VERSION 5.8 ;
BUSBITCHARS "[]" ;
DIVIDERCHAR "/" ;
UNITS
    DATABASE MICRONS 1000 ;
END UNITS

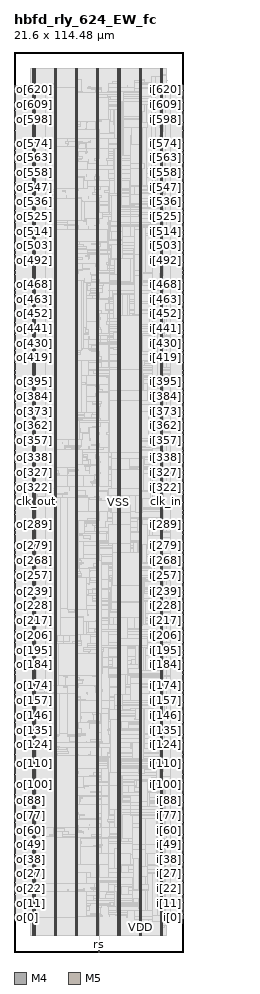
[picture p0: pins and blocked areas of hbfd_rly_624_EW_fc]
MACRO hbfd_rly_624_EW_fc
  FOREIGN hbfd_rly_624_EW_fc 0 0 ;
  CLASS BLOCK ;
  SIZE 21.6 BY 114.48 ;
  PIN clk_in
    DIRECTION INPUT ;
    USE SIGNAL ;
    PORT
      LAYER M4 ;
        RECT  21.408 57.264 21.6 57.288 ;
    END
  END clk_in
  PIN clk_out
    DIRECTION OUTPUT ;
    USE SIGNAL ;
    PORT
      LAYER M4 ;
        RECT  0 57.264 0.192 57.288 ;
    END
  END clk_out
  PIN i[0]
    DIRECTION INPUT ;
    USE SIGNAL ;
    PORT
      LAYER M4 ;
        RECT  21.408 4.32 21.6 4.344 ;
    END
  END i[0]
  PIN i[100]
    DIRECTION INPUT ;
    USE SIGNAL ;
    PORT
      LAYER M4 ;
        RECT  21.408 21.312 21.6 21.336 ;
    END
  END i[100]
  PIN i[101]
    DIRECTION INPUT ;
    USE SIGNAL ;
    PORT
      LAYER M4 ;
        RECT  21.408 21.456 21.6 21.48 ;
    END
  END i[101]
  PIN i[102]
    DIRECTION INPUT ;
    USE SIGNAL ;
    PORT
      LAYER M4 ;
        RECT  21.408 21.648 21.6 21.672 ;
    END
  END i[102]
  PIN i[103]
    DIRECTION INPUT ;
    USE SIGNAL ;
    PORT
      LAYER M4 ;
        RECT  21.408 21.792 21.6 21.816 ;
    END
  END i[103]
  PIN i[104]
    DIRECTION INPUT ;
    USE SIGNAL ;
    PORT
      LAYER M4 ;
        RECT  21.408 21.984 21.6 22.008 ;
    END
  END i[104]
  PIN i[105]
    DIRECTION INPUT ;
    USE SIGNAL ;
    PORT
      LAYER M4 ;
        RECT  21.408 22.128 21.6 22.152 ;
    END
  END i[105]
  PIN i[106]
    DIRECTION INPUT ;
    USE SIGNAL ;
    PORT
      LAYER M4 ;
        RECT  21.408 22.32 21.6 22.344 ;
    END
  END i[106]
  PIN i[107]
    DIRECTION INPUT ;
    USE SIGNAL ;
    PORT
      LAYER M4 ;
        RECT  21.408 22.464 21.6 22.488 ;
    END
  END i[107]
  PIN i[108]
    DIRECTION INPUT ;
    USE SIGNAL ;
    PORT
      LAYER M4 ;
        RECT  21.408 22.656 21.6 22.68 ;
    END
  END i[108]
  PIN i[109]
    DIRECTION INPUT ;
    USE SIGNAL ;
    PORT
      LAYER M4 ;
        RECT  21.408 22.8 21.6 22.824 ;
    END
  END i[109]
  PIN i[10]
    DIRECTION INPUT ;
    USE SIGNAL ;
    PORT
      LAYER M4 ;
        RECT  21.408 6.048 21.6 6.072 ;
    END
  END i[10]
  PIN i[110]
    DIRECTION INPUT ;
    USE SIGNAL ;
    PORT
      LAYER M4 ;
        RECT  21.408 22.992 21.6 23.016 ;
    END
  END i[110]
  PIN i[111]
    DIRECTION INPUT ;
    USE SIGNAL ;
    PORT
      LAYER M4 ;
        RECT  21.408 23.136 21.6 23.16 ;
    END
  END i[111]
  PIN i[112]
    DIRECTION INPUT ;
    USE SIGNAL ;
    PORT
      LAYER M4 ;
        RECT  21.408 23.328 21.6 23.352 ;
    END
  END i[112]
  PIN i[113]
    DIRECTION INPUT ;
    USE SIGNAL ;
    PORT
      LAYER M4 ;
        RECT  21.408 23.52 21.6 23.544 ;
    END
  END i[113]
  PIN i[114]
    DIRECTION INPUT ;
    USE SIGNAL ;
    PORT
      LAYER M4 ;
        RECT  21.408 23.664 21.6 23.688 ;
    END
  END i[114]
  PIN i[115]
    DIRECTION INPUT ;
    USE SIGNAL ;
    PORT
      LAYER M4 ;
        RECT  21.408 23.856 21.6 23.88 ;
    END
  END i[115]
  PIN i[116]
    DIRECTION INPUT ;
    USE SIGNAL ;
    PORT
      LAYER M4 ;
        RECT  21.408 24 21.6 24.024 ;
    END
  END i[116]
  PIN i[117]
    DIRECTION INPUT ;
    USE SIGNAL ;
    PORT
      LAYER M4 ;
        RECT  21.408 24.192 21.6 24.216 ;
    END
  END i[117]
  PIN i[118]
    DIRECTION INPUT ;
    USE SIGNAL ;
    PORT
      LAYER M4 ;
        RECT  21.408 24.336 21.6 24.36 ;
    END
  END i[118]
  PIN i[119]
    DIRECTION INPUT ;
    USE SIGNAL ;
    PORT
      LAYER M4 ;
        RECT  21.408 24.528 21.6 24.552 ;
    END
  END i[119]
  PIN i[11]
    DIRECTION INPUT ;
    USE SIGNAL ;
    PORT
      LAYER M4 ;
        RECT  21.408 6.192 21.6 6.216 ;
    END
  END i[11]
  PIN i[120]
    DIRECTION INPUT ;
    USE SIGNAL ;
    PORT
      LAYER M4 ;
        RECT  21.408 24.672 21.6 24.696 ;
    END
  END i[120]
  PIN i[121]
    DIRECTION INPUT ;
    USE SIGNAL ;
    PORT
      LAYER M4 ;
        RECT  21.408 24.864 21.6 24.888 ;
    END
  END i[121]
  PIN i[122]
    DIRECTION INPUT ;
    USE SIGNAL ;
    PORT
      LAYER M4 ;
        RECT  21.408 25.008 21.6 25.032 ;
    END
  END i[122]
  PIN i[123]
    DIRECTION INPUT ;
    USE SIGNAL ;
    PORT
      LAYER M4 ;
        RECT  21.408 25.2 21.6 25.224 ;
    END
  END i[123]
  PIN i[124]
    DIRECTION INPUT ;
    USE SIGNAL ;
    PORT
      LAYER M4 ;
        RECT  21.408 25.344 21.6 25.368 ;
    END
  END i[124]
  PIN i[125]
    DIRECTION INPUT ;
    USE SIGNAL ;
    PORT
      LAYER M4 ;
        RECT  21.408 25.536 21.6 25.56 ;
    END
  END i[125]
  PIN i[126]
    DIRECTION INPUT ;
    USE SIGNAL ;
    PORT
      LAYER M4 ;
        RECT  21.408 25.68 21.6 25.704 ;
    END
  END i[126]
  PIN i[127]
    DIRECTION INPUT ;
    USE SIGNAL ;
    PORT
      LAYER M4 ;
        RECT  21.408 25.872 21.6 25.896 ;
    END
  END i[127]
  PIN i[128]
    DIRECTION INPUT ;
    USE SIGNAL ;
    PORT
      LAYER M4 ;
        RECT  21.408 26.064 21.6 26.088 ;
    END
  END i[128]
  PIN i[129]
    DIRECTION INPUT ;
    USE SIGNAL ;
    PORT
      LAYER M4 ;
        RECT  21.408 26.208 21.6 26.232 ;
    END
  END i[129]
  PIN i[12]
    DIRECTION INPUT ;
    USE SIGNAL ;
    PORT
      LAYER M4 ;
        RECT  21.408 6.384 21.6 6.408 ;
    END
  END i[12]
  PIN i[130]
    DIRECTION INPUT ;
    USE SIGNAL ;
    PORT
      LAYER M4 ;
        RECT  21.408 26.4 21.6 26.424 ;
    END
  END i[130]
  PIN i[131]
    DIRECTION INPUT ;
    USE SIGNAL ;
    PORT
      LAYER M4 ;
        RECT  21.408 26.544 21.6 26.568 ;
    END
  END i[131]
  PIN i[132]
    DIRECTION INPUT ;
    USE SIGNAL ;
    PORT
      LAYER M4 ;
        RECT  21.408 26.736 21.6 26.76 ;
    END
  END i[132]
  PIN i[133]
    DIRECTION INPUT ;
    USE SIGNAL ;
    PORT
      LAYER M4 ;
        RECT  21.408 26.88 21.6 26.904 ;
    END
  END i[133]
  PIN i[134]
    DIRECTION INPUT ;
    USE SIGNAL ;
    PORT
      LAYER M4 ;
        RECT  21.408 27.072 21.6 27.096 ;
    END
  END i[134]
  PIN i[135]
    DIRECTION INPUT ;
    USE SIGNAL ;
    PORT
      LAYER M4 ;
        RECT  21.408 27.216 21.6 27.24 ;
    END
  END i[135]
  PIN i[136]
    DIRECTION INPUT ;
    USE SIGNAL ;
    PORT
      LAYER M4 ;
        RECT  21.408 27.408 21.6 27.432 ;
    END
  END i[136]
  PIN i[137]
    DIRECTION INPUT ;
    USE SIGNAL ;
    PORT
      LAYER M4 ;
        RECT  21.408 27.552 21.6 27.576 ;
    END
  END i[137]
  PIN i[138]
    DIRECTION INPUT ;
    USE SIGNAL ;
    PORT
      LAYER M4 ;
        RECT  21.408 27.744 21.6 27.768 ;
    END
  END i[138]
  PIN i[139]
    DIRECTION INPUT ;
    USE SIGNAL ;
    PORT
      LAYER M4 ;
        RECT  21.408 27.888 21.6 27.912 ;
    END
  END i[139]
  PIN i[13]
    DIRECTION INPUT ;
    USE SIGNAL ;
    PORT
      LAYER M4 ;
        RECT  21.408 6.528 21.6 6.552 ;
    END
  END i[13]
  PIN i[140]
    DIRECTION INPUT ;
    USE SIGNAL ;
    PORT
      LAYER M4 ;
        RECT  21.408 28.08 21.6 28.104 ;
    END
  END i[140]
  PIN i[141]
    DIRECTION INPUT ;
    USE SIGNAL ;
    PORT
      LAYER M4 ;
        RECT  21.408 28.224 21.6 28.248 ;
    END
  END i[141]
  PIN i[142]
    DIRECTION INPUT ;
    USE SIGNAL ;
    PORT
      LAYER M4 ;
        RECT  21.408 28.416 21.6 28.44 ;
    END
  END i[142]
  PIN i[143]
    DIRECTION INPUT ;
    USE SIGNAL ;
    PORT
      LAYER M4 ;
        RECT  21.408 28.608 21.6 28.632 ;
    END
  END i[143]
  PIN i[144]
    DIRECTION INPUT ;
    USE SIGNAL ;
    PORT
      LAYER M4 ;
        RECT  21.408 28.752 21.6 28.776 ;
    END
  END i[144]
  PIN i[145]
    DIRECTION INPUT ;
    USE SIGNAL ;
    PORT
      LAYER M4 ;
        RECT  21.408 28.944 21.6 28.968 ;
    END
  END i[145]
  PIN i[146]
    DIRECTION INPUT ;
    USE SIGNAL ;
    PORT
      LAYER M4 ;
        RECT  21.408 29.088 21.6 29.112 ;
    END
  END i[146]
  PIN i[147]
    DIRECTION INPUT ;
    USE SIGNAL ;
    PORT
      LAYER M4 ;
        RECT  21.408 29.28 21.6 29.304 ;
    END
  END i[147]
  PIN i[148]
    DIRECTION INPUT ;
    USE SIGNAL ;
    PORT
      LAYER M4 ;
        RECT  21.408 29.424 21.6 29.448 ;
    END
  END i[148]
  PIN i[149]
    DIRECTION INPUT ;
    USE SIGNAL ;
    PORT
      LAYER M4 ;
        RECT  21.408 29.616 21.6 29.64 ;
    END
  END i[149]
  PIN i[14]
    DIRECTION INPUT ;
    USE SIGNAL ;
    PORT
      LAYER M4 ;
        RECT  21.408 6.72 21.6 6.744 ;
    END
  END i[14]
  PIN i[150]
    DIRECTION INPUT ;
    USE SIGNAL ;
    PORT
      LAYER M4 ;
        RECT  21.408 29.76 21.6 29.784 ;
    END
  END i[150]
  PIN i[151]
    DIRECTION INPUT ;
    USE SIGNAL ;
    PORT
      LAYER M4 ;
        RECT  21.408 29.952 21.6 29.976 ;
    END
  END i[151]
  PIN i[152]
    DIRECTION INPUT ;
    USE SIGNAL ;
    PORT
      LAYER M4 ;
        RECT  21.408 30.096 21.6 30.12 ;
    END
  END i[152]
  PIN i[153]
    DIRECTION INPUT ;
    USE SIGNAL ;
    PORT
      LAYER M4 ;
        RECT  21.408 30.288 21.6 30.312 ;
    END
  END i[153]
  PIN i[154]
    DIRECTION INPUT ;
    USE SIGNAL ;
    PORT
      LAYER M4 ;
        RECT  21.408 30.432 21.6 30.456 ;
    END
  END i[154]
  PIN i[155]
    DIRECTION INPUT ;
    USE SIGNAL ;
    PORT
      LAYER M4 ;
        RECT  21.408 30.624 21.6 30.648 ;
    END
  END i[155]
  PIN i[156]
    DIRECTION INPUT ;
    USE SIGNAL ;
    PORT
      LAYER M4 ;
        RECT  21.408 30.768 21.6 30.792 ;
    END
  END i[156]
  PIN i[157]
    DIRECTION INPUT ;
    USE SIGNAL ;
    PORT
      LAYER M4 ;
        RECT  21.408 30.96 21.6 30.984 ;
    END
  END i[157]
  PIN i[158]
    DIRECTION INPUT ;
    USE SIGNAL ;
    PORT
      LAYER M4 ;
        RECT  21.408 31.152 21.6 31.176 ;
    END
  END i[158]
  PIN i[159]
    DIRECTION INPUT ;
    USE SIGNAL ;
    PORT
      LAYER M4 ;
        RECT  21.408 31.296 21.6 31.32 ;
    END
  END i[159]
  PIN i[15]
    DIRECTION INPUT ;
    USE SIGNAL ;
    PORT
      LAYER M4 ;
        RECT  21.408 6.864 21.6 6.888 ;
    END
  END i[15]
  PIN i[160]
    DIRECTION INPUT ;
    USE SIGNAL ;
    PORT
      LAYER M4 ;
        RECT  21.408 31.488 21.6 31.512 ;
    END
  END i[160]
  PIN i[161]
    DIRECTION INPUT ;
    USE SIGNAL ;
    PORT
      LAYER M4 ;
        RECT  21.408 31.632 21.6 31.656 ;
    END
  END i[161]
  PIN i[162]
    DIRECTION INPUT ;
    USE SIGNAL ;
    PORT
      LAYER M4 ;
        RECT  21.408 31.824 21.6 31.848 ;
    END
  END i[162]
  PIN i[163]
    DIRECTION INPUT ;
    USE SIGNAL ;
    PORT
      LAYER M4 ;
        RECT  21.408 31.968 21.6 31.992 ;
    END
  END i[163]
  PIN i[164]
    DIRECTION INPUT ;
    USE SIGNAL ;
    PORT
      LAYER M4 ;
        RECT  21.408 32.16 21.6 32.184 ;
    END
  END i[164]
  PIN i[165]
    DIRECTION INPUT ;
    USE SIGNAL ;
    PORT
      LAYER M4 ;
        RECT  21.408 32.304 21.6 32.328 ;
    END
  END i[165]
  PIN i[166]
    DIRECTION INPUT ;
    USE SIGNAL ;
    PORT
      LAYER M4 ;
        RECT  21.408 32.496 21.6 32.52 ;
    END
  END i[166]
  PIN i[167]
    DIRECTION INPUT ;
    USE SIGNAL ;
    PORT
      LAYER M4 ;
        RECT  21.408 32.64 21.6 32.664 ;
    END
  END i[167]
  PIN i[168]
    DIRECTION INPUT ;
    USE SIGNAL ;
    PORT
      LAYER M4 ;
        RECT  21.408 32.832 21.6 32.856 ;
    END
  END i[168]
  PIN i[169]
    DIRECTION INPUT ;
    USE SIGNAL ;
    PORT
      LAYER M4 ;
        RECT  21.408 32.976 21.6 33 ;
    END
  END i[169]
  PIN i[16]
    DIRECTION INPUT ;
    USE SIGNAL ;
    PORT
      LAYER M4 ;
        RECT  21.408 7.056 21.6 7.08 ;
    END
  END i[16]
  PIN i[170]
    DIRECTION INPUT ;
    USE SIGNAL ;
    PORT
      LAYER M4 ;
        RECT  21.408 33.168 21.6 33.192 ;
    END
  END i[170]
  PIN i[171]
    DIRECTION INPUT ;
    USE SIGNAL ;
    PORT
      LAYER M4 ;
        RECT  21.408 33.36 21.6 33.384 ;
    END
  END i[171]
  PIN i[172]
    DIRECTION INPUT ;
    USE SIGNAL ;
    PORT
      LAYER M4 ;
        RECT  21.408 33.504 21.6 33.528 ;
    END
  END i[172]
  PIN i[173]
    DIRECTION INPUT ;
    USE SIGNAL ;
    PORT
      LAYER M4 ;
        RECT  21.408 33.696 21.6 33.72 ;
    END
  END i[173]
  PIN i[174]
    DIRECTION INPUT ;
    USE SIGNAL ;
    PORT
      LAYER M4 ;
        RECT  21.408 33.84 21.6 33.864 ;
    END
  END i[174]
  PIN i[175]
    DIRECTION INPUT ;
    USE SIGNAL ;
    PORT
      LAYER M4 ;
        RECT  21.408 34.032 21.6 34.056 ;
    END
  END i[175]
  PIN i[176]
    DIRECTION INPUT ;
    USE SIGNAL ;
    PORT
      LAYER M4 ;
        RECT  21.408 34.176 21.6 34.2 ;
    END
  END i[176]
  PIN i[177]
    DIRECTION INPUT ;
    USE SIGNAL ;
    PORT
      LAYER M4 ;
        RECT  21.408 34.368 21.6 34.392 ;
    END
  END i[177]
  PIN i[178]
    DIRECTION INPUT ;
    USE SIGNAL ;
    PORT
      LAYER M4 ;
        RECT  21.408 34.512 21.6 34.536 ;
    END
  END i[178]
  PIN i[179]
    DIRECTION INPUT ;
    USE SIGNAL ;
    PORT
      LAYER M4 ;
        RECT  21.408 34.704 21.6 34.728 ;
    END
  END i[179]
  PIN i[17]
    DIRECTION INPUT ;
    USE SIGNAL ;
    PORT
      LAYER M4 ;
        RECT  21.408 7.2 21.6 7.224 ;
    END
  END i[17]
  PIN i[180]
    DIRECTION INPUT ;
    USE SIGNAL ;
    PORT
      LAYER M4 ;
        RECT  21.408 34.848 21.6 34.872 ;
    END
  END i[180]
  PIN i[181]
    DIRECTION INPUT ;
    USE SIGNAL ;
    PORT
      LAYER M4 ;
        RECT  21.408 35.04 21.6 35.064 ;
    END
  END i[181]
  PIN i[182]
    DIRECTION INPUT ;
    USE SIGNAL ;
    PORT
      LAYER M4 ;
        RECT  21.408 35.184 21.6 35.208 ;
    END
  END i[182]
  PIN i[183]
    DIRECTION INPUT ;
    USE SIGNAL ;
    PORT
      LAYER M4 ;
        RECT  21.408 35.376 21.6 35.4 ;
    END
  END i[183]
  PIN i[184]
    DIRECTION INPUT ;
    USE SIGNAL ;
    PORT
      LAYER M4 ;
        RECT  21.408 35.52 21.6 35.544 ;
    END
  END i[184]
  PIN i[185]
    DIRECTION INPUT ;
    USE SIGNAL ;
    PORT
      LAYER M4 ;
        RECT  21.408 35.712 21.6 35.736 ;
    END
  END i[185]
  PIN i[186]
    DIRECTION INPUT ;
    USE SIGNAL ;
    PORT
      LAYER M4 ;
        RECT  21.408 35.904 21.6 35.928 ;
    END
  END i[186]
  PIN i[187]
    DIRECTION INPUT ;
    USE SIGNAL ;
    PORT
      LAYER M4 ;
        RECT  21.408 36.048 21.6 36.072 ;
    END
  END i[187]
  PIN i[188]
    DIRECTION INPUT ;
    USE SIGNAL ;
    PORT
      LAYER M4 ;
        RECT  21.408 36.24 21.6 36.264 ;
    END
  END i[188]
  PIN i[189]
    DIRECTION INPUT ;
    USE SIGNAL ;
    PORT
      LAYER M4 ;
        RECT  21.408 36.384 21.6 36.408 ;
    END
  END i[189]
  PIN i[18]
    DIRECTION INPUT ;
    USE SIGNAL ;
    PORT
      LAYER M4 ;
        RECT  21.408 7.392 21.6 7.416 ;
    END
  END i[18]
  PIN i[190]
    DIRECTION INPUT ;
    USE SIGNAL ;
    PORT
      LAYER M4 ;
        RECT  21.408 36.576 21.6 36.6 ;
    END
  END i[190]
  PIN i[191]
    DIRECTION INPUT ;
    USE SIGNAL ;
    PORT
      LAYER M4 ;
        RECT  21.408 36.72 21.6 36.744 ;
    END
  END i[191]
  PIN i[192]
    DIRECTION INPUT ;
    USE SIGNAL ;
    PORT
      LAYER M4 ;
        RECT  21.408 36.912 21.6 36.936 ;
    END
  END i[192]
  PIN i[193]
    DIRECTION INPUT ;
    USE SIGNAL ;
    PORT
      LAYER M4 ;
        RECT  21.408 37.056 21.6 37.08 ;
    END
  END i[193]
  PIN i[194]
    DIRECTION INPUT ;
    USE SIGNAL ;
    PORT
      LAYER M4 ;
        RECT  21.408 37.248 21.6 37.272 ;
    END
  END i[194]
  PIN i[195]
    DIRECTION INPUT ;
    USE SIGNAL ;
    PORT
      LAYER M4 ;
        RECT  21.408 37.392 21.6 37.416 ;
    END
  END i[195]
  PIN i[196]
    DIRECTION INPUT ;
    USE SIGNAL ;
    PORT
      LAYER M4 ;
        RECT  21.408 37.584 21.6 37.608 ;
    END
  END i[196]
  PIN i[197]
    DIRECTION INPUT ;
    USE SIGNAL ;
    PORT
      LAYER M4 ;
        RECT  21.408 37.728 21.6 37.752 ;
    END
  END i[197]
  PIN i[198]
    DIRECTION INPUT ;
    USE SIGNAL ;
    PORT
      LAYER M4 ;
        RECT  21.408 37.92 21.6 37.944 ;
    END
  END i[198]
  PIN i[199]
    DIRECTION INPUT ;
    USE SIGNAL ;
    PORT
      LAYER M4 ;
        RECT  21.408 38.064 21.6 38.088 ;
    END
  END i[199]
  PIN i[19]
    DIRECTION INPUT ;
    USE SIGNAL ;
    PORT
      LAYER M4 ;
        RECT  21.408 7.536 21.6 7.56 ;
    END
  END i[19]
  PIN i[1]
    DIRECTION INPUT ;
    USE SIGNAL ;
    PORT
      LAYER M4 ;
        RECT  21.408 4.512 21.6 4.536 ;
    END
  END i[1]
  PIN i[200]
    DIRECTION INPUT ;
    USE SIGNAL ;
    PORT
      LAYER M4 ;
        RECT  21.408 38.256 21.6 38.28 ;
    END
  END i[200]
  PIN i[201]
    DIRECTION INPUT ;
    USE SIGNAL ;
    PORT
      LAYER M4 ;
        RECT  21.408 38.448 21.6 38.472 ;
    END
  END i[201]
  PIN i[202]
    DIRECTION INPUT ;
    USE SIGNAL ;
    PORT
      LAYER M4 ;
        RECT  21.408 38.592 21.6 38.616 ;
    END
  END i[202]
  PIN i[203]
    DIRECTION INPUT ;
    USE SIGNAL ;
    PORT
      LAYER M4 ;
        RECT  21.408 38.784 21.6 38.808 ;
    END
  END i[203]
  PIN i[204]
    DIRECTION INPUT ;
    USE SIGNAL ;
    PORT
      LAYER M4 ;
        RECT  21.408 38.928 21.6 38.952 ;
    END
  END i[204]
  PIN i[205]
    DIRECTION INPUT ;
    USE SIGNAL ;
    PORT
      LAYER M4 ;
        RECT  21.408 39.12 21.6 39.144 ;
    END
  END i[205]
  PIN i[206]
    DIRECTION INPUT ;
    USE SIGNAL ;
    PORT
      LAYER M4 ;
        RECT  21.408 39.264 21.6 39.288 ;
    END
  END i[206]
  PIN i[207]
    DIRECTION INPUT ;
    USE SIGNAL ;
    PORT
      LAYER M4 ;
        RECT  21.408 39.456 21.6 39.48 ;
    END
  END i[207]
  PIN i[208]
    DIRECTION INPUT ;
    USE SIGNAL ;
    PORT
      LAYER M4 ;
        RECT  21.408 39.6 21.6 39.624 ;
    END
  END i[208]
  PIN i[209]
    DIRECTION INPUT ;
    USE SIGNAL ;
    PORT
      LAYER M4 ;
        RECT  21.408 39.792 21.6 39.816 ;
    END
  END i[209]
  PIN i[20]
    DIRECTION INPUT ;
    USE SIGNAL ;
    PORT
      LAYER M4 ;
        RECT  21.408 7.728 21.6 7.752 ;
    END
  END i[20]
  PIN i[210]
    DIRECTION INPUT ;
    USE SIGNAL ;
    PORT
      LAYER M4 ;
        RECT  21.408 39.936 21.6 39.96 ;
    END
  END i[210]
  PIN i[211]
    DIRECTION INPUT ;
    USE SIGNAL ;
    PORT
      LAYER M4 ;
        RECT  21.408 40.128 21.6 40.152 ;
    END
  END i[211]
  PIN i[212]
    DIRECTION INPUT ;
    USE SIGNAL ;
    PORT
      LAYER M4 ;
        RECT  21.408 40.272 21.6 40.296 ;
    END
  END i[212]
  PIN i[213]
    DIRECTION INPUT ;
    USE SIGNAL ;
    PORT
      LAYER M4 ;
        RECT  21.408 40.464 21.6 40.488 ;
    END
  END i[213]
  PIN i[214]
    DIRECTION INPUT ;
    USE SIGNAL ;
    PORT
      LAYER M4 ;
        RECT  21.408 40.608 21.6 40.632 ;
    END
  END i[214]
  PIN i[215]
    DIRECTION INPUT ;
    USE SIGNAL ;
    PORT
      LAYER M4 ;
        RECT  21.408 40.8 21.6 40.824 ;
    END
  END i[215]
  PIN i[216]
    DIRECTION INPUT ;
    USE SIGNAL ;
    PORT
      LAYER M4 ;
        RECT  21.408 40.992 21.6 41.016 ;
    END
  END i[216]
  PIN i[217]
    DIRECTION INPUT ;
    USE SIGNAL ;
    PORT
      LAYER M4 ;
        RECT  21.408 41.136 21.6 41.16 ;
    END
  END i[217]
  PIN i[218]
    DIRECTION INPUT ;
    USE SIGNAL ;
    PORT
      LAYER M4 ;
        RECT  21.408 41.328 21.6 41.352 ;
    END
  END i[218]
  PIN i[219]
    DIRECTION INPUT ;
    USE SIGNAL ;
    PORT
      LAYER M4 ;
        RECT  21.408 41.472 21.6 41.496 ;
    END
  END i[219]
  PIN i[21]
    DIRECTION INPUT ;
    USE SIGNAL ;
    PORT
      LAYER M4 ;
        RECT  21.408 7.872 21.6 7.896 ;
    END
  END i[21]
  PIN i[220]
    DIRECTION INPUT ;
    USE SIGNAL ;
    PORT
      LAYER M4 ;
        RECT  21.408 41.664 21.6 41.688 ;
    END
  END i[220]
  PIN i[221]
    DIRECTION INPUT ;
    USE SIGNAL ;
    PORT
      LAYER M4 ;
        RECT  21.408 41.808 21.6 41.832 ;
    END
  END i[221]
  PIN i[222]
    DIRECTION INPUT ;
    USE SIGNAL ;
    PORT
      LAYER M4 ;
        RECT  21.408 42 21.6 42.024 ;
    END
  END i[222]
  PIN i[223]
    DIRECTION INPUT ;
    USE SIGNAL ;
    PORT
      LAYER M4 ;
        RECT  21.408 42.144 21.6 42.168 ;
    END
  END i[223]
  PIN i[224]
    DIRECTION INPUT ;
    USE SIGNAL ;
    PORT
      LAYER M4 ;
        RECT  21.408 42.336 21.6 42.36 ;
    END
  END i[224]
  PIN i[225]
    DIRECTION INPUT ;
    USE SIGNAL ;
    PORT
      LAYER M4 ;
        RECT  21.408 42.48 21.6 42.504 ;
    END
  END i[225]
  PIN i[226]
    DIRECTION INPUT ;
    USE SIGNAL ;
    PORT
      LAYER M4 ;
        RECT  21.408 42.672 21.6 42.696 ;
    END
  END i[226]
  PIN i[227]
    DIRECTION INPUT ;
    USE SIGNAL ;
    PORT
      LAYER M4 ;
        RECT  21.408 42.816 21.6 42.84 ;
    END
  END i[227]
  PIN i[228]
    DIRECTION INPUT ;
    USE SIGNAL ;
    PORT
      LAYER M4 ;
        RECT  21.408 43.008 21.6 43.032 ;
    END
  END i[228]
  PIN i[229]
    DIRECTION INPUT ;
    USE SIGNAL ;
    PORT
      LAYER M4 ;
        RECT  21.408 43.152 21.6 43.176 ;
    END
  END i[229]
  PIN i[22]
    DIRECTION INPUT ;
    USE SIGNAL ;
    PORT
      LAYER M4 ;
        RECT  21.408 8.064 21.6 8.088 ;
    END
  END i[22]
  PIN i[230]
    DIRECTION INPUT ;
    USE SIGNAL ;
    PORT
      LAYER M4 ;
        RECT  21.408 43.344 21.6 43.368 ;
    END
  END i[230]
  PIN i[231]
    DIRECTION INPUT ;
    USE SIGNAL ;
    PORT
      LAYER M4 ;
        RECT  21.408 43.536 21.6 43.56 ;
    END
  END i[231]
  PIN i[232]
    DIRECTION INPUT ;
    USE SIGNAL ;
    PORT
      LAYER M4 ;
        RECT  21.408 43.68 21.6 43.704 ;
    END
  END i[232]
  PIN i[233]
    DIRECTION INPUT ;
    USE SIGNAL ;
    PORT
      LAYER M4 ;
        RECT  21.408 43.872 21.6 43.896 ;
    END
  END i[233]
  PIN i[234]
    DIRECTION INPUT ;
    USE SIGNAL ;
    PORT
      LAYER M4 ;
        RECT  21.408 44.016 21.6 44.04 ;
    END
  END i[234]
  PIN i[235]
    DIRECTION INPUT ;
    USE SIGNAL ;
    PORT
      LAYER M4 ;
        RECT  21.408 44.208 21.6 44.232 ;
    END
  END i[235]
  PIN i[236]
    DIRECTION INPUT ;
    USE SIGNAL ;
    PORT
      LAYER M4 ;
        RECT  21.408 44.352 21.6 44.376 ;
    END
  END i[236]
  PIN i[237]
    DIRECTION INPUT ;
    USE SIGNAL ;
    PORT
      LAYER M4 ;
        RECT  21.408 44.544 21.6 44.568 ;
    END
  END i[237]
  PIN i[238]
    DIRECTION INPUT ;
    USE SIGNAL ;
    PORT
      LAYER M4 ;
        RECT  21.408 44.688 21.6 44.712 ;
    END
  END i[238]
  PIN i[239]
    DIRECTION INPUT ;
    USE SIGNAL ;
    PORT
      LAYER M4 ;
        RECT  21.408 44.88 21.6 44.904 ;
    END
  END i[239]
  PIN i[23]
    DIRECTION INPUT ;
    USE SIGNAL ;
    PORT
      LAYER M4 ;
        RECT  21.408 8.256 21.6 8.28 ;
    END
  END i[23]
  PIN i[240]
    DIRECTION INPUT ;
    USE SIGNAL ;
    PORT
      LAYER M4 ;
        RECT  21.408 45.024 21.6 45.048 ;
    END
  END i[240]
  PIN i[241]
    DIRECTION INPUT ;
    USE SIGNAL ;
    PORT
      LAYER M4 ;
        RECT  21.408 45.216 21.6 45.24 ;
    END
  END i[241]
  PIN i[242]
    DIRECTION INPUT ;
    USE SIGNAL ;
    PORT
      LAYER M4 ;
        RECT  21.408 45.36 21.6 45.384 ;
    END
  END i[242]
  PIN i[243]
    DIRECTION INPUT ;
    USE SIGNAL ;
    PORT
      LAYER M4 ;
        RECT  21.408 45.552 21.6 45.576 ;
    END
  END i[243]
  PIN i[244]
    DIRECTION INPUT ;
    USE SIGNAL ;
    PORT
      LAYER M4 ;
        RECT  21.408 45.696 21.6 45.72 ;
    END
  END i[244]
  PIN i[245]
    DIRECTION INPUT ;
    USE SIGNAL ;
    PORT
      LAYER M4 ;
        RECT  21.408 45.888 21.6 45.912 ;
    END
  END i[245]
  PIN i[246]
    DIRECTION INPUT ;
    USE SIGNAL ;
    PORT
      LAYER M4 ;
        RECT  21.408 46.08 21.6 46.104 ;
    END
  END i[246]
  PIN i[247]
    DIRECTION INPUT ;
    USE SIGNAL ;
    PORT
      LAYER M4 ;
        RECT  21.408 46.224 21.6 46.248 ;
    END
  END i[247]
  PIN i[248]
    DIRECTION INPUT ;
    USE SIGNAL ;
    PORT
      LAYER M4 ;
        RECT  21.408 46.416 21.6 46.44 ;
    END
  END i[248]
  PIN i[249]
    DIRECTION INPUT ;
    USE SIGNAL ;
    PORT
      LAYER M4 ;
        RECT  21.408 46.56 21.6 46.584 ;
    END
  END i[249]
  PIN i[24]
    DIRECTION INPUT ;
    USE SIGNAL ;
    PORT
      LAYER M4 ;
        RECT  21.408 8.4 21.6 8.424 ;
    END
  END i[24]
  PIN i[250]
    DIRECTION INPUT ;
    USE SIGNAL ;
    PORT
      LAYER M4 ;
        RECT  21.408 46.752 21.6 46.776 ;
    END
  END i[250]
  PIN i[251]
    DIRECTION INPUT ;
    USE SIGNAL ;
    PORT
      LAYER M4 ;
        RECT  21.408 46.896 21.6 46.92 ;
    END
  END i[251]
  PIN i[252]
    DIRECTION INPUT ;
    USE SIGNAL ;
    PORT
      LAYER M4 ;
        RECT  21.408 47.088 21.6 47.112 ;
    END
  END i[252]
  PIN i[253]
    DIRECTION INPUT ;
    USE SIGNAL ;
    PORT
      LAYER M4 ;
        RECT  21.408 47.232 21.6 47.256 ;
    END
  END i[253]
  PIN i[254]
    DIRECTION INPUT ;
    USE SIGNAL ;
    PORT
      LAYER M4 ;
        RECT  21.408 47.424 21.6 47.448 ;
    END
  END i[254]
  PIN i[255]
    DIRECTION INPUT ;
    USE SIGNAL ;
    PORT
      LAYER M4 ;
        RECT  21.408 47.568 21.6 47.592 ;
    END
  END i[255]
  PIN i[256]
    DIRECTION INPUT ;
    USE SIGNAL ;
    PORT
      LAYER M4 ;
        RECT  21.408 47.76 21.6 47.784 ;
    END
  END i[256]
  PIN i[257]
    DIRECTION INPUT ;
    USE SIGNAL ;
    PORT
      LAYER M4 ;
        RECT  21.408 47.904 21.6 47.928 ;
    END
  END i[257]
  PIN i[258]
    DIRECTION INPUT ;
    USE SIGNAL ;
    PORT
      LAYER M4 ;
        RECT  21.408 48.096 21.6 48.12 ;
    END
  END i[258]
  PIN i[259]
    DIRECTION INPUT ;
    USE SIGNAL ;
    PORT
      LAYER M4 ;
        RECT  21.408 48.24 21.6 48.264 ;
    END
  END i[259]
  PIN i[25]
    DIRECTION INPUT ;
    USE SIGNAL ;
    PORT
      LAYER M4 ;
        RECT  21.408 8.592 21.6 8.616 ;
    END
  END i[25]
  PIN i[260]
    DIRECTION INPUT ;
    USE SIGNAL ;
    PORT
      LAYER M4 ;
        RECT  21.408 48.432 21.6 48.456 ;
    END
  END i[260]
  PIN i[261]
    DIRECTION INPUT ;
    USE SIGNAL ;
    PORT
      LAYER M4 ;
        RECT  21.408 48.624 21.6 48.648 ;
    END
  END i[261]
  PIN i[262]
    DIRECTION INPUT ;
    USE SIGNAL ;
    PORT
      LAYER M4 ;
        RECT  21.408 48.768 21.6 48.792 ;
    END
  END i[262]
  PIN i[263]
    DIRECTION INPUT ;
    USE SIGNAL ;
    PORT
      LAYER M4 ;
        RECT  21.408 48.96 21.6 48.984 ;
    END
  END i[263]
  PIN i[264]
    DIRECTION INPUT ;
    USE SIGNAL ;
    PORT
      LAYER M4 ;
        RECT  21.408 49.104 21.6 49.128 ;
    END
  END i[264]
  PIN i[265]
    DIRECTION INPUT ;
    USE SIGNAL ;
    PORT
      LAYER M4 ;
        RECT  21.408 49.296 21.6 49.32 ;
    END
  END i[265]
  PIN i[266]
    DIRECTION INPUT ;
    USE SIGNAL ;
    PORT
      LAYER M4 ;
        RECT  21.408 49.44 21.6 49.464 ;
    END
  END i[266]
  PIN i[267]
    DIRECTION INPUT ;
    USE SIGNAL ;
    PORT
      LAYER M4 ;
        RECT  21.408 49.632 21.6 49.656 ;
    END
  END i[267]
  PIN i[268]
    DIRECTION INPUT ;
    USE SIGNAL ;
    PORT
      LAYER M4 ;
        RECT  21.408 49.776 21.6 49.8 ;
    END
  END i[268]
  PIN i[269]
    DIRECTION INPUT ;
    USE SIGNAL ;
    PORT
      LAYER M4 ;
        RECT  21.408 49.968 21.6 49.992 ;
    END
  END i[269]
  PIN i[26]
    DIRECTION INPUT ;
    USE SIGNAL ;
    PORT
      LAYER M4 ;
        RECT  21.408 8.736 21.6 8.76 ;
    END
  END i[26]
  PIN i[270]
    DIRECTION INPUT ;
    USE SIGNAL ;
    PORT
      LAYER M4 ;
        RECT  21.408 50.112 21.6 50.136 ;
    END
  END i[270]
  PIN i[271]
    DIRECTION INPUT ;
    USE SIGNAL ;
    PORT
      LAYER M4 ;
        RECT  21.408 50.304 21.6 50.328 ;
    END
  END i[271]
  PIN i[272]
    DIRECTION INPUT ;
    USE SIGNAL ;
    PORT
      LAYER M4 ;
        RECT  21.408 50.448 21.6 50.472 ;
    END
  END i[272]
  PIN i[273]
    DIRECTION INPUT ;
    USE SIGNAL ;
    PORT
      LAYER M4 ;
        RECT  21.408 50.64 21.6 50.664 ;
    END
  END i[273]
  PIN i[274]
    DIRECTION INPUT ;
    USE SIGNAL ;
    PORT
      LAYER M4 ;
        RECT  21.408 50.784 21.6 50.808 ;
    END
  END i[274]
  PIN i[275]
    DIRECTION INPUT ;
    USE SIGNAL ;
    PORT
      LAYER M4 ;
        RECT  21.408 50.976 21.6 51 ;
    END
  END i[275]
  PIN i[276]
    DIRECTION INPUT ;
    USE SIGNAL ;
    PORT
      LAYER M4 ;
        RECT  21.408 51.168 21.6 51.192 ;
    END
  END i[276]
  PIN i[277]
    DIRECTION INPUT ;
    USE SIGNAL ;
    PORT
      LAYER M4 ;
        RECT  21.408 51.312 21.6 51.336 ;
    END
  END i[277]
  PIN i[278]
    DIRECTION INPUT ;
    USE SIGNAL ;
    PORT
      LAYER M4 ;
        RECT  21.408 51.504 21.6 51.528 ;
    END
  END i[278]
  PIN i[279]
    DIRECTION INPUT ;
    USE SIGNAL ;
    PORT
      LAYER M4 ;
        RECT  21.408 51.648 21.6 51.672 ;
    END
  END i[279]
  PIN i[27]
    DIRECTION INPUT ;
    USE SIGNAL ;
    PORT
      LAYER M4 ;
        RECT  21.408 8.928 21.6 8.952 ;
    END
  END i[27]
  PIN i[280]
    DIRECTION INPUT ;
    USE SIGNAL ;
    PORT
      LAYER M4 ;
        RECT  21.408 51.84 21.6 51.864 ;
    END
  END i[280]
  PIN i[281]
    DIRECTION INPUT ;
    USE SIGNAL ;
    PORT
      LAYER M4 ;
        RECT  21.408 51.984 21.6 52.008 ;
    END
  END i[281]
  PIN i[282]
    DIRECTION INPUT ;
    USE SIGNAL ;
    PORT
      LAYER M4 ;
        RECT  21.408 52.176 21.6 52.2 ;
    END
  END i[282]
  PIN i[283]
    DIRECTION INPUT ;
    USE SIGNAL ;
    PORT
      LAYER M4 ;
        RECT  21.408 52.32 21.6 52.344 ;
    END
  END i[283]
  PIN i[284]
    DIRECTION INPUT ;
    USE SIGNAL ;
    PORT
      LAYER M4 ;
        RECT  21.408 52.512 21.6 52.536 ;
    END
  END i[284]
  PIN i[285]
    DIRECTION INPUT ;
    USE SIGNAL ;
    PORT
      LAYER M4 ;
        RECT  21.408 52.656 21.6 52.68 ;
    END
  END i[285]
  PIN i[286]
    DIRECTION INPUT ;
    USE SIGNAL ;
    PORT
      LAYER M4 ;
        RECT  21.408 52.848 21.6 52.872 ;
    END
  END i[286]
  PIN i[287]
    DIRECTION INPUT ;
    USE SIGNAL ;
    PORT
      LAYER M4 ;
        RECT  21.408 52.992 21.6 53.016 ;
    END
  END i[287]
  PIN i[288]
    DIRECTION INPUT ;
    USE SIGNAL ;
    PORT
      LAYER M4 ;
        RECT  21.408 53.184 21.6 53.208 ;
    END
  END i[288]
  PIN i[289]
    DIRECTION INPUT ;
    USE SIGNAL ;
    PORT
      LAYER M4 ;
        RECT  21.408 53.328 21.6 53.352 ;
    END
  END i[289]
  PIN i[28]
    DIRECTION INPUT ;
    USE SIGNAL ;
    PORT
      LAYER M4 ;
        RECT  21.408 9.072 21.6 9.096 ;
    END
  END i[28]
  PIN i[290]
    DIRECTION INPUT ;
    USE SIGNAL ;
    PORT
      LAYER M4 ;
        RECT  21.408 53.52 21.6 53.544 ;
    END
  END i[290]
  PIN i[291]
    DIRECTION INPUT ;
    USE SIGNAL ;
    PORT
      LAYER M4 ;
        RECT  21.408 53.712 21.6 53.736 ;
    END
  END i[291]
  PIN i[292]
    DIRECTION INPUT ;
    USE SIGNAL ;
    PORT
      LAYER M4 ;
        RECT  21.408 53.856 21.6 53.88 ;
    END
  END i[292]
  PIN i[293]
    DIRECTION INPUT ;
    USE SIGNAL ;
    PORT
      LAYER M4 ;
        RECT  21.408 54.048 21.6 54.072 ;
    END
  END i[293]
  PIN i[294]
    DIRECTION INPUT ;
    USE SIGNAL ;
    PORT
      LAYER M4 ;
        RECT  21.408 54.192 21.6 54.216 ;
    END
  END i[294]
  PIN i[295]
    DIRECTION INPUT ;
    USE SIGNAL ;
    PORT
      LAYER M4 ;
        RECT  21.408 54.384 21.6 54.408 ;
    END
  END i[295]
  PIN i[296]
    DIRECTION INPUT ;
    USE SIGNAL ;
    PORT
      LAYER M4 ;
        RECT  21.408 54.528 21.6 54.552 ;
    END
  END i[296]
  PIN i[297]
    DIRECTION INPUT ;
    USE SIGNAL ;
    PORT
      LAYER M4 ;
        RECT  21.408 54.72 21.6 54.744 ;
    END
  END i[297]
  PIN i[298]
    DIRECTION INPUT ;
    USE SIGNAL ;
    PORT
      LAYER M4 ;
        RECT  21.408 54.864 21.6 54.888 ;
    END
  END i[298]
  PIN i[299]
    DIRECTION INPUT ;
    USE SIGNAL ;
    PORT
      LAYER M4 ;
        RECT  21.408 55.056 21.6 55.08 ;
    END
  END i[299]
  PIN i[29]
    DIRECTION INPUT ;
    USE SIGNAL ;
    PORT
      LAYER M4 ;
        RECT  21.408 9.264 21.6 9.288 ;
    END
  END i[29]
  PIN i[2]
    DIRECTION INPUT ;
    USE SIGNAL ;
    PORT
      LAYER M4 ;
        RECT  21.408 4.656 21.6 4.68 ;
    END
  END i[2]
  PIN i[300]
    DIRECTION INPUT ;
    USE SIGNAL ;
    PORT
      LAYER M4 ;
        RECT  21.408 55.2 21.6 55.224 ;
    END
  END i[300]
  PIN i[301]
    DIRECTION INPUT ;
    USE SIGNAL ;
    PORT
      LAYER M4 ;
        RECT  21.408 55.392 21.6 55.416 ;
    END
  END i[301]
  PIN i[302]
    DIRECTION INPUT ;
    USE SIGNAL ;
    PORT
      LAYER M4 ;
        RECT  21.408 55.536 21.6 55.56 ;
    END
  END i[302]
  PIN i[303]
    DIRECTION INPUT ;
    USE SIGNAL ;
    PORT
      LAYER M4 ;
        RECT  21.408 55.728 21.6 55.752 ;
    END
  END i[303]
  PIN i[304]
    DIRECTION INPUT ;
    USE SIGNAL ;
    PORT
      LAYER M4 ;
        RECT  21.408 55.872 21.6 55.896 ;
    END
  END i[304]
  PIN i[305]
    DIRECTION INPUT ;
    USE SIGNAL ;
    PORT
      LAYER M4 ;
        RECT  21.408 56.064 21.6 56.088 ;
    END
  END i[305]
  PIN i[306]
    DIRECTION INPUT ;
    USE SIGNAL ;
    PORT
      LAYER M4 ;
        RECT  21.408 56.256 21.6 56.28 ;
    END
  END i[306]
  PIN i[307]
    DIRECTION INPUT ;
    USE SIGNAL ;
    PORT
      LAYER M4 ;
        RECT  21.408 56.4 21.6 56.424 ;
    END
  END i[307]
  PIN i[308]
    DIRECTION INPUT ;
    USE SIGNAL ;
    PORT
      LAYER M4 ;
        RECT  21.408 56.592 21.6 56.616 ;
    END
  END i[308]
  PIN i[309]
    DIRECTION INPUT ;
    USE SIGNAL ;
    PORT
      LAYER M4 ;
        RECT  21.408 56.736 21.6 56.76 ;
    END
  END i[309]
  PIN i[30]
    DIRECTION INPUT ;
    USE SIGNAL ;
    PORT
      LAYER M4 ;
        RECT  21.408 9.408 21.6 9.432 ;
    END
  END i[30]
  PIN i[310]
    DIRECTION INPUT ;
    USE SIGNAL ;
    PORT
      LAYER M4 ;
        RECT  21.408 56.928 21.6 56.952 ;
    END
  END i[310]
  PIN i[311]
    DIRECTION INPUT ;
    USE SIGNAL ;
    PORT
      LAYER M4 ;
        RECT  21.408 57.072 21.6 57.096 ;
    END
  END i[311]
  PIN i[312]
    DIRECTION INPUT ;
    USE SIGNAL ;
    PORT
      LAYER M4 ;
        RECT  21.408 57.408 21.6 57.432 ;
    END
  END i[312]
  PIN i[313]
    DIRECTION INPUT ;
    USE SIGNAL ;
    PORT
      LAYER M4 ;
        RECT  21.408 57.6 21.6 57.624 ;
    END
  END i[313]
  PIN i[314]
    DIRECTION INPUT ;
    USE SIGNAL ;
    PORT
      LAYER M4 ;
        RECT  21.408 57.744 21.6 57.768 ;
    END
  END i[314]
  PIN i[315]
    DIRECTION INPUT ;
    USE SIGNAL ;
    PORT
      LAYER M4 ;
        RECT  21.408 57.936 21.6 57.96 ;
    END
  END i[315]
  PIN i[316]
    DIRECTION INPUT ;
    USE SIGNAL ;
    PORT
      LAYER M4 ;
        RECT  21.408 58.08 21.6 58.104 ;
    END
  END i[316]
  PIN i[317]
    DIRECTION INPUT ;
    USE SIGNAL ;
    PORT
      LAYER M4 ;
        RECT  21.408 58.272 21.6 58.296 ;
    END
  END i[317]
  PIN i[318]
    DIRECTION INPUT ;
    USE SIGNAL ;
    PORT
      LAYER M4 ;
        RECT  21.408 58.416 21.6 58.44 ;
    END
  END i[318]
  PIN i[319]
    DIRECTION INPUT ;
    USE SIGNAL ;
    PORT
      LAYER M4 ;
        RECT  21.408 58.608 21.6 58.632 ;
    END
  END i[319]
  PIN i[31]
    DIRECTION INPUT ;
    USE SIGNAL ;
    PORT
      LAYER M4 ;
        RECT  21.408 9.6 21.6 9.624 ;
    END
  END i[31]
  PIN i[320]
    DIRECTION INPUT ;
    USE SIGNAL ;
    PORT
      LAYER M4 ;
        RECT  21.408 58.8 21.6 58.824 ;
    END
  END i[320]
  PIN i[321]
    DIRECTION INPUT ;
    USE SIGNAL ;
    PORT
      LAYER M4 ;
        RECT  21.408 58.944 21.6 58.968 ;
    END
  END i[321]
  PIN i[322]
    DIRECTION INPUT ;
    USE SIGNAL ;
    PORT
      LAYER M4 ;
        RECT  21.408 59.136 21.6 59.16 ;
    END
  END i[322]
  PIN i[323]
    DIRECTION INPUT ;
    USE SIGNAL ;
    PORT
      LAYER M4 ;
        RECT  21.408 59.28 21.6 59.304 ;
    END
  END i[323]
  PIN i[324]
    DIRECTION INPUT ;
    USE SIGNAL ;
    PORT
      LAYER M4 ;
        RECT  21.408 59.472 21.6 59.496 ;
    END
  END i[324]
  PIN i[325]
    DIRECTION INPUT ;
    USE SIGNAL ;
    PORT
      LAYER M4 ;
        RECT  21.408 59.616 21.6 59.64 ;
    END
  END i[325]
  PIN i[326]
    DIRECTION INPUT ;
    USE SIGNAL ;
    PORT
      LAYER M4 ;
        RECT  21.408 59.808 21.6 59.832 ;
    END
  END i[326]
  PIN i[327]
    DIRECTION INPUT ;
    USE SIGNAL ;
    PORT
      LAYER M4 ;
        RECT  21.408 59.952 21.6 59.976 ;
    END
  END i[327]
  PIN i[328]
    DIRECTION INPUT ;
    USE SIGNAL ;
    PORT
      LAYER M4 ;
        RECT  21.408 60.144 21.6 60.168 ;
    END
  END i[328]
  PIN i[329]
    DIRECTION INPUT ;
    USE SIGNAL ;
    PORT
      LAYER M4 ;
        RECT  21.408 60.288 21.6 60.312 ;
    END
  END i[329]
  PIN i[32]
    DIRECTION INPUT ;
    USE SIGNAL ;
    PORT
      LAYER M4 ;
        RECT  21.408 9.744 21.6 9.768 ;
    END
  END i[32]
  PIN i[330]
    DIRECTION INPUT ;
    USE SIGNAL ;
    PORT
      LAYER M4 ;
        RECT  21.408 60.48 21.6 60.504 ;
    END
  END i[330]
  PIN i[331]
    DIRECTION INPUT ;
    USE SIGNAL ;
    PORT
      LAYER M4 ;
        RECT  21.408 60.624 21.6 60.648 ;
    END
  END i[331]
  PIN i[332]
    DIRECTION INPUT ;
    USE SIGNAL ;
    PORT
      LAYER M4 ;
        RECT  21.408 60.816 21.6 60.84 ;
    END
  END i[332]
  PIN i[333]
    DIRECTION INPUT ;
    USE SIGNAL ;
    PORT
      LAYER M4 ;
        RECT  21.408 60.96 21.6 60.984 ;
    END
  END i[333]
  PIN i[334]
    DIRECTION INPUT ;
    USE SIGNAL ;
    PORT
      LAYER M4 ;
        RECT  21.408 61.152 21.6 61.176 ;
    END
  END i[334]
  PIN i[335]
    DIRECTION INPUT ;
    USE SIGNAL ;
    PORT
      LAYER M4 ;
        RECT  21.408 61.344 21.6 61.368 ;
    END
  END i[335]
  PIN i[336]
    DIRECTION INPUT ;
    USE SIGNAL ;
    PORT
      LAYER M4 ;
        RECT  21.408 61.488 21.6 61.512 ;
    END
  END i[336]
  PIN i[337]
    DIRECTION INPUT ;
    USE SIGNAL ;
    PORT
      LAYER M4 ;
        RECT  21.408 61.68 21.6 61.704 ;
    END
  END i[337]
  PIN i[338]
    DIRECTION INPUT ;
    USE SIGNAL ;
    PORT
      LAYER M4 ;
        RECT  21.408 61.824 21.6 61.848 ;
    END
  END i[338]
  PIN i[339]
    DIRECTION INPUT ;
    USE SIGNAL ;
    PORT
      LAYER M4 ;
        RECT  21.408 62.016 21.6 62.04 ;
    END
  END i[339]
  PIN i[33]
    DIRECTION INPUT ;
    USE SIGNAL ;
    PORT
      LAYER M4 ;
        RECT  21.408 9.936 21.6 9.96 ;
    END
  END i[33]
  PIN i[340]
    DIRECTION INPUT ;
    USE SIGNAL ;
    PORT
      LAYER M4 ;
        RECT  21.408 62.16 21.6 62.184 ;
    END
  END i[340]
  PIN i[341]
    DIRECTION INPUT ;
    USE SIGNAL ;
    PORT
      LAYER M4 ;
        RECT  21.408 62.352 21.6 62.376 ;
    END
  END i[341]
  PIN i[342]
    DIRECTION INPUT ;
    USE SIGNAL ;
    PORT
      LAYER M4 ;
        RECT  21.408 62.496 21.6 62.52 ;
    END
  END i[342]
  PIN i[343]
    DIRECTION INPUT ;
    USE SIGNAL ;
    PORT
      LAYER M4 ;
        RECT  21.408 62.688 21.6 62.712 ;
    END
  END i[343]
  PIN i[344]
    DIRECTION INPUT ;
    USE SIGNAL ;
    PORT
      LAYER M4 ;
        RECT  21.408 62.832 21.6 62.856 ;
    END
  END i[344]
  PIN i[345]
    DIRECTION INPUT ;
    USE SIGNAL ;
    PORT
      LAYER M4 ;
        RECT  21.408 63.024 21.6 63.048 ;
    END
  END i[345]
  PIN i[346]
    DIRECTION INPUT ;
    USE SIGNAL ;
    PORT
      LAYER M4 ;
        RECT  21.408 63.168 21.6 63.192 ;
    END
  END i[346]
  PIN i[347]
    DIRECTION INPUT ;
    USE SIGNAL ;
    PORT
      LAYER M4 ;
        RECT  21.408 63.36 21.6 63.384 ;
    END
  END i[347]
  PIN i[348]
    DIRECTION INPUT ;
    USE SIGNAL ;
    PORT
      LAYER M4 ;
        RECT  21.408 63.504 21.6 63.528 ;
    END
  END i[348]
  PIN i[349]
    DIRECTION INPUT ;
    USE SIGNAL ;
    PORT
      LAYER M4 ;
        RECT  21.408 63.696 21.6 63.72 ;
    END
  END i[349]
  PIN i[34]
    DIRECTION INPUT ;
    USE SIGNAL ;
    PORT
      LAYER M4 ;
        RECT  21.408 10.08 21.6 10.104 ;
    END
  END i[34]
  PIN i[350]
    DIRECTION INPUT ;
    USE SIGNAL ;
    PORT
      LAYER M4 ;
        RECT  21.408 63.888 21.6 63.912 ;
    END
  END i[350]
  PIN i[351]
    DIRECTION INPUT ;
    USE SIGNAL ;
    PORT
      LAYER M4 ;
        RECT  21.408 64.032 21.6 64.056 ;
    END
  END i[351]
  PIN i[352]
    DIRECTION INPUT ;
    USE SIGNAL ;
    PORT
      LAYER M4 ;
        RECT  21.408 64.224 21.6 64.248 ;
    END
  END i[352]
  PIN i[353]
    DIRECTION INPUT ;
    USE SIGNAL ;
    PORT
      LAYER M4 ;
        RECT  21.408 64.368 21.6 64.392 ;
    END
  END i[353]
  PIN i[354]
    DIRECTION INPUT ;
    USE SIGNAL ;
    PORT
      LAYER M4 ;
        RECT  21.408 64.56 21.6 64.584 ;
    END
  END i[354]
  PIN i[355]
    DIRECTION INPUT ;
    USE SIGNAL ;
    PORT
      LAYER M4 ;
        RECT  21.408 64.704 21.6 64.728 ;
    END
  END i[355]
  PIN i[356]
    DIRECTION INPUT ;
    USE SIGNAL ;
    PORT
      LAYER M4 ;
        RECT  21.408 64.896 21.6 64.92 ;
    END
  END i[356]
  PIN i[357]
    DIRECTION INPUT ;
    USE SIGNAL ;
    PORT
      LAYER M4 ;
        RECT  21.408 65.04 21.6 65.064 ;
    END
  END i[357]
  PIN i[358]
    DIRECTION INPUT ;
    USE SIGNAL ;
    PORT
      LAYER M4 ;
        RECT  21.408 65.232 21.6 65.256 ;
    END
  END i[358]
  PIN i[359]
    DIRECTION INPUT ;
    USE SIGNAL ;
    PORT
      LAYER M4 ;
        RECT  21.408 65.376 21.6 65.4 ;
    END
  END i[359]
  PIN i[35]
    DIRECTION INPUT ;
    USE SIGNAL ;
    PORT
      LAYER M4 ;
        RECT  21.408 10.272 21.6 10.296 ;
    END
  END i[35]
  PIN i[360]
    DIRECTION INPUT ;
    USE SIGNAL ;
    PORT
      LAYER M4 ;
        RECT  21.408 65.568 21.6 65.592 ;
    END
  END i[360]
  PIN i[361]
    DIRECTION INPUT ;
    USE SIGNAL ;
    PORT
      LAYER M4 ;
        RECT  21.408 65.712 21.6 65.736 ;
    END
  END i[361]
  PIN i[362]
    DIRECTION INPUT ;
    USE SIGNAL ;
    PORT
      LAYER M4 ;
        RECT  21.408 65.904 21.6 65.928 ;
    END
  END i[362]
  PIN i[363]
    DIRECTION INPUT ;
    USE SIGNAL ;
    PORT
      LAYER M4 ;
        RECT  21.408 66.096 21.6 66.12 ;
    END
  END i[363]
  PIN i[364]
    DIRECTION INPUT ;
    USE SIGNAL ;
    PORT
      LAYER M4 ;
        RECT  21.408 66.24 21.6 66.264 ;
    END
  END i[364]
  PIN i[365]
    DIRECTION INPUT ;
    USE SIGNAL ;
    PORT
      LAYER M4 ;
        RECT  21.408 66.432 21.6 66.456 ;
    END
  END i[365]
  PIN i[366]
    DIRECTION INPUT ;
    USE SIGNAL ;
    PORT
      LAYER M4 ;
        RECT  21.408 66.576 21.6 66.6 ;
    END
  END i[366]
  PIN i[367]
    DIRECTION INPUT ;
    USE SIGNAL ;
    PORT
      LAYER M4 ;
        RECT  21.408 66.768 21.6 66.792 ;
    END
  END i[367]
  PIN i[368]
    DIRECTION INPUT ;
    USE SIGNAL ;
    PORT
      LAYER M4 ;
        RECT  21.408 66.912 21.6 66.936 ;
    END
  END i[368]
  PIN i[369]
    DIRECTION INPUT ;
    USE SIGNAL ;
    PORT
      LAYER M4 ;
        RECT  21.408 67.104 21.6 67.128 ;
    END
  END i[369]
  PIN i[36]
    DIRECTION INPUT ;
    USE SIGNAL ;
    PORT
      LAYER M4 ;
        RECT  21.408 10.416 21.6 10.44 ;
    END
  END i[36]
  PIN i[370]
    DIRECTION INPUT ;
    USE SIGNAL ;
    PORT
      LAYER M4 ;
        RECT  21.408 67.248 21.6 67.272 ;
    END
  END i[370]
  PIN i[371]
    DIRECTION INPUT ;
    USE SIGNAL ;
    PORT
      LAYER M4 ;
        RECT  21.408 67.44 21.6 67.464 ;
    END
  END i[371]
  PIN i[372]
    DIRECTION INPUT ;
    USE SIGNAL ;
    PORT
      LAYER M4 ;
        RECT  21.408 67.584 21.6 67.608 ;
    END
  END i[372]
  PIN i[373]
    DIRECTION INPUT ;
    USE SIGNAL ;
    PORT
      LAYER M4 ;
        RECT  21.408 67.776 21.6 67.8 ;
    END
  END i[373]
  PIN i[374]
    DIRECTION INPUT ;
    USE SIGNAL ;
    PORT
      LAYER M4 ;
        RECT  21.408 67.92 21.6 67.944 ;
    END
  END i[374]
  PIN i[375]
    DIRECTION INPUT ;
    USE SIGNAL ;
    PORT
      LAYER M4 ;
        RECT  21.408 68.112 21.6 68.136 ;
    END
  END i[375]
  PIN i[376]
    DIRECTION INPUT ;
    USE SIGNAL ;
    PORT
      LAYER M4 ;
        RECT  21.408 68.256 21.6 68.28 ;
    END
  END i[376]
  PIN i[377]
    DIRECTION INPUT ;
    USE SIGNAL ;
    PORT
      LAYER M4 ;
        RECT  21.408 68.448 21.6 68.472 ;
    END
  END i[377]
  PIN i[378]
    DIRECTION INPUT ;
    USE SIGNAL ;
    PORT
      LAYER M4 ;
        RECT  21.408 68.64 21.6 68.664 ;
    END
  END i[378]
  PIN i[379]
    DIRECTION INPUT ;
    USE SIGNAL ;
    PORT
      LAYER M4 ;
        RECT  21.408 68.784 21.6 68.808 ;
    END
  END i[379]
  PIN i[37]
    DIRECTION INPUT ;
    USE SIGNAL ;
    PORT
      LAYER M4 ;
        RECT  21.408 10.608 21.6 10.632 ;
    END
  END i[37]
  PIN i[380]
    DIRECTION INPUT ;
    USE SIGNAL ;
    PORT
      LAYER M4 ;
        RECT  21.408 68.976 21.6 69 ;
    END
  END i[380]
  PIN i[381]
    DIRECTION INPUT ;
    USE SIGNAL ;
    PORT
      LAYER M4 ;
        RECT  21.408 69.12 21.6 69.144 ;
    END
  END i[381]
  PIN i[382]
    DIRECTION INPUT ;
    USE SIGNAL ;
    PORT
      LAYER M4 ;
        RECT  21.408 69.312 21.6 69.336 ;
    END
  END i[382]
  PIN i[383]
    DIRECTION INPUT ;
    USE SIGNAL ;
    PORT
      LAYER M4 ;
        RECT  21.408 69.456 21.6 69.48 ;
    END
  END i[383]
  PIN i[384]
    DIRECTION INPUT ;
    USE SIGNAL ;
    PORT
      LAYER M4 ;
        RECT  21.408 69.648 21.6 69.672 ;
    END
  END i[384]
  PIN i[385]
    DIRECTION INPUT ;
    USE SIGNAL ;
    PORT
      LAYER M4 ;
        RECT  21.408 69.792 21.6 69.816 ;
    END
  END i[385]
  PIN i[386]
    DIRECTION INPUT ;
    USE SIGNAL ;
    PORT
      LAYER M4 ;
        RECT  21.408 69.984 21.6 70.008 ;
    END
  END i[386]
  PIN i[387]
    DIRECTION INPUT ;
    USE SIGNAL ;
    PORT
      LAYER M4 ;
        RECT  21.408 70.128 21.6 70.152 ;
    END
  END i[387]
  PIN i[388]
    DIRECTION INPUT ;
    USE SIGNAL ;
    PORT
      LAYER M4 ;
        RECT  21.408 70.32 21.6 70.344 ;
    END
  END i[388]
  PIN i[389]
    DIRECTION INPUT ;
    USE SIGNAL ;
    PORT
      LAYER M4 ;
        RECT  21.408 70.464 21.6 70.488 ;
    END
  END i[389]
  PIN i[38]
    DIRECTION INPUT ;
    USE SIGNAL ;
    PORT
      LAYER M4 ;
        RECT  21.408 10.8 21.6 10.824 ;
    END
  END i[38]
  PIN i[390]
    DIRECTION INPUT ;
    USE SIGNAL ;
    PORT
      LAYER M4 ;
        RECT  21.408 70.656 21.6 70.68 ;
    END
  END i[390]
  PIN i[391]
    DIRECTION INPUT ;
    USE SIGNAL ;
    PORT
      LAYER M4 ;
        RECT  21.408 70.8 21.6 70.824 ;
    END
  END i[391]
  PIN i[392]
    DIRECTION INPUT ;
    USE SIGNAL ;
    PORT
      LAYER M4 ;
        RECT  21.408 70.992 21.6 71.016 ;
    END
  END i[392]
  PIN i[393]
    DIRECTION INPUT ;
    USE SIGNAL ;
    PORT
      LAYER M4 ;
        RECT  21.408 71.184 21.6 71.208 ;
    END
  END i[393]
  PIN i[394]
    DIRECTION INPUT ;
    USE SIGNAL ;
    PORT
      LAYER M4 ;
        RECT  21.408 71.328 21.6 71.352 ;
    END
  END i[394]
  PIN i[395]
    DIRECTION INPUT ;
    USE SIGNAL ;
    PORT
      LAYER M4 ;
        RECT  21.408 71.52 21.6 71.544 ;
    END
  END i[395]
  PIN i[396]
    DIRECTION INPUT ;
    USE SIGNAL ;
    PORT
      LAYER M4 ;
        RECT  21.408 71.664 21.6 71.688 ;
    END
  END i[396]
  PIN i[397]
    DIRECTION INPUT ;
    USE SIGNAL ;
    PORT
      LAYER M4 ;
        RECT  21.408 71.856 21.6 71.88 ;
    END
  END i[397]
  PIN i[398]
    DIRECTION INPUT ;
    USE SIGNAL ;
    PORT
      LAYER M4 ;
        RECT  21.408 72 21.6 72.024 ;
    END
  END i[398]
  PIN i[399]
    DIRECTION INPUT ;
    USE SIGNAL ;
    PORT
      LAYER M4 ;
        RECT  21.408 72.192 21.6 72.216 ;
    END
  END i[399]
  PIN i[39]
    DIRECTION INPUT ;
    USE SIGNAL ;
    PORT
      LAYER M4 ;
        RECT  21.408 10.944 21.6 10.968 ;
    END
  END i[39]
  PIN i[3]
    DIRECTION INPUT ;
    USE SIGNAL ;
    PORT
      LAYER M4 ;
        RECT  21.408 4.848 21.6 4.872 ;
    END
  END i[3]
  PIN i[400]
    DIRECTION INPUT ;
    USE SIGNAL ;
    PORT
      LAYER M4 ;
        RECT  21.408 72.336 21.6 72.36 ;
    END
  END i[400]
  PIN i[401]
    DIRECTION INPUT ;
    USE SIGNAL ;
    PORT
      LAYER M4 ;
        RECT  21.408 72.528 21.6 72.552 ;
    END
  END i[401]
  PIN i[402]
    DIRECTION INPUT ;
    USE SIGNAL ;
    PORT
      LAYER M4 ;
        RECT  21.408 72.672 21.6 72.696 ;
    END
  END i[402]
  PIN i[403]
    DIRECTION INPUT ;
    USE SIGNAL ;
    PORT
      LAYER M4 ;
        RECT  21.408 72.864 21.6 72.888 ;
    END
  END i[403]
  PIN i[404]
    DIRECTION INPUT ;
    USE SIGNAL ;
    PORT
      LAYER M4 ;
        RECT  21.408 73.008 21.6 73.032 ;
    END
  END i[404]
  PIN i[405]
    DIRECTION INPUT ;
    USE SIGNAL ;
    PORT
      LAYER M4 ;
        RECT  21.408 73.2 21.6 73.224 ;
    END
  END i[405]
  PIN i[406]
    DIRECTION INPUT ;
    USE SIGNAL ;
    PORT
      LAYER M4 ;
        RECT  21.408 73.344 21.6 73.368 ;
    END
  END i[406]
  PIN i[407]
    DIRECTION INPUT ;
    USE SIGNAL ;
    PORT
      LAYER M4 ;
        RECT  21.408 73.536 21.6 73.56 ;
    END
  END i[407]
  PIN i[408]
    DIRECTION INPUT ;
    USE SIGNAL ;
    PORT
      LAYER M4 ;
        RECT  21.408 73.728 21.6 73.752 ;
    END
  END i[408]
  PIN i[409]
    DIRECTION INPUT ;
    USE SIGNAL ;
    PORT
      LAYER M4 ;
        RECT  21.408 73.872 21.6 73.896 ;
    END
  END i[409]
  PIN i[40]
    DIRECTION INPUT ;
    USE SIGNAL ;
    PORT
      LAYER M4 ;
        RECT  21.408 11.136 21.6 11.16 ;
    END
  END i[40]
  PIN i[410]
    DIRECTION INPUT ;
    USE SIGNAL ;
    PORT
      LAYER M4 ;
        RECT  21.408 74.064 21.6 74.088 ;
    END
  END i[410]
  PIN i[411]
    DIRECTION INPUT ;
    USE SIGNAL ;
    PORT
      LAYER M4 ;
        RECT  21.408 74.208 21.6 74.232 ;
    END
  END i[411]
  PIN i[412]
    DIRECTION INPUT ;
    USE SIGNAL ;
    PORT
      LAYER M4 ;
        RECT  21.408 74.4 21.6 74.424 ;
    END
  END i[412]
  PIN i[413]
    DIRECTION INPUT ;
    USE SIGNAL ;
    PORT
      LAYER M4 ;
        RECT  21.408 74.544 21.6 74.568 ;
    END
  END i[413]
  PIN i[414]
    DIRECTION INPUT ;
    USE SIGNAL ;
    PORT
      LAYER M4 ;
        RECT  21.408 74.736 21.6 74.76 ;
    END
  END i[414]
  PIN i[415]
    DIRECTION INPUT ;
    USE SIGNAL ;
    PORT
      LAYER M4 ;
        RECT  21.408 74.88 21.6 74.904 ;
    END
  END i[415]
  PIN i[416]
    DIRECTION INPUT ;
    USE SIGNAL ;
    PORT
      LAYER M4 ;
        RECT  21.408 75.072 21.6 75.096 ;
    END
  END i[416]
  PIN i[417]
    DIRECTION INPUT ;
    USE SIGNAL ;
    PORT
      LAYER M4 ;
        RECT  21.408 75.216 21.6 75.24 ;
    END
  END i[417]
  PIN i[418]
    DIRECTION INPUT ;
    USE SIGNAL ;
    PORT
      LAYER M4 ;
        RECT  21.408 75.408 21.6 75.432 ;
    END
  END i[418]
  PIN i[419]
    DIRECTION INPUT ;
    USE SIGNAL ;
    PORT
      LAYER M4 ;
        RECT  21.408 75.552 21.6 75.576 ;
    END
  END i[419]
  PIN i[41]
    DIRECTION INPUT ;
    USE SIGNAL ;
    PORT
      LAYER M4 ;
        RECT  21.408 11.28 21.6 11.304 ;
    END
  END i[41]
  PIN i[420]
    DIRECTION INPUT ;
    USE SIGNAL ;
    PORT
      LAYER M4 ;
        RECT  21.408 75.744 21.6 75.768 ;
    END
  END i[420]
  PIN i[421]
    DIRECTION INPUT ;
    USE SIGNAL ;
    PORT
      LAYER M4 ;
        RECT  21.408 75.888 21.6 75.912 ;
    END
  END i[421]
  PIN i[422]
    DIRECTION INPUT ;
    USE SIGNAL ;
    PORT
      LAYER M4 ;
        RECT  21.408 76.08 21.6 76.104 ;
    END
  END i[422]
  PIN i[423]
    DIRECTION INPUT ;
    USE SIGNAL ;
    PORT
      LAYER M4 ;
        RECT  21.408 76.272 21.6 76.296 ;
    END
  END i[423]
  PIN i[424]
    DIRECTION INPUT ;
    USE SIGNAL ;
    PORT
      LAYER M4 ;
        RECT  21.408 76.416 21.6 76.44 ;
    END
  END i[424]
  PIN i[425]
    DIRECTION INPUT ;
    USE SIGNAL ;
    PORT
      LAYER M4 ;
        RECT  21.408 76.608 21.6 76.632 ;
    END
  END i[425]
  PIN i[426]
    DIRECTION INPUT ;
    USE SIGNAL ;
    PORT
      LAYER M4 ;
        RECT  21.408 76.752 21.6 76.776 ;
    END
  END i[426]
  PIN i[427]
    DIRECTION INPUT ;
    USE SIGNAL ;
    PORT
      LAYER M4 ;
        RECT  21.408 76.944 21.6 76.968 ;
    END
  END i[427]
  PIN i[428]
    DIRECTION INPUT ;
    USE SIGNAL ;
    PORT
      LAYER M4 ;
        RECT  21.408 77.088 21.6 77.112 ;
    END
  END i[428]
  PIN i[429]
    DIRECTION INPUT ;
    USE SIGNAL ;
    PORT
      LAYER M4 ;
        RECT  21.408 77.28 21.6 77.304 ;
    END
  END i[429]
  PIN i[42]
    DIRECTION INPUT ;
    USE SIGNAL ;
    PORT
      LAYER M4 ;
        RECT  21.408 11.472 21.6 11.496 ;
    END
  END i[42]
  PIN i[430]
    DIRECTION INPUT ;
    USE SIGNAL ;
    PORT
      LAYER M4 ;
        RECT  21.408 77.424 21.6 77.448 ;
    END
  END i[430]
  PIN i[431]
    DIRECTION INPUT ;
    USE SIGNAL ;
    PORT
      LAYER M4 ;
        RECT  21.408 77.616 21.6 77.64 ;
    END
  END i[431]
  PIN i[432]
    DIRECTION INPUT ;
    USE SIGNAL ;
    PORT
      LAYER M4 ;
        RECT  21.408 77.76 21.6 77.784 ;
    END
  END i[432]
  PIN i[433]
    DIRECTION INPUT ;
    USE SIGNAL ;
    PORT
      LAYER M4 ;
        RECT  21.408 77.952 21.6 77.976 ;
    END
  END i[433]
  PIN i[434]
    DIRECTION INPUT ;
    USE SIGNAL ;
    PORT
      LAYER M4 ;
        RECT  21.408 78.096 21.6 78.12 ;
    END
  END i[434]
  PIN i[435]
    DIRECTION INPUT ;
    USE SIGNAL ;
    PORT
      LAYER M4 ;
        RECT  21.408 78.288 21.6 78.312 ;
    END
  END i[435]
  PIN i[436]
    DIRECTION INPUT ;
    USE SIGNAL ;
    PORT
      LAYER M4 ;
        RECT  21.408 78.432 21.6 78.456 ;
    END
  END i[436]
  PIN i[437]
    DIRECTION INPUT ;
    USE SIGNAL ;
    PORT
      LAYER M4 ;
        RECT  21.408 78.624 21.6 78.648 ;
    END
  END i[437]
  PIN i[438]
    DIRECTION INPUT ;
    USE SIGNAL ;
    PORT
      LAYER M4 ;
        RECT  21.408 78.816 21.6 78.84 ;
    END
  END i[438]
  PIN i[439]
    DIRECTION INPUT ;
    USE SIGNAL ;
    PORT
      LAYER M4 ;
        RECT  21.408 78.96 21.6 78.984 ;
    END
  END i[439]
  PIN i[43]
    DIRECTION INPUT ;
    USE SIGNAL ;
    PORT
      LAYER M4 ;
        RECT  21.408 11.616 21.6 11.64 ;
    END
  END i[43]
  PIN i[440]
    DIRECTION INPUT ;
    USE SIGNAL ;
    PORT
      LAYER M4 ;
        RECT  21.408 79.152 21.6 79.176 ;
    END
  END i[440]
  PIN i[441]
    DIRECTION INPUT ;
    USE SIGNAL ;
    PORT
      LAYER M4 ;
        RECT  21.408 79.296 21.6 79.32 ;
    END
  END i[441]
  PIN i[442]
    DIRECTION INPUT ;
    USE SIGNAL ;
    PORT
      LAYER M4 ;
        RECT  21.408 79.488 21.6 79.512 ;
    END
  END i[442]
  PIN i[443]
    DIRECTION INPUT ;
    USE SIGNAL ;
    PORT
      LAYER M4 ;
        RECT  21.408 79.632 21.6 79.656 ;
    END
  END i[443]
  PIN i[444]
    DIRECTION INPUT ;
    USE SIGNAL ;
    PORT
      LAYER M4 ;
        RECT  21.408 79.824 21.6 79.848 ;
    END
  END i[444]
  PIN i[445]
    DIRECTION INPUT ;
    USE SIGNAL ;
    PORT
      LAYER M4 ;
        RECT  21.408 79.968 21.6 79.992 ;
    END
  END i[445]
  PIN i[446]
    DIRECTION INPUT ;
    USE SIGNAL ;
    PORT
      LAYER M4 ;
        RECT  21.408 80.16 21.6 80.184 ;
    END
  END i[446]
  PIN i[447]
    DIRECTION INPUT ;
    USE SIGNAL ;
    PORT
      LAYER M4 ;
        RECT  21.408 80.304 21.6 80.328 ;
    END
  END i[447]
  PIN i[448]
    DIRECTION INPUT ;
    USE SIGNAL ;
    PORT
      LAYER M4 ;
        RECT  21.408 80.496 21.6 80.52 ;
    END
  END i[448]
  PIN i[449]
    DIRECTION INPUT ;
    USE SIGNAL ;
    PORT
      LAYER M4 ;
        RECT  21.408 80.64 21.6 80.664 ;
    END
  END i[449]
  PIN i[44]
    DIRECTION INPUT ;
    USE SIGNAL ;
    PORT
      LAYER M4 ;
        RECT  21.408 11.808 21.6 11.832 ;
    END
  END i[44]
  PIN i[450]
    DIRECTION INPUT ;
    USE SIGNAL ;
    PORT
      LAYER M4 ;
        RECT  21.408 80.832 21.6 80.856 ;
    END
  END i[450]
  PIN i[451]
    DIRECTION INPUT ;
    USE SIGNAL ;
    PORT
      LAYER M4 ;
        RECT  21.408 80.976 21.6 81 ;
    END
  END i[451]
  PIN i[452]
    DIRECTION INPUT ;
    USE SIGNAL ;
    PORT
      LAYER M4 ;
        RECT  21.408 81.168 21.6 81.192 ;
    END
  END i[452]
  PIN i[453]
    DIRECTION INPUT ;
    USE SIGNAL ;
    PORT
      LAYER M4 ;
        RECT  21.408 81.36 21.6 81.384 ;
    END
  END i[453]
  PIN i[454]
    DIRECTION INPUT ;
    USE SIGNAL ;
    PORT
      LAYER M4 ;
        RECT  21.408 81.504 21.6 81.528 ;
    END
  END i[454]
  PIN i[455]
    DIRECTION INPUT ;
    USE SIGNAL ;
    PORT
      LAYER M4 ;
        RECT  21.408 81.696 21.6 81.72 ;
    END
  END i[455]
  PIN i[456]
    DIRECTION INPUT ;
    USE SIGNAL ;
    PORT
      LAYER M4 ;
        RECT  21.408 81.84 21.6 81.864 ;
    END
  END i[456]
  PIN i[457]
    DIRECTION INPUT ;
    USE SIGNAL ;
    PORT
      LAYER M4 ;
        RECT  21.408 82.032 21.6 82.056 ;
    END
  END i[457]
  PIN i[458]
    DIRECTION INPUT ;
    USE SIGNAL ;
    PORT
      LAYER M4 ;
        RECT  21.408 82.176 21.6 82.2 ;
    END
  END i[458]
  PIN i[459]
    DIRECTION INPUT ;
    USE SIGNAL ;
    PORT
      LAYER M4 ;
        RECT  21.408 82.368 21.6 82.392 ;
    END
  END i[459]
  PIN i[45]
    DIRECTION INPUT ;
    USE SIGNAL ;
    PORT
      LAYER M4 ;
        RECT  21.408 11.952 21.6 11.976 ;
    END
  END i[45]
  PIN i[460]
    DIRECTION INPUT ;
    USE SIGNAL ;
    PORT
      LAYER M4 ;
        RECT  21.408 82.512 21.6 82.536 ;
    END
  END i[460]
  PIN i[461]
    DIRECTION INPUT ;
    USE SIGNAL ;
    PORT
      LAYER M4 ;
        RECT  21.408 82.704 21.6 82.728 ;
    END
  END i[461]
  PIN i[462]
    DIRECTION INPUT ;
    USE SIGNAL ;
    PORT
      LAYER M4 ;
        RECT  21.408 82.848 21.6 82.872 ;
    END
  END i[462]
  PIN i[463]
    DIRECTION INPUT ;
    USE SIGNAL ;
    PORT
      LAYER M4 ;
        RECT  21.408 83.04 21.6 83.064 ;
    END
  END i[463]
  PIN i[464]
    DIRECTION INPUT ;
    USE SIGNAL ;
    PORT
      LAYER M4 ;
        RECT  21.408 83.184 21.6 83.208 ;
    END
  END i[464]
  PIN i[465]
    DIRECTION INPUT ;
    USE SIGNAL ;
    PORT
      LAYER M4 ;
        RECT  21.408 83.376 21.6 83.4 ;
    END
  END i[465]
  PIN i[466]
    DIRECTION INPUT ;
    USE SIGNAL ;
    PORT
      LAYER M4 ;
        RECT  21.408 83.52 21.6 83.544 ;
    END
  END i[466]
  PIN i[467]
    DIRECTION INPUT ;
    USE SIGNAL ;
    PORT
      LAYER M4 ;
        RECT  21.408 83.712 21.6 83.736 ;
    END
  END i[467]
  PIN i[468]
    DIRECTION INPUT ;
    USE SIGNAL ;
    PORT
      LAYER M4 ;
        RECT  21.408 83.904 21.6 83.928 ;
    END
  END i[468]
  PIN i[469]
    DIRECTION INPUT ;
    USE SIGNAL ;
    PORT
      LAYER M4 ;
        RECT  21.408 84.048 21.6 84.072 ;
    END
  END i[469]
  PIN i[46]
    DIRECTION INPUT ;
    USE SIGNAL ;
    PORT
      LAYER M4 ;
        RECT  21.408 12.144 21.6 12.168 ;
    END
  END i[46]
  PIN i[470]
    DIRECTION INPUT ;
    USE SIGNAL ;
    PORT
      LAYER M4 ;
        RECT  21.408 84.24 21.6 84.264 ;
    END
  END i[470]
  PIN i[471]
    DIRECTION INPUT ;
    USE SIGNAL ;
    PORT
      LAYER M4 ;
        RECT  21.408 84.384 21.6 84.408 ;
    END
  END i[471]
  PIN i[472]
    DIRECTION INPUT ;
    USE SIGNAL ;
    PORT
      LAYER M4 ;
        RECT  21.408 84.576 21.6 84.6 ;
    END
  END i[472]
  PIN i[473]
    DIRECTION INPUT ;
    USE SIGNAL ;
    PORT
      LAYER M4 ;
        RECT  21.408 84.72 21.6 84.744 ;
    END
  END i[473]
  PIN i[474]
    DIRECTION INPUT ;
    USE SIGNAL ;
    PORT
      LAYER M4 ;
        RECT  21.408 84.912 21.6 84.936 ;
    END
  END i[474]
  PIN i[475]
    DIRECTION INPUT ;
    USE SIGNAL ;
    PORT
      LAYER M4 ;
        RECT  21.408 85.056 21.6 85.08 ;
    END
  END i[475]
  PIN i[476]
    DIRECTION INPUT ;
    USE SIGNAL ;
    PORT
      LAYER M4 ;
        RECT  21.408 85.248 21.6 85.272 ;
    END
  END i[476]
  PIN i[477]
    DIRECTION INPUT ;
    USE SIGNAL ;
    PORT
      LAYER M4 ;
        RECT  21.408 85.392 21.6 85.416 ;
    END
  END i[477]
  PIN i[478]
    DIRECTION INPUT ;
    USE SIGNAL ;
    PORT
      LAYER M4 ;
        RECT  21.408 85.584 21.6 85.608 ;
    END
  END i[478]
  PIN i[479]
    DIRECTION INPUT ;
    USE SIGNAL ;
    PORT
      LAYER M4 ;
        RECT  21.408 85.728 21.6 85.752 ;
    END
  END i[479]
  PIN i[47]
    DIRECTION INPUT ;
    USE SIGNAL ;
    PORT
      LAYER M4 ;
        RECT  21.408 12.288 21.6 12.312 ;
    END
  END i[47]
  PIN i[480]
    DIRECTION INPUT ;
    USE SIGNAL ;
    PORT
      LAYER M4 ;
        RECT  21.408 85.92 21.6 85.944 ;
    END
  END i[480]
  PIN i[481]
    DIRECTION INPUT ;
    USE SIGNAL ;
    PORT
      LAYER M4 ;
        RECT  21.408 86.064 21.6 86.088 ;
    END
  END i[481]
  PIN i[482]
    DIRECTION INPUT ;
    USE SIGNAL ;
    PORT
      LAYER M4 ;
        RECT  21.408 86.256 21.6 86.28 ;
    END
  END i[482]
  PIN i[483]
    DIRECTION INPUT ;
    USE SIGNAL ;
    PORT
      LAYER M4 ;
        RECT  21.408 86.448 21.6 86.472 ;
    END
  END i[483]
  PIN i[484]
    DIRECTION INPUT ;
    USE SIGNAL ;
    PORT
      LAYER M4 ;
        RECT  21.408 86.592 21.6 86.616 ;
    END
  END i[484]
  PIN i[485]
    DIRECTION INPUT ;
    USE SIGNAL ;
    PORT
      LAYER M4 ;
        RECT  21.408 86.784 21.6 86.808 ;
    END
  END i[485]
  PIN i[486]
    DIRECTION INPUT ;
    USE SIGNAL ;
    PORT
      LAYER M4 ;
        RECT  21.408 86.928 21.6 86.952 ;
    END
  END i[486]
  PIN i[487]
    DIRECTION INPUT ;
    USE SIGNAL ;
    PORT
      LAYER M4 ;
        RECT  21.408 87.12 21.6 87.144 ;
    END
  END i[487]
  PIN i[488]
    DIRECTION INPUT ;
    USE SIGNAL ;
    PORT
      LAYER M4 ;
        RECT  21.408 87.264 21.6 87.288 ;
    END
  END i[488]
  PIN i[489]
    DIRECTION INPUT ;
    USE SIGNAL ;
    PORT
      LAYER M4 ;
        RECT  21.408 87.456 21.6 87.48 ;
    END
  END i[489]
  PIN i[48]
    DIRECTION INPUT ;
    USE SIGNAL ;
    PORT
      LAYER M4 ;
        RECT  21.408 12.48 21.6 12.504 ;
    END
  END i[48]
  PIN i[490]
    DIRECTION INPUT ;
    USE SIGNAL ;
    PORT
      LAYER M4 ;
        RECT  21.408 87.6 21.6 87.624 ;
    END
  END i[490]
  PIN i[491]
    DIRECTION INPUT ;
    USE SIGNAL ;
    PORT
      LAYER M4 ;
        RECT  21.408 87.792 21.6 87.816 ;
    END
  END i[491]
  PIN i[492]
    DIRECTION INPUT ;
    USE SIGNAL ;
    PORT
      LAYER M4 ;
        RECT  21.408 87.936 21.6 87.96 ;
    END
  END i[492]
  PIN i[493]
    DIRECTION INPUT ;
    USE SIGNAL ;
    PORT
      LAYER M4 ;
        RECT  21.408 88.128 21.6 88.152 ;
    END
  END i[493]
  PIN i[494]
    DIRECTION INPUT ;
    USE SIGNAL ;
    PORT
      LAYER M4 ;
        RECT  21.408 88.272 21.6 88.296 ;
    END
  END i[494]
  PIN i[495]
    DIRECTION INPUT ;
    USE SIGNAL ;
    PORT
      LAYER M4 ;
        RECT  21.408 88.464 21.6 88.488 ;
    END
  END i[495]
  PIN i[496]
    DIRECTION INPUT ;
    USE SIGNAL ;
    PORT
      LAYER M4 ;
        RECT  21.408 88.608 21.6 88.632 ;
    END
  END i[496]
  PIN i[497]
    DIRECTION INPUT ;
    USE SIGNAL ;
    PORT
      LAYER M4 ;
        RECT  21.408 88.8 21.6 88.824 ;
    END
  END i[497]
  PIN i[498]
    DIRECTION INPUT ;
    USE SIGNAL ;
    PORT
      LAYER M4 ;
        RECT  21.408 88.992 21.6 89.016 ;
    END
  END i[498]
  PIN i[499]
    DIRECTION INPUT ;
    USE SIGNAL ;
    PORT
      LAYER M4 ;
        RECT  21.408 89.136 21.6 89.16 ;
    END
  END i[499]
  PIN i[49]
    DIRECTION INPUT ;
    USE SIGNAL ;
    PORT
      LAYER M4 ;
        RECT  21.408 12.624 21.6 12.648 ;
    END
  END i[49]
  PIN i[4]
    DIRECTION INPUT ;
    USE SIGNAL ;
    PORT
      LAYER M4 ;
        RECT  21.408 4.992 21.6 5.016 ;
    END
  END i[4]
  PIN i[500]
    DIRECTION INPUT ;
    USE SIGNAL ;
    PORT
      LAYER M4 ;
        RECT  21.408 89.328 21.6 89.352 ;
    END
  END i[500]
  PIN i[501]
    DIRECTION INPUT ;
    USE SIGNAL ;
    PORT
      LAYER M4 ;
        RECT  21.408 89.472 21.6 89.496 ;
    END
  END i[501]
  PIN i[502]
    DIRECTION INPUT ;
    USE SIGNAL ;
    PORT
      LAYER M4 ;
        RECT  21.408 89.664 21.6 89.688 ;
    END
  END i[502]
  PIN i[503]
    DIRECTION INPUT ;
    USE SIGNAL ;
    PORT
      LAYER M4 ;
        RECT  21.408 89.808 21.6 89.832 ;
    END
  END i[503]
  PIN i[504]
    DIRECTION INPUT ;
    USE SIGNAL ;
    PORT
      LAYER M4 ;
        RECT  21.408 90 21.6 90.024 ;
    END
  END i[504]
  PIN i[505]
    DIRECTION INPUT ;
    USE SIGNAL ;
    PORT
      LAYER M4 ;
        RECT  21.408 90.144 21.6 90.168 ;
    END
  END i[505]
  PIN i[506]
    DIRECTION INPUT ;
    USE SIGNAL ;
    PORT
      LAYER M4 ;
        RECT  21.408 90.336 21.6 90.36 ;
    END
  END i[506]
  PIN i[507]
    DIRECTION INPUT ;
    USE SIGNAL ;
    PORT
      LAYER M4 ;
        RECT  21.408 90.48 21.6 90.504 ;
    END
  END i[507]
  PIN i[508]
    DIRECTION INPUT ;
    USE SIGNAL ;
    PORT
      LAYER M4 ;
        RECT  21.408 90.672 21.6 90.696 ;
    END
  END i[508]
  PIN i[509]
    DIRECTION INPUT ;
    USE SIGNAL ;
    PORT
      LAYER M4 ;
        RECT  21.408 90.816 21.6 90.84 ;
    END
  END i[509]
  PIN i[50]
    DIRECTION INPUT ;
    USE SIGNAL ;
    PORT
      LAYER M4 ;
        RECT  21.408 12.816 21.6 12.84 ;
    END
  END i[50]
  PIN i[510]
    DIRECTION INPUT ;
    USE SIGNAL ;
    PORT
      LAYER M4 ;
        RECT  21.408 91.008 21.6 91.032 ;
    END
  END i[510]
  PIN i[511]
    DIRECTION INPUT ;
    USE SIGNAL ;
    PORT
      LAYER M4 ;
        RECT  21.408 91.152 21.6 91.176 ;
    END
  END i[511]
  PIN i[512]
    DIRECTION INPUT ;
    USE SIGNAL ;
    PORT
      LAYER M4 ;
        RECT  21.408 91.344 21.6 91.368 ;
    END
  END i[512]
  PIN i[513]
    DIRECTION INPUT ;
    USE SIGNAL ;
    PORT
      LAYER M4 ;
        RECT  21.408 91.536 21.6 91.56 ;
    END
  END i[513]
  PIN i[514]
    DIRECTION INPUT ;
    USE SIGNAL ;
    PORT
      LAYER M4 ;
        RECT  21.408 91.68 21.6 91.704 ;
    END
  END i[514]
  PIN i[515]
    DIRECTION INPUT ;
    USE SIGNAL ;
    PORT
      LAYER M4 ;
        RECT  21.408 91.872 21.6 91.896 ;
    END
  END i[515]
  PIN i[516]
    DIRECTION INPUT ;
    USE SIGNAL ;
    PORT
      LAYER M4 ;
        RECT  21.408 92.016 21.6 92.04 ;
    END
  END i[516]
  PIN i[517]
    DIRECTION INPUT ;
    USE SIGNAL ;
    PORT
      LAYER M4 ;
        RECT  21.408 92.208 21.6 92.232 ;
    END
  END i[517]
  PIN i[518]
    DIRECTION INPUT ;
    USE SIGNAL ;
    PORT
      LAYER M4 ;
        RECT  21.408 92.352 21.6 92.376 ;
    END
  END i[518]
  PIN i[519]
    DIRECTION INPUT ;
    USE SIGNAL ;
    PORT
      LAYER M4 ;
        RECT  21.408 92.544 21.6 92.568 ;
    END
  END i[519]
  PIN i[51]
    DIRECTION INPUT ;
    USE SIGNAL ;
    PORT
      LAYER M4 ;
        RECT  21.408 12.96 21.6 12.984 ;
    END
  END i[51]
  PIN i[520]
    DIRECTION INPUT ;
    USE SIGNAL ;
    PORT
      LAYER M4 ;
        RECT  21.408 92.688 21.6 92.712 ;
    END
  END i[520]
  PIN i[521]
    DIRECTION INPUT ;
    USE SIGNAL ;
    PORT
      LAYER M4 ;
        RECT  21.408 92.88 21.6 92.904 ;
    END
  END i[521]
  PIN i[522]
    DIRECTION INPUT ;
    USE SIGNAL ;
    PORT
      LAYER M4 ;
        RECT  21.408 93.024 21.6 93.048 ;
    END
  END i[522]
  PIN i[523]
    DIRECTION INPUT ;
    USE SIGNAL ;
    PORT
      LAYER M4 ;
        RECT  21.408 93.216 21.6 93.24 ;
    END
  END i[523]
  PIN i[524]
    DIRECTION INPUT ;
    USE SIGNAL ;
    PORT
      LAYER M4 ;
        RECT  21.408 93.36 21.6 93.384 ;
    END
  END i[524]
  PIN i[525]
    DIRECTION INPUT ;
    USE SIGNAL ;
    PORT
      LAYER M4 ;
        RECT  21.408 93.552 21.6 93.576 ;
    END
  END i[525]
  PIN i[526]
    DIRECTION INPUT ;
    USE SIGNAL ;
    PORT
      LAYER M4 ;
        RECT  21.408 93.696 21.6 93.72 ;
    END
  END i[526]
  PIN i[527]
    DIRECTION INPUT ;
    USE SIGNAL ;
    PORT
      LAYER M4 ;
        RECT  21.408 93.888 21.6 93.912 ;
    END
  END i[527]
  PIN i[528]
    DIRECTION INPUT ;
    USE SIGNAL ;
    PORT
      LAYER M4 ;
        RECT  21.408 94.08 21.6 94.104 ;
    END
  END i[528]
  PIN i[529]
    DIRECTION INPUT ;
    USE SIGNAL ;
    PORT
      LAYER M4 ;
        RECT  21.408 94.224 21.6 94.248 ;
    END
  END i[529]
  PIN i[52]
    DIRECTION INPUT ;
    USE SIGNAL ;
    PORT
      LAYER M4 ;
        RECT  21.408 13.152 21.6 13.176 ;
    END
  END i[52]
  PIN i[530]
    DIRECTION INPUT ;
    USE SIGNAL ;
    PORT
      LAYER M4 ;
        RECT  21.408 94.416 21.6 94.44 ;
    END
  END i[530]
  PIN i[531]
    DIRECTION INPUT ;
    USE SIGNAL ;
    PORT
      LAYER M4 ;
        RECT  21.408 94.56 21.6 94.584 ;
    END
  END i[531]
  PIN i[532]
    DIRECTION INPUT ;
    USE SIGNAL ;
    PORT
      LAYER M4 ;
        RECT  21.408 94.752 21.6 94.776 ;
    END
  END i[532]
  PIN i[533]
    DIRECTION INPUT ;
    USE SIGNAL ;
    PORT
      LAYER M4 ;
        RECT  21.408 94.896 21.6 94.92 ;
    END
  END i[533]
  PIN i[534]
    DIRECTION INPUT ;
    USE SIGNAL ;
    PORT
      LAYER M4 ;
        RECT  21.408 95.088 21.6 95.112 ;
    END
  END i[534]
  PIN i[535]
    DIRECTION INPUT ;
    USE SIGNAL ;
    PORT
      LAYER M4 ;
        RECT  21.408 95.232 21.6 95.256 ;
    END
  END i[535]
  PIN i[536]
    DIRECTION INPUT ;
    USE SIGNAL ;
    PORT
      LAYER M4 ;
        RECT  21.408 95.424 21.6 95.448 ;
    END
  END i[536]
  PIN i[537]
    DIRECTION INPUT ;
    USE SIGNAL ;
    PORT
      LAYER M4 ;
        RECT  21.408 95.568 21.6 95.592 ;
    END
  END i[537]
  PIN i[538]
    DIRECTION INPUT ;
    USE SIGNAL ;
    PORT
      LAYER M4 ;
        RECT  21.408 95.76 21.6 95.784 ;
    END
  END i[538]
  PIN i[539]
    DIRECTION INPUT ;
    USE SIGNAL ;
    PORT
      LAYER M4 ;
        RECT  21.408 95.904 21.6 95.928 ;
    END
  END i[539]
  PIN i[53]
    DIRECTION INPUT ;
    USE SIGNAL ;
    PORT
      LAYER M4 ;
        RECT  21.408 13.344 21.6 13.368 ;
    END
  END i[53]
  PIN i[540]
    DIRECTION INPUT ;
    USE SIGNAL ;
    PORT
      LAYER M4 ;
        RECT  21.408 96.096 21.6 96.12 ;
    END
  END i[540]
  PIN i[541]
    DIRECTION INPUT ;
    USE SIGNAL ;
    PORT
      LAYER M4 ;
        RECT  21.408 96.24 21.6 96.264 ;
    END
  END i[541]
  PIN i[542]
    DIRECTION INPUT ;
    USE SIGNAL ;
    PORT
      LAYER M4 ;
        RECT  21.408 96.432 21.6 96.456 ;
    END
  END i[542]
  PIN i[543]
    DIRECTION INPUT ;
    USE SIGNAL ;
    PORT
      LAYER M4 ;
        RECT  21.408 96.624 21.6 96.648 ;
    END
  END i[543]
  PIN i[544]
    DIRECTION INPUT ;
    USE SIGNAL ;
    PORT
      LAYER M4 ;
        RECT  21.408 96.768 21.6 96.792 ;
    END
  END i[544]
  PIN i[545]
    DIRECTION INPUT ;
    USE SIGNAL ;
    PORT
      LAYER M4 ;
        RECT  21.408 96.96 21.6 96.984 ;
    END
  END i[545]
  PIN i[546]
    DIRECTION INPUT ;
    USE SIGNAL ;
    PORT
      LAYER M4 ;
        RECT  21.408 97.104 21.6 97.128 ;
    END
  END i[546]
  PIN i[547]
    DIRECTION INPUT ;
    USE SIGNAL ;
    PORT
      LAYER M4 ;
        RECT  21.408 97.296 21.6 97.32 ;
    END
  END i[547]
  PIN i[548]
    DIRECTION INPUT ;
    USE SIGNAL ;
    PORT
      LAYER M4 ;
        RECT  21.408 97.44 21.6 97.464 ;
    END
  END i[548]
  PIN i[549]
    DIRECTION INPUT ;
    USE SIGNAL ;
    PORT
      LAYER M4 ;
        RECT  21.408 97.632 21.6 97.656 ;
    END
  END i[549]
  PIN i[54]
    DIRECTION INPUT ;
    USE SIGNAL ;
    PORT
      LAYER M4 ;
        RECT  21.408 13.488 21.6 13.512 ;
    END
  END i[54]
  PIN i[550]
    DIRECTION INPUT ;
    USE SIGNAL ;
    PORT
      LAYER M4 ;
        RECT  21.408 97.776 21.6 97.8 ;
    END
  END i[550]
  PIN i[551]
    DIRECTION INPUT ;
    USE SIGNAL ;
    PORT
      LAYER M4 ;
        RECT  21.408 97.968 21.6 97.992 ;
    END
  END i[551]
  PIN i[552]
    DIRECTION INPUT ;
    USE SIGNAL ;
    PORT
      LAYER M4 ;
        RECT  21.408 98.112 21.6 98.136 ;
    END
  END i[552]
  PIN i[553]
    DIRECTION INPUT ;
    USE SIGNAL ;
    PORT
      LAYER M4 ;
        RECT  21.408 98.304 21.6 98.328 ;
    END
  END i[553]
  PIN i[554]
    DIRECTION INPUT ;
    USE SIGNAL ;
    PORT
      LAYER M4 ;
        RECT  21.408 98.448 21.6 98.472 ;
    END
  END i[554]
  PIN i[555]
    DIRECTION INPUT ;
    USE SIGNAL ;
    PORT
      LAYER M4 ;
        RECT  21.408 98.64 21.6 98.664 ;
    END
  END i[555]
  PIN i[556]
    DIRECTION INPUT ;
    USE SIGNAL ;
    PORT
      LAYER M4 ;
        RECT  21.408 98.784 21.6 98.808 ;
    END
  END i[556]
  PIN i[557]
    DIRECTION INPUT ;
    USE SIGNAL ;
    PORT
      LAYER M4 ;
        RECT  21.408 98.976 21.6 99 ;
    END
  END i[557]
  PIN i[558]
    DIRECTION INPUT ;
    USE SIGNAL ;
    PORT
      LAYER M4 ;
        RECT  21.408 99.168 21.6 99.192 ;
    END
  END i[558]
  PIN i[559]
    DIRECTION INPUT ;
    USE SIGNAL ;
    PORT
      LAYER M4 ;
        RECT  21.408 99.312 21.6 99.336 ;
    END
  END i[559]
  PIN i[55]
    DIRECTION INPUT ;
    USE SIGNAL ;
    PORT
      LAYER M4 ;
        RECT  21.408 13.68 21.6 13.704 ;
    END
  END i[55]
  PIN i[560]
    DIRECTION INPUT ;
    USE SIGNAL ;
    PORT
      LAYER M4 ;
        RECT  21.408 99.504 21.6 99.528 ;
    END
  END i[560]
  PIN i[561]
    DIRECTION INPUT ;
    USE SIGNAL ;
    PORT
      LAYER M4 ;
        RECT  21.408 99.648 21.6 99.672 ;
    END
  END i[561]
  PIN i[562]
    DIRECTION INPUT ;
    USE SIGNAL ;
    PORT
      LAYER M4 ;
        RECT  21.408 99.84 21.6 99.864 ;
    END
  END i[562]
  PIN i[563]
    DIRECTION INPUT ;
    USE SIGNAL ;
    PORT
      LAYER M4 ;
        RECT  21.408 99.984 21.6 100.008 ;
    END
  END i[563]
  PIN i[564]
    DIRECTION INPUT ;
    USE SIGNAL ;
    PORT
      LAYER M4 ;
        RECT  21.408 100.176 21.6 100.2 ;
    END
  END i[564]
  PIN i[565]
    DIRECTION INPUT ;
    USE SIGNAL ;
    PORT
      LAYER M4 ;
        RECT  21.408 100.32 21.6 100.344 ;
    END
  END i[565]
  PIN i[566]
    DIRECTION INPUT ;
    USE SIGNAL ;
    PORT
      LAYER M4 ;
        RECT  21.408 100.512 21.6 100.536 ;
    END
  END i[566]
  PIN i[567]
    DIRECTION INPUT ;
    USE SIGNAL ;
    PORT
      LAYER M4 ;
        RECT  21.408 100.656 21.6 100.68 ;
    END
  END i[567]
  PIN i[568]
    DIRECTION INPUT ;
    USE SIGNAL ;
    PORT
      LAYER M4 ;
        RECT  21.408 100.848 21.6 100.872 ;
    END
  END i[568]
  PIN i[569]
    DIRECTION INPUT ;
    USE SIGNAL ;
    PORT
      LAYER M4 ;
        RECT  21.408 100.992 21.6 101.016 ;
    END
  END i[569]
  PIN i[56]
    DIRECTION INPUT ;
    USE SIGNAL ;
    PORT
      LAYER M4 ;
        RECT  21.408 13.824 21.6 13.848 ;
    END
  END i[56]
  PIN i[570]
    DIRECTION INPUT ;
    USE SIGNAL ;
    PORT
      LAYER M4 ;
        RECT  21.408 101.184 21.6 101.208 ;
    END
  END i[570]
  PIN i[571]
    DIRECTION INPUT ;
    USE SIGNAL ;
    PORT
      LAYER M4 ;
        RECT  21.408 101.328 21.6 101.352 ;
    END
  END i[571]
  PIN i[572]
    DIRECTION INPUT ;
    USE SIGNAL ;
    PORT
      LAYER M4 ;
        RECT  21.408 101.52 21.6 101.544 ;
    END
  END i[572]
  PIN i[573]
    DIRECTION INPUT ;
    USE SIGNAL ;
    PORT
      LAYER M4 ;
        RECT  21.408 101.712 21.6 101.736 ;
    END
  END i[573]
  PIN i[574]
    DIRECTION INPUT ;
    USE SIGNAL ;
    PORT
      LAYER M4 ;
        RECT  21.408 101.856 21.6 101.88 ;
    END
  END i[574]
  PIN i[575]
    DIRECTION INPUT ;
    USE SIGNAL ;
    PORT
      LAYER M4 ;
        RECT  21.408 102.048 21.6 102.072 ;
    END
  END i[575]
  PIN i[576]
    DIRECTION INPUT ;
    USE SIGNAL ;
    PORT
      LAYER M4 ;
        RECT  21.408 102.192 21.6 102.216 ;
    END
  END i[576]
  PIN i[577]
    DIRECTION INPUT ;
    USE SIGNAL ;
    PORT
      LAYER M4 ;
        RECT  21.408 102.384 21.6 102.408 ;
    END
  END i[577]
  PIN i[578]
    DIRECTION INPUT ;
    USE SIGNAL ;
    PORT
      LAYER M4 ;
        RECT  21.408 102.528 21.6 102.552 ;
    END
  END i[578]
  PIN i[579]
    DIRECTION INPUT ;
    USE SIGNAL ;
    PORT
      LAYER M4 ;
        RECT  21.408 102.72 21.6 102.744 ;
    END
  END i[579]
  PIN i[57]
    DIRECTION INPUT ;
    USE SIGNAL ;
    PORT
      LAYER M4 ;
        RECT  21.408 14.016 21.6 14.04 ;
    END
  END i[57]
  PIN i[580]
    DIRECTION INPUT ;
    USE SIGNAL ;
    PORT
      LAYER M4 ;
        RECT  21.408 102.864 21.6 102.888 ;
    END
  END i[580]
  PIN i[581]
    DIRECTION INPUT ;
    USE SIGNAL ;
    PORT
      LAYER M4 ;
        RECT  21.408 103.056 21.6 103.08 ;
    END
  END i[581]
  PIN i[582]
    DIRECTION INPUT ;
    USE SIGNAL ;
    PORT
      LAYER M4 ;
        RECT  21.408 103.2 21.6 103.224 ;
    END
  END i[582]
  PIN i[583]
    DIRECTION INPUT ;
    USE SIGNAL ;
    PORT
      LAYER M4 ;
        RECT  21.408 103.392 21.6 103.416 ;
    END
  END i[583]
  PIN i[584]
    DIRECTION INPUT ;
    USE SIGNAL ;
    PORT
      LAYER M4 ;
        RECT  21.408 103.536 21.6 103.56 ;
    END
  END i[584]
  PIN i[585]
    DIRECTION INPUT ;
    USE SIGNAL ;
    PORT
      LAYER M4 ;
        RECT  21.408 103.728 21.6 103.752 ;
    END
  END i[585]
  PIN i[586]
    DIRECTION INPUT ;
    USE SIGNAL ;
    PORT
      LAYER M4 ;
        RECT  21.408 103.92 21.6 103.944 ;
    END
  END i[586]
  PIN i[587]
    DIRECTION INPUT ;
    USE SIGNAL ;
    PORT
      LAYER M4 ;
        RECT  21.408 104.064 21.6 104.088 ;
    END
  END i[587]
  PIN i[588]
    DIRECTION INPUT ;
    USE SIGNAL ;
    PORT
      LAYER M4 ;
        RECT  21.408 104.256 21.6 104.28 ;
    END
  END i[588]
  PIN i[589]
    DIRECTION INPUT ;
    USE SIGNAL ;
    PORT
      LAYER M4 ;
        RECT  21.408 104.4 21.6 104.424 ;
    END
  END i[589]
  PIN i[58]
    DIRECTION INPUT ;
    USE SIGNAL ;
    PORT
      LAYER M4 ;
        RECT  21.408 14.16 21.6 14.184 ;
    END
  END i[58]
  PIN i[590]
    DIRECTION INPUT ;
    USE SIGNAL ;
    PORT
      LAYER M4 ;
        RECT  21.408 104.592 21.6 104.616 ;
    END
  END i[590]
  PIN i[591]
    DIRECTION INPUT ;
    USE SIGNAL ;
    PORT
      LAYER M4 ;
        RECT  21.408 104.736 21.6 104.76 ;
    END
  END i[591]
  PIN i[592]
    DIRECTION INPUT ;
    USE SIGNAL ;
    PORT
      LAYER M4 ;
        RECT  21.408 104.928 21.6 104.952 ;
    END
  END i[592]
  PIN i[593]
    DIRECTION INPUT ;
    USE SIGNAL ;
    PORT
      LAYER M4 ;
        RECT  21.408 105.072 21.6 105.096 ;
    END
  END i[593]
  PIN i[594]
    DIRECTION INPUT ;
    USE SIGNAL ;
    PORT
      LAYER M4 ;
        RECT  21.408 105.264 21.6 105.288 ;
    END
  END i[594]
  PIN i[595]
    DIRECTION INPUT ;
    USE SIGNAL ;
    PORT
      LAYER M4 ;
        RECT  21.408 105.408 21.6 105.432 ;
    END
  END i[595]
  PIN i[596]
    DIRECTION INPUT ;
    USE SIGNAL ;
    PORT
      LAYER M4 ;
        RECT  21.408 105.6 21.6 105.624 ;
    END
  END i[596]
  PIN i[597]
    DIRECTION INPUT ;
    USE SIGNAL ;
    PORT
      LAYER M4 ;
        RECT  21.408 105.744 21.6 105.768 ;
    END
  END i[597]
  PIN i[598]
    DIRECTION INPUT ;
    USE SIGNAL ;
    PORT
      LAYER M4 ;
        RECT  21.408 105.936 21.6 105.96 ;
    END
  END i[598]
  PIN i[599]
    DIRECTION INPUT ;
    USE SIGNAL ;
    PORT
      LAYER M4 ;
        RECT  21.408 106.08 21.6 106.104 ;
    END
  END i[599]
  PIN i[59]
    DIRECTION INPUT ;
    USE SIGNAL ;
    PORT
      LAYER M4 ;
        RECT  21.408 14.352 21.6 14.376 ;
    END
  END i[59]
  PIN i[5]
    DIRECTION INPUT ;
    USE SIGNAL ;
    PORT
      LAYER M4 ;
        RECT  21.408 5.184 21.6 5.208 ;
    END
  END i[5]
  PIN i[600]
    DIRECTION INPUT ;
    USE SIGNAL ;
    PORT
      LAYER M4 ;
        RECT  21.408 106.272 21.6 106.296 ;
    END
  END i[600]
  PIN i[601]
    DIRECTION INPUT ;
    USE SIGNAL ;
    PORT
      LAYER M4 ;
        RECT  21.408 106.464 21.6 106.488 ;
    END
  END i[601]
  PIN i[602]
    DIRECTION INPUT ;
    USE SIGNAL ;
    PORT
      LAYER M4 ;
        RECT  21.408 106.608 21.6 106.632 ;
    END
  END i[602]
  PIN i[603]
    DIRECTION INPUT ;
    USE SIGNAL ;
    PORT
      LAYER M4 ;
        RECT  21.408 106.8 21.6 106.824 ;
    END
  END i[603]
  PIN i[604]
    DIRECTION INPUT ;
    USE SIGNAL ;
    PORT
      LAYER M4 ;
        RECT  21.408 106.944 21.6 106.968 ;
    END
  END i[604]
  PIN i[605]
    DIRECTION INPUT ;
    USE SIGNAL ;
    PORT
      LAYER M4 ;
        RECT  21.408 107.136 21.6 107.16 ;
    END
  END i[605]
  PIN i[606]
    DIRECTION INPUT ;
    USE SIGNAL ;
    PORT
      LAYER M4 ;
        RECT  21.408 107.28 21.6 107.304 ;
    END
  END i[606]
  PIN i[607]
    DIRECTION INPUT ;
    USE SIGNAL ;
    PORT
      LAYER M4 ;
        RECT  21.408 107.472 21.6 107.496 ;
    END
  END i[607]
  PIN i[608]
    DIRECTION INPUT ;
    USE SIGNAL ;
    PORT
      LAYER M4 ;
        RECT  21.408 107.616 21.6 107.64 ;
    END
  END i[608]
  PIN i[609]
    DIRECTION INPUT ;
    USE SIGNAL ;
    PORT
      LAYER M4 ;
        RECT  21.408 107.808 21.6 107.832 ;
    END
  END i[609]
  PIN i[60]
    DIRECTION INPUT ;
    USE SIGNAL ;
    PORT
      LAYER M4 ;
        RECT  21.408 14.496 21.6 14.52 ;
    END
  END i[60]
  PIN i[610]
    DIRECTION INPUT ;
    USE SIGNAL ;
    PORT
      LAYER M4 ;
        RECT  21.408 107.952 21.6 107.976 ;
    END
  END i[610]
  PIN i[611]
    DIRECTION INPUT ;
    USE SIGNAL ;
    PORT
      LAYER M4 ;
        RECT  21.408 108.144 21.6 108.168 ;
    END
  END i[611]
  PIN i[612]
    DIRECTION INPUT ;
    USE SIGNAL ;
    PORT
      LAYER M4 ;
        RECT  21.408 108.288 21.6 108.312 ;
    END
  END i[612]
  PIN i[613]
    DIRECTION INPUT ;
    USE SIGNAL ;
    PORT
      LAYER M4 ;
        RECT  21.408 108.48 21.6 108.504 ;
    END
  END i[613]
  PIN i[614]
    DIRECTION INPUT ;
    USE SIGNAL ;
    PORT
      LAYER M4 ;
        RECT  21.408 108.624 21.6 108.648 ;
    END
  END i[614]
  PIN i[615]
    DIRECTION INPUT ;
    USE SIGNAL ;
    PORT
      LAYER M4 ;
        RECT  21.408 108.816 21.6 108.84 ;
    END
  END i[615]
  PIN i[616]
    DIRECTION INPUT ;
    USE SIGNAL ;
    PORT
      LAYER M4 ;
        RECT  21.408 109.008 21.6 109.032 ;
    END
  END i[616]
  PIN i[617]
    DIRECTION INPUT ;
    USE SIGNAL ;
    PORT
      LAYER M4 ;
        RECT  21.408 109.152 21.6 109.176 ;
    END
  END i[617]
  PIN i[618]
    DIRECTION INPUT ;
    USE SIGNAL ;
    PORT
      LAYER M4 ;
        RECT  21.408 109.344 21.6 109.368 ;
    END
  END i[618]
  PIN i[619]
    DIRECTION INPUT ;
    USE SIGNAL ;
    PORT
      LAYER M4 ;
        RECT  21.408 109.488 21.6 109.512 ;
    END
  END i[619]
  PIN i[61]
    DIRECTION INPUT ;
    USE SIGNAL ;
    PORT
      LAYER M4 ;
        RECT  21.408 14.688 21.6 14.712 ;
    END
  END i[61]
  PIN i[620]
    DIRECTION INPUT ;
    USE SIGNAL ;
    PORT
      LAYER M4 ;
        RECT  21.408 109.68 21.6 109.704 ;
    END
  END i[620]
  PIN i[621]
    DIRECTION INPUT ;
    USE SIGNAL ;
    PORT
      LAYER M4 ;
        RECT  21.408 109.824 21.6 109.848 ;
    END
  END i[621]
  PIN i[622]
    DIRECTION INPUT ;
    USE SIGNAL ;
    PORT
      LAYER M4 ;
        RECT  21.408 110.016 21.6 110.04 ;
    END
  END i[622]
  PIN i[623]
    DIRECTION INPUT ;
    USE SIGNAL ;
    PORT
      LAYER M4 ;
        RECT  21.408 110.16 21.6 110.184 ;
    END
  END i[623]
  PIN i[62]
    DIRECTION INPUT ;
    USE SIGNAL ;
    PORT
      LAYER M4 ;
        RECT  21.408 14.832 21.6 14.856 ;
    END
  END i[62]
  PIN i[63]
    DIRECTION INPUT ;
    USE SIGNAL ;
    PORT
      LAYER M4 ;
        RECT  21.408 15.024 21.6 15.048 ;
    END
  END i[63]
  PIN i[64]
    DIRECTION INPUT ;
    USE SIGNAL ;
    PORT
      LAYER M4 ;
        RECT  21.408 15.168 21.6 15.192 ;
    END
  END i[64]
  PIN i[65]
    DIRECTION INPUT ;
    USE SIGNAL ;
    PORT
      LAYER M4 ;
        RECT  21.408 15.36 21.6 15.384 ;
    END
  END i[65]
  PIN i[66]
    DIRECTION INPUT ;
    USE SIGNAL ;
    PORT
      LAYER M4 ;
        RECT  21.408 15.504 21.6 15.528 ;
    END
  END i[66]
  PIN i[67]
    DIRECTION INPUT ;
    USE SIGNAL ;
    PORT
      LAYER M4 ;
        RECT  21.408 15.696 21.6 15.72 ;
    END
  END i[67]
  PIN i[68]
    DIRECTION INPUT ;
    USE SIGNAL ;
    PORT
      LAYER M4 ;
        RECT  21.408 15.888 21.6 15.912 ;
    END
  END i[68]
  PIN i[69]
    DIRECTION INPUT ;
    USE SIGNAL ;
    PORT
      LAYER M4 ;
        RECT  21.408 16.032 21.6 16.056 ;
    END
  END i[69]
  PIN i[6]
    DIRECTION INPUT ;
    USE SIGNAL ;
    PORT
      LAYER M4 ;
        RECT  21.408 5.328 21.6 5.352 ;
    END
  END i[6]
  PIN i[70]
    DIRECTION INPUT ;
    USE SIGNAL ;
    PORT
      LAYER M4 ;
        RECT  21.408 16.224 21.6 16.248 ;
    END
  END i[70]
  PIN i[71]
    DIRECTION INPUT ;
    USE SIGNAL ;
    PORT
      LAYER M4 ;
        RECT  21.408 16.368 21.6 16.392 ;
    END
  END i[71]
  PIN i[72]
    DIRECTION INPUT ;
    USE SIGNAL ;
    PORT
      LAYER M4 ;
        RECT  21.408 16.56 21.6 16.584 ;
    END
  END i[72]
  PIN i[73]
    DIRECTION INPUT ;
    USE SIGNAL ;
    PORT
      LAYER M4 ;
        RECT  21.408 16.704 21.6 16.728 ;
    END
  END i[73]
  PIN i[74]
    DIRECTION INPUT ;
    USE SIGNAL ;
    PORT
      LAYER M4 ;
        RECT  21.408 16.896 21.6 16.92 ;
    END
  END i[74]
  PIN i[75]
    DIRECTION INPUT ;
    USE SIGNAL ;
    PORT
      LAYER M4 ;
        RECT  21.408 17.04 21.6 17.064 ;
    END
  END i[75]
  PIN i[76]
    DIRECTION INPUT ;
    USE SIGNAL ;
    PORT
      LAYER M4 ;
        RECT  21.408 17.232 21.6 17.256 ;
    END
  END i[76]
  PIN i[77]
    DIRECTION INPUT ;
    USE SIGNAL ;
    PORT
      LAYER M4 ;
        RECT  21.408 17.376 21.6 17.4 ;
    END
  END i[77]
  PIN i[78]
    DIRECTION INPUT ;
    USE SIGNAL ;
    PORT
      LAYER M4 ;
        RECT  21.408 17.568 21.6 17.592 ;
    END
  END i[78]
  PIN i[79]
    DIRECTION INPUT ;
    USE SIGNAL ;
    PORT
      LAYER M4 ;
        RECT  21.408 17.712 21.6 17.736 ;
    END
  END i[79]
  PIN i[7]
    DIRECTION INPUT ;
    USE SIGNAL ;
    PORT
      LAYER M4 ;
        RECT  21.408 5.52 21.6 5.544 ;
    END
  END i[7]
  PIN i[80]
    DIRECTION INPUT ;
    USE SIGNAL ;
    PORT
      LAYER M4 ;
        RECT  21.408 17.904 21.6 17.928 ;
    END
  END i[80]
  PIN i[81]
    DIRECTION INPUT ;
    USE SIGNAL ;
    PORT
      LAYER M4 ;
        RECT  21.408 18.048 21.6 18.072 ;
    END
  END i[81]
  PIN i[82]
    DIRECTION INPUT ;
    USE SIGNAL ;
    PORT
      LAYER M4 ;
        RECT  21.408 18.24 21.6 18.264 ;
    END
  END i[82]
  PIN i[83]
    DIRECTION INPUT ;
    USE SIGNAL ;
    PORT
      LAYER M4 ;
        RECT  21.408 18.432 21.6 18.456 ;
    END
  END i[83]
  PIN i[84]
    DIRECTION INPUT ;
    USE SIGNAL ;
    PORT
      LAYER M4 ;
        RECT  21.408 18.576 21.6 18.6 ;
    END
  END i[84]
  PIN i[85]
    DIRECTION INPUT ;
    USE SIGNAL ;
    PORT
      LAYER M4 ;
        RECT  21.408 18.768 21.6 18.792 ;
    END
  END i[85]
  PIN i[86]
    DIRECTION INPUT ;
    USE SIGNAL ;
    PORT
      LAYER M4 ;
        RECT  21.408 18.912 21.6 18.936 ;
    END
  END i[86]
  PIN i[87]
    DIRECTION INPUT ;
    USE SIGNAL ;
    PORT
      LAYER M4 ;
        RECT  21.408 19.104 21.6 19.128 ;
    END
  END i[87]
  PIN i[88]
    DIRECTION INPUT ;
    USE SIGNAL ;
    PORT
      LAYER M4 ;
        RECT  21.408 19.248 21.6 19.272 ;
    END
  END i[88]
  PIN i[89]
    DIRECTION INPUT ;
    USE SIGNAL ;
    PORT
      LAYER M4 ;
        RECT  21.408 19.44 21.6 19.464 ;
    END
  END i[89]
  PIN i[8]
    DIRECTION INPUT ;
    USE SIGNAL ;
    PORT
      LAYER M4 ;
        RECT  21.408 5.712 21.6 5.736 ;
    END
  END i[8]
  PIN i[90]
    DIRECTION INPUT ;
    USE SIGNAL ;
    PORT
      LAYER M4 ;
        RECT  21.408 19.584 21.6 19.608 ;
    END
  END i[90]
  PIN i[91]
    DIRECTION INPUT ;
    USE SIGNAL ;
    PORT
      LAYER M4 ;
        RECT  21.408 19.776 21.6 19.8 ;
    END
  END i[91]
  PIN i[92]
    DIRECTION INPUT ;
    USE SIGNAL ;
    PORT
      LAYER M4 ;
        RECT  21.408 19.92 21.6 19.944 ;
    END
  END i[92]
  PIN i[93]
    DIRECTION INPUT ;
    USE SIGNAL ;
    PORT
      LAYER M4 ;
        RECT  21.408 20.112 21.6 20.136 ;
    END
  END i[93]
  PIN i[94]
    DIRECTION INPUT ;
    USE SIGNAL ;
    PORT
      LAYER M4 ;
        RECT  21.408 20.256 21.6 20.28 ;
    END
  END i[94]
  PIN i[95]
    DIRECTION INPUT ;
    USE SIGNAL ;
    PORT
      LAYER M4 ;
        RECT  21.408 20.448 21.6 20.472 ;
    END
  END i[95]
  PIN i[96]
    DIRECTION INPUT ;
    USE SIGNAL ;
    PORT
      LAYER M4 ;
        RECT  21.408 20.592 21.6 20.616 ;
    END
  END i[96]
  PIN i[97]
    DIRECTION INPUT ;
    USE SIGNAL ;
    PORT
      LAYER M4 ;
        RECT  21.408 20.784 21.6 20.808 ;
    END
  END i[97]
  PIN i[98]
    DIRECTION INPUT ;
    USE SIGNAL ;
    PORT
      LAYER M4 ;
        RECT  21.408 20.976 21.6 21 ;
    END
  END i[98]
  PIN i[99]
    DIRECTION INPUT ;
    USE SIGNAL ;
    PORT
      LAYER M4 ;
        RECT  21.408 21.12 21.6 21.144 ;
    END
  END i[99]
  PIN i[9]
    DIRECTION INPUT ;
    USE SIGNAL ;
    PORT
      LAYER M4 ;
        RECT  21.408 5.856 21.6 5.88 ;
    END
  END i[9]
  PIN o[0]
    DIRECTION OUTPUT ;
    USE SIGNAL ;
    PORT
      LAYER M4 ;
        RECT  0 4.32 0.192 4.344 ;
    END
  END o[0]
  PIN o[100]
    DIRECTION OUTPUT ;
    USE SIGNAL ;
    PORT
      LAYER M4 ;
        RECT  0 21.312 0.192 21.336 ;
    END
  END o[100]
  PIN o[101]
    DIRECTION OUTPUT ;
    USE SIGNAL ;
    PORT
      LAYER M4 ;
        RECT  0 21.456 0.192 21.48 ;
    END
  END o[101]
  PIN o[102]
    DIRECTION OUTPUT ;
    USE SIGNAL ;
    PORT
      LAYER M4 ;
        RECT  0 21.648 0.192 21.672 ;
    END
  END o[102]
  PIN o[103]
    DIRECTION OUTPUT ;
    USE SIGNAL ;
    PORT
      LAYER M4 ;
        RECT  0 21.792 0.192 21.816 ;
    END
  END o[103]
  PIN o[104]
    DIRECTION OUTPUT ;
    USE SIGNAL ;
    PORT
      LAYER M4 ;
        RECT  0 21.984 0.192 22.008 ;
    END
  END o[104]
  PIN o[105]
    DIRECTION OUTPUT ;
    USE SIGNAL ;
    PORT
      LAYER M4 ;
        RECT  0 22.128 0.192 22.152 ;
    END
  END o[105]
  PIN o[106]
    DIRECTION OUTPUT ;
    USE SIGNAL ;
    PORT
      LAYER M4 ;
        RECT  0 22.32 0.192 22.344 ;
    END
  END o[106]
  PIN o[107]
    DIRECTION OUTPUT ;
    USE SIGNAL ;
    PORT
      LAYER M4 ;
        RECT  0 22.464 0.192 22.488 ;
    END
  END o[107]
  PIN o[108]
    DIRECTION OUTPUT ;
    USE SIGNAL ;
    PORT
      LAYER M4 ;
        RECT  0 22.656 0.192 22.68 ;
    END
  END o[108]
  PIN o[109]
    DIRECTION OUTPUT ;
    USE SIGNAL ;
    PORT
      LAYER M4 ;
        RECT  0 22.8 0.192 22.824 ;
    END
  END o[109]
  PIN o[10]
    DIRECTION OUTPUT ;
    USE SIGNAL ;
    PORT
      LAYER M4 ;
        RECT  0 6.048 0.192 6.072 ;
    END
  END o[10]
  PIN o[110]
    DIRECTION OUTPUT ;
    USE SIGNAL ;
    PORT
      LAYER M4 ;
        RECT  0 22.992 0.192 23.016 ;
    END
  END o[110]
  PIN o[111]
    DIRECTION OUTPUT ;
    USE SIGNAL ;
    PORT
      LAYER M4 ;
        RECT  0 23.136 0.192 23.16 ;
    END
  END o[111]
  PIN o[112]
    DIRECTION OUTPUT ;
    USE SIGNAL ;
    PORT
      LAYER M4 ;
        RECT  0 23.328 0.192 23.352 ;
    END
  END o[112]
  PIN o[113]
    DIRECTION OUTPUT ;
    USE SIGNAL ;
    PORT
      LAYER M4 ;
        RECT  0 23.52 0.192 23.544 ;
    END
  END o[113]
  PIN o[114]
    DIRECTION OUTPUT ;
    USE SIGNAL ;
    PORT
      LAYER M4 ;
        RECT  0 23.664 0.192 23.688 ;
    END
  END o[114]
  PIN o[115]
    DIRECTION OUTPUT ;
    USE SIGNAL ;
    PORT
      LAYER M4 ;
        RECT  0 23.856 0.192 23.88 ;
    END
  END o[115]
  PIN o[116]
    DIRECTION OUTPUT ;
    USE SIGNAL ;
    PORT
      LAYER M4 ;
        RECT  0 24 0.192 24.024 ;
    END
  END o[116]
  PIN o[117]
    DIRECTION OUTPUT ;
    USE SIGNAL ;
    PORT
      LAYER M4 ;
        RECT  0 24.192 0.192 24.216 ;
    END
  END o[117]
  PIN o[118]
    DIRECTION OUTPUT ;
    USE SIGNAL ;
    PORT
      LAYER M4 ;
        RECT  0 24.336 0.192 24.36 ;
    END
  END o[118]
  PIN o[119]
    DIRECTION OUTPUT ;
    USE SIGNAL ;
    PORT
      LAYER M4 ;
        RECT  0 24.528 0.192 24.552 ;
    END
  END o[119]
  PIN o[11]
    DIRECTION OUTPUT ;
    USE SIGNAL ;
    PORT
      LAYER M4 ;
        RECT  0 6.192 0.192 6.216 ;
    END
  END o[11]
  PIN o[120]
    DIRECTION OUTPUT ;
    USE SIGNAL ;
    PORT
      LAYER M4 ;
        RECT  0 24.672 0.192 24.696 ;
    END
  END o[120]
  PIN o[121]
    DIRECTION OUTPUT ;
    USE SIGNAL ;
    PORT
      LAYER M4 ;
        RECT  0 24.864 0.192 24.888 ;
    END
  END o[121]
  PIN o[122]
    DIRECTION OUTPUT ;
    USE SIGNAL ;
    PORT
      LAYER M4 ;
        RECT  0 25.008 0.192 25.032 ;
    END
  END o[122]
  PIN o[123]
    DIRECTION OUTPUT ;
    USE SIGNAL ;
    PORT
      LAYER M4 ;
        RECT  0 25.2 0.192 25.224 ;
    END
  END o[123]
  PIN o[124]
    DIRECTION OUTPUT ;
    USE SIGNAL ;
    PORT
      LAYER M4 ;
        RECT  0 25.344 0.192 25.368 ;
    END
  END o[124]
  PIN o[125]
    DIRECTION OUTPUT ;
    USE SIGNAL ;
    PORT
      LAYER M4 ;
        RECT  0 25.536 0.192 25.56 ;
    END
  END o[125]
  PIN o[126]
    DIRECTION OUTPUT ;
    USE SIGNAL ;
    PORT
      LAYER M4 ;
        RECT  0 25.68 0.192 25.704 ;
    END
  END o[126]
  PIN o[127]
    DIRECTION OUTPUT ;
    USE SIGNAL ;
    PORT
      LAYER M4 ;
        RECT  0 25.872 0.192 25.896 ;
    END
  END o[127]
  PIN o[128]
    DIRECTION OUTPUT ;
    USE SIGNAL ;
    PORT
      LAYER M4 ;
        RECT  0 26.064 0.192 26.088 ;
    END
  END o[128]
  PIN o[129]
    DIRECTION OUTPUT ;
    USE SIGNAL ;
    PORT
      LAYER M4 ;
        RECT  0 26.208 0.192 26.232 ;
    END
  END o[129]
  PIN o[12]
    DIRECTION OUTPUT ;
    USE SIGNAL ;
    PORT
      LAYER M4 ;
        RECT  0 6.384 0.192 6.408 ;
    END
  END o[12]
  PIN o[130]
    DIRECTION OUTPUT ;
    USE SIGNAL ;
    PORT
      LAYER M4 ;
        RECT  0 26.4 0.192 26.424 ;
    END
  END o[130]
  PIN o[131]
    DIRECTION OUTPUT ;
    USE SIGNAL ;
    PORT
      LAYER M4 ;
        RECT  0 26.544 0.192 26.568 ;
    END
  END o[131]
  PIN o[132]
    DIRECTION OUTPUT ;
    USE SIGNAL ;
    PORT
      LAYER M4 ;
        RECT  0 26.736 0.192 26.76 ;
    END
  END o[132]
  PIN o[133]
    DIRECTION OUTPUT ;
    USE SIGNAL ;
    PORT
      LAYER M4 ;
        RECT  0 26.88 0.192 26.904 ;
    END
  END o[133]
  PIN o[134]
    DIRECTION OUTPUT ;
    USE SIGNAL ;
    PORT
      LAYER M4 ;
        RECT  0 27.072 0.192 27.096 ;
    END
  END o[134]
  PIN o[135]
    DIRECTION OUTPUT ;
    USE SIGNAL ;
    PORT
      LAYER M4 ;
        RECT  0 27.216 0.192 27.24 ;
    END
  END o[135]
  PIN o[136]
    DIRECTION OUTPUT ;
    USE SIGNAL ;
    PORT
      LAYER M4 ;
        RECT  0 27.408 0.192 27.432 ;
    END
  END o[136]
  PIN o[137]
    DIRECTION OUTPUT ;
    USE SIGNAL ;
    PORT
      LAYER M4 ;
        RECT  0 27.552 0.192 27.576 ;
    END
  END o[137]
  PIN o[138]
    DIRECTION OUTPUT ;
    USE SIGNAL ;
    PORT
      LAYER M4 ;
        RECT  0 27.744 0.192 27.768 ;
    END
  END o[138]
  PIN o[139]
    DIRECTION OUTPUT ;
    USE SIGNAL ;
    PORT
      LAYER M4 ;
        RECT  0 27.888 0.192 27.912 ;
    END
  END o[139]
  PIN o[13]
    DIRECTION OUTPUT ;
    USE SIGNAL ;
    PORT
      LAYER M4 ;
        RECT  0 6.528 0.192 6.552 ;
    END
  END o[13]
  PIN o[140]
    DIRECTION OUTPUT ;
    USE SIGNAL ;
    PORT
      LAYER M4 ;
        RECT  0 28.08 0.192 28.104 ;
    END
  END o[140]
  PIN o[141]
    DIRECTION OUTPUT ;
    USE SIGNAL ;
    PORT
      LAYER M4 ;
        RECT  0 28.224 0.192 28.248 ;
    END
  END o[141]
  PIN o[142]
    DIRECTION OUTPUT ;
    USE SIGNAL ;
    PORT
      LAYER M4 ;
        RECT  0 28.416 0.192 28.44 ;
    END
  END o[142]
  PIN o[143]
    DIRECTION OUTPUT ;
    USE SIGNAL ;
    PORT
      LAYER M4 ;
        RECT  0 28.608 0.192 28.632 ;
    END
  END o[143]
  PIN o[144]
    DIRECTION OUTPUT ;
    USE SIGNAL ;
    PORT
      LAYER M4 ;
        RECT  0 28.752 0.192 28.776 ;
    END
  END o[144]
  PIN o[145]
    DIRECTION OUTPUT ;
    USE SIGNAL ;
    PORT
      LAYER M4 ;
        RECT  0 28.944 0.192 28.968 ;
    END
  END o[145]
  PIN o[146]
    DIRECTION OUTPUT ;
    USE SIGNAL ;
    PORT
      LAYER M4 ;
        RECT  0 29.088 0.192 29.112 ;
    END
  END o[146]
  PIN o[147]
    DIRECTION OUTPUT ;
    USE SIGNAL ;
    PORT
      LAYER M4 ;
        RECT  0 29.28 0.192 29.304 ;
    END
  END o[147]
  PIN o[148]
    DIRECTION OUTPUT ;
    USE SIGNAL ;
    PORT
      LAYER M4 ;
        RECT  0 29.424 0.192 29.448 ;
    END
  END o[148]
  PIN o[149]
    DIRECTION OUTPUT ;
    USE SIGNAL ;
    PORT
      LAYER M4 ;
        RECT  0 29.616 0.192 29.64 ;
    END
  END o[149]
  PIN o[14]
    DIRECTION OUTPUT ;
    USE SIGNAL ;
    PORT
      LAYER M4 ;
        RECT  0 6.72 0.192 6.744 ;
    END
  END o[14]
  PIN o[150]
    DIRECTION OUTPUT ;
    USE SIGNAL ;
    PORT
      LAYER M4 ;
        RECT  0 29.76 0.192 29.784 ;
    END
  END o[150]
  PIN o[151]
    DIRECTION OUTPUT ;
    USE SIGNAL ;
    PORT
      LAYER M4 ;
        RECT  0 29.952 0.192 29.976 ;
    END
  END o[151]
  PIN o[152]
    DIRECTION OUTPUT ;
    USE SIGNAL ;
    PORT
      LAYER M4 ;
        RECT  0 30.096 0.192 30.12 ;
    END
  END o[152]
  PIN o[153]
    DIRECTION OUTPUT ;
    USE SIGNAL ;
    PORT
      LAYER M4 ;
        RECT  0 30.288 0.192 30.312 ;
    END
  END o[153]
  PIN o[154]
    DIRECTION OUTPUT ;
    USE SIGNAL ;
    PORT
      LAYER M4 ;
        RECT  0 30.432 0.192 30.456 ;
    END
  END o[154]
  PIN o[155]
    DIRECTION OUTPUT ;
    USE SIGNAL ;
    PORT
      LAYER M4 ;
        RECT  0 30.624 0.192 30.648 ;
    END
  END o[155]
  PIN o[156]
    DIRECTION OUTPUT ;
    USE SIGNAL ;
    PORT
      LAYER M4 ;
        RECT  0 30.768 0.192 30.792 ;
    END
  END o[156]
  PIN o[157]
    DIRECTION OUTPUT ;
    USE SIGNAL ;
    PORT
      LAYER M4 ;
        RECT  0 30.96 0.192 30.984 ;
    END
  END o[157]
  PIN o[158]
    DIRECTION OUTPUT ;
    USE SIGNAL ;
    PORT
      LAYER M4 ;
        RECT  0 31.152 0.192 31.176 ;
    END
  END o[158]
  PIN o[159]
    DIRECTION OUTPUT ;
    USE SIGNAL ;
    PORT
      LAYER M4 ;
        RECT  0 31.296 0.192 31.32 ;
    END
  END o[159]
  PIN o[15]
    DIRECTION OUTPUT ;
    USE SIGNAL ;
    PORT
      LAYER M4 ;
        RECT  0 6.864 0.192 6.888 ;
    END
  END o[15]
  PIN o[160]
    DIRECTION OUTPUT ;
    USE SIGNAL ;
    PORT
      LAYER M4 ;
        RECT  0 31.488 0.192 31.512 ;
    END
  END o[160]
  PIN o[161]
    DIRECTION OUTPUT ;
    USE SIGNAL ;
    PORT
      LAYER M4 ;
        RECT  0 31.632 0.192 31.656 ;
    END
  END o[161]
  PIN o[162]
    DIRECTION OUTPUT ;
    USE SIGNAL ;
    PORT
      LAYER M4 ;
        RECT  0 31.824 0.192 31.848 ;
    END
  END o[162]
  PIN o[163]
    DIRECTION OUTPUT ;
    USE SIGNAL ;
    PORT
      LAYER M4 ;
        RECT  0 31.968 0.192 31.992 ;
    END
  END o[163]
  PIN o[164]
    DIRECTION OUTPUT ;
    USE SIGNAL ;
    PORT
      LAYER M4 ;
        RECT  0 32.16 0.192 32.184 ;
    END
  END o[164]
  PIN o[165]
    DIRECTION OUTPUT ;
    USE SIGNAL ;
    PORT
      LAYER M4 ;
        RECT  0 32.304 0.192 32.328 ;
    END
  END o[165]
  PIN o[166]
    DIRECTION OUTPUT ;
    USE SIGNAL ;
    PORT
      LAYER M4 ;
        RECT  0 32.496 0.192 32.52 ;
    END
  END o[166]
  PIN o[167]
    DIRECTION OUTPUT ;
    USE SIGNAL ;
    PORT
      LAYER M4 ;
        RECT  0 32.64 0.192 32.664 ;
    END
  END o[167]
  PIN o[168]
    DIRECTION OUTPUT ;
    USE SIGNAL ;
    PORT
      LAYER M4 ;
        RECT  0 32.832 0.192 32.856 ;
    END
  END o[168]
  PIN o[169]
    DIRECTION OUTPUT ;
    USE SIGNAL ;
    PORT
      LAYER M4 ;
        RECT  0 32.976 0.192 33 ;
    END
  END o[169]
  PIN o[16]
    DIRECTION OUTPUT ;
    USE SIGNAL ;
    PORT
      LAYER M4 ;
        RECT  0 7.056 0.192 7.08 ;
    END
  END o[16]
  PIN o[170]
    DIRECTION OUTPUT ;
    USE SIGNAL ;
    PORT
      LAYER M4 ;
        RECT  0 33.168 0.192 33.192 ;
    END
  END o[170]
  PIN o[171]
    DIRECTION OUTPUT ;
    USE SIGNAL ;
    PORT
      LAYER M4 ;
        RECT  0 33.36 0.192 33.384 ;
    END
  END o[171]
  PIN o[172]
    DIRECTION OUTPUT ;
    USE SIGNAL ;
    PORT
      LAYER M4 ;
        RECT  0 33.504 0.192 33.528 ;
    END
  END o[172]
  PIN o[173]
    DIRECTION OUTPUT ;
    USE SIGNAL ;
    PORT
      LAYER M4 ;
        RECT  0 33.696 0.192 33.72 ;
    END
  END o[173]
  PIN o[174]
    DIRECTION OUTPUT ;
    USE SIGNAL ;
    PORT
      LAYER M4 ;
        RECT  0 33.84 0.192 33.864 ;
    END
  END o[174]
  PIN o[175]
    DIRECTION OUTPUT ;
    USE SIGNAL ;
    PORT
      LAYER M4 ;
        RECT  0 34.032 0.192 34.056 ;
    END
  END o[175]
  PIN o[176]
    DIRECTION OUTPUT ;
    USE SIGNAL ;
    PORT
      LAYER M4 ;
        RECT  0 34.176 0.192 34.2 ;
    END
  END o[176]
  PIN o[177]
    DIRECTION OUTPUT ;
    USE SIGNAL ;
    PORT
      LAYER M4 ;
        RECT  0 34.368 0.192 34.392 ;
    END
  END o[177]
  PIN o[178]
    DIRECTION OUTPUT ;
    USE SIGNAL ;
    PORT
      LAYER M4 ;
        RECT  0 34.512 0.192 34.536 ;
    END
  END o[178]
  PIN o[179]
    DIRECTION OUTPUT ;
    USE SIGNAL ;
    PORT
      LAYER M4 ;
        RECT  0 34.704 0.192 34.728 ;
    END
  END o[179]
  PIN o[17]
    DIRECTION OUTPUT ;
    USE SIGNAL ;
    PORT
      LAYER M4 ;
        RECT  0 7.2 0.192 7.224 ;
    END
  END o[17]
  PIN o[180]
    DIRECTION OUTPUT ;
    USE SIGNAL ;
    PORT
      LAYER M4 ;
        RECT  0 34.848 0.192 34.872 ;
    END
  END o[180]
  PIN o[181]
    DIRECTION OUTPUT ;
    USE SIGNAL ;
    PORT
      LAYER M4 ;
        RECT  0 35.04 0.192 35.064 ;
    END
  END o[181]
  PIN o[182]
    DIRECTION OUTPUT ;
    USE SIGNAL ;
    PORT
      LAYER M4 ;
        RECT  0 35.184 0.192 35.208 ;
    END
  END o[182]
  PIN o[183]
    DIRECTION OUTPUT ;
    USE SIGNAL ;
    PORT
      LAYER M4 ;
        RECT  0 35.376 0.192 35.4 ;
    END
  END o[183]
  PIN o[184]
    DIRECTION OUTPUT ;
    USE SIGNAL ;
    PORT
      LAYER M4 ;
        RECT  0 35.52 0.192 35.544 ;
    END
  END o[184]
  PIN o[185]
    DIRECTION OUTPUT ;
    USE SIGNAL ;
    PORT
      LAYER M4 ;
        RECT  0 35.712 0.192 35.736 ;
    END
  END o[185]
  PIN o[186]
    DIRECTION OUTPUT ;
    USE SIGNAL ;
    PORT
      LAYER M4 ;
        RECT  0 35.904 0.192 35.928 ;
    END
  END o[186]
  PIN o[187]
    DIRECTION OUTPUT ;
    USE SIGNAL ;
    PORT
      LAYER M4 ;
        RECT  0 36.048 0.192 36.072 ;
    END
  END o[187]
  PIN o[188]
    DIRECTION OUTPUT ;
    USE SIGNAL ;
    PORT
      LAYER M4 ;
        RECT  0 36.24 0.192 36.264 ;
    END
  END o[188]
  PIN o[189]
    DIRECTION OUTPUT ;
    USE SIGNAL ;
    PORT
      LAYER M4 ;
        RECT  0 36.384 0.192 36.408 ;
    END
  END o[189]
  PIN o[18]
    DIRECTION OUTPUT ;
    USE SIGNAL ;
    PORT
      LAYER M4 ;
        RECT  0 7.392 0.192 7.416 ;
    END
  END o[18]
  PIN o[190]
    DIRECTION OUTPUT ;
    USE SIGNAL ;
    PORT
      LAYER M4 ;
        RECT  0 36.576 0.192 36.6 ;
    END
  END o[190]
  PIN o[191]
    DIRECTION OUTPUT ;
    USE SIGNAL ;
    PORT
      LAYER M4 ;
        RECT  0 36.72 0.192 36.744 ;
    END
  END o[191]
  PIN o[192]
    DIRECTION OUTPUT ;
    USE SIGNAL ;
    PORT
      LAYER M4 ;
        RECT  0 36.912 0.192 36.936 ;
    END
  END o[192]
  PIN o[193]
    DIRECTION OUTPUT ;
    USE SIGNAL ;
    PORT
      LAYER M4 ;
        RECT  0 37.056 0.192 37.08 ;
    END
  END o[193]
  PIN o[194]
    DIRECTION OUTPUT ;
    USE SIGNAL ;
    PORT
      LAYER M4 ;
        RECT  0 37.248 0.192 37.272 ;
    END
  END o[194]
  PIN o[195]
    DIRECTION OUTPUT ;
    USE SIGNAL ;
    PORT
      LAYER M4 ;
        RECT  0 37.392 0.192 37.416 ;
    END
  END o[195]
  PIN o[196]
    DIRECTION OUTPUT ;
    USE SIGNAL ;
    PORT
      LAYER M4 ;
        RECT  0 37.584 0.192 37.608 ;
    END
  END o[196]
  PIN o[197]
    DIRECTION OUTPUT ;
    USE SIGNAL ;
    PORT
      LAYER M4 ;
        RECT  0 37.728 0.192 37.752 ;
    END
  END o[197]
  PIN o[198]
    DIRECTION OUTPUT ;
    USE SIGNAL ;
    PORT
      LAYER M4 ;
        RECT  0 37.92 0.192 37.944 ;
    END
  END o[198]
  PIN o[199]
    DIRECTION OUTPUT ;
    USE SIGNAL ;
    PORT
      LAYER M4 ;
        RECT  0 38.064 0.192 38.088 ;
    END
  END o[199]
  PIN o[19]
    DIRECTION OUTPUT ;
    USE SIGNAL ;
    PORT
      LAYER M4 ;
        RECT  0 7.536 0.192 7.56 ;
    END
  END o[19]
  PIN o[1]
    DIRECTION OUTPUT ;
    USE SIGNAL ;
    PORT
      LAYER M4 ;
        RECT  0 4.512 0.192 4.536 ;
    END
  END o[1]
  PIN o[200]
    DIRECTION OUTPUT ;
    USE SIGNAL ;
    PORT
      LAYER M4 ;
        RECT  0 38.256 0.192 38.28 ;
    END
  END o[200]
  PIN o[201]
    DIRECTION OUTPUT ;
    USE SIGNAL ;
    PORT
      LAYER M4 ;
        RECT  0 38.448 0.192 38.472 ;
    END
  END o[201]
  PIN o[202]
    DIRECTION OUTPUT ;
    USE SIGNAL ;
    PORT
      LAYER M4 ;
        RECT  0 38.592 0.192 38.616 ;
    END
  END o[202]
  PIN o[203]
    DIRECTION OUTPUT ;
    USE SIGNAL ;
    PORT
      LAYER M4 ;
        RECT  0 38.784 0.192 38.808 ;
    END
  END o[203]
  PIN o[204]
    DIRECTION OUTPUT ;
    USE SIGNAL ;
    PORT
      LAYER M4 ;
        RECT  0 38.928 0.192 38.952 ;
    END
  END o[204]
  PIN o[205]
    DIRECTION OUTPUT ;
    USE SIGNAL ;
    PORT
      LAYER M4 ;
        RECT  0 39.12 0.192 39.144 ;
    END
  END o[205]
  PIN o[206]
    DIRECTION OUTPUT ;
    USE SIGNAL ;
    PORT
      LAYER M4 ;
        RECT  0 39.264 0.192 39.288 ;
    END
  END o[206]
  PIN o[207]
    DIRECTION OUTPUT ;
    USE SIGNAL ;
    PORT
      LAYER M4 ;
        RECT  0 39.456 0.192 39.48 ;
    END
  END o[207]
  PIN o[208]
    DIRECTION OUTPUT ;
    USE SIGNAL ;
    PORT
      LAYER M4 ;
        RECT  0 39.6 0.192 39.624 ;
    END
  END o[208]
  PIN o[209]
    DIRECTION OUTPUT ;
    USE SIGNAL ;
    PORT
      LAYER M4 ;
        RECT  0 39.792 0.192 39.816 ;
    END
  END o[209]
  PIN o[20]
    DIRECTION OUTPUT ;
    USE SIGNAL ;
    PORT
      LAYER M4 ;
        RECT  0 7.728 0.192 7.752 ;
    END
  END o[20]
  PIN o[210]
    DIRECTION OUTPUT ;
    USE SIGNAL ;
    PORT
      LAYER M4 ;
        RECT  0 39.936 0.192 39.96 ;
    END
  END o[210]
  PIN o[211]
    DIRECTION OUTPUT ;
    USE SIGNAL ;
    PORT
      LAYER M4 ;
        RECT  0 40.128 0.192 40.152 ;
    END
  END o[211]
  PIN o[212]
    DIRECTION OUTPUT ;
    USE SIGNAL ;
    PORT
      LAYER M4 ;
        RECT  0 40.272 0.192 40.296 ;
    END
  END o[212]
  PIN o[213]
    DIRECTION OUTPUT ;
    USE SIGNAL ;
    PORT
      LAYER M4 ;
        RECT  0 40.464 0.192 40.488 ;
    END
  END o[213]
  PIN o[214]
    DIRECTION OUTPUT ;
    USE SIGNAL ;
    PORT
      LAYER M4 ;
        RECT  0 40.608 0.192 40.632 ;
    END
  END o[214]
  PIN o[215]
    DIRECTION OUTPUT ;
    USE SIGNAL ;
    PORT
      LAYER M4 ;
        RECT  0 40.8 0.192 40.824 ;
    END
  END o[215]
  PIN o[216]
    DIRECTION OUTPUT ;
    USE SIGNAL ;
    PORT
      LAYER M4 ;
        RECT  0 40.992 0.192 41.016 ;
    END
  END o[216]
  PIN o[217]
    DIRECTION OUTPUT ;
    USE SIGNAL ;
    PORT
      LAYER M4 ;
        RECT  0 41.136 0.192 41.16 ;
    END
  END o[217]
  PIN o[218]
    DIRECTION OUTPUT ;
    USE SIGNAL ;
    PORT
      LAYER M4 ;
        RECT  0 41.328 0.192 41.352 ;
    END
  END o[218]
  PIN o[219]
    DIRECTION OUTPUT ;
    USE SIGNAL ;
    PORT
      LAYER M4 ;
        RECT  0 41.472 0.192 41.496 ;
    END
  END o[219]
  PIN o[21]
    DIRECTION OUTPUT ;
    USE SIGNAL ;
    PORT
      LAYER M4 ;
        RECT  0 7.872 0.192 7.896 ;
    END
  END o[21]
  PIN o[220]
    DIRECTION OUTPUT ;
    USE SIGNAL ;
    PORT
      LAYER M4 ;
        RECT  0 41.664 0.192 41.688 ;
    END
  END o[220]
  PIN o[221]
    DIRECTION OUTPUT ;
    USE SIGNAL ;
    PORT
      LAYER M4 ;
        RECT  0 41.808 0.192 41.832 ;
    END
  END o[221]
  PIN o[222]
    DIRECTION OUTPUT ;
    USE SIGNAL ;
    PORT
      LAYER M4 ;
        RECT  0 42 0.192 42.024 ;
    END
  END o[222]
  PIN o[223]
    DIRECTION OUTPUT ;
    USE SIGNAL ;
    PORT
      LAYER M4 ;
        RECT  0 42.144 0.192 42.168 ;
    END
  END o[223]
  PIN o[224]
    DIRECTION OUTPUT ;
    USE SIGNAL ;
    PORT
      LAYER M4 ;
        RECT  0 42.336 0.192 42.36 ;
    END
  END o[224]
  PIN o[225]
    DIRECTION OUTPUT ;
    USE SIGNAL ;
    PORT
      LAYER M4 ;
        RECT  0 42.48 0.192 42.504 ;
    END
  END o[225]
  PIN o[226]
    DIRECTION OUTPUT ;
    USE SIGNAL ;
    PORT
      LAYER M4 ;
        RECT  0 42.672 0.192 42.696 ;
    END
  END o[226]
  PIN o[227]
    DIRECTION OUTPUT ;
    USE SIGNAL ;
    PORT
      LAYER M4 ;
        RECT  0 42.816 0.192 42.84 ;
    END
  END o[227]
  PIN o[228]
    DIRECTION OUTPUT ;
    USE SIGNAL ;
    PORT
      LAYER M4 ;
        RECT  0 43.008 0.192 43.032 ;
    END
  END o[228]
  PIN o[229]
    DIRECTION OUTPUT ;
    USE SIGNAL ;
    PORT
      LAYER M4 ;
        RECT  0 43.152 0.192 43.176 ;
    END
  END o[229]
  PIN o[22]
    DIRECTION OUTPUT ;
    USE SIGNAL ;
    PORT
      LAYER M4 ;
        RECT  0 8.064 0.192 8.088 ;
    END
  END o[22]
  PIN o[230]
    DIRECTION OUTPUT ;
    USE SIGNAL ;
    PORT
      LAYER M4 ;
        RECT  0 43.344 0.192 43.368 ;
    END
  END o[230]
  PIN o[231]
    DIRECTION OUTPUT ;
    USE SIGNAL ;
    PORT
      LAYER M4 ;
        RECT  0 43.536 0.192 43.56 ;
    END
  END o[231]
  PIN o[232]
    DIRECTION OUTPUT ;
    USE SIGNAL ;
    PORT
      LAYER M4 ;
        RECT  0 43.68 0.192 43.704 ;
    END
  END o[232]
  PIN o[233]
    DIRECTION OUTPUT ;
    USE SIGNAL ;
    PORT
      LAYER M4 ;
        RECT  0 43.872 0.192 43.896 ;
    END
  END o[233]
  PIN o[234]
    DIRECTION OUTPUT ;
    USE SIGNAL ;
    PORT
      LAYER M4 ;
        RECT  0 44.016 0.192 44.04 ;
    END
  END o[234]
  PIN o[235]
    DIRECTION OUTPUT ;
    USE SIGNAL ;
    PORT
      LAYER M4 ;
        RECT  0 44.208 0.192 44.232 ;
    END
  END o[235]
  PIN o[236]
    DIRECTION OUTPUT ;
    USE SIGNAL ;
    PORT
      LAYER M4 ;
        RECT  0 44.352 0.192 44.376 ;
    END
  END o[236]
  PIN o[237]
    DIRECTION OUTPUT ;
    USE SIGNAL ;
    PORT
      LAYER M4 ;
        RECT  0 44.544 0.192 44.568 ;
    END
  END o[237]
  PIN o[238]
    DIRECTION OUTPUT ;
    USE SIGNAL ;
    PORT
      LAYER M4 ;
        RECT  0 44.688 0.192 44.712 ;
    END
  END o[238]
  PIN o[239]
    DIRECTION OUTPUT ;
    USE SIGNAL ;
    PORT
      LAYER M4 ;
        RECT  0 44.88 0.192 44.904 ;
    END
  END o[239]
  PIN o[23]
    DIRECTION OUTPUT ;
    USE SIGNAL ;
    PORT
      LAYER M4 ;
        RECT  0 8.256 0.192 8.28 ;
    END
  END o[23]
  PIN o[240]
    DIRECTION OUTPUT ;
    USE SIGNAL ;
    PORT
      LAYER M4 ;
        RECT  0 45.024 0.192 45.048 ;
    END
  END o[240]
  PIN o[241]
    DIRECTION OUTPUT ;
    USE SIGNAL ;
    PORT
      LAYER M4 ;
        RECT  0 45.216 0.192 45.24 ;
    END
  END o[241]
  PIN o[242]
    DIRECTION OUTPUT ;
    USE SIGNAL ;
    PORT
      LAYER M4 ;
        RECT  0 45.36 0.192 45.384 ;
    END
  END o[242]
  PIN o[243]
    DIRECTION OUTPUT ;
    USE SIGNAL ;
    PORT
      LAYER M4 ;
        RECT  0 45.552 0.192 45.576 ;
    END
  END o[243]
  PIN o[244]
    DIRECTION OUTPUT ;
    USE SIGNAL ;
    PORT
      LAYER M4 ;
        RECT  0 45.696 0.192 45.72 ;
    END
  END o[244]
  PIN o[245]
    DIRECTION OUTPUT ;
    USE SIGNAL ;
    PORT
      LAYER M4 ;
        RECT  0 45.888 0.192 45.912 ;
    END
  END o[245]
  PIN o[246]
    DIRECTION OUTPUT ;
    USE SIGNAL ;
    PORT
      LAYER M4 ;
        RECT  0 46.08 0.192 46.104 ;
    END
  END o[246]
  PIN o[247]
    DIRECTION OUTPUT ;
    USE SIGNAL ;
    PORT
      LAYER M4 ;
        RECT  0 46.224 0.192 46.248 ;
    END
  END o[247]
  PIN o[248]
    DIRECTION OUTPUT ;
    USE SIGNAL ;
    PORT
      LAYER M4 ;
        RECT  0 46.416 0.192 46.44 ;
    END
  END o[248]
  PIN o[249]
    DIRECTION OUTPUT ;
    USE SIGNAL ;
    PORT
      LAYER M4 ;
        RECT  0 46.56 0.192 46.584 ;
    END
  END o[249]
  PIN o[24]
    DIRECTION OUTPUT ;
    USE SIGNAL ;
    PORT
      LAYER M4 ;
        RECT  0 8.4 0.192 8.424 ;
    END
  END o[24]
  PIN o[250]
    DIRECTION OUTPUT ;
    USE SIGNAL ;
    PORT
      LAYER M4 ;
        RECT  0 46.752 0.192 46.776 ;
    END
  END o[250]
  PIN o[251]
    DIRECTION OUTPUT ;
    USE SIGNAL ;
    PORT
      LAYER M4 ;
        RECT  0 46.896 0.192 46.92 ;
    END
  END o[251]
  PIN o[252]
    DIRECTION OUTPUT ;
    USE SIGNAL ;
    PORT
      LAYER M4 ;
        RECT  0 47.088 0.192 47.112 ;
    END
  END o[252]
  PIN o[253]
    DIRECTION OUTPUT ;
    USE SIGNAL ;
    PORT
      LAYER M4 ;
        RECT  0 47.232 0.192 47.256 ;
    END
  END o[253]
  PIN o[254]
    DIRECTION OUTPUT ;
    USE SIGNAL ;
    PORT
      LAYER M4 ;
        RECT  0 47.424 0.192 47.448 ;
    END
  END o[254]
  PIN o[255]
    DIRECTION OUTPUT ;
    USE SIGNAL ;
    PORT
      LAYER M4 ;
        RECT  0 47.568 0.192 47.592 ;
    END
  END o[255]
  PIN o[256]
    DIRECTION OUTPUT ;
    USE SIGNAL ;
    PORT
      LAYER M4 ;
        RECT  0 47.76 0.192 47.784 ;
    END
  END o[256]
  PIN o[257]
    DIRECTION OUTPUT ;
    USE SIGNAL ;
    PORT
      LAYER M4 ;
        RECT  0 47.904 0.192 47.928 ;
    END
  END o[257]
  PIN o[258]
    DIRECTION OUTPUT ;
    USE SIGNAL ;
    PORT
      LAYER M4 ;
        RECT  0 48.096 0.192 48.12 ;
    END
  END o[258]
  PIN o[259]
    DIRECTION OUTPUT ;
    USE SIGNAL ;
    PORT
      LAYER M4 ;
        RECT  0 48.24 0.192 48.264 ;
    END
  END o[259]
  PIN o[25]
    DIRECTION OUTPUT ;
    USE SIGNAL ;
    PORT
      LAYER M4 ;
        RECT  0 8.592 0.192 8.616 ;
    END
  END o[25]
  PIN o[260]
    DIRECTION OUTPUT ;
    USE SIGNAL ;
    PORT
      LAYER M4 ;
        RECT  0 48.432 0.192 48.456 ;
    END
  END o[260]
  PIN o[261]
    DIRECTION OUTPUT ;
    USE SIGNAL ;
    PORT
      LAYER M4 ;
        RECT  0 48.624 0.192 48.648 ;
    END
  END o[261]
  PIN o[262]
    DIRECTION OUTPUT ;
    USE SIGNAL ;
    PORT
      LAYER M4 ;
        RECT  0 48.768 0.192 48.792 ;
    END
  END o[262]
  PIN o[263]
    DIRECTION OUTPUT ;
    USE SIGNAL ;
    PORT
      LAYER M4 ;
        RECT  0 48.96 0.192 48.984 ;
    END
  END o[263]
  PIN o[264]
    DIRECTION OUTPUT ;
    USE SIGNAL ;
    PORT
      LAYER M4 ;
        RECT  0 49.104 0.192 49.128 ;
    END
  END o[264]
  PIN o[265]
    DIRECTION OUTPUT ;
    USE SIGNAL ;
    PORT
      LAYER M4 ;
        RECT  0 49.296 0.192 49.32 ;
    END
  END o[265]
  PIN o[266]
    DIRECTION OUTPUT ;
    USE SIGNAL ;
    PORT
      LAYER M4 ;
        RECT  0 49.44 0.192 49.464 ;
    END
  END o[266]
  PIN o[267]
    DIRECTION OUTPUT ;
    USE SIGNAL ;
    PORT
      LAYER M4 ;
        RECT  0 49.632 0.192 49.656 ;
    END
  END o[267]
  PIN o[268]
    DIRECTION OUTPUT ;
    USE SIGNAL ;
    PORT
      LAYER M4 ;
        RECT  0 49.776 0.192 49.8 ;
    END
  END o[268]
  PIN o[269]
    DIRECTION OUTPUT ;
    USE SIGNAL ;
    PORT
      LAYER M4 ;
        RECT  0 49.968 0.192 49.992 ;
    END
  END o[269]
  PIN o[26]
    DIRECTION OUTPUT ;
    USE SIGNAL ;
    PORT
      LAYER M4 ;
        RECT  0 8.736 0.192 8.76 ;
    END
  END o[26]
  PIN o[270]
    DIRECTION OUTPUT ;
    USE SIGNAL ;
    PORT
      LAYER M4 ;
        RECT  0 50.112 0.192 50.136 ;
    END
  END o[270]
  PIN o[271]
    DIRECTION OUTPUT ;
    USE SIGNAL ;
    PORT
      LAYER M4 ;
        RECT  0 50.304 0.192 50.328 ;
    END
  END o[271]
  PIN o[272]
    DIRECTION OUTPUT ;
    USE SIGNAL ;
    PORT
      LAYER M4 ;
        RECT  0 50.448 0.192 50.472 ;
    END
  END o[272]
  PIN o[273]
    DIRECTION OUTPUT ;
    USE SIGNAL ;
    PORT
      LAYER M4 ;
        RECT  0 50.64 0.192 50.664 ;
    END
  END o[273]
  PIN o[274]
    DIRECTION OUTPUT ;
    USE SIGNAL ;
    PORT
      LAYER M4 ;
        RECT  0 50.784 0.192 50.808 ;
    END
  END o[274]
  PIN o[275]
    DIRECTION OUTPUT ;
    USE SIGNAL ;
    PORT
      LAYER M4 ;
        RECT  0 50.976 0.192 51 ;
    END
  END o[275]
  PIN o[276]
    DIRECTION OUTPUT ;
    USE SIGNAL ;
    PORT
      LAYER M4 ;
        RECT  0 51.168 0.192 51.192 ;
    END
  END o[276]
  PIN o[277]
    DIRECTION OUTPUT ;
    USE SIGNAL ;
    PORT
      LAYER M4 ;
        RECT  0 51.312 0.192 51.336 ;
    END
  END o[277]
  PIN o[278]
    DIRECTION OUTPUT ;
    USE SIGNAL ;
    PORT
      LAYER M4 ;
        RECT  0 51.504 0.192 51.528 ;
    END
  END o[278]
  PIN o[279]
    DIRECTION OUTPUT ;
    USE SIGNAL ;
    PORT
      LAYER M4 ;
        RECT  0 51.648 0.192 51.672 ;
    END
  END o[279]
  PIN o[27]
    DIRECTION OUTPUT ;
    USE SIGNAL ;
    PORT
      LAYER M4 ;
        RECT  0 8.928 0.192 8.952 ;
    END
  END o[27]
  PIN o[280]
    DIRECTION OUTPUT ;
    USE SIGNAL ;
    PORT
      LAYER M4 ;
        RECT  0 51.84 0.192 51.864 ;
    END
  END o[280]
  PIN o[281]
    DIRECTION OUTPUT ;
    USE SIGNAL ;
    PORT
      LAYER M4 ;
        RECT  0 51.984 0.192 52.008 ;
    END
  END o[281]
  PIN o[282]
    DIRECTION OUTPUT ;
    USE SIGNAL ;
    PORT
      LAYER M4 ;
        RECT  0 52.176 0.192 52.2 ;
    END
  END o[282]
  PIN o[283]
    DIRECTION OUTPUT ;
    USE SIGNAL ;
    PORT
      LAYER M4 ;
        RECT  0 52.32 0.192 52.344 ;
    END
  END o[283]
  PIN o[284]
    DIRECTION OUTPUT ;
    USE SIGNAL ;
    PORT
      LAYER M4 ;
        RECT  0 52.512 0.192 52.536 ;
    END
  END o[284]
  PIN o[285]
    DIRECTION OUTPUT ;
    USE SIGNAL ;
    PORT
      LAYER M4 ;
        RECT  0 52.656 0.192 52.68 ;
    END
  END o[285]
  PIN o[286]
    DIRECTION OUTPUT ;
    USE SIGNAL ;
    PORT
      LAYER M4 ;
        RECT  0 52.848 0.192 52.872 ;
    END
  END o[286]
  PIN o[287]
    DIRECTION OUTPUT ;
    USE SIGNAL ;
    PORT
      LAYER M4 ;
        RECT  0 52.992 0.192 53.016 ;
    END
  END o[287]
  PIN o[288]
    DIRECTION OUTPUT ;
    USE SIGNAL ;
    PORT
      LAYER M4 ;
        RECT  0 53.184 0.192 53.208 ;
    END
  END o[288]
  PIN o[289]
    DIRECTION OUTPUT ;
    USE SIGNAL ;
    PORT
      LAYER M4 ;
        RECT  0 53.328 0.192 53.352 ;
    END
  END o[289]
  PIN o[28]
    DIRECTION OUTPUT ;
    USE SIGNAL ;
    PORT
      LAYER M4 ;
        RECT  0 9.072 0.192 9.096 ;
    END
  END o[28]
  PIN o[290]
    DIRECTION OUTPUT ;
    USE SIGNAL ;
    PORT
      LAYER M4 ;
        RECT  0 53.52 0.192 53.544 ;
    END
  END o[290]
  PIN o[291]
    DIRECTION OUTPUT ;
    USE SIGNAL ;
    PORT
      LAYER M4 ;
        RECT  0 53.712 0.192 53.736 ;
    END
  END o[291]
  PIN o[292]
    DIRECTION OUTPUT ;
    USE SIGNAL ;
    PORT
      LAYER M4 ;
        RECT  0 53.856 0.192 53.88 ;
    END
  END o[292]
  PIN o[293]
    DIRECTION OUTPUT ;
    USE SIGNAL ;
    PORT
      LAYER M4 ;
        RECT  0 54.048 0.192 54.072 ;
    END
  END o[293]
  PIN o[294]
    DIRECTION OUTPUT ;
    USE SIGNAL ;
    PORT
      LAYER M4 ;
        RECT  0 54.192 0.192 54.216 ;
    END
  END o[294]
  PIN o[295]
    DIRECTION OUTPUT ;
    USE SIGNAL ;
    PORT
      LAYER M4 ;
        RECT  0 54.384 0.192 54.408 ;
    END
  END o[295]
  PIN o[296]
    DIRECTION OUTPUT ;
    USE SIGNAL ;
    PORT
      LAYER M4 ;
        RECT  0 54.528 0.192 54.552 ;
    END
  END o[296]
  PIN o[297]
    DIRECTION OUTPUT ;
    USE SIGNAL ;
    PORT
      LAYER M4 ;
        RECT  0 54.72 0.192 54.744 ;
    END
  END o[297]
  PIN o[298]
    DIRECTION OUTPUT ;
    USE SIGNAL ;
    PORT
      LAYER M4 ;
        RECT  0 54.864 0.192 54.888 ;
    END
  END o[298]
  PIN o[299]
    DIRECTION OUTPUT ;
    USE SIGNAL ;
    PORT
      LAYER M4 ;
        RECT  0 55.056 0.192 55.08 ;
    END
  END o[299]
  PIN o[29]
    DIRECTION OUTPUT ;
    USE SIGNAL ;
    PORT
      LAYER M4 ;
        RECT  0 9.264 0.192 9.288 ;
    END
  END o[29]
  PIN o[2]
    DIRECTION OUTPUT ;
    USE SIGNAL ;
    PORT
      LAYER M4 ;
        RECT  0 4.656 0.192 4.68 ;
    END
  END o[2]
  PIN o[300]
    DIRECTION OUTPUT ;
    USE SIGNAL ;
    PORT
      LAYER M4 ;
        RECT  0 55.2 0.192 55.224 ;
    END
  END o[300]
  PIN o[301]
    DIRECTION OUTPUT ;
    USE SIGNAL ;
    PORT
      LAYER M4 ;
        RECT  0 55.392 0.192 55.416 ;
    END
  END o[301]
  PIN o[302]
    DIRECTION OUTPUT ;
    USE SIGNAL ;
    PORT
      LAYER M4 ;
        RECT  0 55.536 0.192 55.56 ;
    END
  END o[302]
  PIN o[303]
    DIRECTION OUTPUT ;
    USE SIGNAL ;
    PORT
      LAYER M4 ;
        RECT  0 55.728 0.192 55.752 ;
    END
  END o[303]
  PIN o[304]
    DIRECTION OUTPUT ;
    USE SIGNAL ;
    PORT
      LAYER M4 ;
        RECT  0 55.872 0.192 55.896 ;
    END
  END o[304]
  PIN o[305]
    DIRECTION OUTPUT ;
    USE SIGNAL ;
    PORT
      LAYER M4 ;
        RECT  0 56.064 0.192 56.088 ;
    END
  END o[305]
  PIN o[306]
    DIRECTION OUTPUT ;
    USE SIGNAL ;
    PORT
      LAYER M4 ;
        RECT  0 56.256 0.192 56.28 ;
    END
  END o[306]
  PIN o[307]
    DIRECTION OUTPUT ;
    USE SIGNAL ;
    PORT
      LAYER M4 ;
        RECT  0 56.4 0.192 56.424 ;
    END
  END o[307]
  PIN o[308]
    DIRECTION OUTPUT ;
    USE SIGNAL ;
    PORT
      LAYER M4 ;
        RECT  0 56.592 0.192 56.616 ;
    END
  END o[308]
  PIN o[309]
    DIRECTION OUTPUT ;
    USE SIGNAL ;
    PORT
      LAYER M4 ;
        RECT  0 56.736 0.192 56.76 ;
    END
  END o[309]
  PIN o[30]
    DIRECTION OUTPUT ;
    USE SIGNAL ;
    PORT
      LAYER M4 ;
        RECT  0 9.408 0.192 9.432 ;
    END
  END o[30]
  PIN o[310]
    DIRECTION OUTPUT ;
    USE SIGNAL ;
    PORT
      LAYER M4 ;
        RECT  0 56.928 0.192 56.952 ;
    END
  END o[310]
  PIN o[311]
    DIRECTION OUTPUT ;
    USE SIGNAL ;
    PORT
      LAYER M4 ;
        RECT  0 57.072 0.192 57.096 ;
    END
  END o[311]
  PIN o[312]
    DIRECTION OUTPUT ;
    USE SIGNAL ;
    PORT
      LAYER M4 ;
        RECT  0 57.408 0.192 57.432 ;
    END
  END o[312]
  PIN o[313]
    DIRECTION OUTPUT ;
    USE SIGNAL ;
    PORT
      LAYER M4 ;
        RECT  0 57.6 0.192 57.624 ;
    END
  END o[313]
  PIN o[314]
    DIRECTION OUTPUT ;
    USE SIGNAL ;
    PORT
      LAYER M4 ;
        RECT  0 57.744 0.192 57.768 ;
    END
  END o[314]
  PIN o[315]
    DIRECTION OUTPUT ;
    USE SIGNAL ;
    PORT
      LAYER M4 ;
        RECT  0 57.936 0.192 57.96 ;
    END
  END o[315]
  PIN o[316]
    DIRECTION OUTPUT ;
    USE SIGNAL ;
    PORT
      LAYER M4 ;
        RECT  0 58.08 0.192 58.104 ;
    END
  END o[316]
  PIN o[317]
    DIRECTION OUTPUT ;
    USE SIGNAL ;
    PORT
      LAYER M4 ;
        RECT  0 58.272 0.192 58.296 ;
    END
  END o[317]
  PIN o[318]
    DIRECTION OUTPUT ;
    USE SIGNAL ;
    PORT
      LAYER M4 ;
        RECT  0 58.416 0.192 58.44 ;
    END
  END o[318]
  PIN o[319]
    DIRECTION OUTPUT ;
    USE SIGNAL ;
    PORT
      LAYER M4 ;
        RECT  0 58.608 0.192 58.632 ;
    END
  END o[319]
  PIN o[31]
    DIRECTION OUTPUT ;
    USE SIGNAL ;
    PORT
      LAYER M4 ;
        RECT  0 9.6 0.192 9.624 ;
    END
  END o[31]
  PIN o[320]
    DIRECTION OUTPUT ;
    USE SIGNAL ;
    PORT
      LAYER M4 ;
        RECT  0 58.8 0.192 58.824 ;
    END
  END o[320]
  PIN o[321]
    DIRECTION OUTPUT ;
    USE SIGNAL ;
    PORT
      LAYER M4 ;
        RECT  0 58.944 0.192 58.968 ;
    END
  END o[321]
  PIN o[322]
    DIRECTION OUTPUT ;
    USE SIGNAL ;
    PORT
      LAYER M4 ;
        RECT  0 59.136 0.192 59.16 ;
    END
  END o[322]
  PIN o[323]
    DIRECTION OUTPUT ;
    USE SIGNAL ;
    PORT
      LAYER M4 ;
        RECT  0 59.28 0.192 59.304 ;
    END
  END o[323]
  PIN o[324]
    DIRECTION OUTPUT ;
    USE SIGNAL ;
    PORT
      LAYER M4 ;
        RECT  0 59.472 0.192 59.496 ;
    END
  END o[324]
  PIN o[325]
    DIRECTION OUTPUT ;
    USE SIGNAL ;
    PORT
      LAYER M4 ;
        RECT  0 59.616 0.192 59.64 ;
    END
  END o[325]
  PIN o[326]
    DIRECTION OUTPUT ;
    USE SIGNAL ;
    PORT
      LAYER M4 ;
        RECT  0 59.808 0.192 59.832 ;
    END
  END o[326]
  PIN o[327]
    DIRECTION OUTPUT ;
    USE SIGNAL ;
    PORT
      LAYER M4 ;
        RECT  0 59.952 0.192 59.976 ;
    END
  END o[327]
  PIN o[328]
    DIRECTION OUTPUT ;
    USE SIGNAL ;
    PORT
      LAYER M4 ;
        RECT  0 60.144 0.192 60.168 ;
    END
  END o[328]
  PIN o[329]
    DIRECTION OUTPUT ;
    USE SIGNAL ;
    PORT
      LAYER M4 ;
        RECT  0 60.288 0.192 60.312 ;
    END
  END o[329]
  PIN o[32]
    DIRECTION OUTPUT ;
    USE SIGNAL ;
    PORT
      LAYER M4 ;
        RECT  0 9.744 0.192 9.768 ;
    END
  END o[32]
  PIN o[330]
    DIRECTION OUTPUT ;
    USE SIGNAL ;
    PORT
      LAYER M4 ;
        RECT  0 60.48 0.192 60.504 ;
    END
  END o[330]
  PIN o[331]
    DIRECTION OUTPUT ;
    USE SIGNAL ;
    PORT
      LAYER M4 ;
        RECT  0 60.624 0.192 60.648 ;
    END
  END o[331]
  PIN o[332]
    DIRECTION OUTPUT ;
    USE SIGNAL ;
    PORT
      LAYER M4 ;
        RECT  0 60.816 0.192 60.84 ;
    END
  END o[332]
  PIN o[333]
    DIRECTION OUTPUT ;
    USE SIGNAL ;
    PORT
      LAYER M4 ;
        RECT  0 60.96 0.192 60.984 ;
    END
  END o[333]
  PIN o[334]
    DIRECTION OUTPUT ;
    USE SIGNAL ;
    PORT
      LAYER M4 ;
        RECT  0 61.152 0.192 61.176 ;
    END
  END o[334]
  PIN o[335]
    DIRECTION OUTPUT ;
    USE SIGNAL ;
    PORT
      LAYER M4 ;
        RECT  0 61.344 0.192 61.368 ;
    END
  END o[335]
  PIN o[336]
    DIRECTION OUTPUT ;
    USE SIGNAL ;
    PORT
      LAYER M4 ;
        RECT  0 61.488 0.192 61.512 ;
    END
  END o[336]
  PIN o[337]
    DIRECTION OUTPUT ;
    USE SIGNAL ;
    PORT
      LAYER M4 ;
        RECT  0 61.68 0.192 61.704 ;
    END
  END o[337]
  PIN o[338]
    DIRECTION OUTPUT ;
    USE SIGNAL ;
    PORT
      LAYER M4 ;
        RECT  0 61.824 0.192 61.848 ;
    END
  END o[338]
  PIN o[339]
    DIRECTION OUTPUT ;
    USE SIGNAL ;
    PORT
      LAYER M4 ;
        RECT  0 62.016 0.192 62.04 ;
    END
  END o[339]
  PIN o[33]
    DIRECTION OUTPUT ;
    USE SIGNAL ;
    PORT
      LAYER M4 ;
        RECT  0 9.936 0.192 9.96 ;
    END
  END o[33]
  PIN o[340]
    DIRECTION OUTPUT ;
    USE SIGNAL ;
    PORT
      LAYER M4 ;
        RECT  0 62.16 0.192 62.184 ;
    END
  END o[340]
  PIN o[341]
    DIRECTION OUTPUT ;
    USE SIGNAL ;
    PORT
      LAYER M4 ;
        RECT  0 62.352 0.192 62.376 ;
    END
  END o[341]
  PIN o[342]
    DIRECTION OUTPUT ;
    USE SIGNAL ;
    PORT
      LAYER M4 ;
        RECT  0 62.496 0.192 62.52 ;
    END
  END o[342]
  PIN o[343]
    DIRECTION OUTPUT ;
    USE SIGNAL ;
    PORT
      LAYER M4 ;
        RECT  0 62.688 0.192 62.712 ;
    END
  END o[343]
  PIN o[344]
    DIRECTION OUTPUT ;
    USE SIGNAL ;
    PORT
      LAYER M4 ;
        RECT  0 62.832 0.192 62.856 ;
    END
  END o[344]
  PIN o[345]
    DIRECTION OUTPUT ;
    USE SIGNAL ;
    PORT
      LAYER M4 ;
        RECT  0 63.024 0.192 63.048 ;
    END
  END o[345]
  PIN o[346]
    DIRECTION OUTPUT ;
    USE SIGNAL ;
    PORT
      LAYER M4 ;
        RECT  0 63.168 0.192 63.192 ;
    END
  END o[346]
  PIN o[347]
    DIRECTION OUTPUT ;
    USE SIGNAL ;
    PORT
      LAYER M4 ;
        RECT  0 63.36 0.192 63.384 ;
    END
  END o[347]
  PIN o[348]
    DIRECTION OUTPUT ;
    USE SIGNAL ;
    PORT
      LAYER M4 ;
        RECT  0 63.504 0.192 63.528 ;
    END
  END o[348]
  PIN o[349]
    DIRECTION OUTPUT ;
    USE SIGNAL ;
    PORT
      LAYER M4 ;
        RECT  0 63.696 0.192 63.72 ;
    END
  END o[349]
  PIN o[34]
    DIRECTION OUTPUT ;
    USE SIGNAL ;
    PORT
      LAYER M4 ;
        RECT  0 10.08 0.192 10.104 ;
    END
  END o[34]
  PIN o[350]
    DIRECTION OUTPUT ;
    USE SIGNAL ;
    PORT
      LAYER M4 ;
        RECT  0 63.888 0.192 63.912 ;
    END
  END o[350]
  PIN o[351]
    DIRECTION OUTPUT ;
    USE SIGNAL ;
    PORT
      LAYER M4 ;
        RECT  0 64.032 0.192 64.056 ;
    END
  END o[351]
  PIN o[352]
    DIRECTION OUTPUT ;
    USE SIGNAL ;
    PORT
      LAYER M4 ;
        RECT  0 64.224 0.192 64.248 ;
    END
  END o[352]
  PIN o[353]
    DIRECTION OUTPUT ;
    USE SIGNAL ;
    PORT
      LAYER M4 ;
        RECT  0 64.368 0.192 64.392 ;
    END
  END o[353]
  PIN o[354]
    DIRECTION OUTPUT ;
    USE SIGNAL ;
    PORT
      LAYER M4 ;
        RECT  0 64.56 0.192 64.584 ;
    END
  END o[354]
  PIN o[355]
    DIRECTION OUTPUT ;
    USE SIGNAL ;
    PORT
      LAYER M4 ;
        RECT  0 64.704 0.192 64.728 ;
    END
  END o[355]
  PIN o[356]
    DIRECTION OUTPUT ;
    USE SIGNAL ;
    PORT
      LAYER M4 ;
        RECT  0 64.896 0.192 64.92 ;
    END
  END o[356]
  PIN o[357]
    DIRECTION OUTPUT ;
    USE SIGNAL ;
    PORT
      LAYER M4 ;
        RECT  0 65.04 0.192 65.064 ;
    END
  END o[357]
  PIN o[358]
    DIRECTION OUTPUT ;
    USE SIGNAL ;
    PORT
      LAYER M4 ;
        RECT  0 65.232 0.192 65.256 ;
    END
  END o[358]
  PIN o[359]
    DIRECTION OUTPUT ;
    USE SIGNAL ;
    PORT
      LAYER M4 ;
        RECT  0 65.376 0.192 65.4 ;
    END
  END o[359]
  PIN o[35]
    DIRECTION OUTPUT ;
    USE SIGNAL ;
    PORT
      LAYER M4 ;
        RECT  0 10.272 0.192 10.296 ;
    END
  END o[35]
  PIN o[360]
    DIRECTION OUTPUT ;
    USE SIGNAL ;
    PORT
      LAYER M4 ;
        RECT  0 65.568 0.192 65.592 ;
    END
  END o[360]
  PIN o[361]
    DIRECTION OUTPUT ;
    USE SIGNAL ;
    PORT
      LAYER M4 ;
        RECT  0 65.712 0.192 65.736 ;
    END
  END o[361]
  PIN o[362]
    DIRECTION OUTPUT ;
    USE SIGNAL ;
    PORT
      LAYER M4 ;
        RECT  0 65.904 0.192 65.928 ;
    END
  END o[362]
  PIN o[363]
    DIRECTION OUTPUT ;
    USE SIGNAL ;
    PORT
      LAYER M4 ;
        RECT  0 66.096 0.192 66.12 ;
    END
  END o[363]
  PIN o[364]
    DIRECTION OUTPUT ;
    USE SIGNAL ;
    PORT
      LAYER M4 ;
        RECT  0 66.24 0.192 66.264 ;
    END
  END o[364]
  PIN o[365]
    DIRECTION OUTPUT ;
    USE SIGNAL ;
    PORT
      LAYER M4 ;
        RECT  0 66.432 0.192 66.456 ;
    END
  END o[365]
  PIN o[366]
    DIRECTION OUTPUT ;
    USE SIGNAL ;
    PORT
      LAYER M4 ;
        RECT  0 66.576 0.192 66.6 ;
    END
  END o[366]
  PIN o[367]
    DIRECTION OUTPUT ;
    USE SIGNAL ;
    PORT
      LAYER M4 ;
        RECT  0 66.768 0.192 66.792 ;
    END
  END o[367]
  PIN o[368]
    DIRECTION OUTPUT ;
    USE SIGNAL ;
    PORT
      LAYER M4 ;
        RECT  0 66.912 0.192 66.936 ;
    END
  END o[368]
  PIN o[369]
    DIRECTION OUTPUT ;
    USE SIGNAL ;
    PORT
      LAYER M4 ;
        RECT  0 67.104 0.192 67.128 ;
    END
  END o[369]
  PIN o[36]
    DIRECTION OUTPUT ;
    USE SIGNAL ;
    PORT
      LAYER M4 ;
        RECT  0 10.416 0.192 10.44 ;
    END
  END o[36]
  PIN o[370]
    DIRECTION OUTPUT ;
    USE SIGNAL ;
    PORT
      LAYER M4 ;
        RECT  0 67.248 0.192 67.272 ;
    END
  END o[370]
  PIN o[371]
    DIRECTION OUTPUT ;
    USE SIGNAL ;
    PORT
      LAYER M4 ;
        RECT  0 67.44 0.192 67.464 ;
    END
  END o[371]
  PIN o[372]
    DIRECTION OUTPUT ;
    USE SIGNAL ;
    PORT
      LAYER M4 ;
        RECT  0 67.584 0.192 67.608 ;
    END
  END o[372]
  PIN o[373]
    DIRECTION OUTPUT ;
    USE SIGNAL ;
    PORT
      LAYER M4 ;
        RECT  0 67.776 0.192 67.8 ;
    END
  END o[373]
  PIN o[374]
    DIRECTION OUTPUT ;
    USE SIGNAL ;
    PORT
      LAYER M4 ;
        RECT  0 67.92 0.192 67.944 ;
    END
  END o[374]
  PIN o[375]
    DIRECTION OUTPUT ;
    USE SIGNAL ;
    PORT
      LAYER M4 ;
        RECT  0 68.112 0.192 68.136 ;
    END
  END o[375]
  PIN o[376]
    DIRECTION OUTPUT ;
    USE SIGNAL ;
    PORT
      LAYER M4 ;
        RECT  0 68.256 0.192 68.28 ;
    END
  END o[376]
  PIN o[377]
    DIRECTION OUTPUT ;
    USE SIGNAL ;
    PORT
      LAYER M4 ;
        RECT  0 68.448 0.192 68.472 ;
    END
  END o[377]
  PIN o[378]
    DIRECTION OUTPUT ;
    USE SIGNAL ;
    PORT
      LAYER M4 ;
        RECT  0 68.64 0.192 68.664 ;
    END
  END o[378]
  PIN o[379]
    DIRECTION OUTPUT ;
    USE SIGNAL ;
    PORT
      LAYER M4 ;
        RECT  0 68.784 0.192 68.808 ;
    END
  END o[379]
  PIN o[37]
    DIRECTION OUTPUT ;
    USE SIGNAL ;
    PORT
      LAYER M4 ;
        RECT  0 10.608 0.192 10.632 ;
    END
  END o[37]
  PIN o[380]
    DIRECTION OUTPUT ;
    USE SIGNAL ;
    PORT
      LAYER M4 ;
        RECT  0 68.976 0.192 69 ;
    END
  END o[380]
  PIN o[381]
    DIRECTION OUTPUT ;
    USE SIGNAL ;
    PORT
      LAYER M4 ;
        RECT  0 69.12 0.192 69.144 ;
    END
  END o[381]
  PIN o[382]
    DIRECTION OUTPUT ;
    USE SIGNAL ;
    PORT
      LAYER M4 ;
        RECT  0 69.312 0.192 69.336 ;
    END
  END o[382]
  PIN o[383]
    DIRECTION OUTPUT ;
    USE SIGNAL ;
    PORT
      LAYER M4 ;
        RECT  0 69.456 0.192 69.48 ;
    END
  END o[383]
  PIN o[384]
    DIRECTION OUTPUT ;
    USE SIGNAL ;
    PORT
      LAYER M4 ;
        RECT  0 69.648 0.192 69.672 ;
    END
  END o[384]
  PIN o[385]
    DIRECTION OUTPUT ;
    USE SIGNAL ;
    PORT
      LAYER M4 ;
        RECT  0 69.792 0.192 69.816 ;
    END
  END o[385]
  PIN o[386]
    DIRECTION OUTPUT ;
    USE SIGNAL ;
    PORT
      LAYER M4 ;
        RECT  0 69.984 0.192 70.008 ;
    END
  END o[386]
  PIN o[387]
    DIRECTION OUTPUT ;
    USE SIGNAL ;
    PORT
      LAYER M4 ;
        RECT  0 70.128 0.192 70.152 ;
    END
  END o[387]
  PIN o[388]
    DIRECTION OUTPUT ;
    USE SIGNAL ;
    PORT
      LAYER M4 ;
        RECT  0 70.32 0.192 70.344 ;
    END
  END o[388]
  PIN o[389]
    DIRECTION OUTPUT ;
    USE SIGNAL ;
    PORT
      LAYER M4 ;
        RECT  0 70.464 0.192 70.488 ;
    END
  END o[389]
  PIN o[38]
    DIRECTION OUTPUT ;
    USE SIGNAL ;
    PORT
      LAYER M4 ;
        RECT  0 10.8 0.192 10.824 ;
    END
  END o[38]
  PIN o[390]
    DIRECTION OUTPUT ;
    USE SIGNAL ;
    PORT
      LAYER M4 ;
        RECT  0 70.656 0.192 70.68 ;
    END
  END o[390]
  PIN o[391]
    DIRECTION OUTPUT ;
    USE SIGNAL ;
    PORT
      LAYER M4 ;
        RECT  0 70.8 0.192 70.824 ;
    END
  END o[391]
  PIN o[392]
    DIRECTION OUTPUT ;
    USE SIGNAL ;
    PORT
      LAYER M4 ;
        RECT  0 70.992 0.192 71.016 ;
    END
  END o[392]
  PIN o[393]
    DIRECTION OUTPUT ;
    USE SIGNAL ;
    PORT
      LAYER M4 ;
        RECT  0 71.184 0.192 71.208 ;
    END
  END o[393]
  PIN o[394]
    DIRECTION OUTPUT ;
    USE SIGNAL ;
    PORT
      LAYER M4 ;
        RECT  0 71.328 0.192 71.352 ;
    END
  END o[394]
  PIN o[395]
    DIRECTION OUTPUT ;
    USE SIGNAL ;
    PORT
      LAYER M4 ;
        RECT  0 71.52 0.192 71.544 ;
    END
  END o[395]
  PIN o[396]
    DIRECTION OUTPUT ;
    USE SIGNAL ;
    PORT
      LAYER M4 ;
        RECT  0 71.664 0.192 71.688 ;
    END
  END o[396]
  PIN o[397]
    DIRECTION OUTPUT ;
    USE SIGNAL ;
    PORT
      LAYER M4 ;
        RECT  0 71.856 0.192 71.88 ;
    END
  END o[397]
  PIN o[398]
    DIRECTION OUTPUT ;
    USE SIGNAL ;
    PORT
      LAYER M4 ;
        RECT  0 72 0.192 72.024 ;
    END
  END o[398]
  PIN o[399]
    DIRECTION OUTPUT ;
    USE SIGNAL ;
    PORT
      LAYER M4 ;
        RECT  0 72.192 0.192 72.216 ;
    END
  END o[399]
  PIN o[39]
    DIRECTION OUTPUT ;
    USE SIGNAL ;
    PORT
      LAYER M4 ;
        RECT  0 10.944 0.192 10.968 ;
    END
  END o[39]
  PIN o[3]
    DIRECTION OUTPUT ;
    USE SIGNAL ;
    PORT
      LAYER M4 ;
        RECT  0 4.848 0.192 4.872 ;
    END
  END o[3]
  PIN o[400]
    DIRECTION OUTPUT ;
    USE SIGNAL ;
    PORT
      LAYER M4 ;
        RECT  0 72.336 0.192 72.36 ;
    END
  END o[400]
  PIN o[401]
    DIRECTION OUTPUT ;
    USE SIGNAL ;
    PORT
      LAYER M4 ;
        RECT  0 72.528 0.192 72.552 ;
    END
  END o[401]
  PIN o[402]
    DIRECTION OUTPUT ;
    USE SIGNAL ;
    PORT
      LAYER M4 ;
        RECT  0 72.672 0.192 72.696 ;
    END
  END o[402]
  PIN o[403]
    DIRECTION OUTPUT ;
    USE SIGNAL ;
    PORT
      LAYER M4 ;
        RECT  0 72.864 0.192 72.888 ;
    END
  END o[403]
  PIN o[404]
    DIRECTION OUTPUT ;
    USE SIGNAL ;
    PORT
      LAYER M4 ;
        RECT  0 73.008 0.192 73.032 ;
    END
  END o[404]
  PIN o[405]
    DIRECTION OUTPUT ;
    USE SIGNAL ;
    PORT
      LAYER M4 ;
        RECT  0 73.2 0.192 73.224 ;
    END
  END o[405]
  PIN o[406]
    DIRECTION OUTPUT ;
    USE SIGNAL ;
    PORT
      LAYER M4 ;
        RECT  0 73.344 0.192 73.368 ;
    END
  END o[406]
  PIN o[407]
    DIRECTION OUTPUT ;
    USE SIGNAL ;
    PORT
      LAYER M4 ;
        RECT  0 73.536 0.192 73.56 ;
    END
  END o[407]
  PIN o[408]
    DIRECTION OUTPUT ;
    USE SIGNAL ;
    PORT
      LAYER M4 ;
        RECT  0 73.728 0.192 73.752 ;
    END
  END o[408]
  PIN o[409]
    DIRECTION OUTPUT ;
    USE SIGNAL ;
    PORT
      LAYER M4 ;
        RECT  0 73.872 0.192 73.896 ;
    END
  END o[409]
  PIN o[40]
    DIRECTION OUTPUT ;
    USE SIGNAL ;
    PORT
      LAYER M4 ;
        RECT  0 11.136 0.192 11.16 ;
    END
  END o[40]
  PIN o[410]
    DIRECTION OUTPUT ;
    USE SIGNAL ;
    PORT
      LAYER M4 ;
        RECT  0 74.064 0.192 74.088 ;
    END
  END o[410]
  PIN o[411]
    DIRECTION OUTPUT ;
    USE SIGNAL ;
    PORT
      LAYER M4 ;
        RECT  0 74.208 0.192 74.232 ;
    END
  END o[411]
  PIN o[412]
    DIRECTION OUTPUT ;
    USE SIGNAL ;
    PORT
      LAYER M4 ;
        RECT  0 74.4 0.192 74.424 ;
    END
  END o[412]
  PIN o[413]
    DIRECTION OUTPUT ;
    USE SIGNAL ;
    PORT
      LAYER M4 ;
        RECT  0 74.544 0.192 74.568 ;
    END
  END o[413]
  PIN o[414]
    DIRECTION OUTPUT ;
    USE SIGNAL ;
    PORT
      LAYER M4 ;
        RECT  0 74.736 0.192 74.76 ;
    END
  END o[414]
  PIN o[415]
    DIRECTION OUTPUT ;
    USE SIGNAL ;
    PORT
      LAYER M4 ;
        RECT  0 74.88 0.192 74.904 ;
    END
  END o[415]
  PIN o[416]
    DIRECTION OUTPUT ;
    USE SIGNAL ;
    PORT
      LAYER M4 ;
        RECT  0 75.072 0.192 75.096 ;
    END
  END o[416]
  PIN o[417]
    DIRECTION OUTPUT ;
    USE SIGNAL ;
    PORT
      LAYER M4 ;
        RECT  0 75.216 0.192 75.24 ;
    END
  END o[417]
  PIN o[418]
    DIRECTION OUTPUT ;
    USE SIGNAL ;
    PORT
      LAYER M4 ;
        RECT  0 75.408 0.192 75.432 ;
    END
  END o[418]
  PIN o[419]
    DIRECTION OUTPUT ;
    USE SIGNAL ;
    PORT
      LAYER M4 ;
        RECT  0 75.552 0.192 75.576 ;
    END
  END o[419]
  PIN o[41]
    DIRECTION OUTPUT ;
    USE SIGNAL ;
    PORT
      LAYER M4 ;
        RECT  0 11.28 0.192 11.304 ;
    END
  END o[41]
  PIN o[420]
    DIRECTION OUTPUT ;
    USE SIGNAL ;
    PORT
      LAYER M4 ;
        RECT  0 75.744 0.192 75.768 ;
    END
  END o[420]
  PIN o[421]
    DIRECTION OUTPUT ;
    USE SIGNAL ;
    PORT
      LAYER M4 ;
        RECT  0 75.888 0.192 75.912 ;
    END
  END o[421]
  PIN o[422]
    DIRECTION OUTPUT ;
    USE SIGNAL ;
    PORT
      LAYER M4 ;
        RECT  0 76.08 0.192 76.104 ;
    END
  END o[422]
  PIN o[423]
    DIRECTION OUTPUT ;
    USE SIGNAL ;
    PORT
      LAYER M4 ;
        RECT  0 76.272 0.192 76.296 ;
    END
  END o[423]
  PIN o[424]
    DIRECTION OUTPUT ;
    USE SIGNAL ;
    PORT
      LAYER M4 ;
        RECT  0 76.416 0.192 76.44 ;
    END
  END o[424]
  PIN o[425]
    DIRECTION OUTPUT ;
    USE SIGNAL ;
    PORT
      LAYER M4 ;
        RECT  0 76.608 0.192 76.632 ;
    END
  END o[425]
  PIN o[426]
    DIRECTION OUTPUT ;
    USE SIGNAL ;
    PORT
      LAYER M4 ;
        RECT  0 76.752 0.192 76.776 ;
    END
  END o[426]
  PIN o[427]
    DIRECTION OUTPUT ;
    USE SIGNAL ;
    PORT
      LAYER M4 ;
        RECT  0 76.944 0.192 76.968 ;
    END
  END o[427]
  PIN o[428]
    DIRECTION OUTPUT ;
    USE SIGNAL ;
    PORT
      LAYER M4 ;
        RECT  0 77.088 0.192 77.112 ;
    END
  END o[428]
  PIN o[429]
    DIRECTION OUTPUT ;
    USE SIGNAL ;
    PORT
      LAYER M4 ;
        RECT  0 77.28 0.192 77.304 ;
    END
  END o[429]
  PIN o[42]
    DIRECTION OUTPUT ;
    USE SIGNAL ;
    PORT
      LAYER M4 ;
        RECT  0 11.472 0.192 11.496 ;
    END
  END o[42]
  PIN o[430]
    DIRECTION OUTPUT ;
    USE SIGNAL ;
    PORT
      LAYER M4 ;
        RECT  0 77.424 0.192 77.448 ;
    END
  END o[430]
  PIN o[431]
    DIRECTION OUTPUT ;
    USE SIGNAL ;
    PORT
      LAYER M4 ;
        RECT  0 77.616 0.192 77.64 ;
    END
  END o[431]
  PIN o[432]
    DIRECTION OUTPUT ;
    USE SIGNAL ;
    PORT
      LAYER M4 ;
        RECT  0 77.76 0.192 77.784 ;
    END
  END o[432]
  PIN o[433]
    DIRECTION OUTPUT ;
    USE SIGNAL ;
    PORT
      LAYER M4 ;
        RECT  0 77.952 0.192 77.976 ;
    END
  END o[433]
  PIN o[434]
    DIRECTION OUTPUT ;
    USE SIGNAL ;
    PORT
      LAYER M4 ;
        RECT  0 78.096 0.192 78.12 ;
    END
  END o[434]
  PIN o[435]
    DIRECTION OUTPUT ;
    USE SIGNAL ;
    PORT
      LAYER M4 ;
        RECT  0 78.288 0.192 78.312 ;
    END
  END o[435]
  PIN o[436]
    DIRECTION OUTPUT ;
    USE SIGNAL ;
    PORT
      LAYER M4 ;
        RECT  0 78.432 0.192 78.456 ;
    END
  END o[436]
  PIN o[437]
    DIRECTION OUTPUT ;
    USE SIGNAL ;
    PORT
      LAYER M4 ;
        RECT  0 78.624 0.192 78.648 ;
    END
  END o[437]
  PIN o[438]
    DIRECTION OUTPUT ;
    USE SIGNAL ;
    PORT
      LAYER M4 ;
        RECT  0 78.816 0.192 78.84 ;
    END
  END o[438]
  PIN o[439]
    DIRECTION OUTPUT ;
    USE SIGNAL ;
    PORT
      LAYER M4 ;
        RECT  0 78.96 0.192 78.984 ;
    END
  END o[439]
  PIN o[43]
    DIRECTION OUTPUT ;
    USE SIGNAL ;
    PORT
      LAYER M4 ;
        RECT  0 11.616 0.192 11.64 ;
    END
  END o[43]
  PIN o[440]
    DIRECTION OUTPUT ;
    USE SIGNAL ;
    PORT
      LAYER M4 ;
        RECT  0 79.152 0.192 79.176 ;
    END
  END o[440]
  PIN o[441]
    DIRECTION OUTPUT ;
    USE SIGNAL ;
    PORT
      LAYER M4 ;
        RECT  0 79.296 0.192 79.32 ;
    END
  END o[441]
  PIN o[442]
    DIRECTION OUTPUT ;
    USE SIGNAL ;
    PORT
      LAYER M4 ;
        RECT  0 79.488 0.192 79.512 ;
    END
  END o[442]
  PIN o[443]
    DIRECTION OUTPUT ;
    USE SIGNAL ;
    PORT
      LAYER M4 ;
        RECT  0 79.632 0.192 79.656 ;
    END
  END o[443]
  PIN o[444]
    DIRECTION OUTPUT ;
    USE SIGNAL ;
    PORT
      LAYER M4 ;
        RECT  0 79.824 0.192 79.848 ;
    END
  END o[444]
  PIN o[445]
    DIRECTION OUTPUT ;
    USE SIGNAL ;
    PORT
      LAYER M4 ;
        RECT  0 79.968 0.192 79.992 ;
    END
  END o[445]
  PIN o[446]
    DIRECTION OUTPUT ;
    USE SIGNAL ;
    PORT
      LAYER M4 ;
        RECT  0 80.16 0.192 80.184 ;
    END
  END o[446]
  PIN o[447]
    DIRECTION OUTPUT ;
    USE SIGNAL ;
    PORT
      LAYER M4 ;
        RECT  0 80.304 0.192 80.328 ;
    END
  END o[447]
  PIN o[448]
    DIRECTION OUTPUT ;
    USE SIGNAL ;
    PORT
      LAYER M4 ;
        RECT  0 80.496 0.192 80.52 ;
    END
  END o[448]
  PIN o[449]
    DIRECTION OUTPUT ;
    USE SIGNAL ;
    PORT
      LAYER M4 ;
        RECT  0 80.64 0.192 80.664 ;
    END
  END o[449]
  PIN o[44]
    DIRECTION OUTPUT ;
    USE SIGNAL ;
    PORT
      LAYER M4 ;
        RECT  0 11.808 0.192 11.832 ;
    END
  END o[44]
  PIN o[450]
    DIRECTION OUTPUT ;
    USE SIGNAL ;
    PORT
      LAYER M4 ;
        RECT  0 80.832 0.192 80.856 ;
    END
  END o[450]
  PIN o[451]
    DIRECTION OUTPUT ;
    USE SIGNAL ;
    PORT
      LAYER M4 ;
        RECT  0 80.976 0.192 81 ;
    END
  END o[451]
  PIN o[452]
    DIRECTION OUTPUT ;
    USE SIGNAL ;
    PORT
      LAYER M4 ;
        RECT  0 81.168 0.192 81.192 ;
    END
  END o[452]
  PIN o[453]
    DIRECTION OUTPUT ;
    USE SIGNAL ;
    PORT
      LAYER M4 ;
        RECT  0 81.36 0.192 81.384 ;
    END
  END o[453]
  PIN o[454]
    DIRECTION OUTPUT ;
    USE SIGNAL ;
    PORT
      LAYER M4 ;
        RECT  0 81.504 0.192 81.528 ;
    END
  END o[454]
  PIN o[455]
    DIRECTION OUTPUT ;
    USE SIGNAL ;
    PORT
      LAYER M4 ;
        RECT  0 81.696 0.192 81.72 ;
    END
  END o[455]
  PIN o[456]
    DIRECTION OUTPUT ;
    USE SIGNAL ;
    PORT
      LAYER M4 ;
        RECT  0 81.84 0.192 81.864 ;
    END
  END o[456]
  PIN o[457]
    DIRECTION OUTPUT ;
    USE SIGNAL ;
    PORT
      LAYER M4 ;
        RECT  0 82.032 0.192 82.056 ;
    END
  END o[457]
  PIN o[458]
    DIRECTION OUTPUT ;
    USE SIGNAL ;
    PORT
      LAYER M4 ;
        RECT  0 82.176 0.192 82.2 ;
    END
  END o[458]
  PIN o[459]
    DIRECTION OUTPUT ;
    USE SIGNAL ;
    PORT
      LAYER M4 ;
        RECT  0 82.368 0.192 82.392 ;
    END
  END o[459]
  PIN o[45]
    DIRECTION OUTPUT ;
    USE SIGNAL ;
    PORT
      LAYER M4 ;
        RECT  0 11.952 0.192 11.976 ;
    END
  END o[45]
  PIN o[460]
    DIRECTION OUTPUT ;
    USE SIGNAL ;
    PORT
      LAYER M4 ;
        RECT  0 82.512 0.192 82.536 ;
    END
  END o[460]
  PIN o[461]
    DIRECTION OUTPUT ;
    USE SIGNAL ;
    PORT
      LAYER M4 ;
        RECT  0 82.704 0.192 82.728 ;
    END
  END o[461]
  PIN o[462]
    DIRECTION OUTPUT ;
    USE SIGNAL ;
    PORT
      LAYER M4 ;
        RECT  0 82.848 0.192 82.872 ;
    END
  END o[462]
  PIN o[463]
    DIRECTION OUTPUT ;
    USE SIGNAL ;
    PORT
      LAYER M4 ;
        RECT  0 83.04 0.192 83.064 ;
    END
  END o[463]
  PIN o[464]
    DIRECTION OUTPUT ;
    USE SIGNAL ;
    PORT
      LAYER M4 ;
        RECT  0 83.184 0.192 83.208 ;
    END
  END o[464]
  PIN o[465]
    DIRECTION OUTPUT ;
    USE SIGNAL ;
    PORT
      LAYER M4 ;
        RECT  0 83.376 0.192 83.4 ;
    END
  END o[465]
  PIN o[466]
    DIRECTION OUTPUT ;
    USE SIGNAL ;
    PORT
      LAYER M4 ;
        RECT  0 83.52 0.192 83.544 ;
    END
  END o[466]
  PIN o[467]
    DIRECTION OUTPUT ;
    USE SIGNAL ;
    PORT
      LAYER M4 ;
        RECT  0 83.712 0.192 83.736 ;
    END
  END o[467]
  PIN o[468]
    DIRECTION OUTPUT ;
    USE SIGNAL ;
    PORT
      LAYER M4 ;
        RECT  0 83.904 0.192 83.928 ;
    END
  END o[468]
  PIN o[469]
    DIRECTION OUTPUT ;
    USE SIGNAL ;
    PORT
      LAYER M4 ;
        RECT  0 84.048 0.192 84.072 ;
    END
  END o[469]
  PIN o[46]
    DIRECTION OUTPUT ;
    USE SIGNAL ;
    PORT
      LAYER M4 ;
        RECT  0 12.144 0.192 12.168 ;
    END
  END o[46]
  PIN o[470]
    DIRECTION OUTPUT ;
    USE SIGNAL ;
    PORT
      LAYER M4 ;
        RECT  0 84.24 0.192 84.264 ;
    END
  END o[470]
  PIN o[471]
    DIRECTION OUTPUT ;
    USE SIGNAL ;
    PORT
      LAYER M4 ;
        RECT  0 84.384 0.192 84.408 ;
    END
  END o[471]
  PIN o[472]
    DIRECTION OUTPUT ;
    USE SIGNAL ;
    PORT
      LAYER M4 ;
        RECT  0 84.576 0.192 84.6 ;
    END
  END o[472]
  PIN o[473]
    DIRECTION OUTPUT ;
    USE SIGNAL ;
    PORT
      LAYER M4 ;
        RECT  0 84.72 0.192 84.744 ;
    END
  END o[473]
  PIN o[474]
    DIRECTION OUTPUT ;
    USE SIGNAL ;
    PORT
      LAYER M4 ;
        RECT  0 84.912 0.192 84.936 ;
    END
  END o[474]
  PIN o[475]
    DIRECTION OUTPUT ;
    USE SIGNAL ;
    PORT
      LAYER M4 ;
        RECT  0 85.056 0.192 85.08 ;
    END
  END o[475]
  PIN o[476]
    DIRECTION OUTPUT ;
    USE SIGNAL ;
    PORT
      LAYER M4 ;
        RECT  0 85.248 0.192 85.272 ;
    END
  END o[476]
  PIN o[477]
    DIRECTION OUTPUT ;
    USE SIGNAL ;
    PORT
      LAYER M4 ;
        RECT  0 85.392 0.192 85.416 ;
    END
  END o[477]
  PIN o[478]
    DIRECTION OUTPUT ;
    USE SIGNAL ;
    PORT
      LAYER M4 ;
        RECT  0 85.584 0.192 85.608 ;
    END
  END o[478]
  PIN o[479]
    DIRECTION OUTPUT ;
    USE SIGNAL ;
    PORT
      LAYER M4 ;
        RECT  0 85.728 0.192 85.752 ;
    END
  END o[479]
  PIN o[47]
    DIRECTION OUTPUT ;
    USE SIGNAL ;
    PORT
      LAYER M4 ;
        RECT  0 12.288 0.192 12.312 ;
    END
  END o[47]
  PIN o[480]
    DIRECTION OUTPUT ;
    USE SIGNAL ;
    PORT
      LAYER M4 ;
        RECT  0 85.92 0.192 85.944 ;
    END
  END o[480]
  PIN o[481]
    DIRECTION OUTPUT ;
    USE SIGNAL ;
    PORT
      LAYER M4 ;
        RECT  0 86.064 0.192 86.088 ;
    END
  END o[481]
  PIN o[482]
    DIRECTION OUTPUT ;
    USE SIGNAL ;
    PORT
      LAYER M4 ;
        RECT  0 86.256 0.192 86.28 ;
    END
  END o[482]
  PIN o[483]
    DIRECTION OUTPUT ;
    USE SIGNAL ;
    PORT
      LAYER M4 ;
        RECT  0 86.448 0.192 86.472 ;
    END
  END o[483]
  PIN o[484]
    DIRECTION OUTPUT ;
    USE SIGNAL ;
    PORT
      LAYER M4 ;
        RECT  0 86.592 0.192 86.616 ;
    END
  END o[484]
  PIN o[485]
    DIRECTION OUTPUT ;
    USE SIGNAL ;
    PORT
      LAYER M4 ;
        RECT  0 86.784 0.192 86.808 ;
    END
  END o[485]
  PIN o[486]
    DIRECTION OUTPUT ;
    USE SIGNAL ;
    PORT
      LAYER M4 ;
        RECT  0 86.928 0.192 86.952 ;
    END
  END o[486]
  PIN o[487]
    DIRECTION OUTPUT ;
    USE SIGNAL ;
    PORT
      LAYER M4 ;
        RECT  0 87.12 0.192 87.144 ;
    END
  END o[487]
  PIN o[488]
    DIRECTION OUTPUT ;
    USE SIGNAL ;
    PORT
      LAYER M4 ;
        RECT  0 87.264 0.192 87.288 ;
    END
  END o[488]
  PIN o[489]
    DIRECTION OUTPUT ;
    USE SIGNAL ;
    PORT
      LAYER M4 ;
        RECT  0 87.456 0.192 87.48 ;
    END
  END o[489]
  PIN o[48]
    DIRECTION OUTPUT ;
    USE SIGNAL ;
    PORT
      LAYER M4 ;
        RECT  0 12.48 0.192 12.504 ;
    END
  END o[48]
  PIN o[490]
    DIRECTION OUTPUT ;
    USE SIGNAL ;
    PORT
      LAYER M4 ;
        RECT  0 87.6 0.192 87.624 ;
    END
  END o[490]
  PIN o[491]
    DIRECTION OUTPUT ;
    USE SIGNAL ;
    PORT
      LAYER M4 ;
        RECT  0 87.792 0.192 87.816 ;
    END
  END o[491]
  PIN o[492]
    DIRECTION OUTPUT ;
    USE SIGNAL ;
    PORT
      LAYER M4 ;
        RECT  0 87.936 0.192 87.96 ;
    END
  END o[492]
  PIN o[493]
    DIRECTION OUTPUT ;
    USE SIGNAL ;
    PORT
      LAYER M4 ;
        RECT  0 88.128 0.192 88.152 ;
    END
  END o[493]
  PIN o[494]
    DIRECTION OUTPUT ;
    USE SIGNAL ;
    PORT
      LAYER M4 ;
        RECT  0 88.272 0.192 88.296 ;
    END
  END o[494]
  PIN o[495]
    DIRECTION OUTPUT ;
    USE SIGNAL ;
    PORT
      LAYER M4 ;
        RECT  0 88.464 0.192 88.488 ;
    END
  END o[495]
  PIN o[496]
    DIRECTION OUTPUT ;
    USE SIGNAL ;
    PORT
      LAYER M4 ;
        RECT  0 88.608 0.192 88.632 ;
    END
  END o[496]
  PIN o[497]
    DIRECTION OUTPUT ;
    USE SIGNAL ;
    PORT
      LAYER M4 ;
        RECT  0 88.8 0.192 88.824 ;
    END
  END o[497]
  PIN o[498]
    DIRECTION OUTPUT ;
    USE SIGNAL ;
    PORT
      LAYER M4 ;
        RECT  0 88.992 0.192 89.016 ;
    END
  END o[498]
  PIN o[499]
    DIRECTION OUTPUT ;
    USE SIGNAL ;
    PORT
      LAYER M4 ;
        RECT  0 89.136 0.192 89.16 ;
    END
  END o[499]
  PIN o[49]
    DIRECTION OUTPUT ;
    USE SIGNAL ;
    PORT
      LAYER M4 ;
        RECT  0 12.624 0.192 12.648 ;
    END
  END o[49]
  PIN o[4]
    DIRECTION OUTPUT ;
    USE SIGNAL ;
    PORT
      LAYER M4 ;
        RECT  0 4.992 0.192 5.016 ;
    END
  END o[4]
  PIN o[500]
    DIRECTION OUTPUT ;
    USE SIGNAL ;
    PORT
      LAYER M4 ;
        RECT  0 89.328 0.192 89.352 ;
    END
  END o[500]
  PIN o[501]
    DIRECTION OUTPUT ;
    USE SIGNAL ;
    PORT
      LAYER M4 ;
        RECT  0 89.472 0.192 89.496 ;
    END
  END o[501]
  PIN o[502]
    DIRECTION OUTPUT ;
    USE SIGNAL ;
    PORT
      LAYER M4 ;
        RECT  0 89.664 0.192 89.688 ;
    END
  END o[502]
  PIN o[503]
    DIRECTION OUTPUT ;
    USE SIGNAL ;
    PORT
      LAYER M4 ;
        RECT  0 89.808 0.192 89.832 ;
    END
  END o[503]
  PIN o[504]
    DIRECTION OUTPUT ;
    USE SIGNAL ;
    PORT
      LAYER M4 ;
        RECT  0 90 0.192 90.024 ;
    END
  END o[504]
  PIN o[505]
    DIRECTION OUTPUT ;
    USE SIGNAL ;
    PORT
      LAYER M4 ;
        RECT  0 90.144 0.192 90.168 ;
    END
  END o[505]
  PIN o[506]
    DIRECTION OUTPUT ;
    USE SIGNAL ;
    PORT
      LAYER M4 ;
        RECT  0 90.336 0.192 90.36 ;
    END
  END o[506]
  PIN o[507]
    DIRECTION OUTPUT ;
    USE SIGNAL ;
    PORT
      LAYER M4 ;
        RECT  0 90.48 0.192 90.504 ;
    END
  END o[507]
  PIN o[508]
    DIRECTION OUTPUT ;
    USE SIGNAL ;
    PORT
      LAYER M4 ;
        RECT  0 90.672 0.192 90.696 ;
    END
  END o[508]
  PIN o[509]
    DIRECTION OUTPUT ;
    USE SIGNAL ;
    PORT
      LAYER M4 ;
        RECT  0 90.816 0.192 90.84 ;
    END
  END o[509]
  PIN o[50]
    DIRECTION OUTPUT ;
    USE SIGNAL ;
    PORT
      LAYER M4 ;
        RECT  0 12.816 0.192 12.84 ;
    END
  END o[50]
  PIN o[510]
    DIRECTION OUTPUT ;
    USE SIGNAL ;
    PORT
      LAYER M4 ;
        RECT  0 91.008 0.192 91.032 ;
    END
  END o[510]
  PIN o[511]
    DIRECTION OUTPUT ;
    USE SIGNAL ;
    PORT
      LAYER M4 ;
        RECT  0 91.152 0.192 91.176 ;
    END
  END o[511]
  PIN o[512]
    DIRECTION OUTPUT ;
    USE SIGNAL ;
    PORT
      LAYER M4 ;
        RECT  0 91.344 0.192 91.368 ;
    END
  END o[512]
  PIN o[513]
    DIRECTION OUTPUT ;
    USE SIGNAL ;
    PORT
      LAYER M4 ;
        RECT  0 91.536 0.192 91.56 ;
    END
  END o[513]
  PIN o[514]
    DIRECTION OUTPUT ;
    USE SIGNAL ;
    PORT
      LAYER M4 ;
        RECT  0 91.68 0.192 91.704 ;
    END
  END o[514]
  PIN o[515]
    DIRECTION OUTPUT ;
    USE SIGNAL ;
    PORT
      LAYER M4 ;
        RECT  0 91.872 0.192 91.896 ;
    END
  END o[515]
  PIN o[516]
    DIRECTION OUTPUT ;
    USE SIGNAL ;
    PORT
      LAYER M4 ;
        RECT  0 92.016 0.192 92.04 ;
    END
  END o[516]
  PIN o[517]
    DIRECTION OUTPUT ;
    USE SIGNAL ;
    PORT
      LAYER M4 ;
        RECT  0 92.208 0.192 92.232 ;
    END
  END o[517]
  PIN o[518]
    DIRECTION OUTPUT ;
    USE SIGNAL ;
    PORT
      LAYER M4 ;
        RECT  0 92.352 0.192 92.376 ;
    END
  END o[518]
  PIN o[519]
    DIRECTION OUTPUT ;
    USE SIGNAL ;
    PORT
      LAYER M4 ;
        RECT  0 92.544 0.192 92.568 ;
    END
  END o[519]
  PIN o[51]
    DIRECTION OUTPUT ;
    USE SIGNAL ;
    PORT
      LAYER M4 ;
        RECT  0 12.96 0.192 12.984 ;
    END
  END o[51]
  PIN o[520]
    DIRECTION OUTPUT ;
    USE SIGNAL ;
    PORT
      LAYER M4 ;
        RECT  0 92.688 0.192 92.712 ;
    END
  END o[520]
  PIN o[521]
    DIRECTION OUTPUT ;
    USE SIGNAL ;
    PORT
      LAYER M4 ;
        RECT  0 92.88 0.192 92.904 ;
    END
  END o[521]
  PIN o[522]
    DIRECTION OUTPUT ;
    USE SIGNAL ;
    PORT
      LAYER M4 ;
        RECT  0 93.024 0.192 93.048 ;
    END
  END o[522]
  PIN o[523]
    DIRECTION OUTPUT ;
    USE SIGNAL ;
    PORT
      LAYER M4 ;
        RECT  0 93.216 0.192 93.24 ;
    END
  END o[523]
  PIN o[524]
    DIRECTION OUTPUT ;
    USE SIGNAL ;
    PORT
      LAYER M4 ;
        RECT  0 93.36 0.192 93.384 ;
    END
  END o[524]
  PIN o[525]
    DIRECTION OUTPUT ;
    USE SIGNAL ;
    PORT
      LAYER M4 ;
        RECT  0 93.552 0.192 93.576 ;
    END
  END o[525]
  PIN o[526]
    DIRECTION OUTPUT ;
    USE SIGNAL ;
    PORT
      LAYER M4 ;
        RECT  0 93.696 0.192 93.72 ;
    END
  END o[526]
  PIN o[527]
    DIRECTION OUTPUT ;
    USE SIGNAL ;
    PORT
      LAYER M4 ;
        RECT  0 93.888 0.192 93.912 ;
    END
  END o[527]
  PIN o[528]
    DIRECTION OUTPUT ;
    USE SIGNAL ;
    PORT
      LAYER M4 ;
        RECT  0 94.08 0.192 94.104 ;
    END
  END o[528]
  PIN o[529]
    DIRECTION OUTPUT ;
    USE SIGNAL ;
    PORT
      LAYER M4 ;
        RECT  0 94.224 0.192 94.248 ;
    END
  END o[529]
  PIN o[52]
    DIRECTION OUTPUT ;
    USE SIGNAL ;
    PORT
      LAYER M4 ;
        RECT  0 13.152 0.192 13.176 ;
    END
  END o[52]
  PIN o[530]
    DIRECTION OUTPUT ;
    USE SIGNAL ;
    PORT
      LAYER M4 ;
        RECT  0 94.416 0.192 94.44 ;
    END
  END o[530]
  PIN o[531]
    DIRECTION OUTPUT ;
    USE SIGNAL ;
    PORT
      LAYER M4 ;
        RECT  0 94.56 0.192 94.584 ;
    END
  END o[531]
  PIN o[532]
    DIRECTION OUTPUT ;
    USE SIGNAL ;
    PORT
      LAYER M4 ;
        RECT  0 94.752 0.192 94.776 ;
    END
  END o[532]
  PIN o[533]
    DIRECTION OUTPUT ;
    USE SIGNAL ;
    PORT
      LAYER M4 ;
        RECT  0 94.896 0.192 94.92 ;
    END
  END o[533]
  PIN o[534]
    DIRECTION OUTPUT ;
    USE SIGNAL ;
    PORT
      LAYER M4 ;
        RECT  0 95.088 0.192 95.112 ;
    END
  END o[534]
  PIN o[535]
    DIRECTION OUTPUT ;
    USE SIGNAL ;
    PORT
      LAYER M4 ;
        RECT  0 95.232 0.192 95.256 ;
    END
  END o[535]
  PIN o[536]
    DIRECTION OUTPUT ;
    USE SIGNAL ;
    PORT
      LAYER M4 ;
        RECT  0 95.424 0.192 95.448 ;
    END
  END o[536]
  PIN o[537]
    DIRECTION OUTPUT ;
    USE SIGNAL ;
    PORT
      LAYER M4 ;
        RECT  0 95.568 0.192 95.592 ;
    END
  END o[537]
  PIN o[538]
    DIRECTION OUTPUT ;
    USE SIGNAL ;
    PORT
      LAYER M4 ;
        RECT  0 95.76 0.192 95.784 ;
    END
  END o[538]
  PIN o[539]
    DIRECTION OUTPUT ;
    USE SIGNAL ;
    PORT
      LAYER M4 ;
        RECT  0 95.904 0.192 95.928 ;
    END
  END o[539]
  PIN o[53]
    DIRECTION OUTPUT ;
    USE SIGNAL ;
    PORT
      LAYER M4 ;
        RECT  0 13.344 0.192 13.368 ;
    END
  END o[53]
  PIN o[540]
    DIRECTION OUTPUT ;
    USE SIGNAL ;
    PORT
      LAYER M4 ;
        RECT  0 96.096 0.192 96.12 ;
    END
  END o[540]
  PIN o[541]
    DIRECTION OUTPUT ;
    USE SIGNAL ;
    PORT
      LAYER M4 ;
        RECT  0 96.24 0.192 96.264 ;
    END
  END o[541]
  PIN o[542]
    DIRECTION OUTPUT ;
    USE SIGNAL ;
    PORT
      LAYER M4 ;
        RECT  0 96.432 0.192 96.456 ;
    END
  END o[542]
  PIN o[543]
    DIRECTION OUTPUT ;
    USE SIGNAL ;
    PORT
      LAYER M4 ;
        RECT  0 96.624 0.192 96.648 ;
    END
  END o[543]
  PIN o[544]
    DIRECTION OUTPUT ;
    USE SIGNAL ;
    PORT
      LAYER M4 ;
        RECT  0 96.768 0.192 96.792 ;
    END
  END o[544]
  PIN o[545]
    DIRECTION OUTPUT ;
    USE SIGNAL ;
    PORT
      LAYER M4 ;
        RECT  0 96.96 0.192 96.984 ;
    END
  END o[545]
  PIN o[546]
    DIRECTION OUTPUT ;
    USE SIGNAL ;
    PORT
      LAYER M4 ;
        RECT  0 97.104 0.192 97.128 ;
    END
  END o[546]
  PIN o[547]
    DIRECTION OUTPUT ;
    USE SIGNAL ;
    PORT
      LAYER M4 ;
        RECT  0 97.296 0.192 97.32 ;
    END
  END o[547]
  PIN o[548]
    DIRECTION OUTPUT ;
    USE SIGNAL ;
    PORT
      LAYER M4 ;
        RECT  0 97.44 0.192 97.464 ;
    END
  END o[548]
  PIN o[549]
    DIRECTION OUTPUT ;
    USE SIGNAL ;
    PORT
      LAYER M4 ;
        RECT  0 97.632 0.192 97.656 ;
    END
  END o[549]
  PIN o[54]
    DIRECTION OUTPUT ;
    USE SIGNAL ;
    PORT
      LAYER M4 ;
        RECT  0 13.488 0.192 13.512 ;
    END
  END o[54]
  PIN o[550]
    DIRECTION OUTPUT ;
    USE SIGNAL ;
    PORT
      LAYER M4 ;
        RECT  0 97.776 0.192 97.8 ;
    END
  END o[550]
  PIN o[551]
    DIRECTION OUTPUT ;
    USE SIGNAL ;
    PORT
      LAYER M4 ;
        RECT  0 97.968 0.192 97.992 ;
    END
  END o[551]
  PIN o[552]
    DIRECTION OUTPUT ;
    USE SIGNAL ;
    PORT
      LAYER M4 ;
        RECT  0 98.112 0.192 98.136 ;
    END
  END o[552]
  PIN o[553]
    DIRECTION OUTPUT ;
    USE SIGNAL ;
    PORT
      LAYER M4 ;
        RECT  0 98.304 0.192 98.328 ;
    END
  END o[553]
  PIN o[554]
    DIRECTION OUTPUT ;
    USE SIGNAL ;
    PORT
      LAYER M4 ;
        RECT  0 98.448 0.192 98.472 ;
    END
  END o[554]
  PIN o[555]
    DIRECTION OUTPUT ;
    USE SIGNAL ;
    PORT
      LAYER M4 ;
        RECT  0 98.64 0.192 98.664 ;
    END
  END o[555]
  PIN o[556]
    DIRECTION OUTPUT ;
    USE SIGNAL ;
    PORT
      LAYER M4 ;
        RECT  0 98.784 0.192 98.808 ;
    END
  END o[556]
  PIN o[557]
    DIRECTION OUTPUT ;
    USE SIGNAL ;
    PORT
      LAYER M4 ;
        RECT  0 98.976 0.192 99 ;
    END
  END o[557]
  PIN o[558]
    DIRECTION OUTPUT ;
    USE SIGNAL ;
    PORT
      LAYER M4 ;
        RECT  0 99.168 0.192 99.192 ;
    END
  END o[558]
  PIN o[559]
    DIRECTION OUTPUT ;
    USE SIGNAL ;
    PORT
      LAYER M4 ;
        RECT  0 99.312 0.192 99.336 ;
    END
  END o[559]
  PIN o[55]
    DIRECTION OUTPUT ;
    USE SIGNAL ;
    PORT
      LAYER M4 ;
        RECT  0 13.68 0.192 13.704 ;
    END
  END o[55]
  PIN o[560]
    DIRECTION OUTPUT ;
    USE SIGNAL ;
    PORT
      LAYER M4 ;
        RECT  0 99.504 0.192 99.528 ;
    END
  END o[560]
  PIN o[561]
    DIRECTION OUTPUT ;
    USE SIGNAL ;
    PORT
      LAYER M4 ;
        RECT  0 99.648 0.192 99.672 ;
    END
  END o[561]
  PIN o[562]
    DIRECTION OUTPUT ;
    USE SIGNAL ;
    PORT
      LAYER M4 ;
        RECT  0 99.84 0.192 99.864 ;
    END
  END o[562]
  PIN o[563]
    DIRECTION OUTPUT ;
    USE SIGNAL ;
    PORT
      LAYER M4 ;
        RECT  0 99.984 0.192 100.008 ;
    END
  END o[563]
  PIN o[564]
    DIRECTION OUTPUT ;
    USE SIGNAL ;
    PORT
      LAYER M4 ;
        RECT  0 100.176 0.192 100.2 ;
    END
  END o[564]
  PIN o[565]
    DIRECTION OUTPUT ;
    USE SIGNAL ;
    PORT
      LAYER M4 ;
        RECT  0 100.32 0.192 100.344 ;
    END
  END o[565]
  PIN o[566]
    DIRECTION OUTPUT ;
    USE SIGNAL ;
    PORT
      LAYER M4 ;
        RECT  0 100.512 0.192 100.536 ;
    END
  END o[566]
  PIN o[567]
    DIRECTION OUTPUT ;
    USE SIGNAL ;
    PORT
      LAYER M4 ;
        RECT  0 100.656 0.192 100.68 ;
    END
  END o[567]
  PIN o[568]
    DIRECTION OUTPUT ;
    USE SIGNAL ;
    PORT
      LAYER M4 ;
        RECT  0 100.848 0.192 100.872 ;
    END
  END o[568]
  PIN o[569]
    DIRECTION OUTPUT ;
    USE SIGNAL ;
    PORT
      LAYER M4 ;
        RECT  0 100.992 0.192 101.016 ;
    END
  END o[569]
  PIN o[56]
    DIRECTION OUTPUT ;
    USE SIGNAL ;
    PORT
      LAYER M4 ;
        RECT  0 13.824 0.192 13.848 ;
    END
  END o[56]
  PIN o[570]
    DIRECTION OUTPUT ;
    USE SIGNAL ;
    PORT
      LAYER M4 ;
        RECT  0 101.184 0.192 101.208 ;
    END
  END o[570]
  PIN o[571]
    DIRECTION OUTPUT ;
    USE SIGNAL ;
    PORT
      LAYER M4 ;
        RECT  0 101.328 0.192 101.352 ;
    END
  END o[571]
  PIN o[572]
    DIRECTION OUTPUT ;
    USE SIGNAL ;
    PORT
      LAYER M4 ;
        RECT  0 101.52 0.192 101.544 ;
    END
  END o[572]
  PIN o[573]
    DIRECTION OUTPUT ;
    USE SIGNAL ;
    PORT
      LAYER M4 ;
        RECT  0 101.712 0.192 101.736 ;
    END
  END o[573]
  PIN o[574]
    DIRECTION OUTPUT ;
    USE SIGNAL ;
    PORT
      LAYER M4 ;
        RECT  0 101.856 0.192 101.88 ;
    END
  END o[574]
  PIN o[575]
    DIRECTION OUTPUT ;
    USE SIGNAL ;
    PORT
      LAYER M4 ;
        RECT  0 102.048 0.192 102.072 ;
    END
  END o[575]
  PIN o[576]
    DIRECTION OUTPUT ;
    USE SIGNAL ;
    PORT
      LAYER M4 ;
        RECT  0 102.192 0.192 102.216 ;
    END
  END o[576]
  PIN o[577]
    DIRECTION OUTPUT ;
    USE SIGNAL ;
    PORT
      LAYER M4 ;
        RECT  0 102.384 0.192 102.408 ;
    END
  END o[577]
  PIN o[578]
    DIRECTION OUTPUT ;
    USE SIGNAL ;
    PORT
      LAYER M4 ;
        RECT  0 102.528 0.192 102.552 ;
    END
  END o[578]
  PIN o[579]
    DIRECTION OUTPUT ;
    USE SIGNAL ;
    PORT
      LAYER M4 ;
        RECT  0 102.72 0.192 102.744 ;
    END
  END o[579]
  PIN o[57]
    DIRECTION OUTPUT ;
    USE SIGNAL ;
    PORT
      LAYER M4 ;
        RECT  0 14.016 0.192 14.04 ;
    END
  END o[57]
  PIN o[580]
    DIRECTION OUTPUT ;
    USE SIGNAL ;
    PORT
      LAYER M4 ;
        RECT  0 102.864 0.192 102.888 ;
    END
  END o[580]
  PIN o[581]
    DIRECTION OUTPUT ;
    USE SIGNAL ;
    PORT
      LAYER M4 ;
        RECT  0 103.056 0.192 103.08 ;
    END
  END o[581]
  PIN o[582]
    DIRECTION OUTPUT ;
    USE SIGNAL ;
    PORT
      LAYER M4 ;
        RECT  0 103.2 0.192 103.224 ;
    END
  END o[582]
  PIN o[583]
    DIRECTION OUTPUT ;
    USE SIGNAL ;
    PORT
      LAYER M4 ;
        RECT  0 103.392 0.192 103.416 ;
    END
  END o[583]
  PIN o[584]
    DIRECTION OUTPUT ;
    USE SIGNAL ;
    PORT
      LAYER M4 ;
        RECT  0 103.536 0.192 103.56 ;
    END
  END o[584]
  PIN o[585]
    DIRECTION OUTPUT ;
    USE SIGNAL ;
    PORT
      LAYER M4 ;
        RECT  0 103.728 0.192 103.752 ;
    END
  END o[585]
  PIN o[586]
    DIRECTION OUTPUT ;
    USE SIGNAL ;
    PORT
      LAYER M4 ;
        RECT  0 103.92 0.192 103.944 ;
    END
  END o[586]
  PIN o[587]
    DIRECTION OUTPUT ;
    USE SIGNAL ;
    PORT
      LAYER M4 ;
        RECT  0 104.064 0.192 104.088 ;
    END
  END o[587]
  PIN o[588]
    DIRECTION OUTPUT ;
    USE SIGNAL ;
    PORT
      LAYER M4 ;
        RECT  0 104.256 0.192 104.28 ;
    END
  END o[588]
  PIN o[589]
    DIRECTION OUTPUT ;
    USE SIGNAL ;
    PORT
      LAYER M4 ;
        RECT  0 104.4 0.192 104.424 ;
    END
  END o[589]
  PIN o[58]
    DIRECTION OUTPUT ;
    USE SIGNAL ;
    PORT
      LAYER M4 ;
        RECT  0 14.16 0.192 14.184 ;
    END
  END o[58]
  PIN o[590]
    DIRECTION OUTPUT ;
    USE SIGNAL ;
    PORT
      LAYER M4 ;
        RECT  0 104.592 0.192 104.616 ;
    END
  END o[590]
  PIN o[591]
    DIRECTION OUTPUT ;
    USE SIGNAL ;
    PORT
      LAYER M4 ;
        RECT  0 104.736 0.192 104.76 ;
    END
  END o[591]
  PIN o[592]
    DIRECTION OUTPUT ;
    USE SIGNAL ;
    PORT
      LAYER M4 ;
        RECT  0 104.928 0.192 104.952 ;
    END
  END o[592]
  PIN o[593]
    DIRECTION OUTPUT ;
    USE SIGNAL ;
    PORT
      LAYER M4 ;
        RECT  0 105.072 0.192 105.096 ;
    END
  END o[593]
  PIN o[594]
    DIRECTION OUTPUT ;
    USE SIGNAL ;
    PORT
      LAYER M4 ;
        RECT  0 105.264 0.192 105.288 ;
    END
  END o[594]
  PIN o[595]
    DIRECTION OUTPUT ;
    USE SIGNAL ;
    PORT
      LAYER M4 ;
        RECT  0 105.408 0.192 105.432 ;
    END
  END o[595]
  PIN o[596]
    DIRECTION OUTPUT ;
    USE SIGNAL ;
    PORT
      LAYER M4 ;
        RECT  0 105.6 0.192 105.624 ;
    END
  END o[596]
  PIN o[597]
    DIRECTION OUTPUT ;
    USE SIGNAL ;
    PORT
      LAYER M4 ;
        RECT  0 105.744 0.192 105.768 ;
    END
  END o[597]
  PIN o[598]
    DIRECTION OUTPUT ;
    USE SIGNAL ;
    PORT
      LAYER M4 ;
        RECT  0 105.936 0.192 105.96 ;
    END
  END o[598]
  PIN o[599]
    DIRECTION OUTPUT ;
    USE SIGNAL ;
    PORT
      LAYER M4 ;
        RECT  0 106.08 0.192 106.104 ;
    END
  END o[599]
  PIN o[59]
    DIRECTION OUTPUT ;
    USE SIGNAL ;
    PORT
      LAYER M4 ;
        RECT  0 14.352 0.192 14.376 ;
    END
  END o[59]
  PIN o[5]
    DIRECTION OUTPUT ;
    USE SIGNAL ;
    PORT
      LAYER M4 ;
        RECT  0 5.184 0.192 5.208 ;
    END
  END o[5]
  PIN o[600]
    DIRECTION OUTPUT ;
    USE SIGNAL ;
    PORT
      LAYER M4 ;
        RECT  0 106.272 0.192 106.296 ;
    END
  END o[600]
  PIN o[601]
    DIRECTION OUTPUT ;
    USE SIGNAL ;
    PORT
      LAYER M4 ;
        RECT  0 106.464 0.192 106.488 ;
    END
  END o[601]
  PIN o[602]
    DIRECTION OUTPUT ;
    USE SIGNAL ;
    PORT
      LAYER M4 ;
        RECT  0 106.608 0.192 106.632 ;
    END
  END o[602]
  PIN o[603]
    DIRECTION OUTPUT ;
    USE SIGNAL ;
    PORT
      LAYER M4 ;
        RECT  0 106.8 0.192 106.824 ;
    END
  END o[603]
  PIN o[604]
    DIRECTION OUTPUT ;
    USE SIGNAL ;
    PORT
      LAYER M4 ;
        RECT  0 106.944 0.192 106.968 ;
    END
  END o[604]
  PIN o[605]
    DIRECTION OUTPUT ;
    USE SIGNAL ;
    PORT
      LAYER M4 ;
        RECT  0 107.136 0.192 107.16 ;
    END
  END o[605]
  PIN o[606]
    DIRECTION OUTPUT ;
    USE SIGNAL ;
    PORT
      LAYER M4 ;
        RECT  0 107.28 0.192 107.304 ;
    END
  END o[606]
  PIN o[607]
    DIRECTION OUTPUT ;
    USE SIGNAL ;
    PORT
      LAYER M4 ;
        RECT  0 107.472 0.192 107.496 ;
    END
  END o[607]
  PIN o[608]
    DIRECTION OUTPUT ;
    USE SIGNAL ;
    PORT
      LAYER M4 ;
        RECT  0 107.616 0.192 107.64 ;
    END
  END o[608]
  PIN o[609]
    DIRECTION OUTPUT ;
    USE SIGNAL ;
    PORT
      LAYER M4 ;
        RECT  0 107.808 0.192 107.832 ;
    END
  END o[609]
  PIN o[60]
    DIRECTION OUTPUT ;
    USE SIGNAL ;
    PORT
      LAYER M4 ;
        RECT  0 14.496 0.192 14.52 ;
    END
  END o[60]
  PIN o[610]
    DIRECTION OUTPUT ;
    USE SIGNAL ;
    PORT
      LAYER M4 ;
        RECT  0 107.952 0.192 107.976 ;
    END
  END o[610]
  PIN o[611]
    DIRECTION OUTPUT ;
    USE SIGNAL ;
    PORT
      LAYER M4 ;
        RECT  0 108.144 0.192 108.168 ;
    END
  END o[611]
  PIN o[612]
    DIRECTION OUTPUT ;
    USE SIGNAL ;
    PORT
      LAYER M4 ;
        RECT  0 108.288 0.192 108.312 ;
    END
  END o[612]
  PIN o[613]
    DIRECTION OUTPUT ;
    USE SIGNAL ;
    PORT
      LAYER M4 ;
        RECT  0 108.48 0.192 108.504 ;
    END
  END o[613]
  PIN o[614]
    DIRECTION OUTPUT ;
    USE SIGNAL ;
    PORT
      LAYER M4 ;
        RECT  0 108.624 0.192 108.648 ;
    END
  END o[614]
  PIN o[615]
    DIRECTION OUTPUT ;
    USE SIGNAL ;
    PORT
      LAYER M4 ;
        RECT  0 108.816 0.192 108.84 ;
    END
  END o[615]
  PIN o[616]
    DIRECTION OUTPUT ;
    USE SIGNAL ;
    PORT
      LAYER M4 ;
        RECT  0 109.008 0.192 109.032 ;
    END
  END o[616]
  PIN o[617]
    DIRECTION OUTPUT ;
    USE SIGNAL ;
    PORT
      LAYER M4 ;
        RECT  0 109.152 0.192 109.176 ;
    END
  END o[617]
  PIN o[618]
    DIRECTION OUTPUT ;
    USE SIGNAL ;
    PORT
      LAYER M4 ;
        RECT  0 109.344 0.192 109.368 ;
    END
  END o[618]
  PIN o[619]
    DIRECTION OUTPUT ;
    USE SIGNAL ;
    PORT
      LAYER M4 ;
        RECT  0 109.488 0.192 109.512 ;
    END
  END o[619]
  PIN o[61]
    DIRECTION OUTPUT ;
    USE SIGNAL ;
    PORT
      LAYER M4 ;
        RECT  0 14.688 0.192 14.712 ;
    END
  END o[61]
  PIN o[620]
    DIRECTION OUTPUT ;
    USE SIGNAL ;
    PORT
      LAYER M4 ;
        RECT  0 109.68 0.192 109.704 ;
    END
  END o[620]
  PIN o[621]
    DIRECTION OUTPUT ;
    USE SIGNAL ;
    PORT
      LAYER M4 ;
        RECT  0 109.824 0.192 109.848 ;
    END
  END o[621]
  PIN o[622]
    DIRECTION OUTPUT ;
    USE SIGNAL ;
    PORT
      LAYER M4 ;
        RECT  0 110.016 0.192 110.04 ;
    END
  END o[622]
  PIN o[623]
    DIRECTION OUTPUT ;
    USE SIGNAL ;
    PORT
      LAYER M4 ;
        RECT  0 110.16 0.192 110.184 ;
    END
  END o[623]
  PIN o[62]
    DIRECTION OUTPUT ;
    USE SIGNAL ;
    PORT
      LAYER M4 ;
        RECT  0 14.832 0.192 14.856 ;
    END
  END o[62]
  PIN o[63]
    DIRECTION OUTPUT ;
    USE SIGNAL ;
    PORT
      LAYER M4 ;
        RECT  0 15.024 0.192 15.048 ;
    END
  END o[63]
  PIN o[64]
    DIRECTION OUTPUT ;
    USE SIGNAL ;
    PORT
      LAYER M4 ;
        RECT  0 15.168 0.192 15.192 ;
    END
  END o[64]
  PIN o[65]
    DIRECTION OUTPUT ;
    USE SIGNAL ;
    PORT
      LAYER M4 ;
        RECT  0 15.36 0.192 15.384 ;
    END
  END o[65]
  PIN o[66]
    DIRECTION OUTPUT ;
    USE SIGNAL ;
    PORT
      LAYER M4 ;
        RECT  0 15.504 0.192 15.528 ;
    END
  END o[66]
  PIN o[67]
    DIRECTION OUTPUT ;
    USE SIGNAL ;
    PORT
      LAYER M4 ;
        RECT  0 15.696 0.192 15.72 ;
    END
  END o[67]
  PIN o[68]
    DIRECTION OUTPUT ;
    USE SIGNAL ;
    PORT
      LAYER M4 ;
        RECT  0 15.888 0.192 15.912 ;
    END
  END o[68]
  PIN o[69]
    DIRECTION OUTPUT ;
    USE SIGNAL ;
    PORT
      LAYER M4 ;
        RECT  0 16.032 0.192 16.056 ;
    END
  END o[69]
  PIN o[6]
    DIRECTION OUTPUT ;
    USE SIGNAL ;
    PORT
      LAYER M4 ;
        RECT  0 5.328 0.192 5.352 ;
    END
  END o[6]
  PIN o[70]
    DIRECTION OUTPUT ;
    USE SIGNAL ;
    PORT
      LAYER M4 ;
        RECT  0 16.224 0.192 16.248 ;
    END
  END o[70]
  PIN o[71]
    DIRECTION OUTPUT ;
    USE SIGNAL ;
    PORT
      LAYER M4 ;
        RECT  0 16.368 0.192 16.392 ;
    END
  END o[71]
  PIN o[72]
    DIRECTION OUTPUT ;
    USE SIGNAL ;
    PORT
      LAYER M4 ;
        RECT  0 16.56 0.192 16.584 ;
    END
  END o[72]
  PIN o[73]
    DIRECTION OUTPUT ;
    USE SIGNAL ;
    PORT
      LAYER M4 ;
        RECT  0 16.704 0.192 16.728 ;
    END
  END o[73]
  PIN o[74]
    DIRECTION OUTPUT ;
    USE SIGNAL ;
    PORT
      LAYER M4 ;
        RECT  0 16.896 0.192 16.92 ;
    END
  END o[74]
  PIN o[75]
    DIRECTION OUTPUT ;
    USE SIGNAL ;
    PORT
      LAYER M4 ;
        RECT  0 17.04 0.192 17.064 ;
    END
  END o[75]
  PIN o[76]
    DIRECTION OUTPUT ;
    USE SIGNAL ;
    PORT
      LAYER M4 ;
        RECT  0 17.232 0.192 17.256 ;
    END
  END o[76]
  PIN o[77]
    DIRECTION OUTPUT ;
    USE SIGNAL ;
    PORT
      LAYER M4 ;
        RECT  0 17.376 0.192 17.4 ;
    END
  END o[77]
  PIN o[78]
    DIRECTION OUTPUT ;
    USE SIGNAL ;
    PORT
      LAYER M4 ;
        RECT  0 17.568 0.192 17.592 ;
    END
  END o[78]
  PIN o[79]
    DIRECTION OUTPUT ;
    USE SIGNAL ;
    PORT
      LAYER M4 ;
        RECT  0 17.712 0.192 17.736 ;
    END
  END o[79]
  PIN o[7]
    DIRECTION OUTPUT ;
    USE SIGNAL ;
    PORT
      LAYER M4 ;
        RECT  0 5.52 0.192 5.544 ;
    END
  END o[7]
  PIN o[80]
    DIRECTION OUTPUT ;
    USE SIGNAL ;
    PORT
      LAYER M4 ;
        RECT  0 17.904 0.192 17.928 ;
    END
  END o[80]
  PIN o[81]
    DIRECTION OUTPUT ;
    USE SIGNAL ;
    PORT
      LAYER M4 ;
        RECT  0 18.048 0.192 18.072 ;
    END
  END o[81]
  PIN o[82]
    DIRECTION OUTPUT ;
    USE SIGNAL ;
    PORT
      LAYER M4 ;
        RECT  0 18.24 0.192 18.264 ;
    END
  END o[82]
  PIN o[83]
    DIRECTION OUTPUT ;
    USE SIGNAL ;
    PORT
      LAYER M4 ;
        RECT  0 18.432 0.192 18.456 ;
    END
  END o[83]
  PIN o[84]
    DIRECTION OUTPUT ;
    USE SIGNAL ;
    PORT
      LAYER M4 ;
        RECT  0 18.576 0.192 18.6 ;
    END
  END o[84]
  PIN o[85]
    DIRECTION OUTPUT ;
    USE SIGNAL ;
    PORT
      LAYER M4 ;
        RECT  0 18.768 0.192 18.792 ;
    END
  END o[85]
  PIN o[86]
    DIRECTION OUTPUT ;
    USE SIGNAL ;
    PORT
      LAYER M4 ;
        RECT  0 18.912 0.192 18.936 ;
    END
  END o[86]
  PIN o[87]
    DIRECTION OUTPUT ;
    USE SIGNAL ;
    PORT
      LAYER M4 ;
        RECT  0 19.104 0.192 19.128 ;
    END
  END o[87]
  PIN o[88]
    DIRECTION OUTPUT ;
    USE SIGNAL ;
    PORT
      LAYER M4 ;
        RECT  0 19.248 0.192 19.272 ;
    END
  END o[88]
  PIN o[89]
    DIRECTION OUTPUT ;
    USE SIGNAL ;
    PORT
      LAYER M4 ;
        RECT  0 19.44 0.192 19.464 ;
    END
  END o[89]
  PIN o[8]
    DIRECTION OUTPUT ;
    USE SIGNAL ;
    PORT
      LAYER M4 ;
        RECT  0 5.712 0.192 5.736 ;
    END
  END o[8]
  PIN o[90]
    DIRECTION OUTPUT ;
    USE SIGNAL ;
    PORT
      LAYER M4 ;
        RECT  0 19.584 0.192 19.608 ;
    END
  END o[90]
  PIN o[91]
    DIRECTION OUTPUT ;
    USE SIGNAL ;
    PORT
      LAYER M4 ;
        RECT  0 19.776 0.192 19.8 ;
    END
  END o[91]
  PIN o[92]
    DIRECTION OUTPUT ;
    USE SIGNAL ;
    PORT
      LAYER M4 ;
        RECT  0 19.92 0.192 19.944 ;
    END
  END o[92]
  PIN o[93]
    DIRECTION OUTPUT ;
    USE SIGNAL ;
    PORT
      LAYER M4 ;
        RECT  0 20.112 0.192 20.136 ;
    END
  END o[93]
  PIN o[94]
    DIRECTION OUTPUT ;
    USE SIGNAL ;
    PORT
      LAYER M4 ;
        RECT  0 20.256 0.192 20.28 ;
    END
  END o[94]
  PIN o[95]
    DIRECTION OUTPUT ;
    USE SIGNAL ;
    PORT
      LAYER M4 ;
        RECT  0 20.448 0.192 20.472 ;
    END
  END o[95]
  PIN o[96]
    DIRECTION OUTPUT ;
    USE SIGNAL ;
    PORT
      LAYER M4 ;
        RECT  0 20.592 0.192 20.616 ;
    END
  END o[96]
  PIN o[97]
    DIRECTION OUTPUT ;
    USE SIGNAL ;
    PORT
      LAYER M4 ;
        RECT  0 20.784 0.192 20.808 ;
    END
  END o[97]
  PIN o[98]
    DIRECTION OUTPUT ;
    USE SIGNAL ;
    PORT
      LAYER M4 ;
        RECT  0 20.976 0.192 21 ;
    END
  END o[98]
  PIN o[99]
    DIRECTION OUTPUT ;
    USE SIGNAL ;
    PORT
      LAYER M4 ;
        RECT  0 21.12 0.192 21.144 ;
    END
  END o[99]
  PIN o[9]
    DIRECTION OUTPUT ;
    USE SIGNAL ;
    PORT
      LAYER M4 ;
        RECT  0 5.856 0.192 5.88 ;
    END
  END o[9]
  PIN rs
    DIRECTION INPUT ;
    USE SIGNAL ;
    PORT
      LAYER M5 ;
        RECT  10.8 0 10.824 0.192 ;
    END
  END rs
  PIN VDD
    DIRECTION INOUT ;
    USE POWER ;
    PORT
      LAYER M5 ;
        RECT  18.792 2.151 18.912 112.329 ;
        RECT  16.092 2.151 16.212 112.329 ;
        RECT  13.392 2.151 13.512 112.329 ;
        RECT  10.692 2.151 10.812 112.329 ;
        RECT  7.992 2.151 8.112 112.329 ;
        RECT  5.292 2.151 5.412 112.329 ;
        RECT  2.592 2.151 2.712 112.329 ;
    END
  END VDD
  PIN VSS
    DIRECTION INOUT ;
    USE GROUND ;
    PORT
      LAYER M5 ;
        RECT  18.6 2.137 18.72 112.343 ;
        RECT  15.9 2.137 16.02 112.343 ;
        RECT  13.2 2.137 13.32 112.343 ;
        RECT  10.5 2.137 10.62 112.343 ;
        RECT  7.8 2.137 7.92 112.343 ;
        RECT  5.1 2.137 5.22 112.343 ;
        RECT  2.4 2.137 2.52 112.343 ;
    END
  END VSS
  OBS
    LAYER RVTN ;
     RECT  2.16 2.16 19.44 2.295 ;
     RECT  2.16 2.565 19.44 2.835 ;
     RECT  2.16 3.105 19.44 3.375 ;
     RECT  2.16 3.645 19.44 3.915 ;
     RECT  2.16 4.185 19.44 4.455 ;
     RECT  2.16 4.725 19.44 4.995 ;
     RECT  2.16 5.265 19.44 5.535 ;
     RECT  2.16 5.805 19.44 6.075 ;
     RECT  2.16 6.345 19.44 6.615 ;
     RECT  2.16 6.885 19.44 7.155 ;
     RECT  2.16 7.425 19.44 7.695 ;
     RECT  2.16 7.965 19.44 8.235 ;
     RECT  2.16 8.505 19.44 8.775 ;
     RECT  2.16 9.045 19.44 9.315 ;
     RECT  2.16 9.585 19.44 9.855 ;
     RECT  2.16 10.125 19.44 10.395 ;
     RECT  2.16 10.665 19.44 10.935 ;
     RECT  2.16 11.205 19.44 11.475 ;
     RECT  2.16 11.745 19.44 12.015 ;
     RECT  2.16 12.285 19.44 12.555 ;
     RECT  2.16 12.825 19.44 13.095 ;
     RECT  2.16 13.365 19.44 13.635 ;
     RECT  2.16 13.905 19.44 14.175 ;
     RECT  2.16 14.445 19.44 14.715 ;
     RECT  2.16 14.985 19.44 15.255 ;
     RECT  2.16 15.525 19.44 15.795 ;
     RECT  2.16 16.065 19.44 16.335 ;
     RECT  2.16 16.605 19.44 16.875 ;
     RECT  2.16 17.145 19.44 17.415 ;
     RECT  2.16 17.685 19.44 17.955 ;
     RECT  2.16 18.225 19.44 18.495 ;
     RECT  2.16 18.765 19.44 19.035 ;
     RECT  2.16 19.305 19.44 19.575 ;
     RECT  2.16 19.845 19.44 20.115 ;
     RECT  2.16 20.385 19.44 20.655 ;
     RECT  2.16 20.925 19.44 21.195 ;
     RECT  2.16 21.465 19.44 21.735 ;
     RECT  2.16 22.005 19.44 22.275 ;
     RECT  2.16 22.545 19.44 22.815 ;
     RECT  2.16 23.085 19.44 23.355 ;
     RECT  2.16 23.625 19.44 23.895 ;
     RECT  2.16 24.165 19.44 24.435 ;
     RECT  2.16 24.705 19.44 24.975 ;
     RECT  2.16 25.245 19.44 25.515 ;
     RECT  2.16 25.785 19.44 26.055 ;
     RECT  2.16 26.325 19.44 26.595 ;
     RECT  2.16 26.865 19.44 27.135 ;
     RECT  2.16 27.405 19.44 27.675 ;
     RECT  2.16 27.945 19.44 28.215 ;
     RECT  2.16 28.485 19.44 28.755 ;
     RECT  2.16 29.025 19.44 29.295 ;
     RECT  2.16 29.565 19.44 29.835 ;
     RECT  2.16 30.105 19.44 30.375 ;
     RECT  2.16 30.645 19.44 30.915 ;
     RECT  2.16 31.185 19.44 31.455 ;
     RECT  2.16 31.725 19.44 31.995 ;
     RECT  2.16 32.265 19.44 32.535 ;
     RECT  2.16 32.805 19.44 33.075 ;
     RECT  2.16 33.345 19.44 33.615 ;
     RECT  2.16 33.885 19.44 34.155 ;
     RECT  2.16 34.425 19.44 34.695 ;
     RECT  2.16 34.965 19.44 35.235 ;
     RECT  2.16 35.505 19.44 35.775 ;
     RECT  2.16 36.045 19.44 36.315 ;
     RECT  2.16 36.585 19.44 36.855 ;
     RECT  2.16 37.125 19.44 37.395 ;
     RECT  2.16 37.665 19.44 37.935 ;
     RECT  2.16 38.205 19.44 38.475 ;
     RECT  2.16 38.745 19.44 39.015 ;
     RECT  2.16 39.285 19.44 39.555 ;
     RECT  2.16 39.825 19.44 40.095 ;
     RECT  2.16 40.365 19.44 40.635 ;
     RECT  2.16 40.905 19.44 41.175 ;
     RECT  2.16 41.445 19.44 41.715 ;
     RECT  2.16 41.985 19.44 42.255 ;
     RECT  2.16 42.525 19.44 42.795 ;
     RECT  2.16 43.065 19.44 43.335 ;
     RECT  2.16 43.605 19.44 43.875 ;
     RECT  2.16 44.145 19.44 44.415 ;
     RECT  2.16 44.685 19.44 44.955 ;
     RECT  2.16 45.225 19.44 45.495 ;
     RECT  2.16 45.765 19.44 46.035 ;
     RECT  2.16 46.305 19.44 46.575 ;
     RECT  2.16 46.845 19.44 47.115 ;
     RECT  2.16 47.385 19.44 47.655 ;
     RECT  2.16 47.925 19.44 48.195 ;
     RECT  2.16 48.465 19.44 48.735 ;
     RECT  2.16 49.005 19.44 49.275 ;
     RECT  2.16 49.545 19.44 49.815 ;
     RECT  2.16 50.085 19.44 50.355 ;
     RECT  2.16 50.625 19.44 50.895 ;
     RECT  2.16 51.165 19.44 51.435 ;
     RECT  2.16 51.705 19.44 51.975 ;
     RECT  2.16 52.245 19.44 52.515 ;
     RECT  2.16 52.785 19.44 53.055 ;
     RECT  2.16 53.325 19.44 53.595 ;
     RECT  2.16 53.865 19.44 54.135 ;
     RECT  2.16 54.405 19.44 54.675 ;
     RECT  2.16 54.945 19.44 55.215 ;
     RECT  2.16 55.485 19.44 55.755 ;
     RECT  2.16 56.025 19.44 56.295 ;
     RECT  2.16 56.565 19.44 56.835 ;
     RECT  2.16 57.105 19.44 57.375 ;
     RECT  2.16 57.645 19.44 57.915 ;
     RECT  2.16 58.185 19.44 58.455 ;
     RECT  2.16 58.725 19.44 58.995 ;
     RECT  2.16 59.265 19.44 59.535 ;
     RECT  2.16 59.805 19.44 60.075 ;
     RECT  2.16 60.345 19.44 60.615 ;
     RECT  2.16 60.885 19.44 61.155 ;
     RECT  2.16 61.425 19.44 61.695 ;
     RECT  2.16 61.965 19.44 62.235 ;
     RECT  2.16 62.505 19.44 62.775 ;
     RECT  2.16 63.045 19.44 63.315 ;
     RECT  2.16 63.585 19.44 63.855 ;
     RECT  2.16 64.125 19.44 64.395 ;
     RECT  2.16 64.665 19.44 64.935 ;
     RECT  2.16 65.205 19.44 65.475 ;
     RECT  2.16 65.745 19.44 66.015 ;
     RECT  2.16 66.285 19.44 66.555 ;
     RECT  2.16 66.825 19.44 67.095 ;
     RECT  2.16 67.365 19.44 67.635 ;
     RECT  2.16 67.905 19.44 68.175 ;
     RECT  2.16 68.445 19.44 68.715 ;
     RECT  2.16 68.985 19.44 69.255 ;
     RECT  2.16 69.525 19.44 69.795 ;
     RECT  2.16 70.065 19.44 70.335 ;
     RECT  2.16 70.605 19.44 70.875 ;
     RECT  2.16 71.145 19.44 71.415 ;
     RECT  2.16 71.685 19.44 71.955 ;
     RECT  2.16 72.225 19.44 72.495 ;
     RECT  2.16 72.765 19.44 73.035 ;
     RECT  2.16 73.305 19.44 73.575 ;
     RECT  2.16 73.845 19.44 74.115 ;
     RECT  2.16 74.385 19.44 74.655 ;
     RECT  2.16 74.925 19.44 75.195 ;
     RECT  2.16 75.465 19.44 75.735 ;
     RECT  2.16 76.005 19.44 76.275 ;
     RECT  2.16 76.545 19.44 76.815 ;
     RECT  2.16 77.085 19.44 77.355 ;
     RECT  2.16 77.625 19.44 77.895 ;
     RECT  2.16 78.165 19.44 78.435 ;
     RECT  2.16 78.705 19.44 78.975 ;
     RECT  2.16 79.245 19.44 79.515 ;
     RECT  2.16 79.785 19.44 80.055 ;
     RECT  2.16 80.325 19.44 80.595 ;
     RECT  2.16 80.865 19.44 81.135 ;
     RECT  2.16 81.405 19.44 81.675 ;
     RECT  2.16 81.945 19.44 82.215 ;
     RECT  2.16 82.485 19.44 82.755 ;
     RECT  2.16 83.025 19.44 83.295 ;
     RECT  2.16 83.565 19.44 83.835 ;
     RECT  2.16 84.105 19.44 84.375 ;
     RECT  2.16 84.645 19.44 84.915 ;
     RECT  2.16 85.185 19.44 85.455 ;
     RECT  2.16 85.725 19.44 85.995 ;
     RECT  2.16 86.265 19.44 86.535 ;
     RECT  2.16 86.805 19.44 87.075 ;
     RECT  2.16 87.345 19.44 87.615 ;
     RECT  2.16 87.885 19.44 88.155 ;
     RECT  2.16 88.425 19.44 88.695 ;
     RECT  2.16 88.965 19.44 89.235 ;
     RECT  2.16 89.505 19.44 89.775 ;
     RECT  2.16 90.045 19.44 90.315 ;
     RECT  2.16 90.585 19.44 90.855 ;
     RECT  2.16 91.125 19.44 91.395 ;
     RECT  2.16 91.665 19.44 91.935 ;
     RECT  2.16 92.205 19.44 92.475 ;
     RECT  2.16 92.745 19.44 93.015 ;
     RECT  2.16 93.285 19.44 93.555 ;
     RECT  2.16 93.825 19.44 94.095 ;
     RECT  2.16 94.365 19.44 94.635 ;
     RECT  2.16 94.905 19.44 95.175 ;
     RECT  2.16 95.445 19.44 95.715 ;
     RECT  2.16 95.985 19.44 96.255 ;
     RECT  2.16 96.525 19.44 96.795 ;
     RECT  2.16 97.065 19.44 97.335 ;
     RECT  2.16 97.605 19.44 97.875 ;
     RECT  2.16 98.145 19.44 98.415 ;
     RECT  2.16 98.685 19.44 98.955 ;
     RECT  2.16 99.225 19.44 99.495 ;
     RECT  2.16 99.765 19.44 100.035 ;
     RECT  2.16 100.305 19.44 100.575 ;
     RECT  2.16 100.845 19.44 101.115 ;
     RECT  2.16 101.385 19.44 101.655 ;
     RECT  2.16 101.925 19.44 102.195 ;
     RECT  2.16 102.465 19.44 102.735 ;
     RECT  2.16 103.005 19.44 103.275 ;
     RECT  2.16 103.545 19.44 103.815 ;
     RECT  2.16 104.085 19.44 104.355 ;
     RECT  2.16 104.625 19.44 104.895 ;
     RECT  2.16 105.165 19.44 105.435 ;
     RECT  2.16 105.705 19.44 105.975 ;
     RECT  2.16 106.245 19.44 106.515 ;
     RECT  2.16 106.785 19.44 107.055 ;
     RECT  2.16 107.325 19.44 107.595 ;
     RECT  2.16 107.865 19.44 108.135 ;
     RECT  2.16 108.405 19.44 108.675 ;
     RECT  2.16 108.945 19.44 109.215 ;
     RECT  2.16 109.485 19.44 109.755 ;
     RECT  2.16 110.025 19.44 110.295 ;
     RECT  2.16 110.565 19.44 110.835 ;
     RECT  2.16 111.105 19.44 111.375 ;
     RECT  2.16 111.645 19.44 111.915 ;
     RECT  2.16 112.185 19.44 112.32 ;
    LAYER RVTP ;
     RECT  2.16 2.295 19.44 2.565 ;
     RECT  2.16 2.835 19.44 3.105 ;
     RECT  2.16 3.375 19.44 3.645 ;
     RECT  2.16 3.915 19.44 4.185 ;
     RECT  2.16 4.455 19.44 4.725 ;
     RECT  2.16 4.995 19.44 5.265 ;
     RECT  2.16 5.535 19.44 5.805 ;
     RECT  2.16 6.075 19.44 6.345 ;
     RECT  2.16 6.615 19.44 6.885 ;
     RECT  2.16 7.155 19.44 7.425 ;
     RECT  2.16 7.695 19.44 7.965 ;
     RECT  2.16 8.235 19.44 8.505 ;
     RECT  2.16 8.775 19.44 9.045 ;
     RECT  2.16 9.315 19.44 9.585 ;
     RECT  2.16 9.855 19.44 10.125 ;
     RECT  2.16 10.395 19.44 10.665 ;
     RECT  2.16 10.935 19.44 11.205 ;
     RECT  2.16 11.475 19.44 11.745 ;
     RECT  2.16 12.015 19.44 12.285 ;
     RECT  2.16 12.555 19.44 12.825 ;
     RECT  2.16 13.095 19.44 13.365 ;
     RECT  2.16 13.635 19.44 13.905 ;
     RECT  2.16 14.175 19.44 14.445 ;
     RECT  2.16 14.715 19.44 14.985 ;
     RECT  2.16 15.255 19.44 15.525 ;
     RECT  2.16 15.795 19.44 16.065 ;
     RECT  2.16 16.335 19.44 16.605 ;
     RECT  2.16 16.875 19.44 17.145 ;
     RECT  2.16 17.415 19.44 17.685 ;
     RECT  2.16 17.955 19.44 18.225 ;
     RECT  2.16 18.495 19.44 18.765 ;
     RECT  2.16 19.035 19.44 19.305 ;
     RECT  2.16 19.575 19.44 19.845 ;
     RECT  2.16 20.115 19.44 20.385 ;
     RECT  2.16 20.655 19.44 20.925 ;
     RECT  2.16 21.195 19.44 21.465 ;
     RECT  2.16 21.735 19.44 22.005 ;
     RECT  2.16 22.275 19.44 22.545 ;
     RECT  2.16 22.815 19.44 23.085 ;
     RECT  2.16 23.355 19.44 23.625 ;
     RECT  2.16 23.895 19.44 24.165 ;
     RECT  2.16 24.435 19.44 24.705 ;
     RECT  2.16 24.975 19.44 25.245 ;
     RECT  2.16 25.515 19.44 25.785 ;
     RECT  2.16 26.055 19.44 26.325 ;
     RECT  2.16 26.595 19.44 26.865 ;
     RECT  2.16 27.135 19.44 27.405 ;
     RECT  2.16 27.675 19.44 27.945 ;
     RECT  2.16 28.215 19.44 28.485 ;
     RECT  2.16 28.755 19.44 29.025 ;
     RECT  2.16 29.295 19.44 29.565 ;
     RECT  2.16 29.835 19.44 30.105 ;
     RECT  2.16 30.375 19.44 30.645 ;
     RECT  2.16 30.915 19.44 31.185 ;
     RECT  2.16 31.455 19.44 31.725 ;
     RECT  2.16 31.995 19.44 32.265 ;
     RECT  2.16 32.535 19.44 32.805 ;
     RECT  2.16 33.075 19.44 33.345 ;
     RECT  2.16 33.615 19.44 33.885 ;
     RECT  2.16 34.155 19.44 34.425 ;
     RECT  2.16 34.695 19.44 34.965 ;
     RECT  2.16 35.235 19.44 35.505 ;
     RECT  2.16 35.775 19.44 36.045 ;
     RECT  2.16 36.315 19.44 36.585 ;
     RECT  2.16 36.855 19.44 37.125 ;
     RECT  2.16 37.395 19.44 37.665 ;
     RECT  2.16 37.935 19.44 38.205 ;
     RECT  2.16 38.475 19.44 38.745 ;
     RECT  2.16 39.015 19.44 39.285 ;
     RECT  2.16 39.555 19.44 39.825 ;
     RECT  2.16 40.095 19.44 40.365 ;
     RECT  2.16 40.635 19.44 40.905 ;
     RECT  2.16 41.175 19.44 41.445 ;
     RECT  2.16 41.715 19.44 41.985 ;
     RECT  2.16 42.255 19.44 42.525 ;
     RECT  2.16 42.795 19.44 43.065 ;
     RECT  2.16 43.335 19.44 43.605 ;
     RECT  2.16 43.875 19.44 44.145 ;
     RECT  2.16 44.415 19.44 44.685 ;
     RECT  2.16 44.955 19.44 45.225 ;
     RECT  2.16 45.495 19.44 45.765 ;
     RECT  2.16 46.035 19.44 46.305 ;
     RECT  2.16 46.575 19.44 46.845 ;
     RECT  2.16 47.115 19.44 47.385 ;
     RECT  2.16 47.655 19.44 47.925 ;
     RECT  2.16 48.195 19.44 48.465 ;
     RECT  2.16 48.735 19.44 49.005 ;
     RECT  2.16 49.275 19.44 49.545 ;
     RECT  2.16 49.815 19.44 50.085 ;
     RECT  2.16 50.355 19.44 50.625 ;
     RECT  2.16 50.895 19.44 51.165 ;
     RECT  2.16 51.435 19.44 51.705 ;
     RECT  2.16 51.975 19.44 52.245 ;
     RECT  2.16 52.515 19.44 52.785 ;
     RECT  2.16 53.055 19.44 53.325 ;
     RECT  2.16 53.595 19.44 53.865 ;
     RECT  2.16 54.135 19.44 54.405 ;
     RECT  2.16 54.675 19.44 54.945 ;
     RECT  2.16 55.215 19.44 55.485 ;
     RECT  2.16 55.755 19.44 56.025 ;
     RECT  2.16 56.295 19.44 56.565 ;
     RECT  2.16 56.835 19.44 57.105 ;
     RECT  2.16 57.375 19.44 57.645 ;
     RECT  2.16 57.915 19.44 58.185 ;
     RECT  2.16 58.455 19.44 58.725 ;
     RECT  2.16 58.995 19.44 59.265 ;
     RECT  2.16 59.535 19.44 59.805 ;
     RECT  2.16 60.075 19.44 60.345 ;
     RECT  2.16 60.615 19.44 60.885 ;
     RECT  2.16 61.155 19.44 61.425 ;
     RECT  2.16 61.695 19.44 61.965 ;
     RECT  2.16 62.235 19.44 62.505 ;
     RECT  2.16 62.775 19.44 63.045 ;
     RECT  2.16 63.315 19.44 63.585 ;
     RECT  2.16 63.855 19.44 64.125 ;
     RECT  2.16 64.395 19.44 64.665 ;
     RECT  2.16 64.935 19.44 65.205 ;
     RECT  2.16 65.475 19.44 65.745 ;
     RECT  2.16 66.015 19.44 66.285 ;
     RECT  2.16 66.555 19.44 66.825 ;
     RECT  2.16 67.095 19.44 67.365 ;
     RECT  2.16 67.635 19.44 67.905 ;
     RECT  2.16 68.175 19.44 68.445 ;
     RECT  2.16 68.715 19.44 68.985 ;
     RECT  2.16 69.255 19.44 69.525 ;
     RECT  2.16 69.795 19.44 70.065 ;
     RECT  2.16 70.335 19.44 70.605 ;
     RECT  2.16 70.875 19.44 71.145 ;
     RECT  2.16 71.415 19.44 71.685 ;
     RECT  2.16 71.955 19.44 72.225 ;
     RECT  2.16 72.495 19.44 72.765 ;
     RECT  2.16 73.035 19.44 73.305 ;
     RECT  2.16 73.575 19.44 73.845 ;
     RECT  2.16 74.115 19.44 74.385 ;
     RECT  2.16 74.655 19.44 74.925 ;
     RECT  2.16 75.195 19.44 75.465 ;
     RECT  2.16 75.735 19.44 76.005 ;
     RECT  2.16 76.275 19.44 76.545 ;
     RECT  2.16 76.815 19.44 77.085 ;
     RECT  2.16 77.355 19.44 77.625 ;
     RECT  2.16 77.895 19.44 78.165 ;
     RECT  2.16 78.435 19.44 78.705 ;
     RECT  2.16 78.975 19.44 79.245 ;
     RECT  2.16 79.515 19.44 79.785 ;
     RECT  2.16 80.055 19.44 80.325 ;
     RECT  2.16 80.595 19.44 80.865 ;
     RECT  2.16 81.135 19.44 81.405 ;
     RECT  2.16 81.675 19.44 81.945 ;
     RECT  2.16 82.215 19.44 82.485 ;
     RECT  2.16 82.755 19.44 83.025 ;
     RECT  2.16 83.295 19.44 83.565 ;
     RECT  2.16 83.835 19.44 84.105 ;
     RECT  2.16 84.375 19.44 84.645 ;
     RECT  2.16 84.915 19.44 85.185 ;
     RECT  2.16 85.455 19.44 85.725 ;
     RECT  2.16 85.995 19.44 86.265 ;
     RECT  2.16 86.535 19.44 86.805 ;
     RECT  2.16 87.075 19.44 87.345 ;
     RECT  2.16 87.615 19.44 87.885 ;
     RECT  2.16 88.155 19.44 88.425 ;
     RECT  2.16 88.695 19.44 88.965 ;
     RECT  2.16 89.235 19.44 89.505 ;
     RECT  2.16 89.775 19.44 90.045 ;
     RECT  2.16 90.315 19.44 90.585 ;
     RECT  2.16 90.855 19.44 91.125 ;
     RECT  2.16 91.395 19.44 91.665 ;
     RECT  2.16 91.935 19.44 92.205 ;
     RECT  2.16 92.475 19.44 92.745 ;
     RECT  2.16 93.015 19.44 93.285 ;
     RECT  2.16 93.555 19.44 93.825 ;
     RECT  2.16 94.095 19.44 94.365 ;
     RECT  2.16 94.635 19.44 94.905 ;
     RECT  2.16 95.175 19.44 95.445 ;
     RECT  2.16 95.715 19.44 95.985 ;
     RECT  2.16 96.255 19.44 96.525 ;
     RECT  2.16 96.795 19.44 97.065 ;
     RECT  2.16 97.335 19.44 97.605 ;
     RECT  2.16 97.875 19.44 98.145 ;
     RECT  2.16 98.415 19.44 98.685 ;
     RECT  2.16 98.955 19.44 99.225 ;
     RECT  2.16 99.495 19.44 99.765 ;
     RECT  2.16 100.035 19.44 100.305 ;
     RECT  2.16 100.575 19.44 100.845 ;
     RECT  2.16 101.115 19.44 101.385 ;
     RECT  2.16 101.655 19.44 101.925 ;
     RECT  2.16 102.195 19.44 102.465 ;
     RECT  2.16 102.735 19.44 103.005 ;
     RECT  2.16 103.275 19.44 103.545 ;
     RECT  2.16 103.815 19.44 104.085 ;
     RECT  2.16 104.355 19.44 104.625 ;
     RECT  2.16 104.895 19.44 105.165 ;
     RECT  2.16 105.435 19.44 105.705 ;
     RECT  2.16 105.975 19.44 106.245 ;
     RECT  2.16 106.515 19.44 106.785 ;
     RECT  2.16 107.055 19.44 107.325 ;
     RECT  2.16 107.595 19.44 107.865 ;
     RECT  2.16 108.135 19.44 108.405 ;
     RECT  2.16 108.675 19.44 108.945 ;
     RECT  2.16 109.215 19.44 109.485 ;
     RECT  2.16 109.755 19.44 110.025 ;
     RECT  2.16 110.295 19.44 110.565 ;
     RECT  2.16 110.835 19.44 111.105 ;
     RECT  2.16 111.375 19.44 111.645 ;
     RECT  2.16 111.915 19.44 112.185 ;
    LAYER M1 ;
     RECT  2.16 2.151 19.44 112.329 ;
    LAYER M2 ;
     RECT  0.211 8.856 0.247 8.874 ;
     RECT  0.247 8.856 0.283 9.504 ;
     RECT  0.211 57.078 0.319 57.096 ;
     RECT  0.211 10.836 0.499 10.854 ;
     RECT  0.211 59.976 0.499 59.994 ;
     RECT  0.211 97.956 0.499 97.974 ;
     RECT  0.499 6.624 0.535 6.642 ;
     RECT  0.211 7.506 0.535 7.524 ;
     RECT  0.283 8.676 0.535 9.504 ;
     RECT  0.499 10.836 0.535 11.232 ;
     RECT  0.211 12.186 0.535 12.204 ;
     RECT  0.211 15.336 0.535 16.056 ;
     RECT  0.211 17.316 0.535 17.334 ;
     RECT  0.211 18.126 0.535 18.144 ;
     RECT  0.499 21.636 0.535 21.654 ;
     RECT  0.211 24.876 0.535 24.894 ;
     RECT  0.499 32.436 0.535 32.454 ;
     RECT  0.211 33.696 0.535 34.524 ;
     RECT  0.211 38.79 0.535 38.808 ;
     RECT  0.319 56.538 0.535 57.096 ;
     RECT  0.499 59.274 0.535 59.994 ;
     RECT  0.211 65.016 0.535 65.034 ;
     RECT  0.211 66.456 0.535 66.474 ;
     RECT  0.211 75.636 0.535 75.654 ;
     RECT  0.499 78.066 0.535 78.084 ;
     RECT  0.211 83.376 0.535 83.394 ;
     RECT  0.211 90.486 0.535 90.504 ;
     RECT  0.499 97.956 0.535 98.244 ;
     RECT  0.211 99.234 0.535 99.252 ;
     RECT  0.211 100.89 0.535 100.908 ;
     RECT  0.499 103.59 0.535 103.608 ;
     RECT  0.499 109.152 0.535 109.17 ;
     RECT  0.535 4.5 2.16 4.518 ;
     RECT  0.535 6.12 2.16 12.204 ;
     RECT  0.535 12.996 2.16 13.554 ;
     RECT  0.535 14.688 2.16 16.398 ;
     RECT  0.535 17.154 2.16 17.334 ;
     RECT  0.535 18.126 2.16 18.792 ;
     RECT  0.535 21.546 2.16 21.654 ;
     RECT  0.211 23.526 2.16 23.544 ;
     RECT  0.535 24.876 2.16 26.658 ;
     RECT  2.083 27.414 2.16 27.432 ;
     RECT  0.535 28.458 2.16 28.476 ;
     RECT  0.535 32.31 2.16 32.904 ;
     RECT  0.535 33.696 2.16 34.614 ;
     RECT  0.211 35.406 2.16 35.424 ;
     RECT  0.535 38.106 2.16 38.808 ;
     RECT  0.535 39.798 2.16 39.816 ;
     RECT  0.211 41.796 2.16 41.814 ;
     RECT  0.535 43.11 2.16 43.128 ;
     RECT  0.535 44.388 2.16 44.406 ;
     RECT  0.535 47.286 2.16 48.258 ;
     RECT  0.535 49.446 2.16 49.464 ;
     RECT  0.211 51.336 2.16 51.354 ;
     RECT  0.535 53.226 2.16 53.244 ;
     RECT  0.535 54.684 2.16 54.702 ;
     RECT  0.535 56.538 2.16 58.014 ;
     RECT  0.535 58.968 2.16 59.994 ;
     RECT  0.535 60.894 2.16 60.912 ;
     RECT  0.535 62.676 2.16 62.694 ;
     RECT  0.535 64.368 2.16 65.034 ;
     RECT  0.535 66.456 2.16 68.202 ;
     RECT  0.535 68.958 2.16 69.084 ;
     RECT  0.535 71.19 2.16 71.208 ;
     RECT  0.211 72.846 2.16 72.864 ;
     RECT  0.535 75.168 2.16 76.194 ;
     RECT  0.535 77.976 2.16 79.704 ;
     RECT  0.535 83.376 2.16 84.204 ;
     RECT  0.211 85.086 2.16 85.104 ;
     RECT  0.535 86.004 2.16 86.022 ;
     RECT  0.535 88.776 2.16 90.504 ;
     RECT  0.535 93.456 2.16 93.474 ;
     RECT  0.535 95.688 2.16 96.246 ;
     RECT  0.535 97.956 2.16 99.252 ;
     RECT  0.535 100.89 2.16 101.214 ;
     RECT  0.535 102.006 2.16 102.024 ;
     RECT  0.535 103.05 2.16 103.734 ;
     RECT  0.535 104.868 2.16 104.886 ;
     RECT  0.535 105.876 2.16 107.082 ;
     RECT  0.535 109.152 2.16 109.242 ;
     RECT  0.535 109.998 2.16 110.016 ;
     RECT  2.16 2.151 19.44 112.329 ;
     RECT  19.44 110.808 19.463 110.826 ;
     RECT  19.44 4.5 19.967 5.256 ;
     RECT  19.44 6.048 19.967 7.686 ;
     RECT  19.44 8.478 19.967 10.728 ;
     RECT  19.44 11.52 19.967 109.746 ;
     RECT  19.967 6.12 20.003 7.524 ;
     RECT  19.967 8.586 20.003 8.766 ;
     RECT  19.967 9.9 20.003 10.728 ;
     RECT  19.967 12.996 20.003 14.166 ;
     RECT  19.967 15.264 20.003 17.442 ;
     RECT  19.967 18.738 20.003 19.566 ;
     RECT  19.967 20.898 20.003 22.914 ;
     RECT  19.967 24.21 20.003 25.812 ;
     RECT  19.967 30.15 20.003 31.788 ;
     RECT  19.967 33.048 20.003 39.618 ;
     RECT  19.967 40.374 20.003 43.668 ;
     RECT  19.967 44.694 20.003 51.228 ;
     RECT  19.967 52.02 20.003 54.468 ;
     RECT  19.967 57.42 20.003 57.438 ;
     RECT  19.967 59.58 20.003 60.066 ;
     RECT  19.967 60.858 20.003 67.356 ;
     RECT  19.967 68.148 20.003 75.726 ;
     RECT  19.967 76.518 20.003 80.244 ;
     RECT  19.967 81.108 20.003 81.198 ;
     RECT  19.967 81.99 20.003 83.556 ;
     RECT  19.967 86.58 20.003 86.598 ;
     RECT  19.967 87.588 20.003 98.172 ;
     RECT  19.967 99 20.003 101.718 ;
     RECT  19.967 106.218 20.003 106.236 ;
     RECT  19.967 108.108 20.003 108.126 ;
     RECT  19.967 109.188 20.003 109.746 ;
     RECT  20.003 7.506 20.039 7.524 ;
     RECT  19.967 11.52 20.039 12.078 ;
     RECT  20.003 34.974 20.039 37.962 ;
     RECT  20.003 45 20.039 51.228 ;
     RECT  20.003 52.02 20.039 53.586 ;
     RECT  20.003 54.45 20.039 54.468 ;
     RECT  20.003 60.858 20.039 61.686 ;
     RECT  20.003 63.558 20.039 66.888 ;
     RECT  20.003 70.38 20.039 70.938 ;
     RECT  20.003 76.518 20.039 77.688 ;
     RECT  20.003 88.2 20.039 88.218 ;
     RECT  20.003 91.98 20.039 94.464 ;
     RECT  20.003 96.228 20.039 96.246 ;
     RECT  20.003 24.21 20.075 24.804 ;
     RECT  19.967 55.26 20.075 55.818 ;
     RECT  20.039 63.558 20.075 64.764 ;
     RECT  20.039 77.67 20.075 77.688 ;
     RECT  20.003 78.48 20.075 80.244 ;
     RECT  20.075 78.48 20.147 78.66 ;
     RECT  20.003 8.586 20.543 8.604 ;
     RECT  20.003 10.44 20.543 10.728 ;
     RECT  20.039 12.06 20.543 12.078 ;
     RECT  20.003 12.996 20.543 13.014 ;
     RECT  20.003 13.95 20.543 13.968 ;
     RECT  20.003 15.264 20.543 15.858 ;
     RECT  20.003 16.65 20.543 17.442 ;
     RECT  20.003 19.278 20.543 19.368 ;
     RECT  20.003 20.97 20.543 21.258 ;
     RECT  20.003 22.086 20.543 22.914 ;
     RECT  20.075 24.21 20.543 24.228 ;
     RECT  20.003 25.794 20.543 25.812 ;
     RECT  19.967 26.604 20.543 27.36 ;
     RECT  19.967 28.224 20.543 28.818 ;
     RECT  20.003 30.15 20.543 31.554 ;
     RECT  20.003 33.048 20.543 34.182 ;
     RECT  20.039 34.974 20.543 36.036 ;
     RECT  20.039 36.9 20.543 37.962 ;
     RECT  20.003 39.564 20.543 39.582 ;
     RECT  20.003 40.374 20.543 40.734 ;
     RECT  20.003 41.76 20.543 42.318 ;
     RECT  20.003 43.146 20.543 43.596 ;
     RECT  20.039 45 20.543 46.368 ;
     RECT  20.039 47.16 20.543 48.726 ;
     RECT  20.039 50.4 20.543 51.228 ;
     RECT  20.039 52.02 20.543 53.352 ;
     RECT  20.075 55.8 20.543 55.818 ;
     RECT  20.075 64.206 20.543 64.764 ;
     RECT  20.039 65.718 20.543 66.888 ;
     RECT  20.003 68.256 20.543 68.814 ;
     RECT  20.003 69.606 20.543 69.624 ;
     RECT  20.039 70.65 20.543 70.938 ;
     RECT  20.003 72.306 20.543 74.214 ;
     RECT  20.003 75.006 20.543 75.024 ;
     RECT  20.039 76.518 20.543 76.536 ;
     RECT  20.147 78.48 20.543 78.498 ;
     RECT  20.075 79.596 20.543 80.244 ;
     RECT  20.003 81.99 20.543 82.008 ;
     RECT  20.003 82.8 20.543 83.394 ;
     RECT  20.003 89.478 20.543 91.224 ;
     RECT  20.039 91.98 20.543 92.196 ;
     RECT  20.039 93.06 20.543 94.05 ;
     RECT  20.003 95.454 20.543 95.472 ;
     RECT  20.003 97.11 20.543 98.172 ;
     RECT  20.003 99 20.543 100.674 ;
     RECT  19.967 103.59 20.543 104.184 ;
     RECT  20.543 17.424 20.579 17.442 ;
     RECT  20.543 19.278 20.579 19.296 ;
     RECT  20.543 21.204 20.579 21.222 ;
     RECT  20.543 31.23 20.579 31.518 ;
     RECT  20.543 43.146 20.579 43.164 ;
     RECT  20.543 45.81 20.579 45.828 ;
     RECT  20.543 65.718 20.579 66.384 ;
     RECT  20.543 73.008 20.579 73.026 ;
     RECT  20.543 79.596 20.579 79.614 ;
     RECT  20.543 97.11 20.579 97.128 ;
     RECT  20.543 30.186 20.615 30.204 ;
     RECT  20.579 31.5 20.615 31.518 ;
     RECT  20.579 66.366 20.615 66.384 ;
     RECT  20.543 83.376 20.615 83.394 ;
     RECT  21.379 17.082 21.479 17.1 ;
    LAYER M3 ;
     RECT  10.872 0.187 10.89 2.143 ;
     RECT  2.415 2.143 2.505 2.413 ;
     RECT  5.115 2.143 5.205 2.413 ;
     RECT  7.815 2.143 7.905 2.413 ;
     RECT  13.215 2.143 13.305 2.413 ;
     RECT  15.915 2.143 16.005 2.413 ;
     RECT  18.615 2.143 18.705 2.413 ;
     RECT  18.615 2.413 18.897 3.145 ;
     RECT  18.615 3.145 19.098 3.181 ;
     RECT  18.615 3.181 19.206 3.379 ;
     RECT  18.615 3.379 19.314 3.847 ;
     RECT  15.915 2.413 16.197 4.117 ;
     RECT  17.1 3.991 17.118 4.117 ;
     RECT  18.36 3.847 19.314 4.117 ;
     RECT  15.915 4.117 19.314 4.189 ;
     RECT  2.415 2.413 2.697 4.315 ;
     RECT  5.115 2.413 5.397 4.351 ;
     RECT  14.4 4.351 14.418 4.387 ;
     RECT  5.004 4.351 5.397 4.397 ;
     RECT  10.515 2.143 10.89 4.459 ;
     RECT  6.84 4.363 6.858 4.493 ;
     RECT  15.3 4.189 19.314 4.495 ;
     RECT  7.815 2.413 8.097 4.507 ;
     RECT  14.292 4.387 14.418 4.523 ;
     RECT  10.515 4.459 11.286 4.649 ;
     RECT  9.756 4.459 9.774 4.651 ;
     RECT  10.515 4.649 11.178 4.651 ;
     RECT  13.215 2.413 13.497 4.657 ;
     RECT  12.924 4.657 13.497 4.693 ;
     RECT  14.292 4.523 14.382 4.693 ;
     RECT  7.812 4.507 8.097 4.729 ;
     RECT  12.096 4.531 12.114 4.729 ;
     RECT  2.304 4.315 2.697 4.801 ;
     RECT  12.06 4.729 12.114 4.801 ;
     RECT  12.924 4.693 14.382 4.801 ;
     RECT  9.756 4.651 11.178 4.829 ;
     RECT  2.304 4.801 3.474 4.919 ;
     RECT  7.812 4.729 8.73 4.919 ;
     RECT  9.756 4.829 11.034 4.919 ;
     RECT  2.415 4.919 3.474 4.927 ;
     RECT  12.06 4.801 14.382 4.963 ;
     RECT  0.54 4.495 0.558 5.021 ;
     RECT  5.115 4.397 5.397 5.161 ;
     RECT  2.415 4.927 3.654 5.189 ;
     RECT  5.115 5.161 5.706 5.213 ;
     RECT  5.115 5.213 5.397 5.227 ;
     RECT  15.3 4.495 19.962 5.261 ;
     RECT  7.812 4.919 8.097 5.269 ;
     RECT  11.988 4.963 14.382 5.305 ;
     RECT  15.3 5.261 19.242 5.305 ;
     RECT  1.152 5.227 1.17 5.357 ;
     RECT  7.74 5.269 8.097 5.459 ;
     RECT  7.815 5.459 8.097 5.701 ;
     RECT  10.515 4.919 11.034 5.701 ;
     RECT  2.415 5.189 2.862 5.729 ;
     RECT  3.744 5.701 3.762 5.801 ;
     RECT  11.988 5.305 19.242 5.809 ;
     RECT  7.815 5.701 8.262 5.851 ;
     RECT  9.144 5.341 9.666 5.851 ;
     RECT  5.076 5.227 5.397 5.881 ;
     RECT  6.84 5.323 6.858 5.881 ;
     RECT  7.815 5.851 9.666 5.881 ;
     RECT  10.515 5.701 11.106 5.971 ;
     RECT  11.952 5.809 19.242 5.971 ;
     RECT  10.515 5.971 19.242 6.037 ;
     RECT  19.98 5.707 19.998 6.037 ;
     RECT  7.815 5.881 9.702 6.115 ;
     RECT  10.515 6.037 19.998 6.115 ;
     RECT  6.84 5.881 6.93 6.143 ;
     RECT  6.912 6.143 6.93 6.179 ;
     RECT  2.415 5.729 2.697 6.187 ;
     RECT  2.304 6.187 2.697 6.269 ;
     RECT  5.04 5.881 5.397 6.385 ;
     RECT  7.815 6.115 19.998 6.511 ;
     RECT  0.54 6.115 0.558 6.523 ;
     RECT  7.164 6.511 19.998 6.539 ;
     RECT  0.54 6.523 1.17 6.619 ;
     RECT  0.504 6.619 1.17 6.653 ;
     RECT  7.164 6.539 8.097 6.653 ;
     RECT  4.68 6.385 5.397 6.691 ;
     RECT  0.504 6.653 0.558 6.715 ;
     RECT  4.572 6.691 5.397 6.809 ;
     RECT  10.116 6.539 19.998 6.809 ;
     RECT  3.564 6.781 3.582 6.817 ;
     RECT  9.072 6.539 9.27 6.845 ;
     RECT  10.116 6.809 19.098 6.845 ;
     RECT  3.564 6.817 4.122 6.881 ;
     RECT  9.072 6.845 9.09 6.881 ;
     RECT  0.288 6.715 0.558 6.893 ;
     RECT  3.6 6.881 4.122 6.989 ;
     RECT  7.308 6.653 8.097 6.989 ;
     RECT  0.288 6.893 0.522 7.085 ;
     RECT  3.6 6.989 3.906 7.349 ;
     RECT  11.7 6.845 19.062 7.349 ;
     RECT  11.772 7.349 19.062 7.373 ;
     RECT  19.944 6.809 19.998 7.387 ;
     RECT  0.216 7.387 0.234 7.529 ;
     RECT  19.944 7.387 20.034 7.529 ;
     RECT  2.415 6.269 2.697 7.531 ;
     RECT  2.304 7.531 2.697 7.619 ;
     RECT  11.772 7.373 13.698 7.619 ;
     RECT  3.672 7.349 3.906 7.691 ;
     RECT  11.88 7.619 13.698 7.691 ;
     RECT  12.06 7.691 13.698 7.757 ;
     RECT  6.84 7.675 6.858 7.771 ;
     RECT  7.815 6.989 8.097 7.771 ;
     RECT  14.544 7.373 19.062 7.771 ;
     RECT  19.944 7.529 19.962 7.771 ;
     RECT  7.815 7.771 8.334 7.861 ;
     RECT  6.84 7.771 6.894 7.889 ;
     RECT  7.815 7.861 8.91 7.889 ;
     RECT  1.152 7.675 1.17 7.901 ;
     RECT  7.815 7.889 8.097 7.933 ;
     RECT  10.116 6.845 10.89 7.933 ;
     RECT  6.876 7.889 6.894 7.961 ;
     RECT  8.82 7.889 8.91 8.033 ;
     RECT  9.9 7.933 10.89 8.041 ;
     RECT  8.82 8.033 8.838 8.069 ;
     RECT  0.54 7.933 0.558 8.093 ;
     RECT  9.792 8.041 10.89 8.159 ;
     RECT  2.415 7.619 2.697 8.239 ;
     RECT  14.544 7.771 19.962 8.251 ;
     RECT  2.415 8.239 2.898 8.311 ;
     RECT  12.816 7.757 13.698 8.311 ;
     RECT  14.544 8.251 20.538 8.311 ;
     RECT  2.415 8.311 3.546 8.429 ;
     RECT  12.06 7.757 12.078 8.581 ;
     RECT  12.816 8.311 20.538 8.581 ;
     RECT  12.06 8.581 20.538 8.609 ;
     RECT  0.216 8.395 0.306 8.699 ;
     RECT  7.776 7.933 8.097 8.779 ;
     RECT  12.06 8.609 19.998 8.843 ;
     RECT  7.416 8.779 8.097 8.851 ;
     RECT  10.188 8.159 10.89 8.851 ;
     RECT  12.06 8.843 19.134 8.851 ;
     RECT  10.188 8.851 19.134 8.969 ;
     RECT  6.84 8.851 8.097 9.041 ;
     RECT  10.188 8.969 19.098 9.041 ;
     RECT  3.42 8.429 3.438 9.239 ;
     RECT  11.88 9.041 19.098 9.239 ;
     RECT  8.964 9.211 8.982 9.319 ;
     RECT  8.82 9.319 8.982 9.355 ;
     RECT  10.188 9.041 10.89 9.355 ;
     RECT  8.82 9.355 10.89 9.419 ;
     RECT  9.18 9.419 10.89 9.509 ;
     RECT  2.415 8.429 2.697 9.595 ;
     RECT  0.216 8.699 0.27 9.773 ;
     RECT  3.852 9.751 3.87 9.851 ;
     RECT  2.415 9.595 2.79 10.021 ;
     RECT  7.056 9.041 8.097 10.021 ;
     RECT  12.06 9.239 19.098 10.049 ;
     RECT  9.18 9.509 9.774 10.109 ;
     RECT  9.756 10.109 9.774 10.121 ;
     RECT  19.944 8.843 19.998 10.121 ;
     RECT  6.84 10.021 8.097 10.129 ;
     RECT  2.415 10.021 3.078 10.165 ;
     RECT  6.552 10.129 8.097 10.193 ;
     RECT  6.552 10.193 6.57 10.229 ;
     RECT  0.54 10.129 0.558 10.301 ;
     RECT  2.415 10.165 3.402 10.319 ;
     RECT  14.508 10.049 19.098 10.471 ;
     RECT  5.115 6.809 5.397 10.561 ;
     RECT  12.06 10.049 13.698 10.633 ;
     RECT  5.115 10.561 5.454 10.669 ;
     RECT  11.988 10.633 13.698 10.685 ;
     RECT  5.04 10.669 5.454 10.733 ;
     RECT  0.216 10.795 0.234 10.859 ;
     RECT  2.415 10.319 2.697 10.939 ;
     RECT  20.52 10.267 20.538 10.973 ;
     RECT  3.528 10.831 3.618 10.975 ;
     RECT  2.304 10.939 2.697 11.003 ;
     RECT  5.04 10.733 5.397 11.011 ;
     RECT  12.06 10.685 13.698 11.011 ;
     RECT  14.508 10.471 19.242 11.011 ;
     RECT  3.528 10.975 3.834 11.129 ;
     RECT  5.004 11.011 5.397 11.129 ;
     RECT  1.224 11.128 1.242 11.131 ;
     RECT  1.224 11.131 1.422 11.209 ;
     RECT  2.415 11.003 2.697 11.209 ;
     RECT  7.308 10.193 8.097 11.209 ;
     RECT  12.06 11.011 19.242 11.275 ;
     RECT  6.84 11.209 8.097 11.281 ;
     RECT  9.612 11.209 9.63 11.281 ;
     RECT  10.515 9.509 10.89 11.281 ;
     RECT  0.504 11.209 1.422 11.309 ;
     RECT  5.076 11.129 5.397 11.309 ;
     RECT  6.84 11.281 8.586 11.309 ;
     RECT  2.415 11.209 3.258 11.399 ;
     RECT  4.068 11.281 4.158 11.399 ;
     RECT  7.704 11.309 8.586 11.399 ;
     RECT  9.612 11.281 10.89 11.399 ;
     RECT  12.06 11.275 20.034 11.515 ;
     RECT  7.815 11.399 8.586 11.785 ;
     RECT  6.84 11.309 6.858 11.837 ;
     RECT  0.504 11.309 1.206 11.939 ;
     RECT  4.068 11.399 4.086 11.939 ;
     RECT  9.972 11.399 10.89 11.939 ;
     RECT  0.504 11.939 0.558 11.947 ;
     RECT  7.815 11.785 8.694 11.947 ;
     RECT  11.7 11.515 20.034 11.975 ;
     RECT  10.116 11.939 10.89 12.019 ;
     RECT  12.06 11.975 20.034 12.055 ;
     RECT  10.116 12.019 10.926 12.083 ;
     RECT  10.296 12.083 10.926 12.091 ;
     RECT  0.216 11.947 0.558 12.173 ;
     RECT  0.216 12.173 0.234 12.209 ;
     RECT  7.815 11.947 9.162 12.209 ;
     RECT  10.296 12.091 10.962 12.209 ;
     RECT  10.515 12.209 10.962 12.253 ;
     RECT  2.415 11.399 2.697 12.283 ;
     RECT  7.815 12.209 8.766 12.289 ;
     RECT  2.304 12.283 2.697 12.361 ;
     RECT  5.115 11.309 5.397 12.361 ;
     RECT  2.304 12.361 3.078 12.451 ;
     RECT  7.308 12.289 8.766 12.479 ;
     RECT  2.304 12.451 3.294 12.551 ;
     RECT  2.304 12.551 3.006 12.659 ;
     RECT  7.308 12.479 8.658 12.749 ;
     RECT  6.192 12.631 6.21 12.785 ;
     RECT  7.308 12.749 8.118 12.811 ;
     RECT  4.572 12.361 5.397 12.865 ;
     RECT  6.372 12.865 6.39 13.019 ;
     RECT  7.272 12.811 8.118 13.261 ;
     RECT  10.515 12.253 11.07 13.261 ;
     RECT  3.996 12.865 5.397 13.289 ;
     RECT  10.26 13.261 11.07 13.405 ;
     RECT  6.552 13.261 8.118 13.469 ;
     RECT  2.304 12.659 2.697 13.531 ;
     RECT  10.116 13.405 11.07 13.531 ;
     RECT  10.116 13.531 11.286 13.559 ;
     RECT  10.515 13.559 11.286 13.631 ;
     RECT  2.304 13.531 3.186 13.667 ;
     RECT  0.54 12.991 0.558 13.709 ;
     RECT  12.06 12.055 20.538 13.739 ;
     RECT  7.38 13.469 8.118 13.801 ;
     RECT  2.304 13.667 3.114 13.829 ;
     RECT  3.924 13.711 3.942 13.829 ;
     RECT  19.944 13.739 20.538 13.973 ;
     RECT  5.004 13.289 5.397 13.997 ;
     RECT  2.304 13.829 2.697 14.045 ;
     RECT  7.38 13.801 8.622 14.099 ;
     RECT  12.06 13.739 19.098 14.099 ;
     RECT  19.944 13.973 19.998 14.171 ;
     RECT  4.068 14.179 4.086 14.215 ;
     RECT  6.336 13.945 6.354 14.449 ;
     RECT  6.228 14.449 6.354 14.521 ;
     RECT  14.544 14.099 19.098 14.521 ;
     RECT  19.944 14.171 19.962 14.521 ;
     RECT  4.068 14.215 4.338 14.549 ;
     RECT  6.12 14.521 6.354 14.683 ;
     RECT  7.38 14.099 8.097 14.683 ;
     RECT  12.06 14.099 13.734 14.711 ;
     RECT  10.515 13.631 11.07 14.719 ;
     RECT  2.415 14.045 2.697 14.881 ;
     RECT  5.115 13.997 5.397 14.881 ;
     RECT  6.12 14.683 8.097 14.909 ;
     RECT  9.9 14.719 11.07 14.909 ;
     RECT  12.096 14.711 13.734 14.917 ;
     RECT  14.544 14.521 19.962 14.917 ;
     RECT  4.5 14.881 5.397 14.981 ;
     RECT  12.096 14.917 19.962 15.019 ;
     RECT  2.415 14.881 3.474 15.151 ;
     RECT  7.815 14.909 8.097 15.259 ;
     RECT  8.82 15.025 8.838 15.259 ;
     RECT  6.12 14.909 6.93 15.287 ;
     RECT  0.54 14.683 0.558 15.331 ;
     RECT  5.076 14.981 5.397 15.331 ;
     RECT  6.12 15.287 6.39 15.331 ;
     RECT  7.815 15.259 8.838 15.359 ;
     RECT  2.304 15.151 3.474 15.449 ;
     RECT  7.815 15.359 8.586 15.449 ;
     RECT  0.216 15.331 0.558 15.533 ;
     RECT  5.076 15.331 6.39 15.719 ;
     RECT  7.815 15.449 8.154 15.799 ;
     RECT  9.468 15.565 9.486 15.827 ;
     RECT  3.816 15.691 4.158 15.871 ;
     RECT  5.076 15.719 5.397 15.871 ;
     RECT  2.304 15.449 2.934 15.899 ;
     RECT  6.192 15.719 6.39 15.899 ;
     RECT  7.2 15.799 8.154 16.061 ;
     RECT  10.515 14.909 11.07 16.069 ;
     RECT  0.216 15.533 0.234 16.253 ;
     RECT  7.776 16.061 8.097 16.259 ;
     RECT  9.576 16.033 9.666 16.259 ;
     RECT  2.415 15.899 2.934 16.339 ;
     RECT  3.816 15.871 5.397 16.339 ;
     RECT  12.096 15.019 20.538 16.501 ;
     RECT  6.84 16.375 6.858 16.529 ;
     RECT  2.415 16.339 5.397 16.601 ;
     RECT  4.176 16.601 5.397 16.645 ;
     RECT  12.024 16.501 20.538 16.645 ;
     RECT  4.176 16.645 5.886 16.681 ;
     RECT  2.415 16.601 3.258 16.699 ;
     RECT  2.304 16.699 3.258 16.709 ;
     RECT  4.176 16.681 6.462 16.799 ;
     RECT  11.844 16.645 20.538 16.799 ;
     RECT  10.476 16.069 11.07 16.879 ;
     RECT  9.9 16.879 11.07 16.915 ;
     RECT  9.9 16.915 11.178 16.979 ;
     RECT  6.336 16.799 6.462 17.069 ;
     RECT  10.44 16.979 11.178 17.069 ;
     RECT  21.384 17.035 21.402 17.077 ;
     RECT  21.384 17.077 21.474 17.105 ;
     RECT  21.456 17.105 21.474 17.117 ;
     RECT  0.54 16.375 0.558 17.227 ;
     RECT  7.815 16.259 8.097 17.311 ;
     RECT  7.38 17.311 8.91 17.405 ;
     RECT  4.176 16.799 5.397 17.411 ;
     RECT  12.024 16.799 20.538 17.419 ;
     RECT  7.815 17.405 8.91 17.483 ;
     RECT  7.815 17.483 8.262 17.501 ;
     RECT  12.024 17.419 20.574 17.519 ;
     RECT  10.44 17.069 11.07 17.609 ;
     RECT  7.815 17.501 8.226 17.681 ;
     RECT  12.096 17.519 20.574 17.741 ;
     RECT  5.115 17.411 5.397 17.761 ;
     RECT  2.304 16.709 2.697 17.851 ;
     RECT  2.304 17.851 2.898 17.879 ;
     RECT  4.14 17.725 4.158 17.879 ;
     RECT  0.216 17.227 0.558 17.933 ;
     RECT  2.415 17.879 2.898 17.951 ;
     RECT  0.216 17.933 0.234 18.149 ;
     RECT  12.096 17.741 19.998 18.149 ;
     RECT  6.84 17.419 6.894 18.193 ;
     RECT  7.815 17.681 8.097 18.193 ;
     RECT  6.84 18.193 8.097 18.499 ;
     RECT  6.66 18.499 8.097 18.563 ;
     RECT  6.66 18.563 6.858 18.599 ;
     RECT  12.096 18.149 19.098 18.697 ;
     RECT  5.115 17.761 5.49 18.733 ;
     RECT  3.996 18.391 4.014 18.763 ;
     RECT  5.115 18.733 5.598 18.763 ;
     RECT  6.768 18.599 6.858 18.797 ;
     RECT  2.415 17.951 2.697 18.931 ;
     RECT  3.996 18.763 5.598 18.931 ;
     RECT  0.54 18.769 0.558 18.941 ;
     RECT  12.06 18.697 19.098 19.003 ;
     RECT  19.944 18.149 19.998 19.003 ;
     RECT  3.636 18.931 5.598 19.031 ;
     RECT  6.768 18.797 6.786 19.031 ;
     RECT  3.708 19.031 5.598 19.067 ;
     RECT  12.06 19.003 19.998 19.099 ;
     RECT  7.815 18.563 8.097 19.111 ;
     RECT  3.708 19.067 5.397 19.139 ;
     RECT  3.708 19.139 4.158 19.229 ;
     RECT  12.06 19.099 20.538 19.273 ;
     RECT  10.515 17.609 11.07 19.381 ;
     RECT  7.815 19.111 8.478 19.471 ;
     RECT  10.476 19.381 11.07 19.499 ;
     RECT  0.396 19.435 0.414 19.579 ;
     RECT  2.376 18.931 2.697 19.579 ;
     RECT  7.815 19.471 8.73 19.579 ;
     RECT  0.216 19.579 0.414 19.613 ;
     RECT  12.06 19.273 20.574 19.613 ;
     RECT  7.524 19.579 8.73 19.679 ;
     RECT  0.216 19.613 0.27 19.709 ;
     RECT  2.376 19.579 2.718 19.819 ;
     RECT  7.524 19.679 8.097 19.819 ;
     RECT  9.036 19.777 9.054 19.849 ;
     RECT  0.252 19.709 0.27 19.949 ;
     RECT  2.376 19.819 2.862 19.949 ;
     RECT  9.036 19.849 9.126 19.949 ;
     RECT  3.708 19.229 3.762 20.107 ;
     RECT  3.708 20.107 4.014 20.147 ;
     RECT  10.515 19.499 11.07 20.281 ;
     RECT  12.06 19.613 19.998 20.309 ;
     RECT  9.756 20.281 11.07 20.381 ;
     RECT  2.376 19.949 2.697 20.443 ;
     RECT  15.336 20.309 19.998 20.443 ;
     RECT  5.004 19.139 5.397 20.551 ;
     RECT  2.304 20.443 2.697 20.579 ;
     RECT  4.464 20.551 5.634 20.587 ;
     RECT  6.84 19.819 8.097 20.587 ;
     RECT  4.464 20.587 8.097 20.621 ;
     RECT  4.464 20.621 6.21 20.723 ;
     RECT  3.708 20.147 3.726 20.759 ;
     RECT  4.824 20.723 6.21 20.759 ;
     RECT  2.415 20.579 2.697 20.821 ;
     RECT  6.192 20.759 6.21 20.849 ;
     RECT  7.524 20.621 8.097 20.957 ;
     RECT  7.596 20.957 8.097 20.965 ;
     RECT  8.928 20.821 8.946 20.965 ;
     RECT  15.336 20.443 20.538 20.971 ;
     RECT  7.596 20.965 8.946 21.001 ;
     RECT  15.336 20.971 20.574 21.029 ;
     RECT  2.415 20.821 2.79 21.091 ;
     RECT  7.596 21.001 9.522 21.119 ;
     RECT  7.596 21.119 8.37 21.149 ;
     RECT  19.944 21.029 20.574 21.227 ;
     RECT  12.06 20.309 14.598 21.271 ;
     RECT  15.336 21.029 19.098 21.271 ;
     RECT  3.636 21.199 3.654 21.299 ;
     RECT  4.824 20.759 5.397 21.461 ;
     RECT  9.144 21.119 9.522 21.469 ;
     RECT  10.515 20.381 11.07 21.469 ;
     RECT  12.06 21.271 19.098 21.469 ;
     RECT  0.54 21.541 0.558 21.631 ;
     RECT  2.415 21.091 2.826 21.631 ;
     RECT  9.144 21.469 19.098 21.659 ;
     RECT  0.504 21.631 0.558 21.677 ;
     RECT  0.504 21.677 0.522 21.821 ;
     RECT  12.06 21.659 19.098 21.901 ;
     RECT  19.944 21.227 20.538 21.901 ;
     RECT  4.176 21.775 4.194 21.929 ;
     RECT  7.74 21.149 8.37 21.929 ;
     RECT  9.144 21.659 11.07 21.979 ;
     RECT  2.415 21.631 2.862 22.045 ;
     RECT  6.84 21.451 6.858 22.081 ;
     RECT  5.004 21.461 5.397 22.109 ;
     RECT  2.415 22.045 3.294 22.123 ;
     RECT  2.304 22.123 3.294 22.171 ;
     RECT  8.892 21.979 11.07 22.199 ;
     RECT  9.612 22.199 11.07 22.271 ;
     RECT  2.304 22.171 3.366 22.279 ;
     RECT  9.648 22.271 11.07 22.469 ;
     RECT  12.06 21.901 20.538 22.505 ;
     RECT  6.804 22.081 6.858 22.549 ;
     RECT  6.336 22.549 6.858 22.621 ;
     RECT  2.304 22.279 4.014 22.685 ;
     RECT  2.415 22.685 4.014 22.711 ;
     RECT  6.228 22.621 6.858 22.711 ;
     RECT  7.815 21.929 8.097 22.711 ;
     RECT  2.415 22.711 4.158 22.739 ;
     RECT  6.228 22.711 8.097 22.739 ;
     RECT  6.588 22.739 8.097 22.747 ;
     RECT  10.08 22.469 11.07 22.811 ;
     RECT  4.068 22.739 4.158 22.829 ;
     RECT  12.06 22.505 19.026 22.832 ;
     RECT  4.068 22.829 4.086 22.919 ;
     RECT  6.588 22.747 8.226 23.009 ;
     RECT  2.415 22.739 3.222 23.081 ;
     RECT  6.912 23.009 8.097 23.189 ;
     RECT  11.988 22.832 19.026 23.323 ;
     RECT  11.988 23.323 19.098 23.431 ;
     RECT  19.944 22.505 20.538 23.431 ;
     RECT  0.216 23.512 0.234 23.549 ;
     RECT  10.515 22.811 11.07 23.656 ;
     RECT  11.988 23.431 20.538 23.656 ;
     RECT  10.515 23.656 20.538 23.693 ;
     RECT  7.236 23.189 8.097 23.891 ;
     RECT  2.415 23.081 2.826 23.899 ;
     RECT  5.115 22.109 5.397 23.935 ;
     RECT  9.684 23.701 9.702 23.971 ;
     RECT  10.515 23.693 19.026 23.971 ;
     RECT  4.824 23.935 5.397 24.061 ;
     RECT  2.415 23.899 2.862 24.089 ;
     RECT  4.824 24.061 5.454 24.089 ;
     RECT  0.288 23.995 0.306 24.125 ;
     RECT  5.004 24.089 5.454 24.169 ;
     RECT  9.684 23.971 19.026 24.187 ;
     RECT  19.944 23.693 20.538 24.233 ;
     RECT  2.415 24.089 2.697 24.331 ;
     RECT  5.004 24.169 6.138 24.331 ;
     RECT  6.876 24.133 6.894 24.331 ;
     RECT  5.004 24.331 6.894 24.359 ;
     RECT  9.144 24.187 19.026 24.359 ;
     RECT  5.004 24.359 5.49 24.368 ;
     RECT  6.84 24.359 6.894 24.431 ;
     RECT  6.84 24.431 6.858 24.461 ;
     RECT  9.54 24.359 19.026 24.475 ;
     RECT  19.944 24.233 20.07 24.475 ;
     RECT  9.54 24.475 20.07 24.629 ;
     RECT  3.96 24.601 3.978 24.701 ;
     RECT  0.216 24.859 0.234 24.899 ;
     RECT  10.515 24.629 20.07 24.899 ;
     RECT  7.815 23.891 8.097 25.015 ;
     RECT  9.54 24.629 9.774 25.079 ;
     RECT  7.815 25.015 8.154 25.169 ;
     RECT  2.304 24.331 2.697 25.177 ;
     RECT  11.844 24.899 20.07 25.195 ;
     RECT  2.304 25.177 2.862 25.249 ;
     RECT  5.115 24.368 5.49 25.249 ;
     RECT  5.115 25.249 6.174 25.285 ;
     RECT  2.304 25.249 3.33 25.349 ;
     RECT  11.844 25.195 20.538 25.439 ;
     RECT  5.115 25.285 6.93 25.475 ;
     RECT  9.756 25.079 9.774 25.475 ;
     RECT  5.115 25.475 6.858 25.511 ;
     RECT  5.115 25.511 6.822 25.531 ;
     RECT  4.464 25.531 6.822 25.781 ;
     RECT  10.515 24.899 11.106 25.951 ;
     RECT  2.304 25.349 3.042 25.979 ;
     RECT  12.096 25.439 20.538 25.979 ;
     RECT  10.296 25.951 11.106 26.051 ;
     RECT  2.304 25.979 2.934 26.087 ;
     RECT  6.624 25.781 6.822 26.087 ;
     RECT  6.696 26.087 6.822 26.159 ;
     RECT  5.004 25.781 5.706 26.189 ;
     RECT  7.815 25.169 8.097 26.401 ;
     RECT  6.84 26.299 6.858 26.429 ;
     RECT  0.54 25.555 0.558 26.635 ;
     RECT  10.515 26.051 11.106 26.635 ;
     RECT  4.068 26.527 4.086 26.671 ;
     RECT  5.004 26.189 5.397 26.671 ;
     RECT  4.068 26.671 5.397 26.761 ;
     RECT  7.596 26.401 8.097 26.761 ;
     RECT  0.216 26.635 0.558 26.765 ;
     RECT  3.996 26.761 5.397 26.789 ;
     RECT  9.18 26.635 9.198 26.789 ;
     RECT  10.515 26.635 11.214 26.789 ;
     RECT  10.515 26.789 11.106 26.833 ;
     RECT  9.792 26.833 11.106 26.969 ;
     RECT  0.54 26.765 0.558 27.101 ;
     RECT  12.096 25.979 19.026 27.139 ;
     RECT  19.944 25.979 20.538 27.139 ;
     RECT  2.304 26.087 2.697 27.211 ;
     RECT  5.115 26.789 5.397 27.409 ;
     RECT  7.092 26.761 8.097 27.409 ;
     RECT  2.088 27.211 2.697 27.437 ;
     RECT  6.804 27.409 8.097 27.445 ;
     RECT  3.996 26.789 4.266 27.473 ;
     RECT  3.996 27.473 4.122 27.571 ;
     RECT  5.115 27.409 5.706 27.571 ;
     RECT  6.804 27.445 8.406 27.571 ;
     RECT  3.42 27.571 4.122 27.671 ;
     RECT  5.115 27.571 5.778 27.677 ;
     RECT  12.096 27.139 20.538 27.715 ;
     RECT  6.804 27.571 9.126 27.779 ;
     RECT  2.304 27.437 2.697 27.841 ;
     RECT  10.476 26.969 11.106 27.869 ;
     RECT  2.304 27.841 2.826 27.917 ;
     RECT  12.06 27.715 20.538 28.139 ;
     RECT  12.06 28.139 18.897 28.171 ;
     RECT  11.916 28.171 18.897 28.247 ;
     RECT  11.988 28.247 18.897 28.283 ;
     RECT  6.804 27.779 8.55 28.381 ;
     RECT  3.744 27.671 4.122 28.409 ;
     RECT  6.732 28.381 8.55 28.409 ;
     RECT  12.06 28.283 18.897 28.409 ;
     RECT  6.732 28.409 8.154 28.445 ;
     RECT  6.732 28.445 6.966 28.453 ;
     RECT  6.66 28.453 6.966 28.589 ;
     RECT  4.176 28.555 4.338 28.679 ;
     RECT  0.54 28.453 0.558 28.781 ;
     RECT  14.508 28.409 18.897 28.939 ;
     RECT  19.944 28.139 20.538 28.939 ;
     RECT  6.768 28.589 6.966 28.973 ;
     RECT  14.508 28.939 20.538 29.021 ;
     RECT  5.115 27.677 5.397 29.083 ;
     RECT  9.612 28.381 9.63 29.101 ;
     RECT  10.515 27.869 11.106 29.101 ;
     RECT  2.304 27.917 2.697 29.129 ;
     RECT  2.412 29.129 2.697 29.191 ;
     RECT  7.815 28.445 8.154 29.191 ;
     RECT  9.612 29.101 11.106 29.191 ;
     RECT  14.508 29.021 19.026 29.219 ;
     RECT  9.396 29.191 11.106 29.261 ;
     RECT  12.06 28.409 13.698 29.371 ;
     RECT  14.508 29.219 18.954 29.371 ;
     RECT  4.176 28.679 4.194 29.489 ;
     RECT  4.932 29.083 5.397 29.489 ;
     RECT  9.54 29.261 11.106 29.489 ;
     RECT  2.412 29.191 2.826 29.605 ;
     RECT  2.412 29.605 3.366 29.611 ;
     RECT  6.768 28.973 6.858 29.641 ;
     RECT  7.815 29.191 8.226 29.731 ;
     RECT  2.412 29.611 4.05 29.759 ;
     RECT  5.076 29.489 5.397 29.767 ;
     RECT  6.192 29.641 6.858 29.767 ;
     RECT  7.815 29.731 8.586 29.903 ;
     RECT  5.076 29.767 6.858 29.939 ;
     RECT  7.815 29.903 8.298 29.939 ;
     RECT  2.412 29.759 2.934 29.947 ;
     RECT  19.944 29.021 20.538 29.947 ;
     RECT  12.06 29.371 18.954 30.001 ;
     RECT  6.552 29.939 6.858 30.029 ;
     RECT  12.06 30.001 19.026 30.109 ;
     RECT  19.944 29.947 20.61 30.209 ;
     RECT  5.076 29.939 5.454 30.271 ;
     RECT  10.116 29.489 11.106 30.271 ;
     RECT  2.304 29.947 2.934 30.317 ;
     RECT  12.06 30.109 19.098 30.371 ;
     RECT  3.744 29.759 4.05 30.451 ;
     RECT  5.004 30.271 5.454 30.451 ;
     RECT  9.972 30.271 11.106 30.461 ;
     RECT  6.552 30.029 6.57 30.569 ;
     RECT  10.116 30.461 11.106 30.569 ;
     RECT  3.744 30.451 5.454 30.605 ;
     RECT  2.415 30.317 2.934 30.613 ;
     RECT  3.744 30.605 4.014 30.613 ;
     RECT  5.115 30.605 5.454 30.641 ;
     RECT  2.415 30.613 4.014 30.677 ;
     RECT  7.815 29.939 8.097 30.811 ;
     RECT  2.415 30.677 3.438 30.839 ;
     RECT  21.384 30.763 21.402 30.893 ;
     RECT  7.815 30.811 8.694 30.919 ;
     RECT  0.252 30.763 0.27 30.941 ;
     RECT  10.368 30.569 11.106 30.991 ;
     RECT  7.815 30.919 9.09 31.019 ;
     RECT  10.368 30.991 11.178 31.181 ;
     RECT  19.944 30.209 20.538 31.225 ;
     RECT  2.415 30.839 3.222 31.291 ;
     RECT  2.304 31.291 3.222 31.379 ;
     RECT  12.132 30.371 19.098 31.379 ;
     RECT  12.132 31.379 19.026 31.451 ;
     RECT  9 31.019 9.09 31.459 ;
     RECT  5.115 30.641 5.397 31.495 ;
     RECT  19.944 31.225 20.574 31.495 ;
     RECT  4.716 31.495 5.397 31.531 ;
     RECT  2.415 31.379 3.222 31.649 ;
     RECT  6.84 30.811 6.858 31.657 ;
     RECT  6.84 31.657 6.894 31.729 ;
     RECT  12.132 31.451 18.954 31.729 ;
     RECT  7.815 31.019 8.097 31.765 ;
     RECT  9 31.459 9.126 31.765 ;
     RECT  6.336 31.729 6.894 31.829 ;
     RECT  7.815 31.765 9.198 31.891 ;
     RECT  3.996 31.531 5.397 31.919 ;
     RECT  6.804 31.829 6.894 31.919 ;
     RECT  7.668 31.891 9.198 31.919 ;
     RECT  0.252 31.819 0.27 31.949 ;
     RECT  4.248 31.919 5.397 31.997 ;
     RECT  19.944 31.495 20.61 31.997 ;
     RECT  7.668 31.919 9.09 32.063 ;
     RECT  2.415 31.649 3.078 32.099 ;
     RECT  6.84 31.919 6.894 32.341 ;
     RECT  7.668 32.063 8.406 32.341 ;
     RECT  12.096 31.729 18.954 32.341 ;
     RECT  12.096 32.341 19.098 32.495 ;
     RECT  6.84 32.341 8.406 32.531 ;
     RECT  0.504 32.305 0.558 32.669 ;
     RECT  3.42 32.467 3.438 32.737 ;
     RECT  6.84 32.531 8.097 32.737 ;
     RECT  6.768 32.737 8.097 32.801 ;
     RECT  4.572 31.997 5.397 32.809 ;
     RECT  2.415 32.099 2.697 32.827 ;
     RECT  3.42 32.737 3.582 32.827 ;
     RECT  6.768 32.801 6.966 32.837 ;
     RECT  9.36 32.773 9.378 32.845 ;
     RECT  6.84 32.837 6.966 32.873 ;
     RECT  2.415 32.827 3.582 32.881 ;
     RECT  4.392 32.809 5.397 32.881 ;
     RECT  2.415 32.881 5.397 32.999 ;
     RECT  9.252 32.845 9.378 32.999 ;
     RECT  10.515 31.181 11.106 33.007 ;
     RECT  10.368 33.007 11.106 33.079 ;
     RECT  0.54 32.669 0.558 33.197 ;
     RECT  2.415 32.999 3.834 33.413 ;
     RECT  10.368 33.079 11.214 33.413 ;
     RECT  2.415 33.413 3.114 33.499 ;
     RECT  2.304 33.499 3.114 33.539 ;
     RECT  7.815 32.801 8.097 33.583 ;
     RECT  12.096 32.495 19.026 33.655 ;
     RECT  6.84 32.873 6.858 33.691 ;
     RECT  10.368 33.413 11.106 33.781 ;
     RECT  6.264 33.691 6.858 33.809 ;
     RECT  12.096 33.655 19.062 33.809 ;
     RECT  6.552 33.809 6.858 33.845 ;
     RECT  10.26 33.781 11.106 33.869 ;
     RECT  4.068 33.889 4.086 33.925 ;
     RECT  4.86 32.999 5.397 33.925 ;
     RECT  4.068 33.925 5.706 33.989 ;
     RECT  2.415 33.539 3.114 34.079 ;
     RECT  4.104 33.989 5.706 34.151 ;
     RECT  7.815 33.583 8.154 34.195 ;
     RECT  5.04 34.151 5.706 34.397 ;
     RECT  7.815 34.195 8.73 34.501 ;
     RECT  0.216 33.691 0.234 34.541 ;
     RECT  4.104 34.151 4.194 34.619 ;
     RECT  7.815 34.501 8.838 34.619 ;
     RECT  2.415 34.079 2.826 34.861 ;
     RECT  6.552 33.845 6.57 34.861 ;
     RECT  0.54 34.591 0.558 34.877 ;
     RECT  2.415 34.861 3.006 34.961 ;
     RECT  7.815 34.619 8.37 34.961 ;
     RECT  12.096 33.809 18.954 34.969 ;
     RECT  6.552 34.861 6.858 34.997 ;
     RECT  2.415 34.961 2.697 35.032 ;
     RECT  5.04 34.397 5.454 35.032 ;
     RECT  10.515 33.869 11.106 35.041 ;
     RECT  12.06 34.969 18.954 35.041 ;
     RECT  19.944 31.997 20.538 35.041 ;
     RECT  2.304 35.032 2.697 35.069 ;
     RECT  4.104 34.619 4.122 35.131 ;
     RECT  9.972 35.041 11.106 35.131 ;
     RECT  6.3 35.041 6.39 35.203 ;
     RECT  9.756 35.131 11.106 35.213 ;
     RECT  12.06 35.041 20.538 35.231 ;
     RECT  12.06 35.231 19.062 35.309 ;
     RECT  5.004 35.032 5.454 35.339 ;
     RECT  9.9 35.213 11.106 35.339 ;
     RECT  10.044 35.339 11.106 35.401 ;
     RECT  6.228 35.203 6.39 35.429 ;
     RECT  14.508 35.309 19.062 35.429 ;
     RECT  3.996 35.131 4.122 35.671 ;
     RECT  5.004 35.339 5.397 35.671 ;
     RECT  6.3 35.429 6.39 35.699 ;
     RECT  7.815 34.961 8.097 35.707 ;
     RECT  9.144 35.671 9.162 35.707 ;
     RECT  3.996 35.671 5.397 35.779 ;
     RECT  3.96 35.779 5.397 35.843 ;
     RECT  3.96 35.843 4.266 35.879 ;
     RECT  2.415 35.069 2.697 35.941 ;
     RECT  7.815 35.707 9.162 35.969 ;
     RECT  9.144 35.969 9.162 36.005 ;
     RECT  2.415 35.941 2.79 36.076 ;
     RECT  6.84 35.947 6.858 36.077 ;
     RECT  2.415 36.076 2.826 36.121 ;
     RECT  10.044 35.401 11.25 36.121 ;
     RECT  12.06 35.309 13.734 36.121 ;
     RECT  14.508 35.429 19.026 36.121 ;
     RECT  7.815 35.969 8.406 36.149 ;
     RECT  0.216 35.371 0.234 36.173 ;
     RECT  3.996 35.879 4.266 36.239 ;
     RECT  9.972 36.121 11.25 36.571 ;
     RECT  5.115 35.843 5.397 36.589 ;
     RECT  12.06 36.121 19.026 36.589 ;
     RECT  9.828 36.571 11.25 36.689 ;
     RECT  3.996 36.239 4.014 36.751 ;
     RECT  6.876 36.517 6.894 36.823 ;
     RECT  3.96 36.751 4.014 36.851 ;
     RECT  2.304 36.121 2.826 36.859 ;
     RECT  5.115 36.589 6.138 36.859 ;
     RECT  6.876 36.823 6.93 36.859 ;
     RECT  5.115 36.859 6.93 36.931 ;
     RECT  2.304 36.859 2.862 36.959 ;
     RECT  4.86 36.931 6.93 36.959 ;
     RECT  6.588 36.959 6.93 37.021 ;
     RECT  7.815 36.149 8.097 37.021 ;
     RECT  4.86 36.959 5.67 37.057 ;
     RECT  6.588 37.021 8.097 37.085 ;
     RECT  7.704 37.085 8.097 37.093 ;
     RECT  12.06 36.589 19.062 37.121 ;
     RECT  10.404 36.689 11.25 37.229 ;
     RECT  9.54 36.931 9.558 37.291 ;
     RECT  7.704 37.093 8.226 37.319 ;
     RECT  9.036 37.291 9.558 37.391 ;
     RECT  7.815 37.319 8.226 37.399 ;
     RECT  7.815 37.399 8.298 37.499 ;
     RECT  4.14 37.057 5.67 37.589 ;
     RECT  12.06 37.121 19.026 37.589 ;
     RECT  0.252 37.435 0.27 37.613 ;
     RECT  12.06 37.589 18.954 37.625 ;
     RECT  4.14 37.589 5.397 37.757 ;
     RECT  5.076 37.757 5.397 37.769 ;
     RECT  2.304 36.959 2.697 37.831 ;
     RECT  6.588 37.085 6.822 37.859 ;
     RECT  2.304 37.831 2.862 38.003 ;
     RECT  2.304 38.003 2.826 38.093 ;
     RECT  19.944 35.231 20.538 38.093 ;
     RECT  10.515 37.229 11.25 38.101 ;
     RECT  4.14 37.757 4.194 38.173 ;
     RECT  9.54 37.391 9.558 38.173 ;
     RECT  2.415 38.093 2.826 38.201 ;
     RECT  6.804 37.859 6.822 38.201 ;
     RECT  10.515 38.101 11.286 38.209 ;
     RECT  9.54 38.173 9.702 38.281 ;
     RECT  0.54 38.101 0.558 38.285 ;
     RECT  3.708 38.173 4.194 38.309 ;
     RECT  7.815 37.499 8.097 38.371 ;
     RECT  6.876 38.371 7.038 38.477 ;
     RECT  8.892 38.281 9.702 38.479 ;
     RECT  10.515 38.209 11.322 38.479 ;
     RECT  7.776 38.371 8.097 38.543 ;
     RECT  12.06 37.625 18.897 38.551 ;
     RECT  6.876 38.477 6.894 38.579 ;
     RECT  5.115 37.769 5.397 38.641 ;
     RECT  8.892 38.479 11.322 38.669 ;
     RECT  9.324 38.669 11.322 38.677 ;
     RECT  12.06 38.551 19.062 38.677 ;
     RECT  9.324 38.677 19.062 38.785 ;
     RECT  19.944 38.093 19.998 38.785 ;
     RECT  0.216 38.587 0.234 38.813 ;
     RECT  4.392 38.641 5.85 38.821 ;
     RECT  4.392 38.821 6.138 38.849 ;
     RECT  2.415 38.201 2.697 38.923 ;
     RECT  9.324 38.785 19.998 38.939 ;
     RECT  7.815 38.543 8.097 39.019 ;
     RECT  4.86 38.849 6.138 39.055 ;
     RECT  2.304 38.923 2.697 39.181 ;
     RECT  9.324 38.939 11.178 39.209 ;
     RECT  2.304 39.181 2.898 39.281 ;
     RECT  9.684 39.209 11.178 39.281 ;
     RECT  7.815 39.019 8.55 39.289 ;
     RECT  12.06 38.939 19.998 39.317 ;
     RECT  19.944 39.317 19.998 39.451 ;
     RECT  7.416 39.289 8.55 39.479 ;
     RECT  4.86 39.055 6.318 39.551 ;
     RECT  6.264 39.551 6.318 39.559 ;
     RECT  7.815 39.479 8.55 39.587 ;
     RECT  2.304 39.281 2.826 39.629 ;
     RECT  0.54 39.793 0.558 39.965 ;
     RECT  3.996 39.787 4.014 40.019 ;
     RECT  9.684 39.281 9.702 40.135 ;
     RECT  10.44 39.281 11.178 40.135 ;
     RECT  4.86 39.551 5.49 40.171 ;
     RECT  4.824 40.171 5.49 40.301 ;
     RECT  12.06 39.317 18.897 40.333 ;
     RECT  7.815 39.587 8.514 40.36 ;
     RECT  9.684 40.135 11.178 40.36 ;
     RECT  3.528 40.261 3.546 40.361 ;
     RECT  6.264 39.559 7.002 40.397 ;
     RECT  7.815 40.36 11.178 40.441 ;
     RECT  0.252 40.459 0.27 40.589 ;
     RECT  7.128 40.441 11.178 40.589 ;
     RECT  7.416 40.589 11.178 40.637 ;
     RECT  10.188 40.637 11.178 40.667 ;
     RECT  4.824 40.301 5.397 40.675 ;
     RECT  10.26 40.667 11.178 40.711 ;
     RECT  11.988 40.333 18.897 40.711 ;
     RECT  4.392 40.675 5.397 40.829 ;
     RECT  7.416 40.637 9.162 40.829 ;
     RECT  4.5 40.829 5.397 40.901 ;
     RECT  6.192 40.711 6.21 40.901 ;
     RECT  10.26 40.711 18.897 41.009 ;
     RECT  2.304 39.629 2.697 41.071 ;
     RECT  2.304 41.071 3.006 41.099 ;
     RECT  4.536 40.901 5.397 41.165 ;
     RECT  10.26 41.009 11.178 41.213 ;
     RECT  7.416 40.829 8.514 41.369 ;
     RECT  6.66 41.341 6.678 41.413 ;
     RECT  7.416 41.369 8.298 41.413 ;
     RECT  6.66 41.413 8.298 41.441 ;
     RECT  7.344 41.441 8.298 41.639 ;
     RECT  11.988 41.009 18.897 41.659 ;
     RECT  19.944 39.451 20.538 41.659 ;
     RECT  11.988 41.659 20.538 41.747 ;
     RECT  0.216 41.227 0.234 41.837 ;
     RECT  2.415 41.099 3.006 41.881 ;
     RECT  5.004 41.165 5.397 41.909 ;
     RECT  9.432 41.611 9.45 41.945 ;
     RECT  2.304 41.881 3.222 41.981 ;
     RECT  10.44 41.213 11.178 41.995 ;
     RECT  10.368 41.995 11.178 42.151 ;
     RECT  11.988 41.747 19.098 42.151 ;
     RECT  10.368 42.151 19.098 42.179 ;
     RECT  19.944 41.747 20.538 42.323 ;
     RECT  10.476 42.179 19.098 42.359 ;
     RECT  7.815 41.639 8.298 42.565 ;
     RECT  7.815 42.565 8.694 42.571 ;
     RECT  10.515 42.359 19.098 42.593 ;
     RECT  12.06 42.593 19.098 42.601 ;
     RECT  19.944 42.323 20.034 42.601 ;
     RECT  0.216 42.571 0.234 42.701 ;
     RECT  7.815 42.571 8.802 42.719 ;
     RECT  5.115 41.909 5.397 42.871 ;
     RECT  9.288 42.799 9.414 42.899 ;
     RECT  2.304 41.981 3.186 42.961 ;
     RECT  4.428 42.871 5.397 42.961 ;
     RECT  2.304 42.961 3.618 43.033 ;
     RECT  4.428 42.961 5.526 43.033 ;
     RECT  7.815 42.719 8.097 43.069 ;
     RECT  2.304 43.033 5.526 43.133 ;
     RECT  7.776 43.069 8.097 43.141 ;
     RECT  12.06 42.601 20.034 43.141 ;
     RECT  3.78 43.133 5.526 43.169 ;
     RECT  3.888 43.169 5.526 43.231 ;
     RECT  6.912 43.141 8.097 43.295 ;
     RECT  3.888 43.231 5.85 43.325 ;
     RECT  3.888 43.325 5.526 43.331 ;
     RECT  12.06 43.141 20.574 43.331 ;
     RECT  0.54 43.105 0.558 43.373 ;
     RECT  6.912 43.295 6.93 43.403 ;
     RECT  7.704 43.295 8.097 43.439 ;
     RECT  9.288 42.899 9.306 43.529 ;
     RECT  3.888 43.331 5.397 43.565 ;
     RECT  5.004 43.565 5.397 43.709 ;
     RECT  9.144 43.609 9.162 43.709 ;
     RECT  12.24 43.331 20.574 43.709 ;
     RECT  7.815 43.439 8.097 43.807 ;
     RECT  2.304 43.133 3.006 44.041 ;
     RECT  10.515 42.593 11.178 44.059 ;
     RECT  0.216 44.011 0.234 44.141 ;
     RECT  2.304 44.041 3.87 44.141 ;
     RECT  12.24 43.709 19.962 44.149 ;
     RECT  12.204 44.149 19.962 44.213 ;
     RECT  7.815 43.807 8.154 44.221 ;
     RECT  10.515 44.059 11.43 44.221 ;
     RECT  12.204 44.213 19.026 44.221 ;
     RECT  2.304 44.141 3.438 44.237 ;
     RECT  6.84 43.579 6.858 44.311 ;
     RECT  6.804 44.311 6.93 44.411 ;
     RECT  6.804 44.411 6.822 44.447 ;
     RECT  5.04 43.709 5.397 44.491 ;
     RECT  0.54 44.383 0.558 44.573 ;
     RECT  10.515 44.221 19.026 44.581 ;
     RECT  7.815 44.221 8.91 44.683 ;
     RECT  19.944 44.213 19.962 44.683 ;
     RECT  10.008 44.581 19.026 44.753 ;
     RECT  7.815 44.683 9.234 44.789 ;
     RECT  19.944 44.683 19.998 44.875 ;
     RECT  7.815 44.789 8.514 44.879 ;
     RECT  4.932 44.491 5.397 44.923 ;
     RECT  10.008 44.753 18.897 44.987 ;
     RECT  4.5 44.923 5.397 45.031 ;
     RECT  4.392 45.031 5.397 45.149 ;
     RECT  2.415 44.237 3.438 45.157 ;
     RECT  2.376 45.157 3.438 45.391 ;
     RECT  10.008 44.987 11.178 45.391 ;
     RECT  6.444 45.229 6.462 45.403 ;
     RECT  6.444 45.403 6.858 45.419 ;
     RECT  7.815 44.879 8.406 45.419 ;
     RECT  2.376 45.391 3.834 45.499 ;
     RECT  2.304 45.499 3.834 45.527 ;
     RECT  6.84 45.419 6.858 45.533 ;
     RECT  19.944 44.875 20.538 45.547 ;
     RECT  2.304 45.527 3.726 45.599 ;
     RECT  9.396 45.391 11.178 45.599 ;
     RECT  2.304 45.599 3.33 45.761 ;
     RECT  19.944 45.547 20.574 45.833 ;
     RECT  7.815 45.419 8.097 45.835 ;
     RECT  1.152 45.355 1.17 45.917 ;
     RECT  10.044 45.599 11.178 46.075 ;
     RECT  12.06 44.987 18.897 46.075 ;
     RECT  4.572 45.149 5.397 46.111 ;
     RECT  10.044 46.075 18.897 46.229 ;
     RECT  12.06 46.229 18.897 46.309 ;
     RECT  19.944 45.833 20.538 46.373 ;
     RECT  7.704 45.835 8.097 46.381 ;
     RECT  7.704 46.381 8.694 46.471 ;
     RECT  2.304 45.761 2.697 46.499 ;
     RECT  6.804 46.381 6.822 46.507 ;
     RECT  7.56 46.471 8.694 46.507 ;
     RECT  6.804 46.507 8.694 46.571 ;
     RECT  3.492 46.471 3.51 46.643 ;
     RECT  2.34 46.499 2.697 46.679 ;
     RECT  6.84 46.571 8.694 46.679 ;
     RECT  7.815 46.679 8.694 46.769 ;
     RECT  9.54 46.741 9.63 46.813 ;
     RECT  9.144 46.813 9.63 46.877 ;
     RECT  4.464 46.111 5.778 46.891 ;
     RECT  9.54 46.877 9.63 46.913 ;
     RECT  3.924 46.891 5.778 47.011 ;
     RECT  9.576 46.913 9.63 47.011 ;
     RECT  10.515 46.229 11.178 47.011 ;
     RECT  3.924 47.011 5.886 47.147 ;
     RECT  2.412 46.679 2.697 47.155 ;
     RECT  12.06 46.309 18.954 47.155 ;
     RECT  19.944 46.373 20.034 47.155 ;
     RECT  11.988 47.155 18.954 47.191 ;
     RECT  11.988 47.191 19.098 47.227 ;
     RECT  19.944 47.155 20.538 47.227 ;
     RECT  2.412 47.155 2.934 47.309 ;
     RECT  9.576 47.011 11.178 47.309 ;
     RECT  10.515 47.309 11.178 47.323 ;
     RECT  11.988 47.227 20.538 47.323 ;
     RECT  6.84 46.679 6.894 47.425 ;
     RECT  3.924 47.147 5.397 47.489 ;
     RECT  2.412 47.309 2.754 47.551 ;
     RECT  6.804 47.425 6.894 47.551 ;
     RECT  7.815 46.769 8.154 47.551 ;
     RECT  6.804 47.551 8.154 47.579 ;
     RECT  9.576 47.309 9.702 47.579 ;
     RECT  2.304 47.551 2.754 47.597 ;
     RECT  6.948 47.579 8.154 47.623 ;
     RECT  10.515 47.323 20.538 47.693 ;
     RECT  6.948 47.623 8.586 47.759 ;
     RECT  10.515 47.693 19.17 47.849 ;
     RECT  10.515 47.849 19.098 47.885 ;
     RECT  7.056 47.759 8.586 47.933 ;
     RECT  7.596 47.933 8.586 48.119 ;
     RECT  4.608 47.489 5.397 48.199 ;
     RECT  4.608 48.199 5.778 48.235 ;
     RECT  2.415 47.597 2.754 48.361 ;
     RECT  4.248 48.235 5.778 48.389 ;
     RECT  7.596 48.119 8.442 48.389 ;
     RECT  4.248 48.389 5.397 48.397 ;
     RECT  9.576 47.579 9.594 48.397 ;
     RECT  2.415 48.361 2.826 48.433 ;
     RECT  7.815 48.389 8.442 48.461 ;
     RECT  9.576 48.397 9.702 48.541 ;
     RECT  10.515 47.885 18.99 48.541 ;
     RECT  0.54 47.281 0.558 48.653 ;
     RECT  9.576 48.541 18.99 48.763 ;
     RECT  9.432 48.763 18.99 48.811 ;
     RECT  19.944 47.693 20.538 48.811 ;
     RECT  2.415 48.433 2.898 48.901 ;
     RECT  9.432 48.811 20.538 48.929 ;
     RECT  10.152 48.929 20.538 48.989 ;
     RECT  2.304 48.901 3.258 49.001 ;
     RECT  2.304 49.001 2.697 49.199 ;
     RECT  4.176 48.397 5.397 49.207 ;
     RECT  3.672 49.207 5.397 49.243 ;
     RECT  7.815 48.461 8.298 49.279 ;
     RECT  10.152 48.989 20.034 49.379 ;
     RECT  7.815 49.279 8.586 49.441 ;
     RECT  10.515 49.379 20.034 49.469 ;
     RECT  3.672 49.243 5.958 49.541 ;
     RECT  7.815 49.441 8.838 49.541 ;
     RECT  10.515 49.469 18.954 49.541 ;
     RECT  3.672 49.541 4.014 49.649 ;
     RECT  0.54 49.441 0.558 49.661 ;
     RECT  7.815 49.541 8.586 49.739 ;
     RECT  6.84 49.621 6.858 49.981 ;
     RECT  7.815 49.739 8.442 49.981 ;
     RECT  6.84 49.981 8.442 50.053 ;
     RECT  6.264 50.053 8.442 50.093 ;
     RECT  5.004 49.541 5.49 50.153 ;
     RECT  9.684 50.089 9.702 50.161 ;
     RECT  6.264 50.093 6.93 50.279 ;
     RECT  9.576 50.161 9.702 50.279 ;
     RECT  19.944 49.469 20.034 50.299 ;
     RECT  0.288 50.347 0.306 50.477 ;
     RECT  3.996 49.649 4.014 50.521 ;
     RECT  6.3 50.279 6.93 50.549 ;
     RECT  10.515 49.541 18.897 50.585 ;
     RECT  3.852 50.521 4.014 50.635 ;
     RECT  5.004 50.153 5.397 50.635 ;
     RECT  6.84 50.549 6.93 50.657 ;
     RECT  2.415 49.199 2.697 50.683 ;
     RECT  18.615 50.585 18.897 50.701 ;
     RECT  19.944 50.299 20.538 50.701 ;
     RECT  7.815 50.093 8.442 50.791 ;
     RECT  2.304 50.683 2.697 50.813 ;
     RECT  3.852 50.635 5.397 50.855 ;
     RECT  7.815 50.791 8.766 50.861 ;
     RECT  7.815 50.861 8.622 50.891 ;
     RECT  4.464 50.855 5.397 50.927 ;
     RECT  7.815 50.891 8.37 50.999 ;
     RECT  2.376 50.813 2.697 51.061 ;
     RECT  7.815 50.999 8.19 51.241 ;
     RECT  2.376 51.061 2.754 51.269 ;
     RECT  10.515 50.585 17.802 51.331 ;
     RECT  2.415 51.269 2.754 51.403 ;
     RECT  6.84 50.657 6.858 51.403 ;
     RECT  7.596 51.241 8.19 51.403 ;
     RECT  10.515 51.331 17.874 51.499 ;
     RECT  18.615 50.701 20.538 51.499 ;
     RECT  6.84 51.403 8.19 51.539 ;
     RECT  7.815 51.539 8.19 51.629 ;
     RECT  2.415 51.403 2.862 51.709 ;
     RECT  3.78 51.637 3.798 51.709 ;
     RECT  2.415 51.709 3.798 51.809 ;
     RECT  0.216 51.307 0.234 51.869 ;
     RECT  9.756 52.015 9.774 52.051 ;
     RECT  10.515 51.499 20.538 52.051 ;
     RECT  9.756 52.051 20.538 52.205 ;
     RECT  2.415 51.809 3.33 52.312 ;
     RECT  10.515 52.205 20.538 52.313 ;
     RECT  5.004 50.927 5.397 52.315 ;
     RECT  6.84 51.539 6.93 52.321 ;
     RECT  7.815 51.629 8.097 52.321 ;
     RECT  4.428 52.315 5.397 52.411 ;
     RECT  6.264 52.321 6.93 52.411 ;
     RECT  7.74 52.321 8.097 52.411 ;
     RECT  2.304 52.312 3.33 52.591 ;
     RECT  9.576 52.483 9.702 52.591 ;
     RECT  6.264 52.411 8.097 52.681 ;
     RECT  2.304 52.591 3.546 52.795 ;
     RECT  4.428 52.411 5.418 52.795 ;
     RECT  6.264 52.681 8.154 52.877 ;
     RECT  2.304 52.795 5.418 52.889 ;
     RECT  8.892 52.591 9.702 52.979 ;
     RECT  7.128 52.877 8.154 52.987 ;
     RECT  0.252 52.651 0.27 53.083 ;
     RECT  2.415 52.889 5.418 53.131 ;
     RECT  6.264 52.877 6.39 53.131 ;
     RECT  7.128 52.987 8.766 53.159 ;
     RECT  0.216 53.083 0.27 53.213 ;
     RECT  2.415 53.131 6.39 53.249 ;
     RECT  10.515 52.313 10.797 53.257 ;
     RECT  11.736 52.313 20.538 53.357 ;
     RECT  10.515 53.257 10.926 53.491 ;
     RECT  11.736 53.357 20.034 53.491 ;
     RECT  2.415 53.249 5.397 53.519 ;
     RECT  6.372 53.249 6.39 53.519 ;
     RECT  10.26 53.491 20.034 53.519 ;
     RECT  4.464 53.519 5.397 53.555 ;
     RECT  7.128 53.159 8.097 53.591 ;
     RECT  0.54 53.221 0.558 53.741 ;
     RECT  6.84 53.671 6.858 53.789 ;
     RECT  10.26 53.519 19.062 53.969 ;
     RECT  2.415 53.519 3.402 54.031 ;
     RECT  7.704 53.591 8.097 54.031 ;
     RECT  2.304 54.031 3.402 54.059 ;
     RECT  7.704 54.031 8.73 54.077 ;
     RECT  7.815 54.077 8.73 54.103 ;
     RECT  7.815 54.103 9.162 54.167 ;
     RECT  10.26 53.969 10.797 54.211 ;
     RECT  4.536 53.555 5.397 54.301 ;
     RECT  8.892 54.167 9.162 54.481 ;
     RECT  10.008 54.211 10.797 54.481 ;
     RECT  19.944 53.519 20.034 54.523 ;
     RECT  8.892 54.481 10.797 54.635 ;
     RECT  9 54.635 10.797 54.707 ;
     RECT  11.628 53.969 19.062 54.707 ;
     RECT  11.844 54.707 19.062 54.715 ;
     RECT  19.944 54.523 20.07 54.715 ;
     RECT  0.54 54.679 0.558 54.749 ;
     RECT  2.304 54.059 2.697 54.841 ;
     RECT  9.216 54.707 10.797 54.869 ;
     RECT  9.288 54.869 10.797 54.949 ;
     RECT  2.304 54.841 2.862 55.013 ;
     RECT  6.84 54.607 6.858 55.021 ;
     RECT  4.068 54.301 5.397 55.111 ;
     RECT  2.304 55.013 2.826 55.139 ;
     RECT  6.3 55.021 6.858 55.139 ;
     RECT  9.288 54.949 10.89 55.139 ;
     RECT  9.792 55.139 10.89 55.175 ;
     RECT  11.844 54.715 20.07 55.181 ;
     RECT  10.515 55.175 10.89 55.211 ;
     RECT  3.852 55.111 5.397 55.219 ;
     RECT  2.415 55.139 2.826 55.229 ;
     RECT  3.6 55.219 5.397 55.247 ;
     RECT  11.844 55.181 19.098 55.283 ;
     RECT  3.6 55.247 3.69 55.409 ;
     RECT  4.572 55.247 5.397 55.48 ;
     RECT  4.572 55.48 5.706 55.481 ;
     RECT  3.672 55.409 3.69 55.553 ;
     RECT  7.815 54.167 8.097 55.651 ;
     RECT  19.908 55.181 20.07 55.723 ;
     RECT  6.48 55.139 6.858 55.759 ;
     RECT  7.776 55.651 8.097 55.759 ;
     RECT  19.908 55.723 20.538 55.823 ;
     RECT  0.252 55.867 0.27 56.045 ;
     RECT  11.916 55.283 19.098 56.059 ;
     RECT  19.908 55.823 19.962 56.059 ;
     RECT  5.115 55.481 5.706 56.101 ;
     RECT  6.48 55.759 8.097 56.101 ;
     RECT  10.515 55.211 10.854 56.101 ;
     RECT  5.115 56.101 8.097 56.219 ;
     RECT  9.576 56.101 9.594 56.219 ;
     RECT  10.515 56.101 10.998 56.227 ;
     RECT  11.916 56.059 19.962 56.227 ;
     RECT  5.115 56.219 6.03 56.291 ;
     RECT  10.515 56.227 19.962 56.327 ;
     RECT  6.84 56.219 8.097 56.371 ;
     RECT  10.515 56.327 18.99 56.399 ;
     RECT  2.415 55.229 2.697 56.461 ;
     RECT  6.84 56.371 8.586 56.461 ;
     RECT  0.324 56.059 0.342 56.561 ;
     RECT  5.115 56.291 5.397 56.605 ;
     RECT  6.84 56.461 8.694 56.669 ;
     RECT  2.415 56.461 3.078 56.731 ;
     RECT  10.515 56.399 11.034 56.731 ;
     RECT  4.896 56.605 5.397 56.759 ;
     RECT  7.164 56.669 8.694 56.759 ;
     RECT  7.236 56.759 8.097 56.903 ;
     RECT  19.944 56.327 19.962 56.923 ;
     RECT  10.476 56.731 11.034 57.065 ;
     RECT  2.304 56.731 3.222 57.101 ;
     RECT  5.115 56.759 5.397 57.109 ;
     RECT  2.415 57.101 3.222 57.145 ;
     RECT  14.544 56.399 18.99 57.145 ;
     RECT  19.944 56.923 19.998 57.145 ;
     RECT  5.115 57.109 5.598 57.181 ;
     RECT  11.916 56.399 13.734 57.181 ;
     RECT  14.544 57.145 19.998 57.181 ;
     RECT  2.415 57.145 3.474 57.271 ;
     RECT  2.415 57.271 3.546 57.299 ;
     RECT  9.108 57.271 9.27 57.343 ;
     RECT  3.528 57.299 3.546 57.371 ;
     RECT  11.916 57.181 19.998 57.443 ;
     RECT  0.216 56.923 0.234 57.541 ;
     RECT  1.152 57.259 1.17 57.541 ;
     RECT  10.515 57.065 11.034 57.541 ;
     RECT  0.216 57.541 1.17 57.569 ;
     RECT  10.515 57.541 11.106 57.641 ;
     RECT  7.815 56.903 8.097 57.649 ;
     RECT  9.108 57.343 9.378 57.721 ;
     RECT  9.108 57.721 9.594 57.811 ;
     RECT  10.515 57.641 10.926 57.811 ;
     RECT  9.108 57.811 10.926 57.839 ;
     RECT  0.216 57.569 0.558 57.869 ;
     RECT  9.108 57.839 9.45 57.869 ;
     RECT  10.188 57.839 10.926 57.947 ;
     RECT  10.188 57.947 10.797 57.983 ;
     RECT  7.815 57.649 8.154 57.991 ;
     RECT  9.108 57.869 9.342 57.991 ;
     RECT  7.815 57.991 9.342 58.019 ;
     RECT  2.415 57.299 2.79 58.081 ;
     RECT  5.115 57.181 6.138 58.153 ;
     RECT  2.415 58.081 3.006 58.181 ;
     RECT  2.415 58.181 2.697 58.267 ;
     RECT  5.115 58.153 6.858 58.379 ;
     RECT  10.44 57.983 10.797 58.379 ;
     RECT  6.372 58.379 6.858 58.451 ;
     RECT  11.916 57.443 19.962 58.523 ;
     RECT  11.916 58.523 19.17 58.531 ;
     RECT  3.996 57.931 4.014 58.621 ;
     RECT  7.815 58.019 9.126 58.649 ;
     RECT  11.772 58.531 19.17 58.649 ;
     RECT  11.772 58.649 19.134 58.685 ;
     RECT  3.96 58.621 4.014 58.693 ;
     RECT  5.115 58.379 5.397 58.693 ;
     RECT  10.515 58.379 10.797 58.729 ;
     RECT  11.772 58.685 19.026 58.729 ;
     RECT  2.304 58.267 2.697 58.963 ;
     RECT  0.54 57.869 0.558 59.035 ;
     RECT  3.96 58.693 5.397 59.099 ;
     RECT  4.932 59.099 5.397 59.161 ;
     RECT  10.515 58.729 19.026 59.161 ;
     RECT  0.216 59.035 1.17 59.165 ;
     RECT  7.056 58.765 7.074 59.189 ;
     RECT  9.936 59.161 19.026 59.189 ;
     RECT  2.304 58.963 3.078 59.197 ;
     RECT  0.504 59.165 1.17 59.213 ;
     RECT  19.944 58.523 19.962 59.26 ;
     RECT  0.504 59.213 0.558 59.309 ;
     RECT  4.932 59.161 5.526 59.333 ;
     RECT  4.932 59.333 5.397 59.459 ;
     RECT  2.304 59.197 3.654 59.501 ;
     RECT  9.936 59.189 10.926 59.611 ;
     RECT  7.815 58.649 8.097 59.701 ;
     RECT  9.828 59.611 10.926 59.701 ;
     RECT  2.415 59.501 3.654 59.729 ;
     RECT  3.564 59.729 3.654 59.801 ;
     RECT  6.876 59.611 6.894 59.837 ;
     RECT  7.812 59.701 8.802 59.837 ;
     RECT  9.756 59.701 10.926 59.837 ;
     RECT  7.812 59.837 8.097 59.845 ;
     RECT  0.504 59.309 0.522 59.947 ;
     RECT  12.06 59.189 13.698 59.971 ;
     RECT  14.544 59.189 19.026 59.971 ;
     RECT  0.216 59.947 0.522 59.999 ;
     RECT  7.704 59.845 8.097 59.999 ;
     RECT  10.08 59.837 10.926 59.999 ;
     RECT  4.14 59.971 4.302 60.071 ;
     RECT  10.296 59.999 10.926 60.071 ;
     RECT  6.444 60.079 6.858 60.151 ;
     RECT  5.115 59.459 5.397 60.241 ;
     RECT  6.336 60.151 6.858 60.269 ;
     RECT  5.112 60.241 5.397 60.413 ;
     RECT  0.504 59.999 0.522 60.619 ;
     RECT  1.26 60.475 1.278 60.619 ;
     RECT  19.944 59.26 19.998 60.619 ;
     RECT  0.504 60.619 1.278 60.653 ;
     RECT  5.115 60.413 5.397 60.691 ;
     RECT  10.296 60.071 10.854 60.719 ;
     RECT  2.415 59.729 2.697 60.781 ;
     RECT  12.06 59.971 19.026 60.781 ;
     RECT  19.944 60.619 20.034 60.781 ;
     RECT  5.115 60.691 5.85 60.809 ;
     RECT  6.84 60.269 6.858 60.853 ;
     RECT  10.515 60.719 10.854 60.853 ;
     RECT  0.504 60.653 1.17 60.859 ;
     RECT  4.14 60.071 4.158 60.859 ;
     RECT  2.415 60.781 3.114 60.881 ;
     RECT  0.252 60.859 1.17 60.941 ;
     RECT  9.576 60.853 9.666 60.953 ;
     RECT  4.068 60.859 4.158 60.961 ;
     RECT  0.252 60.941 0.558 60.989 ;
     RECT  10.515 60.853 10.998 60.989 ;
     RECT  6.84 60.853 6.93 61.087 ;
     RECT  7.815 59.999 8.097 61.087 ;
     RECT  0.54 60.989 0.558 61.181 ;
     RECT  9.576 60.953 9.594 61.195 ;
     RECT  6.84 61.087 8.097 61.231 ;
     RECT  5.115 60.809 5.67 61.259 ;
     RECT  3.996 60.961 4.158 61.321 ;
     RECT  5.115 61.259 5.397 61.321 ;
     RECT  6.84 61.231 8.262 61.349 ;
     RECT  12.06 60.781 20.034 61.357 ;
     RECT  3.996 61.321 5.397 61.421 ;
     RECT  2.415 60.881 2.697 61.483 ;
     RECT  11.988 61.357 20.034 61.493 ;
     RECT  3.996 61.421 4.05 61.591 ;
     RECT  12.06 61.493 20.034 61.691 ;
     RECT  9.108 61.195 9.594 61.735 ;
     RECT  12.06 61.691 19.998 61.763 ;
     RECT  9 61.735 9.594 61.771 ;
     RECT  2.304 61.483 2.697 61.861 ;
     RECT  9 61.771 9.702 61.861 ;
     RECT  10.515 60.989 10.926 61.861 ;
     RECT  9 61.861 10.926 61.889 ;
     RECT  3.96 61.591 4.05 61.897 ;
     RECT  4.896 61.421 5.397 62.033 ;
     RECT  5.115 62.033 5.397 62.041 ;
     RECT  9.252 61.889 10.926 62.069 ;
     RECT  2.304 61.861 2.79 62.131 ;
     RECT  3.924 61.897 4.05 62.131 ;
     RECT  6.84 61.349 8.097 62.239 ;
     RECT  10.515 62.069 10.926 62.275 ;
     RECT  2.304 62.131 4.05 62.303 ;
     RECT  5.115 62.041 5.49 62.311 ;
     RECT  6.516 62.239 8.097 62.311 ;
     RECT  2.304 62.303 3.114 62.339 ;
     RECT  5.115 62.311 5.562 62.429 ;
     RECT  10.515 62.275 10.998 62.429 ;
     RECT  6.444 62.311 8.097 62.501 ;
     RECT  6.516 62.501 8.097 62.609 ;
     RECT  6.732 62.609 8.097 62.699 ;
     RECT  9.252 62.069 9.738 62.699 ;
     RECT  0.54 62.671 0.558 62.717 ;
     RECT  10.515 62.429 10.926 62.815 ;
     RECT  19.944 61.763 19.998 62.827 ;
     RECT  2.304 62.339 2.934 62.843 ;
     RECT  7.815 62.699 8.097 62.941 ;
     RECT  9.252 62.699 9.342 62.941 ;
     RECT  12.06 61.763 19.026 62.941 ;
     RECT  19.944 62.827 20.07 62.941 ;
     RECT  2.304 62.843 2.697 62.969 ;
     RECT  6.732 62.699 6.858 62.969 ;
     RECT  12.06 62.941 20.07 63.005 ;
     RECT  3.96 62.303 4.05 63.013 ;
     RECT  6.804 62.969 6.858 63.041 ;
     RECT  10.404 62.815 10.926 63.041 ;
     RECT  7.815 62.941 9.342 63.053 ;
     RECT  5.115 62.429 5.397 63.067 ;
     RECT  6.84 63.041 6.858 63.149 ;
     RECT  8.856 63.053 9.342 63.239 ;
     RECT  10.404 63.041 10.797 63.239 ;
     RECT  9.324 63.239 9.342 63.311 ;
     RECT  3.96 63.013 4.302 63.391 ;
     RECT  5.076 63.067 5.397 63.391 ;
     RECT  3.96 63.391 5.397 63.481 ;
     RECT  3.96 63.481 5.886 63.509 ;
     RECT  4.284 63.509 5.886 63.589 ;
     RECT  4.284 63.589 5.994 63.689 ;
     RECT  19.908 63.005 20.07 63.725 ;
     RECT  4.284 63.689 5.397 63.779 ;
     RECT  12.06 63.005 19.026 63.851 ;
     RECT  7.815 63.053 8.097 63.859 ;
     RECT  12.06 63.851 18.918 63.923 ;
     RECT  10.515 63.239 10.797 63.931 ;
     RECT  19.944 63.725 20.07 64.027 ;
     RECT  3.42 63.931 3.438 64.049 ;
     RECT  7.815 63.859 8.298 64.057 ;
     RECT  9.648 63.883 9.666 64.057 ;
     RECT  2.415 62.969 2.697 64.093 ;
     RECT  6.372 63.931 6.498 64.129 ;
     RECT  7.308 64.057 8.298 64.129 ;
     RECT  10.515 63.931 11.322 64.129 ;
     RECT  12.06 63.923 18.897 64.129 ;
     RECT  1.152 64.027 1.17 64.157 ;
     RECT  2.415 64.093 3.114 64.201 ;
     RECT  6.372 64.129 8.298 64.201 ;
     RECT  4.392 63.779 5.397 64.229 ;
     RECT  10.515 64.129 18.897 64.229 ;
     RECT  9.54 64.057 9.666 64.319 ;
     RECT  6.372 64.201 8.406 64.327 ;
     RECT  6.372 64.327 8.586 64.427 ;
     RECT  10.515 64.229 10.854 64.471 ;
     RECT  0.54 64.363 0.558 64.589 ;
     RECT  9.9 64.471 10.854 64.589 ;
     RECT  10.515 64.589 10.854 64.697 ;
     RECT  19.944 64.027 20.538 64.769 ;
     RECT  2.304 64.201 3.114 64.831 ;
     RECT  3.852 64.597 4.194 64.831 ;
     RECT  2.304 64.831 4.194 64.859 ;
     RECT  6.192 64.741 6.21 64.859 ;
     RECT  4.176 64.859 4.194 64.931 ;
     RECT  2.304 64.859 3.294 64.967 ;
     RECT  11.988 64.229 18.897 64.973 ;
     RECT  0.216 65.011 0.234 65.069 ;
     RECT  12.06 64.973 18.897 65.101 ;
     RECT  6.948 64.427 8.586 65.227 ;
     RECT  6.948 65.227 8.73 65.273 ;
     RECT  9.648 65.101 9.738 65.273 ;
     RECT  5.076 64.229 5.397 65.371 ;
     RECT  4.32 65.371 5.397 65.479 ;
     RECT  1.152 65.371 1.17 65.501 ;
     RECT  4.32 65.479 5.85 65.501 ;
     RECT  4.572 65.501 5.85 65.507 ;
     RECT  5.076 65.507 5.85 65.669 ;
     RECT  12.06 65.101 18.954 65.704 ;
     RECT  11.988 65.704 18.954 65.707 ;
     RECT  19.944 64.769 20.034 65.707 ;
     RECT  2.304 64.967 2.697 65.713 ;
     RECT  6.948 65.273 8.334 65.713 ;
     RECT  11.988 65.707 20.034 65.713 ;
     RECT  11.988 65.713 20.574 65.785 ;
     RECT  10.515 64.697 10.797 65.821 ;
     RECT  9.648 65.273 9.666 65.911 ;
     RECT  5.076 65.669 5.706 65.975 ;
     RECT  6.768 65.713 8.334 66.019 ;
     RECT  9.18 65.911 9.666 66.019 ;
     RECT  10.515 65.821 10.926 66.047 ;
     RECT  11.808 65.785 20.574 66.083 ;
     RECT  6.768 66.019 9.666 66.119 ;
     RECT  2.304 65.713 2.826 66.181 ;
     RECT  12.06 66.083 20.574 66.209 ;
     RECT  6.768 66.119 8.406 66.361 ;
     RECT  19.944 66.209 20.574 66.361 ;
     RECT  0.216 66.427 0.234 66.479 ;
     RECT  6.66 66.361 8.406 66.479 ;
     RECT  5.115 65.975 5.706 66.523 ;
     RECT  6.66 66.479 6.858 66.523 ;
     RECT  7.815 66.479 8.406 66.551 ;
     RECT  5.115 66.523 6.858 66.659 ;
     RECT  7.815 66.551 8.262 66.659 ;
     RECT  9.468 66.119 9.666 66.721 ;
     RECT  10.515 66.047 10.797 66.721 ;
     RECT  9.468 66.721 10.797 66.749 ;
     RECT  2.304 66.181 3.222 66.793 ;
     RECT  19.944 66.361 20.61 66.797 ;
     RECT  10.008 66.749 10.797 66.821 ;
     RECT  10.515 66.821 10.797 66.829 ;
     RECT  19.944 66.797 20.538 66.893 ;
     RECT  2.304 66.793 3.834 66.929 ;
     RECT  5.115 66.659 5.598 67.019 ;
     RECT  5.115 67.019 5.454 67.133 ;
     RECT  12.06 66.209 19.206 67.243 ;
     RECT  19.944 66.893 19.998 67.243 ;
     RECT  6.516 66.659 6.858 67.261 ;
     RECT  7.815 66.659 8.097 67.261 ;
     RECT  6.516 67.261 8.097 67.289 ;
     RECT  6.84 67.289 8.097 67.373 ;
     RECT  10.515 66.829 10.998 67.441 ;
     RECT  5.115 67.133 5.397 67.531 ;
     RECT  5.076 67.531 5.397 67.613 ;
     RECT  7.776 67.373 8.097 67.639 ;
     RECT  0.54 66.901 0.558 67.675 ;
     RECT  2.304 66.929 3.762 67.675 ;
     RECT  7.776 67.639 8.586 67.711 ;
     RECT  10.515 67.441 11.034 67.801 ;
     RECT  0.216 67.675 0.558 67.805 ;
     RECT  2.304 67.675 4.374 67.829 ;
     RECT  9.936 67.801 11.034 67.829 ;
     RECT  7.776 67.711 8.694 67.873 ;
     RECT  9.936 67.829 10.926 67.873 ;
     RECT  7.776 67.873 10.926 68.009 ;
     RECT  12.06 67.243 19.998 68.107 ;
     RECT  2.304 67.829 4.23 68.141 ;
     RECT  6.84 67.373 6.93 68.251 ;
     RECT  7.776 68.009 8.946 68.251 ;
     RECT  2.415 68.141 4.23 68.279 ;
     RECT  12.06 68.107 20.538 68.285 ;
     RECT  6.84 68.251 8.946 68.369 ;
     RECT  9.9 68.009 10.926 68.369 ;
     RECT  8.928 68.369 8.946 68.513 ;
     RECT  5.115 67.613 5.397 68.611 ;
     RECT  12.06 68.285 19.026 68.639 ;
     RECT  10.044 68.369 10.926 68.669 ;
     RECT  0.54 67.805 0.558 68.683 ;
     RECT  2.415 68.279 3.258 68.711 ;
     RECT  4.428 68.611 5.922 68.711 ;
     RECT  6.84 68.369 8.097 68.719 ;
     RECT  0.54 68.683 1.17 68.813 ;
     RECT  2.415 68.711 2.97 68.909 ;
     RECT  6.804 68.719 8.097 68.909 ;
     RECT  2.415 68.909 2.826 69.115 ;
     RECT  2.304 69.115 2.826 69.179 ;
     RECT  6.912 68.909 8.097 69.179 ;
     RECT  4.428 68.711 5.778 69.197 ;
     RECT  8.928 69.259 8.946 69.295 ;
     RECT  10.515 68.669 10.926 69.331 ;
     RECT  8.928 69.295 9.162 69.341 ;
     RECT  5.115 69.197 5.778 69.359 ;
     RECT  8.928 69.341 8.946 69.359 ;
     RECT  7.632 69.179 8.097 69.449 ;
     RECT  2.415 69.179 2.826 69.485 ;
     RECT  4.356 69.421 4.374 69.493 ;
     RECT  4.284 69.493 4.374 69.593 ;
     RECT  4.284 69.593 4.302 69.629 ;
     RECT  0.54 68.813 0.558 69.677 ;
     RECT  10.515 69.331 10.998 69.691 ;
     RECT  12.06 68.639 18.954 69.691 ;
     RECT  10.044 69.691 10.998 69.799 ;
     RECT  6.84 69.763 6.858 69.821 ;
     RECT  10.044 69.799 11.106 69.989 ;
     RECT  2.415 69.485 2.697 70.123 ;
     RECT  2.304 70.123 2.697 70.339 ;
     RECT  5.115 69.359 5.598 70.375 ;
     RECT  4.14 70.375 4.158 70.411 ;
     RECT  5.115 70.375 5.67 70.411 ;
     RECT  10.044 69.989 10.797 70.501 ;
     RECT  4.14 70.411 5.67 70.529 ;
     RECT  7.815 69.449 8.097 70.537 ;
     RECT  2.304 70.339 3.222 70.541 ;
     RECT  7.815 70.537 8.406 70.609 ;
     RECT  4.536 70.529 5.67 70.645 ;
     RECT  6.624 70.501 6.642 70.673 ;
     RECT  9.756 70.501 10.797 70.685 ;
     RECT  7.815 70.609 8.658 70.799 ;
     RECT  4.536 70.645 5.814 70.829 ;
     RECT  19.944 68.285 20.538 70.943 ;
     RECT  10.404 70.685 10.797 70.979 ;
     RECT  2.304 70.541 2.754 71.021 ;
     RECT  12.06 69.691 19.026 71.041 ;
     RECT  11.988 71.041 19.026 71.179 ;
     RECT  19.944 70.943 19.998 71.179 ;
     RECT  10.44 70.979 10.797 71.185 ;
     RECT  11.952 71.179 19.998 71.185 ;
     RECT  6.84 70.879 6.858 71.213 ;
     RECT  10.44 71.185 19.998 71.219 ;
     RECT  3.492 70.771 3.69 71.249 ;
     RECT  10.44 71.219 18.99 71.339 ;
     RECT  0.54 71.185 0.558 71.357 ;
     RECT  8.928 70.807 9.234 71.483 ;
     RECT  5.004 70.829 5.814 71.491 ;
     RECT  8.928 71.483 9.198 71.519 ;
     RECT  10.44 71.339 11.214 71.519 ;
     RECT  2.415 71.021 2.754 71.581 ;
     RECT  5.004 71.491 6.03 71.617 ;
     RECT  4.896 71.617 6.03 71.645 ;
     RECT  4.896 71.645 5.397 71.653 ;
     RECT  2.415 71.581 3.33 71.681 ;
     RECT  4.824 71.653 5.397 71.753 ;
     RECT  9.144 71.519 9.198 71.789 ;
     RECT  2.415 71.681 2.826 71.851 ;
     RECT  6.912 71.617 6.93 71.995 ;
     RECT  10.44 71.519 10.854 71.995 ;
     RECT  7.815 70.799 8.097 72.031 ;
     RECT  6.12 71.959 6.138 72.059 ;
     RECT  10.368 71.995 10.854 72.059 ;
     RECT  6.912 71.995 7.074 72.149 ;
     RECT  7.812 72.031 8.097 72.149 ;
     RECT  10.515 72.059 10.854 72.149 ;
     RECT  6.912 72.149 6.966 72.187 ;
     RECT  19.944 71.219 19.998 72.187 ;
     RECT  12.06 71.339 18.99 72.235 ;
     RECT  7.815 72.149 8.097 72.391 ;
     RECT  9.144 71.789 9.162 72.391 ;
     RECT  4.896 71.753 5.397 72.499 ;
     RECT  3.96 72.121 3.978 72.523 ;
     RECT  4.824 72.499 5.397 72.535 ;
     RECT  3.96 72.523 4.014 72.571 ;
     RECT  6.84 72.187 6.966 72.689 ;
     RECT  2.304 71.851 2.826 72.697 ;
     RECT  3.924 72.571 4.014 72.697 ;
     RECT  6.84 72.689 6.858 72.701 ;
     RECT  4.824 72.535 5.814 72.725 ;
     RECT  5.115 72.725 5.814 72.797 ;
     RECT  12.06 72.235 19.026 72.841 ;
     RECT  19.944 72.187 20.538 72.859 ;
     RECT  2.304 72.697 4.014 72.893 ;
     RECT  2.415 72.893 4.014 72.959 ;
     RECT  19.944 72.859 20.574 73.031 ;
     RECT  0.216 72.841 0.234 73.037 ;
     RECT  3.996 72.959 4.014 73.075 ;
     RECT  12.06 72.841 19.062 73.111 ;
     RECT  5.115 72.797 5.598 73.229 ;
     RECT  10.515 72.149 10.797 73.237 ;
     RECT  11.736 73.111 19.062 73.237 ;
     RECT  10.515 73.237 19.062 73.291 ;
     RECT  6.552 73.291 6.57 73.309 ;
     RECT  6.336 73.309 6.57 73.337 ;
     RECT  7.815 72.391 9.162 73.381 ;
     RECT  10.515 73.291 19.17 73.387 ;
     RECT  19.944 73.031 20.538 73.387 ;
     RECT  6.336 73.337 6.354 73.409 ;
     RECT  7.815 73.381 9.198 73.499 ;
     RECT  3.996 73.075 4.158 73.565 ;
     RECT  10.515 73.387 20.538 73.579 ;
     RECT  5.115 73.229 5.454 73.615 ;
     RECT  7.815 73.499 8.586 73.841 ;
     RECT  7.815 73.841 8.514 73.885 ;
     RECT  4.32 73.615 5.454 73.901 ;
     RECT  10.116 73.579 20.538 74.011 ;
     RECT  4.32 73.901 5.397 74.039 ;
     RECT  7.38 73.885 8.514 74.039 ;
     RECT  9.396 74.011 20.538 74.039 ;
     RECT  9.396 74.039 9.414 74.093 ;
     RECT  7.38 74.039 8.097 74.111 ;
     RECT  2.415 72.959 2.697 74.191 ;
     RECT  2.415 74.191 3.33 74.203 ;
     RECT  4.32 74.039 4.338 74.309 ;
     RECT  10.515 74.039 20.538 74.309 ;
     RECT  6.84 74.317 6.93 74.489 ;
     RECT  2.34 74.203 3.33 74.539 ;
     RECT  4.104 74.389 4.122 74.579 ;
     RECT  2.304 74.539 3.33 74.759 ;
     RECT  2.415 74.759 3.33 74.821 ;
     RECT  8.928 74.695 8.946 74.849 ;
     RECT  2.415 74.821 4.05 74.909 ;
     RECT  10.515 74.309 11.178 74.929 ;
     RECT  5.115 74.039 5.397 75.001 ;
     RECT  10.332 74.929 11.178 75.001 ;
     RECT  3.492 74.909 4.05 75.029 ;
     RECT  19.944 74.309 20.538 75.029 ;
     RECT  5.115 75.001 5.886 75.091 ;
     RECT  9.9 75.001 11.178 75.091 ;
     RECT  12.06 74.309 18.954 75.091 ;
     RECT  6.84 74.489 6.858 75.191 ;
     RECT  9.432 75.091 11.178 75.191 ;
     RECT  12.06 75.091 19.026 75.191 ;
     RECT  9.9 75.191 11.178 75.227 ;
     RECT  3.996 75.029 4.05 75.245 ;
     RECT  10.476 75.227 11.178 75.389 ;
     RECT  0.54 75.163 0.558 75.437 ;
     RECT  5.004 75.091 5.886 75.631 ;
     RECT  6.912 75.235 6.966 75.631 ;
     RECT  7.815 74.111 8.097 75.631 ;
     RECT  2.415 74.909 2.697 75.739 ;
     RECT  4.5 75.631 5.886 75.775 ;
     RECT  2.412 75.739 2.697 75.787 ;
     RECT  10.515 75.389 11.178 75.803 ;
     RECT  6.912 75.631 8.097 75.937 ;
     RECT  6.84 75.937 8.097 75.973 ;
     RECT  2.304 75.787 2.697 75.979 ;
     RECT  12.06 75.191 18.954 76.001 ;
     RECT  0.216 75.547 0.234 76.109 ;
     RECT  2.304 75.979 2.862 76.109 ;
     RECT  6.84 75.973 8.514 76.243 ;
     RECT  3.744 76.171 3.762 76.267 ;
     RECT  4.5 75.775 6.066 76.267 ;
     RECT  19.944 75.029 19.998 76.267 ;
     RECT  3.744 76.267 6.066 76.271 ;
     RECT  6.804 76.243 8.514 76.271 ;
     RECT  10.515 75.803 10.926 76.271 ;
     RECT  10.515 76.271 10.89 76.379 ;
     RECT  10.515 76.379 10.797 76.441 ;
     RECT  0.54 76.171 0.558 76.445 ;
     RECT  7.815 76.271 8.514 76.504 ;
     RECT  19.944 76.267 20.538 76.541 ;
     RECT  9.9 76.441 10.797 76.549 ;
     RECT  7.815 76.504 8.622 76.585 ;
     RECT  4.068 76.271 6.066 76.621 ;
     RECT  6.804 76.271 6.858 76.621 ;
     RECT  9.576 76.549 10.797 76.621 ;
     RECT  4.068 76.621 6.858 76.649 ;
     RECT  12.06 76.001 18.897 76.739 ;
     RECT  4.068 76.649 5.397 76.775 ;
     RECT  9.432 76.621 10.797 76.781 ;
     RECT  14.544 76.739 18.897 76.783 ;
     RECT  6.408 76.649 6.858 76.919 ;
     RECT  14.544 76.783 18.954 76.919 ;
     RECT  15.336 76.919 18.954 76.981 ;
     RECT  2.304 76.109 2.697 76.987 ;
     RECT  4.068 76.775 4.302 77.021 ;
     RECT  15.336 76.981 19.026 77.081 ;
     RECT  0.396 76.939 0.414 77.083 ;
     RECT  2.304 76.987 2.79 77.116 ;
     RECT  0.216 77.083 0.414 77.117 ;
     RECT  9.864 76.781 10.797 77.189 ;
     RECT  0.216 77.117 0.234 77.213 ;
     RECT  6.84 76.919 6.858 77.251 ;
     RECT  7.815 76.585 8.694 77.251 ;
     RECT  10.404 77.189 10.797 77.287 ;
     RECT  10.404 77.287 11.286 77.323 ;
     RECT  12.06 76.739 13.698 77.323 ;
     RECT  6.84 77.251 8.694 77.431 ;
     RECT  10.404 77.323 13.698 77.459 ;
     RECT  2.304 77.116 2.826 77.521 ;
     RECT  10.515 77.459 13.698 77.521 ;
     RECT  14.544 76.919 14.598 77.521 ;
     RECT  6.84 77.431 8.766 77.549 ;
     RECT  10.515 77.521 14.598 77.549 ;
     RECT  5.115 76.775 5.397 77.665 ;
     RECT  6.84 77.549 8.73 77.665 ;
     RECT  11.88 77.549 14.598 77.693 ;
     RECT  11.952 77.693 14.598 77.701 ;
     RECT  15.336 77.081 18.897 77.701 ;
     RECT  2.304 77.521 3.726 77.729 ;
     RECT  2.304 77.729 3.006 77.819 ;
     RECT  6.768 77.665 8.73 77.819 ;
     RECT  5.115 77.665 5.526 77.863 ;
     RECT  11.952 77.701 18.897 77.863 ;
     RECT  2.415 77.819 3.006 77.891 ;
     RECT  11.952 77.863 18.954 77.899 ;
     RECT  0.252 77.899 0.27 77.971 ;
     RECT  7.416 77.819 8.73 78.125 ;
     RECT  3.996 78.169 4.014 78.205 ;
     RECT  5.115 77.863 6.498 78.205 ;
     RECT  11.952 77.899 19.026 78.205 ;
     RECT  11.952 78.205 19.098 78.241 ;
     RECT  19.944 76.541 20.07 78.241 ;
     RECT  3.996 78.205 6.498 78.269 ;
     RECT  7.815 78.125 8.73 78.269 ;
     RECT  9.54 77.971 9.558 78.269 ;
     RECT  11.952 78.241 20.07 78.283 ;
     RECT  3.996 78.269 5.886 78.359 ;
     RECT  11.952 78.283 20.538 78.359 ;
     RECT  10.515 77.549 11.034 78.439 ;
     RECT  11.952 78.359 19.098 78.439 ;
     RECT  0.252 77.971 0.558 78.461 ;
     RECT  19.944 78.359 20.538 78.503 ;
     RECT  10.515 78.439 19.098 78.629 ;
     RECT  19.944 78.503 20.142 78.665 ;
     RECT  8.82 78.601 9.486 78.701 ;
     RECT  9.108 78.701 9.486 78.773 ;
     RECT  5.115 78.359 5.886 78.899 ;
     RECT  11.988 78.629 19.098 78.899 ;
     RECT  3.996 78.359 4.266 78.979 ;
     RECT  2.415 77.891 2.697 79.051 ;
     RECT  3.852 78.979 4.266 79.079 ;
     RECT  2.415 79.051 3.042 79.141 ;
     RECT  5.115 78.899 5.397 79.141 ;
     RECT  9.144 78.773 9.486 79.169 ;
     RECT  2.304 79.141 3.042 79.181 ;
     RECT  2.415 79.181 3.042 79.241 ;
     RECT  10.515 78.629 11.106 79.241 ;
     RECT  7.815 78.269 8.097 79.285 ;
     RECT  12.06 78.899 19.098 79.291 ;
     RECT  19.944 78.665 20.07 79.291 ;
     RECT  2.415 79.241 2.898 79.349 ;
     RECT  7.815 79.285 8.262 79.439 ;
     RECT  10.515 79.241 10.962 79.439 ;
     RECT  9.144 79.169 9.234 79.519 ;
     RECT  8.928 79.519 9.234 79.583 ;
     RECT  12.06 79.291 20.07 79.591 ;
     RECT  8.928 79.583 8.946 79.619 ;
     RECT  4.32 79.141 5.397 79.709 ;
     RECT  4.536 79.709 5.397 79.717 ;
     RECT  12.06 79.591 20.574 79.757 ;
     RECT  12.06 79.757 19.134 79.789 ;
     RECT  4.536 79.717 5.85 79.825 ;
     RECT  6.84 79.285 6.858 79.825 ;
     RECT  0.54 78.461 0.558 79.853 ;
     RECT  4.536 79.825 6.858 79.861 ;
     RECT  7.815 79.439 8.097 79.861 ;
     RECT  2.415 79.349 2.79 79.951 ;
     RECT  4.536 79.861 8.097 79.979 ;
     RECT  4.536 79.979 5.397 79.997 ;
     RECT  6.804 79.979 8.097 80.123 ;
     RECT  6.84 80.123 8.097 80.159 ;
     RECT  19.944 79.757 20.574 80.189 ;
     RECT  2.304 79.951 2.79 80.221 ;
     RECT  10.515 79.439 10.854 80.221 ;
     RECT  11.808 79.789 19.134 80.249 ;
     RECT  0.288 80.155 0.306 80.285 ;
     RECT  6.876 80.159 8.097 80.329 ;
     RECT  19.944 80.189 20.538 80.333 ;
     RECT  2.304 80.221 2.898 80.365 ;
     RECT  3.672 80.293 3.69 80.365 ;
     RECT  10.152 80.221 10.854 80.401 ;
     RECT  6.876 80.329 8.73 80.491 ;
     RECT  6.876 80.491 8.838 80.519 ;
     RECT  11.916 80.249 19.134 80.573 ;
     RECT  7.02 80.519 8.838 80.591 ;
     RECT  11.988 80.573 19.134 80.627 ;
     RECT  9.36 80.599 9.378 80.635 ;
     RECT  10.152 80.401 10.962 80.635 ;
     RECT  7.02 80.591 8.154 80.699 ;
     RECT  9.36 80.635 10.962 80.699 ;
     RECT  2.304 80.365 3.69 80.761 ;
     RECT  2.304 80.761 3.726 80.789 ;
     RECT  9.36 80.699 10.818 80.789 ;
     RECT  12.06 80.627 19.134 80.905 ;
     RECT  19.944 80.333 19.998 80.905 ;
     RECT  5.115 79.997 5.397 80.923 ;
     RECT  3.708 80.789 3.726 80.933 ;
     RECT  2.304 80.789 2.697 81.005 ;
     RECT  5.004 80.923 5.397 81.059 ;
     RECT  7.2 80.699 8.154 81.401 ;
     RECT  7.815 81.401 8.154 81.481 ;
     RECT  2.415 81.005 2.697 81.571 ;
     RECT  10.515 80.789 10.818 81.571 ;
     RECT  7.815 81.481 8.55 81.599 ;
     RECT  0.216 81.499 0.234 81.629 ;
     RECT  10.515 81.571 11.178 81.629 ;
     RECT  12.06 80.905 19.998 81.643 ;
     RECT  11.592 81.643 19.998 81.691 ;
     RECT  11.592 81.691 20.538 81.707 ;
     RECT  11.592 81.707 18.897 81.779 ;
     RECT  2.415 81.571 3.294 81.832 ;
     RECT  5.115 81.059 5.397 81.841 ;
     RECT  6.624 81.751 6.642 81.869 ;
     RECT  2.304 81.832 3.294 81.931 ;
     RECT  2.016 81.931 4.014 82.021 ;
     RECT  5.004 81.841 5.397 82.021 ;
     RECT  7.815 81.599 8.478 82.049 ;
     RECT  2.016 82.021 5.397 82.061 ;
     RECT  9.756 82.111 9.774 82.171 ;
     RECT  9.684 82.171 9.774 82.219 ;
     RECT  9.468 82.219 9.774 82.319 ;
     RECT  19.944 81.707 20.538 82.48 ;
     RECT  0.252 82.363 0.27 82.493 ;
     RECT  11.628 81.779 18.897 82.517 ;
     RECT  7.815 82.049 8.097 82.651 ;
     RECT  12.06 82.517 18.897 82.699 ;
     RECT  19.908 82.48 20.538 82.699 ;
     RECT  10.515 81.629 10.797 82.747 ;
     RECT  2.415 82.061 5.397 82.795 ;
     RECT  2.415 82.795 5.814 82.831 ;
     RECT  6.912 82.651 8.097 82.831 ;
     RECT  0.288 82.747 0.306 82.877 ;
     RECT  6.912 82.831 8.406 82.987 ;
     RECT  9.936 82.747 10.797 82.987 ;
     RECT  6.84 82.987 8.406 83.035 ;
     RECT  6.84 83.035 8.586 83.065 ;
     RECT  2.415 82.831 5.958 83.093 ;
     RECT  2.415 83.093 5.814 83.101 ;
     RECT  2.304 83.101 5.814 83.219 ;
     RECT  6.768 83.065 8.586 83.219 ;
     RECT  12.06 82.699 20.538 83.291 ;
     RECT  12.492 83.291 20.538 83.371 ;
     RECT  0.216 83.371 0.234 83.408 ;
     RECT  6.876 83.219 8.586 83.461 ;
     RECT  9.936 82.987 10.854 83.461 ;
     RECT  6.876 83.461 10.854 83.549 ;
     RECT  2.304 83.219 5.598 83.597 ;
     RECT  12.492 83.371 20.61 83.741 ;
     RECT  6.876 83.549 8.658 83.759 ;
     RECT  12.492 83.741 19.962 83.759 ;
     RECT  9.648 83.549 10.854 83.795 ;
     RECT  12.492 83.759 19.098 83.795 ;
     RECT  9.756 83.795 10.854 83.839 ;
     RECT  4.752 83.597 5.598 84.029 ;
     RECT  12.492 83.795 18.99 84.109 ;
     RECT  6.876 83.759 8.097 84.139 ;
     RECT  12.06 84.109 18.99 84.173 ;
     RECT  2.304 83.597 3.87 84.299 ;
     RECT  6.84 84.139 8.097 84.317 ;
     RECT  9.756 83.839 11.214 84.371 ;
     RECT  0.54 83.731 0.558 84.413 ;
     RECT  4.788 84.029 5.397 84.569 ;
     RECT  10.515 84.371 11.214 84.721 ;
     RECT  0.252 84.619 0.27 84.749 ;
     RECT  2.34 84.299 3.87 84.839 ;
     RECT  12.096 84.173 18.99 84.883 ;
     RECT  7.092 84.317 8.097 84.955 ;
     RECT  10.515 84.721 11.358 84.991 ;
     RECT  12.096 84.883 19.026 84.991 ;
     RECT  7.092 84.955 8.478 85.019 ;
     RECT  9.288 84.811 9.702 85.019 ;
     RECT  7.776 85.019 8.478 85.081 ;
     RECT  7.776 85.081 9.018 85.109 ;
     RECT  10.515 84.991 19.026 85.109 ;
     RECT  4.824 84.569 5.397 85.189 ;
     RECT  10.515 85.109 10.89 85.225 ;
     RECT  2.34 84.839 2.862 85.243 ;
     RECT  19.944 83.759 19.962 85.243 ;
     RECT  2.304 85.243 2.862 85.277 ;
     RECT  9.9 85.225 10.89 85.277 ;
     RECT  2.304 85.277 2.79 85.289 ;
     RECT  12.096 85.109 19.026 85.351 ;
     RECT  19.944 85.243 19.998 85.351 ;
     RECT  4.824 85.189 5.814 85.379 ;
     RECT  7.815 85.109 9.018 85.421 ;
     RECT  12.096 85.351 19.998 85.469 ;
     RECT  8.928 85.421 9.018 85.487 ;
     RECT  9.9 85.277 10.854 85.487 ;
     RECT  0.216 85.051 0.234 85.613 ;
     RECT  4.824 85.379 5.49 85.661 ;
     RECT  8.928 85.487 8.946 85.721 ;
     RECT  4.824 85.661 5.397 85.801 ;
     RECT  4.788 85.801 5.397 85.919 ;
     RECT  6.84 85.147 6.858 86.027 ;
     RECT  9.9 85.487 10.797 86.035 ;
     RECT  2.415 85.289 2.79 86.059 ;
     RECT  3.888 85.963 3.906 86.189 ;
     RECT  9.864 86.035 10.797 86.189 ;
     RECT  6.876 86.161 7.074 86.269 ;
     RECT  7.815 85.421 8.097 86.269 ;
     RECT  12.096 85.469 19.098 86.269 ;
     RECT  19.944 85.469 19.998 86.269 ;
     RECT  0.54 85.999 0.558 86.285 ;
     RECT  6.876 86.269 8.097 86.305 ;
     RECT  10.515 86.189 10.797 86.341 ;
     RECT  12.096 86.269 19.998 86.341 ;
     RECT  6.876 86.305 8.154 86.369 ;
     RECT  9.756 86.197 9.774 86.369 ;
     RECT  2.415 86.059 2.862 86.431 ;
     RECT  6.876 86.369 7.074 86.459 ;
     RECT  10.515 86.341 19.998 86.459 ;
     RECT  3.6 86.341 3.618 86.531 ;
     RECT  19.944 86.459 19.998 86.603 ;
     RECT  5.004 85.919 5.397 86.611 ;
     RECT  6.876 86.459 6.93 86.639 ;
     RECT  10.515 86.459 19.098 86.639 ;
     RECT  2.304 86.431 2.862 86.701 ;
     RECT  7.815 86.369 8.154 86.701 ;
     RECT  7.815 86.701 8.694 86.773 ;
     RECT  6.876 86.639 6.894 86.779 ;
     RECT  2.304 86.701 3.438 86.801 ;
     RECT  7.815 86.773 8.838 86.809 ;
     RECT  7.815 86.809 9.594 86.813 ;
     RECT  5.004 86.611 5.958 86.845 ;
     RECT  6.84 86.779 6.894 86.845 ;
     RECT  5.004 86.845 6.894 86.909 ;
     RECT  8.82 86.813 9.594 86.909 ;
     RECT  5.004 86.909 6.318 86.999 ;
     RECT  8.82 86.909 8.838 86.999 ;
     RECT  9.576 86.909 9.594 86.999 ;
     RECT  11.952 86.639 19.098 86.999 ;
     RECT  7.815 86.813 8.097 87.241 ;
     RECT  10.515 86.639 10.818 87.241 ;
     RECT  4.176 87.241 4.194 87.341 ;
     RECT  11.952 86.999 19.026 87.511 ;
     RECT  2.304 86.801 3.294 87.539 ;
     RECT  7.704 87.241 8.097 87.575 ;
     RECT  0.252 87.451 0.27 87.581 ;
     RECT  19.944 86.603 19.962 87.583 ;
     RECT  5.004 86.999 6.138 87.611 ;
     RECT  10.404 87.241 10.818 87.629 ;
     RECT  11.808 87.511 19.026 87.647 ;
     RECT  6.12 87.611 6.138 87.719 ;
     RECT  10.512 87.629 10.818 87.719 ;
     RECT  12.06 87.647 19.026 87.781 ;
     RECT  7.776 87.575 8.097 87.809 ;
     RECT  19.944 87.583 19.998 87.931 ;
     RECT  12.06 87.781 19.098 88.051 ;
     RECT  19.944 87.931 20.034 88.051 ;
     RECT  6.84 88.051 6.858 88.075 ;
     RECT  4.032 87.925 4.05 88.087 ;
     RECT  7.815 87.809 8.097 88.123 ;
     RECT  6.84 88.075 6.93 88.157 ;
     RECT  3.78 88.087 4.05 88.159 ;
     RECT  5.004 87.611 5.397 88.159 ;
     RECT  9.432 88.051 9.45 88.195 ;
     RECT  12.06 88.051 20.034 88.223 ;
     RECT  6.876 88.157 6.93 88.259 ;
     RECT  3.78 88.159 5.397 88.349 ;
     RECT  6.912 88.259 6.93 88.349 ;
     RECT  7.815 88.123 8.658 88.349 ;
     RECT  9.432 88.195 9.558 88.465 ;
     RECT  2.304 87.539 2.862 88.591 ;
     RECT  3.78 88.349 4.086 88.591 ;
     RECT  2.268 88.591 4.086 88.619 ;
     RECT  9.108 88.465 9.558 88.619 ;
     RECT  10.515 87.719 10.818 88.627 ;
     RECT  9.324 88.619 9.558 88.699 ;
     RECT  10.515 88.627 10.926 88.699 ;
     RECT  9.324 88.699 11.178 88.735 ;
     RECT  12.06 88.223 19.998 88.735 ;
     RECT  0.54 88.771 0.558 88.795 ;
     RECT  2.268 88.619 3.798 88.889 ;
     RECT  9.324 88.735 19.998 88.889 ;
     RECT  0.216 88.795 0.558 88.925 ;
     RECT  9.324 88.889 10.926 88.925 ;
     RECT  5.115 88.349 5.397 89.203 ;
     RECT  2.268 88.889 3.366 89.231 ;
     RECT  4.86 89.203 5.397 89.311 ;
     RECT  2.268 89.231 3.15 89.339 ;
     RECT  7.815 88.349 8.097 89.401 ;
     RECT  4.86 89.311 5.562 89.429 ;
     RECT  7.815 89.401 8.154 89.437 ;
     RECT  11.952 88.889 19.998 89.473 ;
     RECT  6.84 89.401 6.858 89.5 ;
     RECT  4.86 89.429 5.418 89.609 ;
     RECT  6.84 89.5 6.894 89.609 ;
     RECT  7.815 89.437 9.162 89.699 ;
     RECT  10.515 88.925 10.926 89.707 ;
     RECT  10.515 89.707 10.962 89.743 ;
     RECT  11.952 89.473 20.538 89.815 ;
     RECT  6.372 89.779 6.39 89.851 ;
     RECT  10.515 89.743 11.034 89.941 ;
     RECT  6.3 89.851 6.39 89.969 ;
     RECT  4.86 89.609 5.397 89.977 ;
     RECT  9.972 89.941 11.034 90.013 ;
     RECT  2.304 89.339 3.15 90.041 ;
     RECT  7.815 89.699 8.802 90.041 ;
     RECT  2.304 90.041 3.006 90.149 ;
     RECT  4.32 89.977 5.397 90.149 ;
     RECT  9.9 90.013 11.034 90.149 ;
     RECT  0.54 88.925 0.558 90.173 ;
     RECT  10.515 90.149 11.034 90.211 ;
     RECT  11.844 89.815 20.538 90.211 ;
     RECT  10.515 90.211 20.538 90.311 ;
     RECT  10.515 90.311 11.286 90.419 ;
     RECT  4.464 90.149 5.397 90.661 ;
     RECT  2.304 90.149 2.697 90.779 ;
     RECT  4.464 90.661 5.706 90.779 ;
     RECT  7.815 90.041 8.37 90.779 ;
     RECT  6.948 90.751 7.038 90.851 ;
     RECT  2.412 90.779 2.697 90.895 ;
     RECT  6.948 90.851 6.966 90.923 ;
     RECT  10.515 90.419 10.962 90.959 ;
     RECT  2.412 90.895 3.366 91.021 ;
     RECT  9.18 90.907 9.198 91.021 ;
     RECT  0.216 90.472 0.234 91.037 ;
     RECT  9.18 91.021 9.522 91.049 ;
     RECT  2.412 91.021 4.05 91.133 ;
     RECT  2.412 91.133 3.078 91.157 ;
     RECT  9.432 91.049 9.522 91.157 ;
     RECT  2.412 91.157 2.826 91.181 ;
     RECT  10.515 90.959 10.854 91.181 ;
     RECT  4.032 91.133 4.05 91.193 ;
     RECT  9.504 91.157 9.522 91.193 ;
     RECT  0.288 91.051 0.306 91.373 ;
     RECT  12.06 90.311 20.538 91.427 ;
     RECT  4.932 90.779 5.706 91.499 ;
     RECT  4.932 91.499 5.397 91.561 ;
     RECT  9.576 91.561 9.594 91.661 ;
     RECT  7.815 90.779 8.097 91.705 ;
     RECT  4.212 91.561 5.397 91.859 ;
     RECT  7.815 91.705 8.586 91.859 ;
     RECT  2.415 91.181 2.826 91.901 ;
     RECT  3.42 91.903 3.438 92.039 ;
     RECT  0.252 91.915 0.27 92.045 ;
     RECT  12.06 91.427 18.897 92.101 ;
     RECT  2.415 91.901 2.697 92.281 ;
     RECT  12.024 92.101 18.897 92.281 ;
     RECT  9.468 92.011 9.486 92.309 ;
     RECT  6.84 91.471 6.858 92.371 ;
     RECT  7.815 91.859 8.154 92.371 ;
     RECT  10.515 91.181 10.797 92.371 ;
     RECT  2.304 92.281 2.697 92.381 ;
     RECT  6.84 92.371 8.154 92.399 ;
     RECT  6.84 92.399 8.097 92.407 ;
     RECT  12.024 92.281 19.098 92.435 ;
     RECT  10.224 92.371 10.797 92.471 ;
     RECT  4.428 91.859 5.397 92.515 ;
     RECT  6.408 92.407 8.097 92.515 ;
     RECT  4.428 92.515 8.097 92.543 ;
     RECT  12.024 92.435 19.026 92.551 ;
     RECT  4.428 92.543 7.002 92.579 ;
     RECT  2.415 92.381 2.697 92.683 ;
     RECT  10.515 92.471 10.797 92.713 ;
     RECT  11.952 92.551 19.026 92.777 ;
     RECT  4.428 92.579 6.858 92.779 ;
     RECT  0.216 92.779 0.234 92.909 ;
     RECT  9.252 92.551 9.27 92.911 ;
     RECT  2.415 92.683 2.934 92.939 ;
     RECT  8.892 92.911 9.27 93.053 ;
     RECT  10.515 92.713 10.854 93.091 ;
     RECT  3.996 92.779 6.858 93.119 ;
     RECT  9.036 93.053 9.27 93.209 ;
     RECT  4.536 93.119 5.397 93.245 ;
     RECT  10.515 93.091 10.926 93.253 ;
     RECT  10.515 93.253 10.962 93.259 ;
     RECT  4.824 93.245 5.397 93.281 ;
     RECT  2.415 92.939 2.79 93.352 ;
     RECT  5.004 93.281 5.397 93.389 ;
     RECT  6.228 93.119 6.858 93.451 ;
     RECT  6.228 93.451 6.894 93.488 ;
     RECT  9.648 93.451 9.666 93.523 ;
     RECT  10.515 93.259 11.25 93.523 ;
     RECT  12.06 92.777 19.026 93.523 ;
     RECT  19.944 91.427 20.538 93.523 ;
     RECT  9.648 93.523 11.25 93.551 ;
     RECT  9.756 93.551 11.25 93.559 ;
     RECT  12.06 93.523 20.538 93.559 ;
     RECT  0.54 93.451 0.558 93.581 ;
     RECT  2.304 93.352 2.79 93.721 ;
     RECT  9.756 93.559 20.538 93.749 ;
     RECT  6.228 93.488 6.246 93.821 ;
     RECT  2.304 93.721 2.97 93.893 ;
     RECT  7.815 92.543 8.097 93.901 ;
     RECT  2.304 93.893 2.826 93.917 ;
     RECT  7.632 93.901 8.097 94.019 ;
     RECT  5.04 93.389 5.397 94.171 ;
     RECT  12.096 93.749 20.538 94.253 ;
     RECT  7.815 94.019 8.097 94.261 ;
     RECT  7.815 94.261 8.37 94.405 ;
     RECT  12.096 94.253 20.034 94.469 ;
     RECT  5.04 94.171 6.174 94.559 ;
     RECT  7.815 94.405 8.802 94.559 ;
     RECT  5.04 94.559 5.67 94.567 ;
     RECT  12.096 94.469 19.998 94.703 ;
     RECT  2.415 93.917 2.826 94.747 ;
     RECT  10.515 93.749 10.854 94.801 ;
     RECT  4.32 94.567 5.67 94.829 ;
     RECT  12.096 94.703 19.026 94.873 ;
     RECT  6.804 94.873 6.822 94.909 ;
     RECT  7.815 94.559 8.097 94.909 ;
     RECT  4.5 94.829 5.67 94.937 ;
     RECT  10.515 94.801 10.89 94.939 ;
     RECT  2.304 94.747 2.826 94.945 ;
     RECT  9.972 94.939 10.89 94.945 ;
     RECT  9.972 94.945 11.106 94.981 ;
     RECT  12.024 94.873 19.026 94.981 ;
     RECT  4.5 94.937 5.598 95.009 ;
     RECT  2.304 94.945 3.402 95.071 ;
     RECT  9.972 94.981 19.026 95.099 ;
     RECT  2.304 95.071 3.474 95.171 ;
     RECT  4.5 95.009 5.397 95.369 ;
     RECT  19.944 94.703 19.998 95.449 ;
     RECT  6.804 94.909 8.097 95.485 ;
     RECT  12.06 95.099 19.026 95.485 ;
     RECT  19.944 95.449 20.538 95.485 ;
     RECT  2.304 95.171 2.898 95.549 ;
     RECT  6.804 95.485 8.694 95.549 ;
     RECT  7.815 95.549 8.694 95.639 ;
     RECT  12.06 95.485 20.538 95.789 ;
     RECT  7.815 95.639 8.586 95.909 ;
     RECT  10.515 95.099 10.926 95.953 ;
     RECT  3.888 95.755 3.906 95.989 ;
     RECT  3.744 95.989 3.906 96.025 ;
     RECT  9.432 95.881 9.45 96.053 ;
     RECT  6.66 95.791 6.678 96.179 ;
     RECT  10.515 95.953 11.106 96.179 ;
     RECT  3.6 96.025 3.906 96.235 ;
     RECT  10.515 96.179 10.797 96.295 ;
     RECT  0.54 95.683 0.558 96.461 ;
     RECT  12.06 95.789 20.034 96.509 ;
     RECT  3.6 96.235 4.05 96.557 ;
     RECT  12.06 96.509 19.062 96.601 ;
     RECT  9.972 96.295 10.797 96.629 ;
     RECT  4.932 95.369 5.397 96.691 ;
     RECT  2.304 95.549 2.826 96.719 ;
     RECT  3.6 96.557 3.798 96.719 ;
     RECT  2.34 96.719 2.826 96.727 ;
     RECT  6.552 96.565 6.606 96.763 ;
     RECT  19.944 96.509 20.034 96.797 ;
     RECT  7.815 95.909 8.097 96.835 ;
     RECT  11.52 96.601 19.062 96.863 ;
     RECT  19.98 96.797 20.034 96.863 ;
     RECT  6.12 96.763 6.606 96.899 ;
     RECT  0.216 96.859 0.306 96.989 ;
     RECT  2.34 96.727 3.546 96.989 ;
     RECT  12.024 96.863 19.062 96.989 ;
     RECT  10.224 96.629 10.797 97.033 ;
     RECT  4.536 96.691 5.397 97.037 ;
     RECT  0.288 96.989 0.306 97.229 ;
     RECT  5.115 97.037 5.397 97.267 ;
     RECT  12.024 96.989 12.186 97.295 ;
     RECT  10.224 97.033 10.998 97.367 ;
     RECT  2.415 96.989 3.546 97.439 ;
     RECT  2.415 97.439 2.79 97.469 ;
     RECT  9.324 97.099 9.342 97.501 ;
     RECT  3.528 97.439 3.546 97.565 ;
     RECT  7.815 96.835 8.154 97.627 ;
     RECT  8.928 97.501 9.342 97.627 ;
     RECT  5.115 97.267 5.526 97.681 ;
     RECT  7.815 97.627 9.342 97.709 ;
     RECT  2.415 97.469 2.754 97.771 ;
     RECT  5.115 97.681 6.21 97.771 ;
     RECT  20.52 97.105 20.574 97.805 ;
     RECT  5.004 97.771 6.894 97.901 ;
     RECT  3.852 97.879 3.87 97.915 ;
     RECT  5.004 97.901 6.858 97.915 ;
     RECT  3.852 97.915 6.858 97.943 ;
     RECT  9 97.709 9.342 97.943 ;
     RECT  3.852 97.943 6.498 97.979 ;
     RECT  0.216 97.951 0.234 97.997 ;
     RECT  12.096 97.295 12.186 98.041 ;
     RECT  12.924 96.989 19.062 98.041 ;
     RECT  4.284 97.979 6.498 98.069 ;
     RECT  7.815 97.709 8.097 98.113 ;
     RECT  12.096 98.041 19.062 98.113 ;
     RECT  2.304 97.771 2.754 98.221 ;
     RECT  4.716 98.069 6.498 98.249 ;
     RECT  10.224 97.367 10.926 98.249 ;
     RECT  2.304 98.221 2.862 98.333 ;
     RECT  6.48 98.249 6.498 98.339 ;
     RECT  12.096 98.113 19.242 98.383 ;
     RECT  7.596 98.113 8.097 98.443 ;
     RECT  9 97.943 9.018 98.443 ;
     RECT  12.06 98.383 19.242 98.443 ;
     RECT  20.52 97.805 20.538 98.443 ;
     RECT  0.504 98.221 0.522 98.581 ;
     RECT  7.596 98.443 9.018 98.609 ;
     RECT  10.224 98.249 10.854 98.609 ;
     RECT  0.504 98.581 0.558 98.669 ;
     RECT  2.415 98.333 2.862 98.725 ;
     RECT  7.596 98.609 8.097 98.761 ;
     RECT  0.504 98.669 0.522 98.813 ;
     RECT  2.415 98.725 3.33 98.879 ;
     RECT  9.216 98.689 9.234 98.879 ;
     RECT  10.332 98.609 10.797 98.879 ;
     RECT  4.716 98.249 5.397 98.971 ;
     RECT  12.06 98.443 20.538 99.005 ;
     RECT  4.716 98.971 5.634 99.031 ;
     RECT  4.716 99.031 6.102 99.121 ;
     RECT  3.96 99.121 6.246 99.149 ;
     RECT  6.228 99.149 6.246 99.293 ;
     RECT  3.96 99.149 5.49 99.329 ;
     RECT  0.216 99.229 0.234 99.341 ;
     RECT  3.996 99.329 5.49 99.419 ;
     RECT  7.164 98.761 8.097 99.499 ;
     RECT  7.164 99.499 8.154 99.563 ;
     RECT  10.515 98.879 10.797 99.769 ;
     RECT  2.415 98.879 2.697 99.832 ;
     RECT  12.06 99.005 19.314 99.835 ;
     RECT  20.52 99.005 20.538 99.835 ;
     RECT  2.304 99.832 2.697 99.869 ;
     RECT  7.596 99.563 8.154 99.931 ;
     RECT  9.576 99.769 9.594 99.931 ;
     RECT  10.515 99.769 10.854 99.931 ;
     RECT  12.06 99.835 20.538 99.931 ;
     RECT  6.84 99.835 6.858 100.013 ;
     RECT  7.596 99.931 9.594 100.061 ;
     RECT  10.515 99.931 10.926 100.061 ;
     RECT  7.815 100.061 9.594 100.067 ;
     RECT  9.252 100.067 9.594 100.103 ;
     RECT  10.515 100.061 10.854 100.103 ;
     RECT  2.415 99.869 2.697 100.171 ;
     RECT  9.324 100.103 9.594 100.201 ;
     RECT  2.415 100.171 2.79 100.273 ;
     RECT  3.996 99.419 5.397 100.273 ;
     RECT  9.324 100.201 9.774 100.301 ;
     RECT  9.324 100.301 9.522 100.541 ;
     RECT  2.415 100.273 5.397 100.571 ;
     RECT  2.415 100.571 2.898 100.651 ;
     RECT  10.515 100.103 10.797 100.651 ;
     RECT  11.88 99.931 20.538 100.651 ;
     RECT  2.304 100.651 2.898 100.688 ;
     RECT  6.66 100.381 6.678 100.741 ;
     RECT  9.504 100.541 9.522 100.769 ;
     RECT  3.708 100.571 5.397 100.841 ;
     RECT  7.815 100.067 8.154 100.849 ;
     RECT  10.26 100.651 10.797 100.877 ;
     RECT  11.808 100.651 20.538 100.877 ;
     RECT  7.815 100.849 8.586 100.885 ;
     RECT  10.515 100.877 10.797 100.885 ;
     RECT  0.216 100.843 0.234 100.891 ;
     RECT  0.216 100.891 0.306 100.913 ;
     RECT  0.288 100.913 0.306 101.021 ;
     RECT  5.076 100.841 5.397 101.039 ;
     RECT  7.815 100.885 8.658 101.219 ;
     RECT  6.66 100.741 7.038 101.309 ;
     RECT  12.06 100.877 20.538 101.357 ;
     RECT  7.815 101.219 8.154 101.551 ;
     RECT  12.06 101.357 19.998 101.615 ;
     RECT  9.036 101.551 9.234 101.659 ;
     RECT  10.515 100.885 10.854 101.731 ;
     RECT  7.38 101.551 8.154 101.759 ;
     RECT  2.415 100.688 2.898 101.821 ;
     RECT  3.708 100.841 4.014 101.821 ;
     RECT  9.036 101.659 9.378 101.849 ;
     RECT  12.06 101.615 18.954 101.849 ;
     RECT  9.144 101.849 9.234 101.885 ;
     RECT  19.944 101.615 19.998 101.885 ;
     RECT  14.292 101.849 18.954 101.933 ;
     RECT  10.515 101.731 10.926 101.957 ;
     RECT  2.415 101.821 4.014 101.965 ;
     RECT  2.415 101.965 4.05 102.029 ;
     RECT  14.292 101.933 16.29 102.029 ;
     RECT  0.54 101.191 0.558 102.077 ;
     RECT  4.032 102.029 4.05 102.119 ;
     RECT  2.415 102.029 2.862 102.523 ;
     RECT  7.815 101.759 8.154 102.631 ;
     RECT  17.028 101.933 18.954 102.631 ;
     RECT  19.944 101.885 19.962 102.631 ;
     RECT  12.06 101.849 13.518 102.667 ;
     RECT  17.028 102.631 19.962 102.701 ;
     RECT  6.84 102.361 6.858 102.703 ;
     RECT  5.115 101.039 5.397 102.739 ;
     RECT  6.804 102.703 6.858 102.739 ;
     RECT  7.815 102.631 8.262 102.739 ;
     RECT  14.508 102.029 16.29 102.739 ;
     RECT  17.028 102.701 19.098 102.739 ;
     RECT  2.304 102.523 2.862 102.775 ;
     RECT  10.515 101.957 10.89 102.811 ;
     RECT  12.06 102.667 13.698 102.811 ;
     RECT  14.508 102.739 19.098 102.811 ;
     RECT  2.304 102.775 3.51 102.901 ;
     RECT  6.804 102.739 6.93 102.901 ;
     RECT  7.815 102.739 8.334 102.901 ;
     RECT  9.144 101.885 9.162 102.901 ;
     RECT  7.815 102.901 9.162 102.937 ;
     RECT  7.815 102.937 9.702 103.001 ;
     RECT  6.516 102.901 6.93 103.037 ;
     RECT  6.624 103.037 6.93 103.081 ;
     RECT  7.815 103.001 8.694 103.081 ;
     RECT  6.624 103.081 8.694 103.109 ;
     RECT  9.504 103.001 9.702 103.109 ;
     RECT  9.684 103.109 9.702 103.199 ;
     RECT  19.944 102.701 19.962 103.387 ;
     RECT  2.304 102.901 4.05 103.421 ;
     RECT  2.415 103.421 4.05 103.441 ;
     RECT  5.04 102.739 5.397 103.441 ;
     RECT  10.515 102.811 10.926 103.441 ;
     RECT  2.415 103.441 5.397 103.469 ;
     RECT  12.06 102.811 19.098 103.579 ;
     RECT  19.944 103.387 20.538 103.579 ;
     RECT  0.54 103.045 0.558 103.585 ;
     RECT  9.756 103.441 10.926 103.613 ;
     RECT  12.06 103.579 20.538 103.621 ;
     RECT  2.415 103.469 2.934 103.739 ;
     RECT  4.14 103.469 5.397 103.739 ;
     RECT  0.504 103.585 0.558 103.757 ;
     RECT  6.84 103.109 8.097 103.855 ;
     RECT  11.7 103.621 20.538 103.919 ;
     RECT  0.504 103.757 0.522 103.949 ;
     RECT  6.84 103.855 8.514 104.009 ;
     RECT  6.84 104.009 8.097 104.089 ;
     RECT  6.444 104.089 8.097 104.161 ;
     RECT  4.356 103.739 5.397 104.189 ;
     RECT  6.336 104.161 8.097 104.189 ;
     RECT  12.096 103.919 20.538 104.189 ;
     RECT  2.415 103.739 2.697 104.251 ;
     RECT  6.336 104.189 6.462 104.279 ;
     RECT  9.756 103.613 10.89 104.287 ;
     RECT  7.38 104.189 8.097 104.429 ;
     RECT  9.144 104.287 10.89 104.431 ;
     RECT  2.304 104.251 2.697 104.521 ;
     RECT  9.144 104.431 10.926 104.621 ;
     RECT  10.404 104.621 10.926 104.657 ;
     RECT  9.144 104.621 9.27 104.729 ;
     RECT  2.304 104.521 3.33 104.765 ;
     RECT  4.428 104.189 5.397 104.819 ;
     RECT  0.54 104.863 0.558 104.957 ;
     RECT  7.704 104.429 8.097 104.971 ;
     RECT  4.5 104.819 5.397 105.169 ;
     RECT  6.408 105.061 6.426 105.233 ;
     RECT  2.415 104.765 3.33 105.241 ;
     RECT  4.5 105.169 5.598 105.269 ;
     RECT  7.704 104.971 8.406 105.269 ;
     RECT  0.216 105.163 0.234 105.293 ;
     RECT  9.252 104.729 9.27 105.511 ;
     RECT  7.815 105.269 8.406 105.601 ;
     RECT  9.252 105.511 9.342 105.601 ;
     RECT  2.415 105.241 3.366 105.629 ;
     RECT  4.5 105.269 5.397 105.629 ;
     RECT  10.404 104.657 10.797 105.637 ;
     RECT  10.404 105.637 11.106 105.709 ;
     RECT  7.815 105.601 9.342 105.781 ;
     RECT  10.224 105.709 11.106 105.809 ;
     RECT  10.515 105.809 11.106 105.871 ;
     RECT  12.096 104.189 19.962 105.871 ;
     RECT  10.515 105.871 19.962 105.931 ;
     RECT  10.515 105.931 19.998 105.965 ;
     RECT  11.52 105.965 19.998 105.971 ;
     RECT  3.42 105.907 3.438 106.169 ;
     RECT  11.88 105.971 19.998 106.241 ;
     RECT  7.815 105.781 9.414 106.411 ;
     RECT  11.88 106.241 19.962 106.439 ;
     RECT  7.815 106.411 9.666 106.583 ;
     RECT  14.472 106.439 19.962 106.817 ;
     RECT  4.248 106.051 4.266 106.825 ;
     RECT  5.115 105.629 5.397 106.825 ;
     RECT  9.468 106.583 9.666 106.889 ;
     RECT  0.54 105.871 0.558 106.939 ;
     RECT  4.248 106.825 5.397 106.979 ;
     RECT  6.84 106.987 6.858 107.087 ;
     RECT  7.815 106.583 8.73 107.159 ;
     RECT  12.06 106.439 13.662 107.179 ;
     RECT  12.06 107.179 13.698 107.227 ;
     RECT  14.472 106.817 19.098 107.227 ;
     RECT  9.684 107.095 9.702 107.249 ;
     RECT  0.252 106.939 0.558 107.309 ;
     RECT  6.66 107.221 6.678 107.321 ;
     RECT  7.815 107.159 8.622 107.401 ;
     RECT  10.515 105.965 10.797 107.401 ;
     RECT  4.536 106.979 5.397 107.429 ;
     RECT  10.515 107.401 11.286 107.491 ;
     RECT  12.06 107.227 19.098 107.491 ;
     RECT  7.524 107.401 8.622 107.519 ;
     RECT  2.415 105.629 2.697 107.563 ;
     RECT  0.252 107.309 0.27 107.597 ;
     RECT  19.944 106.817 19.962 107.611 ;
     RECT  10.515 107.491 19.098 107.635 ;
     RECT  19.944 107.611 19.998 107.635 ;
     RECT  2.415 107.563 3.366 107.761 ;
     RECT  10.515 107.635 19.998 107.861 ;
     RECT  10.515 107.861 19.242 108.125 ;
     RECT  19.98 107.861 19.998 108.131 ;
     RECT  2.415 107.761 3.546 108.175 ;
     RECT  11.808 108.125 19.242 108.203 ;
     RECT  2.415 108.175 3.618 108.301 ;
     RECT  5.115 107.429 5.397 108.301 ;
     RECT  2.415 108.301 3.69 108.401 ;
     RECT  5.115 108.301 6.102 108.445 ;
     RECT  2.415 108.401 3.33 108.472 ;
     RECT  5.115 108.445 6.21 108.475 ;
     RECT  5.004 108.475 6.21 108.571 ;
     RECT  7.815 107.519 8.622 108.571 ;
     RECT  9.468 108.301 9.486 108.571 ;
     RECT  10.515 108.125 10.797 108.571 ;
     RECT  11.916 108.203 19.242 108.619 ;
     RECT  5.004 108.571 6.642 108.635 ;
     RECT  5.004 108.635 5.706 108.679 ;
     RECT  7.815 108.571 10.797 108.707 ;
     RECT  6.624 108.635 6.642 108.743 ;
     RECT  9.792 108.707 10.797 108.743 ;
     RECT  7.815 108.707 8.658 108.751 ;
     RECT  2.304 108.472 3.33 108.869 ;
     RECT  4.464 108.679 5.706 108.869 ;
     RECT  7.74 108.751 8.658 108.869 ;
     RECT  11.916 108.619 19.962 108.869 ;
     RECT  0.216 108.715 0.234 109.037 ;
     RECT  10.404 108.743 10.797 109.111 ;
     RECT  11.916 108.869 19.206 109.111 ;
     RECT  2.415 108.869 3.33 109.147 ;
     RECT  19.944 108.869 19.962 109.147 ;
     RECT  5.115 108.869 5.706 109.181 ;
     RECT  0.504 109.147 0.522 109.219 ;
     RECT  10.404 109.111 19.206 109.283 ;
     RECT  2.415 109.147 3.546 109.381 ;
     RECT  7.815 108.869 8.658 109.409 ;
     RECT  11.844 109.283 19.206 109.409 ;
     RECT  18.576 109.409 19.206 109.445 ;
     RECT  2.415 109.381 3.618 109.481 ;
     RECT  5.115 109.181 5.418 109.679 ;
     RECT  0.504 109.219 0.558 109.709 ;
     RECT  19.944 109.147 19.998 109.751 ;
     RECT  10.404 109.283 11.106 109.759 ;
     RECT  9.9 109.759 11.106 109.831 ;
     RECT  12.06 109.409 17.838 109.901 ;
     RECT  9.396 109.831 11.106 109.949 ;
     RECT  12.06 109.901 17.658 109.949 ;
     RECT  12.06 109.949 13.662 109.985 ;
     RECT  14.436 109.949 17.658 109.985 ;
     RECT  6.84 109.183 6.93 109.997 ;
     RECT  18.615 109.445 19.206 110.011 ;
     RECT  6.912 109.997 6.93 110.021 ;
     RECT  9.468 109.949 10.797 110.021 ;
     RECT  14.436 109.985 14.562 110.021 ;
     RECT  0.54 109.709 0.558 110.045 ;
     RECT  2.415 109.481 3.078 110.101 ;
     RECT  9.468 110.021 9.738 110.129 ;
     RECT  2.304 110.101 3.078 110.189 ;
     RECT  2.415 110.189 3.078 110.219 ;
     RECT  14.436 110.021 14.454 110.255 ;
     RECT  5.115 109.679 5.397 110.299 ;
     RECT  15.3 109.985 17.658 110.327 ;
     RECT  4.5 110.299 5.397 110.371 ;
     RECT  2.415 110.219 2.97 110.399 ;
     RECT  4.392 110.371 5.397 110.489 ;
     RECT  15.3 110.327 17.622 110.489 ;
     RECT  12.06 109.985 13.554 110.525 ;
     RECT  15.3 110.489 17.478 110.561 ;
     RECT  17.46 110.561 17.478 110.573 ;
     RECT  12.564 110.525 13.554 110.759 ;
     RECT  13.215 110.759 13.554 110.831 ;
     RECT  15.3 110.561 16.614 110.831 ;
     RECT  18.615 110.011 19.458 110.831 ;
     RECT  7.815 109.409 8.586 111.029 ;
     RECT  15.915 110.831 16.614 111.029 ;
     RECT  18.615 110.831 19.242 111.569 ;
     RECT  18.615 111.569 19.098 111.605 ;
     RECT  2.415 110.399 2.697 112.067 ;
     RECT  5.115 110.489 5.397 112.067 ;
     RECT  7.815 111.029 8.097 112.067 ;
     RECT  10.515 110.021 10.797 112.067 ;
     RECT  13.215 110.831 13.497 112.067 ;
     RECT  15.915 111.029 16.197 112.067 ;
     RECT  18.615 111.605 18.897 112.067 ;
     RECT  2.415 112.067 2.505 112.337 ;
     RECT  5.115 112.067 5.205 112.337 ;
     RECT  7.815 112.067 7.905 112.337 ;
     RECT  10.515 112.067 10.605 112.337 ;
     RECT  13.215 112.067 13.305 112.337 ;
     RECT  15.915 112.067 16.005 112.337 ;
     RECT  18.615 112.067 18.705 112.337 ;
    LAYER M4 ;
     RECT  0.156 4.32 2.408 110.184 ;
     RECT  2.408 2.148 2.512 112.332 ;
     RECT  2.512 2.418 2.704 112.062 ;
     RECT  2.704 4.368 2.765 57.96 ;
     RECT  2.765 8.736 2.837 57.96 ;
     RECT  2.837 15.792 2.873 57.96 ;
     RECT  2.873 33.84 4.025 57.96 ;
     RECT  2.704 58.944 4.061 109.992 ;
     RECT  2.765 4.368 5.108 7.752 ;
     RECT  2.837 8.736 5.108 14.712 ;
     RECT  2.873 15.792 5.108 32.856 ;
     RECT  4.025 33.84 5.108 57.864 ;
     RECT  4.061 58.944 5.108 95.784 ;
     RECT  4.061 97.008 5.108 109.992 ;
     RECT  5.108 2.148 5.212 112.332 ;
     RECT  5.212 2.418 5.404 112.062 ;
     RECT  5.404 33.84 5.717 39.288 ;
     RECT  5.404 27.648 5.789 32.856 ;
     RECT  5.404 40.272 5.861 57.864 ;
     RECT  5.861 43.68 6.829 57.864 ;
     RECT  5.404 59.184 6.829 60.552 ;
     RECT  5.789 27.744 6.868 32.856 ;
     RECT  5.404 4.368 7.808 7.752 ;
     RECT  5.404 8.736 7.808 14.52 ;
     RECT  5.404 15.792 7.808 25.032 ;
     RECT  5.404 26.016 7.808 26.664 ;
     RECT  6.868 27.648 7.808 32.856 ;
     RECT  5.717 33.84 7.808 33.864 ;
     RECT  5.717 35.184 7.808 39.288 ;
     RECT  5.861 40.272 7.808 42.6 ;
     RECT  6.829 43.584 7.808 57.864 ;
     RECT  6.829 59.184 7.808 60.648 ;
     RECT  5.404 61.68 7.808 63.912 ;
     RECT  5.404 65.232 7.808 91.944 ;
     RECT  5.404 93.024 7.808 95.784 ;
     RECT  5.404 97.104 7.808 102.456 ;
     RECT  5.404 103.536 7.808 109.992 ;
     RECT  7.808 2.148 7.912 112.332 ;
     RECT  7.912 2.418 8.104 112.062 ;
     RECT  8.104 48.768 8.165 54.888 ;
     RECT  8.104 39.264 8.237 39.288 ;
     RECT  8.165 48.768 8.237 52.2 ;
     RECT  8.104 16.896 8.273 17.496 ;
     RECT  8.104 65.232 8.273 67.656 ;
     RECT  8.104 18.72 8.345 19.848 ;
     RECT  8.104 29.232 8.453 32.04 ;
     RECT  8.104 11.184 8.489 14.52 ;
     RECT  8.104 68.64 8.597 75.192 ;
     RECT  8.104 93.024 8.597 95.784 ;
     RECT  8.104 76.512 8.633 85.416 ;
     RECT  8.104 61.968 8.669 63.912 ;
     RECT  8.104 86.784 8.705 87.624 ;
     RECT  8.273 65.232 8.741 66.024 ;
     RECT  8.237 50.112 8.777 52.2 ;
     RECT  8.633 76.752 8.777 85.416 ;
     RECT  8.104 97.104 8.777 98.472 ;
     RECT  8.104 20.976 8.813 22.344 ;
     RECT  8.104 40.368 8.813 42.6 ;
     RECT  8.104 59.184 8.813 60.648 ;
     RECT  8.777 76.752 8.849 85.176 ;
     RECT  8.597 93.024 8.921 95.448 ;
     RECT  8.165 53.232 9.029 54.888 ;
     RECT  8.104 27.648 9.137 27.672 ;
     RECT  8.104 4.464 9.173 7.752 ;
     RECT  8.813 40.368 9.173 42.024 ;
     RECT  8.104 43.584 9.173 47.688 ;
     RECT  8.597 68.64 9.173 72.216 ;
     RECT  8.849 79.488 9.173 85.176 ;
     RECT  8.104 8.736 9.209 10.104 ;
     RECT  8.741 66 9.209 66.024 ;
     RECT  9.173 6.048 9.245 7.752 ;
     RECT  9.173 43.584 9.245 46.104 ;
     RECT  9.173 80.256 9.245 85.176 ;
     RECT  8.104 101.856 9.245 102.216 ;
     RECT  9.245 6.816 9.281 7.752 ;
     RECT  9.029 54.864 9.317 54.888 ;
     RECT  9.245 84.144 9.317 85.176 ;
     RECT  8.104 88.896 9.353 89.304 ;
     RECT  8.777 97.104 9.353 98.136 ;
     RECT  8.104 99.504 9.353 100.536 ;
     RECT  8.453 29.232 9.425 29.256 ;
     RECT  9.245 45.504 9.425 46.104 ;
     RECT  8.597 73.344 9.425 75.192 ;
     RECT  8.237 48.768 9.461 48.792 ;
     RECT  8.104 56.016 9.461 57.864 ;
     RECT  8.849 76.752 9.461 77.928 ;
     RECT  8.669 61.968 9.497 62.52 ;
     RECT  9.173 40.608 9.533 42.024 ;
     RECT  10.429 48.768 10.501 48.792 ;
     RECT  9.173 4.464 10.508 4.68 ;
     RECT  9.281 7.2 10.508 7.752 ;
     RECT  9.209 8.736 10.508 9.528 ;
     RECT  8.489 11.184 10.508 13.368 ;
     RECT  8.489 14.496 10.508 14.52 ;
     RECT  8.104 15.792 10.508 15.816 ;
     RECT  8.273 16.896 10.508 16.92 ;
     RECT  8.345 18.72 10.508 18.744 ;
     RECT  8.345 19.824 10.508 19.848 ;
     RECT  8.813 21.12 10.508 22.344 ;
     RECT  8.104 23.328 10.508 25.032 ;
     RECT  8.104 26.016 10.508 26.664 ;
     RECT  8.453 30.432 10.508 32.04 ;
     RECT  8.104 33.84 10.508 33.864 ;
     RECT  8.104 35.184 10.508 37.944 ;
     RECT  9.533 41.184 10.508 42.024 ;
     RECT  9.245 43.584 10.508 44.088 ;
     RECT  9.425 46.08 10.508 46.104 ;
     RECT  9.173 47.664 10.508 47.688 ;
     RECT  10.501 48.768 10.508 48.984 ;
     RECT  8.777 50.112 10.508 50.568 ;
     RECT  8.777 51.744 10.508 52.2 ;
     RECT  9.029 53.232 10.508 53.544 ;
     RECT  9.461 56.016 10.508 57.576 ;
     RECT  8.813 59.184 10.508 59.208 ;
     RECT  8.813 60.624 10.508 60.648 ;
     RECT  9.497 61.968 10.508 61.992 ;
     RECT  8.669 63.504 10.508 63.912 ;
     RECT  8.273 67.344 10.508 67.656 ;
     RECT  9.173 68.64 10.508 68.664 ;
     RECT  9.173 69.984 10.508 70.68 ;
     RECT  9.173 72 10.508 72.216 ;
     RECT  9.425 73.344 10.508 73.368 ;
     RECT  9.425 74.928 10.508 75.192 ;
     RECT  9.461 77.328 10.508 77.928 ;
     RECT  9.245 80.256 10.508 83.064 ;
     RECT  9.317 84.144 10.508 84.168 ;
     RECT  9.317 85.152 10.508 85.176 ;
     RECT  8.705 87.6 10.508 87.624 ;
     RECT  9.353 89.28 10.508 89.304 ;
     RECT  8.104 90.336 10.508 91.944 ;
     RECT  8.921 93.264 10.508 95.448 ;
     RECT  9.353 97.392 10.508 98.136 ;
     RECT  9.353 99.504 10.508 100.248 ;
     RECT  9.245 102.192 10.508 102.216 ;
     RECT  8.104 103.536 10.508 104.616 ;
     RECT  8.104 105.696 10.508 109.272 ;
     RECT  10.508 2.148 10.612 112.332 ;
     RECT  10.612 2.418 10.804 112.062 ;
     RECT  10.804 41.184 10.829 41.688 ;
     RECT  10.804 26.016 10.865 26.664 ;
     RECT  10.804 82.944 10.865 83.112 ;
     RECT  10.789 0.192 10.901 0.216 ;
     RECT  10.804 19.824 10.901 19.944 ;
     RECT  10.804 73.344 10.901 73.368 ;
     RECT  10.804 85.152 10.901 85.272 ;
     RECT  10.804 103.536 10.901 104.184 ;
     RECT  10.804 15.792 11.009 16.392 ;
     RECT  10.804 29.376 11.009 30.936 ;
     RECT  10.804 46.08 11.081 46.104 ;
     RECT  10.804 47.328 11.123 50.568 ;
     RECT  10.804 81.168 11.189 81.624 ;
     RECT  10.804 93.264 11.261 94.104 ;
     RECT  10.804 4.464 11.297 4.488 ;
     RECT  11.189 81.168 11.905 81.192 ;
     RECT  10.804 23.328 11.941 23.688 ;
     RECT  10.804 24.672 11.941 24.696 ;
     RECT  10.804 89.28 11.941 89.304 ;
     RECT  10.804 90.336 11.941 91.944 ;
     RECT  11.941 5.904 11.977 5.928 ;
     RECT  10.804 11.184 11.977 12.504 ;
     RECT  11.941 23.328 11.977 24.696 ;
     RECT  11.905 28.176 11.977 28.2 ;
     RECT  10.829 41.664 11.977 41.688 ;
     RECT  11.941 71.184 11.977 71.208 ;
     RECT  11.123 47.328 11.981 49.272 ;
     RECT  10.804 56.016 11.989 57.384 ;
     RECT  10.804 58.56 11.989 58.584 ;
     RECT  11.941 89.28 12.013 91.944 ;
     RECT  11.261 94.08 12.013 94.104 ;
     RECT  10.804 95.424 12.013 95.448 ;
     RECT  10.804 105.936 12.017 108.744 ;
     RECT  11.989 58.56 12.035 58.968 ;
     RECT  12.013 17.472 12.044 17.496 ;
     RECT  10.804 18.72 12.044 18.744 ;
     RECT  11.009 30.336 12.044 30.936 ;
     RECT  10.804 43.584 12.044 44.088 ;
     RECT  10.804 63.504 12.044 63.528 ;
     RECT  12.013 94.08 12.044 95.448 ;
     RECT  12.044 17.472 12.049 18.744 ;
     RECT  10.901 19.824 12.049 19.848 ;
     RECT  10.804 21.12 12.049 21.528 ;
     RECT  11.977 22.848 12.049 24.696 ;
     RECT  11.977 41.664 12.049 41.784 ;
     RECT  12.044 43.584 12.049 44.568 ;
     RECT  12.044 63.504 12.049 63.624 ;
     RECT  11.977 64.944 12.049 65.736 ;
     RECT  11.977 71.088 12.049 71.208 ;
     RECT  10.804 72.192 12.049 72.216 ;
     RECT  11.941 87.36 12.049 87.384 ;
     RECT  12.013 89.28 12.049 92.184 ;
     RECT  10.804 51.744 12.083 52.008 ;
     RECT  12.044 84.144 12.085 84.168 ;
     RECT  10.901 85.152 12.085 85.176 ;
     RECT  12.044 94.08 12.085 96.312 ;
     RECT  10.804 97.392 12.085 98.136 ;
     RECT  12.044 29.616 12.121 30.936 ;
     RECT  10.804 32.016 12.121 32.04 ;
     RECT  12.049 89.28 12.124 93.048 ;
     RECT  11.989 56.016 12.125 57.576 ;
     RECT  12.121 29.616 12.131 32.04 ;
     RECT  12.049 41.664 12.133 45.768 ;
     RECT  11.977 5.904 12.157 6.072 ;
     RECT  12.049 17.472 12.161 19.848 ;
     RECT  11.981 47.328 12.161 47.88 ;
     RECT  12.085 84.144 12.179 85.176 ;
     RECT  12.157 5.904 12.265 6.36 ;
     RECT  12.133 43.584 12.265 45.768 ;
     RECT  10.804 53.232 12.265 53.256 ;
     RECT  12.037 54.336 12.265 54.36 ;
     RECT  12.229 76.752 12.265 76.776 ;
     RECT  12.049 87.36 12.265 88.2 ;
     RECT  12.124 89.28 12.265 89.496 ;
     RECT  12.017 108.432 12.265 108.744 ;
     RECT  12.017 105.936 12.301 107.112 ;
     RECT  12.125 56.016 12.332 57.48 ;
     RECT  12.265 43.584 12.421 46.152 ;
     RECT  12.161 47.328 12.421 47.688 ;
     RECT  10.804 36.24 12.481 36.264 ;
     RECT  10.804 37.44 12.481 37.464 ;
     RECT  12.049 63.504 12.481 65.736 ;
     RECT  10.865 82.944 12.481 83.064 ;
     RECT  11.123 50.352 12.553 50.568 ;
     RECT  12.083 51.744 12.553 51.768 ;
     RECT  12.265 5.856 12.661 6.36 ;
     RECT  10.865 26.016 12.661 26.568 ;
     RECT  12.133 41.664 12.661 42.6 ;
     RECT  12.265 53.232 12.661 54.36 ;
     RECT  12.332 55.968 12.661 57.48 ;
     RECT  12.265 76.752 12.661 76.872 ;
     RECT  10.804 77.904 12.661 77.928 ;
     RECT  11.905 80.544 12.661 81.192 ;
     RECT  12.481 82.944 12.661 83.64 ;
     RECT  10.804 99.504 12.661 100.056 ;
     RECT  12.301 105.648 12.661 107.112 ;
     RECT  12.661 99.504 12.697 100.392 ;
     RECT  10.804 102.192 12.697 102.216 ;
     RECT  12.661 5.76 12.733 6.36 ;
     RECT  10.804 7.728 12.733 7.752 ;
     RECT  11.009 15.792 12.733 15.816 ;
     RECT  12.161 17.472 12.733 18.12 ;
     RECT  10.901 103.536 12.733 104.088 ;
     RECT  12.661 105.264 12.733 107.112 ;
     RECT  12.049 21.12 12.764 24.696 ;
     RECT  12.661 25.872 12.764 26.568 ;
     RECT  12.035 58.944 12.769 58.968 ;
     RECT  12.131 30.336 12.805 32.04 ;
     RECT  11.977 10.656 12.841 12.504 ;
     RECT  11.977 28.176 12.841 28.248 ;
     RECT  12.049 71.088 12.841 72.216 ;
     RECT  12.133 73.248 12.841 73.272 ;
     RECT  12.085 86.208 12.841 86.232 ;
     RECT  12.265 87.36 12.841 89.496 ;
     RECT  12.124 90.624 12.841 93.048 ;
     RECT  12.085 94.08 12.841 98.136 ;
     RECT  12.697 99.504 12.841 102.216 ;
     RECT  11.981 49.248 12.913 49.272 ;
     RECT  12.553 50.352 12.913 51.768 ;
     RECT  12.481 62.784 12.977 65.736 ;
     RECT  12.769 58.944 12.997 59.784 ;
     RECT  12.841 71.088 13.013 73.272 ;
     RECT  12.913 49.248 13.021 51.768 ;
     RECT  12.977 62.784 13.045 66.168 ;
     RECT  12.733 5.76 13.093 7.752 ;
     RECT  13.093 5.088 13.208 7.752 ;
     RECT  10.804 9.072 13.208 9.528 ;
     RECT  12.841 10.656 13.208 13.176 ;
     RECT  10.804 14.496 13.208 14.52 ;
     RECT  12.733 15.792 13.208 18.12 ;
     RECT  12.161 19.296 13.208 19.848 ;
     RECT  12.764 21.12 13.208 26.568 ;
     RECT  12.841 28.176 13.208 28.392 ;
     RECT  12.805 30.336 13.208 32.76 ;
     RECT  12.805 35.232 13.208 35.256 ;
     RECT  12.481 36.24 13.208 37.464 ;
     RECT  11.977 40.368 13.208 40.392 ;
     RECT  12.661 41.616 13.208 42.6 ;
     RECT  12.421 43.584 13.208 47.688 ;
     RECT  13.021 48.96 13.208 51.768 ;
     RECT  12.661 53.232 13.208 57.48 ;
     RECT  12.997 58.56 13.208 59.784 ;
     RECT  13.045 62.784 13.208 66.36 ;
     RECT  10.804 67.344 13.208 67.56 ;
     RECT  12.877 68.736 13.208 68.76 ;
     RECT  13.013 71.088 13.208 74.136 ;
     RECT  10.804 75.168 13.208 75.192 ;
     RECT  12.661 76.656 13.208 76.872 ;
     RECT  12.661 77.904 13.208 78.792 ;
     RECT  12.661 80.544 13.208 83.64 ;
     RECT  12.179 85.152 13.208 85.176 ;
     RECT  12.841 86.208 13.208 89.496 ;
     RECT  12.841 90.624 13.208 102.216 ;
     RECT  12.733 103.536 13.208 107.112 ;
     RECT  12.265 108.432 13.208 108.792 ;
     RECT  13.208 2.148 13.312 112.332 ;
     RECT  13.312 2.418 13.504 112.062 ;
     RECT  13.504 50.352 13.529 50.568 ;
     RECT  13.504 10.656 13.565 13.176 ;
     RECT  13.504 37.44 13.565 37.464 ;
     RECT  13.504 94.08 13.565 98.136 ;
     RECT  13.565 10.656 13.601 12.504 ;
     RECT  13.504 23.328 13.637 24.168 ;
     RECT  13.504 59.76 13.637 65.736 ;
     RECT  13.565 94.896 13.708 98.136 ;
     RECT  13.504 101.136 13.708 109.464 ;
     RECT  13.504 14.496 13.715 22.296 ;
     RECT  13.504 90.48 13.715 92.424 ;
     RECT  13.715 19.296 13.745 22.296 ;
     RECT  13.504 28.176 13.745 28.248 ;
     RECT  13.504 45.168 13.745 47.688 ;
     RECT  13.745 19.776 13.756 22.296 ;
     RECT  13.504 30.672 13.763 32.76 ;
     RECT  13.504 51.6 13.763 51.816 ;
     RECT  13.504 77.568 13.763 83.64 ;
     RECT  13.715 14.496 13.781 17.496 ;
     RECT  13.708 101.376 13.781 109.464 ;
     RECT  13.504 34.08 13.811 35.928 ;
     RECT  13.756 21.12 13.817 22.296 ;
     RECT  13.715 90.48 13.852 92.328 ;
     RECT  13.504 40.368 13.853 42.6 ;
     RECT  13.852 90.576 13.861 92.328 ;
     RECT  13.781 101.376 13.925 108.216 ;
     RECT  13.811 34.08 14.243 35.352 ;
     RECT  13.504 48.96 14.285 48.984 ;
     RECT  13.763 80.928 14.473 83.64 ;
     RECT  14.243 34.08 14.483 35.304 ;
     RECT  13.504 75.168 14.497 75.192 ;
     RECT  13.745 45.168 14.573 45.192 ;
     RECT  13.504 56.016 14.609 58.104 ;
     RECT  13.708 94.896 14.677 96.072 ;
     RECT  13.708 97.056 14.677 98.136 ;
     RECT  13.637 60 14.681 65.736 ;
     RECT  14.681 62.304 14.717 65.736 ;
     RECT  14.473 81.024 14.717 83.64 ;
     RECT  13.529 50.544 14.725 50.568 ;
     RECT  13.504 71.184 14.753 73.416 ;
     RECT  14.497 74.688 14.753 75.192 ;
     RECT  13.763 51.744 14.785 51.816 ;
     RECT  14.483 34.08 14.789 35.16 ;
     RECT  13.861 91.056 14.819 92.328 ;
     RECT  13.504 26.016 14.821 26.664 ;
     RECT  13.763 32.016 14.821 32.76 ;
     RECT  14.789 34.08 14.821 34.296 ;
     RECT  13.504 43.68 14.821 43.704 ;
     RECT  14.785 51.744 14.821 52.104 ;
     RECT  14.753 71.184 14.821 73.032 ;
     RECT  13.763 77.568 14.821 79.272 ;
     RECT  13.504 85.248 14.821 88.2 ;
     RECT  14.821 32.016 14.825 34.296 ;
     RECT  14.717 62.784 14.825 65.736 ;
     RECT  13.756 19.776 14.857 19.944 ;
     RECT  13.763 30.672 14.857 30.84 ;
     RECT  14.725 50.544 14.857 50.616 ;
     RECT  13.601 11.184 14.861 12.504 ;
     RECT  14.857 19.056 14.861 19.944 ;
     RECT  13.504 38.832 14.893 38.856 ;
     RECT  14.821 36.624 14.929 36.648 ;
     RECT  13.504 99.504 14.929 100.056 ;
     RECT  13.925 101.376 14.929 104.904 ;
     RECT  14.821 25.824 14.933 26.664 ;
     RECT  14.893 38.832 15.013 39.24 ;
     RECT  13.504 6.288 15.02 6.312 ;
     RECT  13.504 7.344 15.02 7.368 ;
     RECT  15.02 6.288 15.061 7.368 ;
     RECT  13.504 8.592 15.061 9.528 ;
     RECT  14.893 24.624 15.109 24.648 ;
     RECT  14.933 25.824 15.109 26.616 ;
     RECT  14.821 43.68 15.164 43.848 ;
     RECT  14.857 50.544 15.205 50.664 ;
     RECT  14.821 51.648 15.205 52.104 ;
     RECT  14.825 65.376 15.205 65.736 ;
     RECT  13.504 67.344 15.205 70.008 ;
     RECT  14.821 71.136 15.205 73.032 ;
     RECT  14.821 85.152 15.217 88.2 ;
     RECT  13.504 89.28 15.217 89.496 ;
     RECT  15.061 6.288 15.253 9.528 ;
     RECT  14.861 11.184 15.253 12.36 ;
     RECT  14.821 77.568 15.26 79.32 ;
     RECT  14.681 60 15.289 61.32 ;
     RECT  15.217 85.152 15.301 89.496 ;
     RECT  13.853 41.184 15.325 42.6 ;
     RECT  15.164 43.68 15.325 44.712 ;
     RECT  15.301 85.152 15.325 89.88 ;
     RECT  14.819 91.056 15.325 92.28 ;
     RECT  13.781 109.44 15.349 109.464 ;
     RECT  15.289 110.592 15.349 110.616 ;
     RECT  13.817 21.12 15.361 21.528 ;
     RECT  14.677 94.896 15.361 98.136 ;
     RECT  14.929 36.624 15.397 37.224 ;
     RECT  15.013 38.832 15.397 39.912 ;
     RECT  15.26 77.568 15.397 79.464 ;
     RECT  15.325 29.616 15.433 29.64 ;
     RECT  14.857 30.672 15.433 30.936 ;
     RECT  14.609 56.016 15.469 58.056 ;
     RECT  15.361 21.12 15.541 21.768 ;
     RECT  13.745 46.32 15.649 47.688 ;
     RECT  15.205 50.544 15.649 52.104 ;
     RECT  15.613 53.52 15.685 53.544 ;
     RECT  15.685 53.52 15.721 54.216 ;
     RECT  15.289 59.232 15.721 61.32 ;
     RECT  15.397 36.624 15.829 39.912 ;
     RECT  15.253 49.008 15.829 49.032 ;
     RECT  15.253 6.288 15.865 12.36 ;
     RECT  13.637 23.328 15.865 23.352 ;
     RECT  15.829 36.24 15.865 39.912 ;
     RECT  15.829 49.008 15.865 49.512 ;
     RECT  15.649 50.544 15.865 52.2 ;
     RECT  15.205 67.344 15.865 73.032 ;
     RECT  15.397 77.376 15.865 79.464 ;
     RECT  14.717 82.944 15.865 83.64 ;
     RECT  15.757 93.552 15.865 93.576 ;
     RECT  15.865 93.552 15.901 93.816 ;
     RECT  15.361 94.848 15.901 98.136 ;
     RECT  15.865 5.568 15.908 12.36 ;
     RECT  13.781 14.496 15.908 17.448 ;
     RECT  14.861 19.056 15.908 19.848 ;
     RECT  15.541 20.976 15.908 21.768 ;
     RECT  15.865 22.752 15.908 23.352 ;
     RECT  15.109 24.624 15.908 26.616 ;
     RECT  13.745 28.224 15.908 28.248 ;
     RECT  15.433 29.616 15.908 30.936 ;
     RECT  14.825 32.016 15.908 34.2 ;
     RECT  15.865 36.096 15.908 39.912 ;
     RECT  15.325 41.184 15.908 44.712 ;
     RECT  15.649 45.696 15.908 47.688 ;
     RECT  15.865 49.008 15.908 52.2 ;
     RECT  15.721 53.52 15.908 54.984 ;
     RECT  15.469 55.968 15.908 58.056 ;
     RECT  15.721 59.232 15.908 61.656 ;
     RECT  14.825 62.784 15.908 64.392 ;
     RECT  15.205 65.376 15.908 66.12 ;
     RECT  15.865 67.344 15.908 73.608 ;
     RECT  14.753 75.168 15.908 75.192 ;
     RECT  15.865 76.848 15.908 79.464 ;
     RECT  14.717 81.024 15.908 81.192 ;
     RECT  15.865 82.944 15.908 83.784 ;
     RECT  15.325 85.152 15.908 92.28 ;
     RECT  15.901 93.552 15.908 98.136 ;
     RECT  14.929 99.504 15.908 104.904 ;
     RECT  13.925 106.272 15.908 108.216 ;
     RECT  15.349 109.44 15.908 110.616 ;
     RECT  15.908 2.148 16.012 112.332 ;
     RECT  16.012 2.418 16.204 112.062 ;
     RECT  16.204 5.328 16.229 17.4 ;
     RECT  16.204 32.016 16.265 34.2 ;
     RECT  16.204 96.816 16.265 109.896 ;
     RECT  16.204 55.968 16.301 57.672 ;
     RECT  16.204 71.424 16.301 75.192 ;
     RECT  16.204 76.368 16.301 78.648 ;
     RECT  16.265 34.08 16.337 34.2 ;
     RECT  16.204 84.816 16.337 92.184 ;
     RECT  16.265 96.816 16.337 107.784 ;
     RECT  16.204 41.472 16.373 47.688 ;
     RECT  16.204 49.488 16.373 54.984 ;
     RECT  16.373 41.664 16.409 47.688 ;
     RECT  16.204 24.528 16.445 30.936 ;
     RECT  16.204 35.76 16.445 40.152 ;
     RECT  16.204 58.704 16.445 62.808 ;
     RECT  16.301 71.424 16.517 73.608 ;
     RECT  16.445 25.824 16.553 30.936 ;
     RECT  16.445 62.064 16.589 62.808 ;
     RECT  16.204 22.752 16.661 23.352 ;
     RECT  16.553 25.824 16.661 26.568 ;
     RECT  16.409 45.6 16.661 47.688 ;
     RECT  16.301 74.592 16.661 75.192 ;
     RECT  16.445 35.76 16.697 38.76 ;
     RECT  16.204 64.32 16.697 64.344 ;
     RECT  16.337 86.496 16.697 92.184 ;
     RECT  16.229 5.328 16.739 16.968 ;
     RECT  16.409 41.664 16.769 44.616 ;
     RECT  16.661 47.088 16.769 47.688 ;
     RECT  16.373 49.488 16.841 51.912 ;
     RECT  16.337 96.864 16.877 107.784 ;
     RECT  16.739 5.328 16.931 12.504 ;
     RECT  16.204 18.48 16.931 21.768 ;
     RECT  16.445 40.128 16.931 40.152 ;
     RECT  16.517 71.424 16.931 72.312 ;
     RECT  16.697 38.64 16.957 38.76 ;
     RECT  16.841 51.36 16.977 51.912 ;
     RECT  16.204 65.328 17.129 68.808 ;
     RECT  16.769 47.088 17.201 47.112 ;
     RECT  16.661 23.184 17.233 23.352 ;
     RECT  16.445 24.528 17.233 24.648 ;
     RECT  16.265 32.016 17.233 32.856 ;
     RECT  16.337 34.08 17.233 34.104 ;
     RECT  16.373 52.944 17.233 54.984 ;
     RECT  16.931 18.48 17.237 20.328 ;
     RECT  17.233 23.184 17.237 24.648 ;
     RECT  16.769 41.664 17.237 41.784 ;
     RECT  16.841 49.488 17.269 50.28 ;
     RECT  16.204 79.872 17.269 81.192 ;
     RECT  16.301 56.592 17.341 57.672 ;
     RECT  16.445 58.704 17.341 60.84 ;
     RECT  16.204 70.128 17.341 70.152 ;
     RECT  16.337 84.816 17.341 85.176 ;
     RECT  16.265 108.816 17.365 109.896 ;
     RECT  16.204 93.312 17.413 95.448 ;
     RECT  17.365 108.816 17.42 110.088 ;
     RECT  16.931 21.6 17.449 21.768 ;
     RECT  16.769 43.104 17.449 44.616 ;
     RECT  16.661 45.6 17.449 45.864 ;
     RECT  16.877 99.696 17.449 107.784 ;
     RECT  17.42 108.816 17.449 110.568 ;
     RECT  17.449 99.696 17.461 110.568 ;
     RECT  17.269 48.912 17.485 50.28 ;
     RECT  16.204 82.704 17.521 83.784 ;
     RECT  17.341 84.816 17.521 85.464 ;
     RECT  17.341 56.592 17.557 60.84 ;
     RECT  16.589 62.064 17.557 62.664 ;
     RECT  16.517 73.392 17.557 73.608 ;
     RECT  16.661 74.592 17.557 74.904 ;
     RECT  17.521 82.704 17.557 85.464 ;
     RECT  16.877 96.864 17.557 98.52 ;
     RECT  17.129 65.328 17.561 67.416 ;
     RECT  17.269 79.728 17.561 81.192 ;
     RECT  16.931 5.328 17.593 9.96 ;
     RECT  17.593 4.56 17.605 9.96 ;
     RECT  17.233 52.944 17.629 55.08 ;
     RECT  16.553 27.84 17.633 30.936 ;
     RECT  17.561 65.328 17.633 66.312 ;
     RECT  17.557 82.56 17.633 85.464 ;
     RECT  17.413 92.592 17.633 95.448 ;
     RECT  17.633 84.576 17.665 85.464 ;
     RECT  16.697 86.496 17.665 91.08 ;
     RECT  17.633 27.888 17.701 30.936 ;
     RECT  17.233 32.016 17.701 34.104 ;
     RECT  16.301 76.368 17.809 78.456 ;
     RECT  17.485 48.288 17.917 50.28 ;
     RECT  16.661 25.824 18.025 26.52 ;
     RECT  17.557 96.48 18.025 98.52 ;
     RECT  17.461 99.696 18.025 111.336 ;
     RECT  17.449 21.6 18.097 22.2 ;
     RECT  17.237 23.184 18.097 24.552 ;
     RECT  16.931 11.184 18.181 12.504 ;
     RECT  16.739 13.68 18.181 16.968 ;
     RECT  17.557 73.392 18.205 74.904 ;
     RECT  17.809 76.368 18.205 78.552 ;
     RECT  18.181 11.184 18.241 16.968 ;
     RECT  17.237 18.48 18.241 18.888 ;
     RECT  17.237 20.304 18.241 20.328 ;
     RECT  16.931 72.048 18.241 72.312 ;
     RECT  17.605 3.84 18.277 9.96 ;
     RECT  18.241 11.184 18.277 17.112 ;
     RECT  17.561 67.392 18.469 67.416 ;
     RECT  17.129 68.4 18.469 68.808 ;
     RECT  18.097 21.6 18.529 24.552 ;
     RECT  18.025 25.824 18.529 26.712 ;
     RECT  18.277 3.84 18.608 17.112 ;
     RECT  18.241 18.48 18.608 20.328 ;
     RECT  18.529 21.6 18.608 26.712 ;
     RECT  17.701 27.888 18.608 34.104 ;
     RECT  16.697 35.76 18.608 37.656 ;
     RECT  16.957 38.64 18.608 38.664 ;
     RECT  17.449 40.512 18.608 40.536 ;
     RECT  17.237 41.712 18.608 41.784 ;
     RECT  17.449 43.104 18.608 45.864 ;
     RECT  17.917 47.664 18.608 50.28 ;
     RECT  16.977 51.36 18.608 51.816 ;
     RECT  17.629 52.944 18.608 55.176 ;
     RECT  17.557 56.592 18.608 64.056 ;
     RECT  17.633 65.712 18.608 66.312 ;
     RECT  18.469 67.392 18.608 68.808 ;
     RECT  17.341 70.128 18.608 70.632 ;
     RECT  18.241 71.616 18.608 72.312 ;
     RECT  18.205 73.392 18.608 78.552 ;
     RECT  17.561 79.728 18.608 80.856 ;
     RECT  17.633 82.56 18.608 83.496 ;
     RECT  17.665 84.576 18.608 91.08 ;
     RECT  17.633 92.688 18.608 95.448 ;
     RECT  18.025 96.48 18.608 111.336 ;
     RECT  18.608 2.148 18.712 112.332 ;
     RECT  18.712 2.418 18.904 112.062 ;
     RECT  18.904 93.84 18.929 111.432 ;
     RECT  18.904 43.104 18.965 44.232 ;
     RECT  18.904 53.808 18.965 63.528 ;
     RECT  18.904 67.248 18.965 68.424 ;
     RECT  18.904 70.56 18.965 72.264 ;
     RECT  18.904 92.688 18.965 92.712 ;
     RECT  18.904 3.168 19.139 20.904 ;
     RECT  19.139 3.408 19.283 20.904 ;
     RECT  18.929 93.888 19.331 111.432 ;
     RECT  19.331 111.408 19.379 111.432 ;
     RECT  18.904 22.32 19.897 26.088 ;
     RECT  18.965 60.816 19.897 63.528 ;
     RECT  18.904 82.704 19.897 91.032 ;
     RECT  19.283 4.32 19.933 20.904 ;
     RECT  19.897 21.984 19.933 26.088 ;
     RECT  18.904 27.072 19.933 29.64 ;
     RECT  18.904 39.12 19.933 39.144 ;
     RECT  18.904 41.664 19.933 41.688 ;
     RECT  18.965 43.584 19.933 44.232 ;
     RECT  18.904 47.232 19.933 47.736 ;
     RECT  18.904 51.312 19.933 52.68 ;
     RECT  18.965 54.144 19.933 58.968 ;
     RECT  19.897 60.816 19.933 63.72 ;
     RECT  18.904 65.712 19.933 65.736 ;
     RECT  18.965 67.248 19.933 68.28 ;
     RECT  18.965 70.656 19.933 72.264 ;
     RECT  18.904 73.296 19.933 73.416 ;
     RECT  18.904 75.552 19.933 75.576 ;
     RECT  18.904 77.616 19.933 77.64 ;
     RECT  18.904 78.96 19.933 79.752 ;
     RECT  18.904 80.976 19.933 81.528 ;
     RECT  19.897 82.512 19.933 91.032 ;
     RECT  19.331 93.888 19.933 110.184 ;
     RECT  19.933 4.32 19.969 92.04 ;
     RECT  19.933 93.36 19.969 110.184 ;
     RECT  19.969 4.32 21.42 110.184 ;
     RECT  21.42 17.088 21.485 17.112 ;
    LAYER M5 ;
     RECT  10.8 0.144 10.824 0.227 ;
     RECT  2.4 2.137 2.52 2.151 ;
     RECT  5.1 2.137 5.22 2.151 ;
     RECT  7.8 2.137 7.92 2.151 ;
     RECT  10.5 2.137 10.62 2.151 ;
     RECT  13.2 2.137 13.32 2.151 ;
     RECT  15.9 2.137 16.02 2.151 ;
     RECT  18.6 2.137 18.72 2.151 ;
     RECT  18.6 2.151 18.912 3.157 ;
     RECT  18.6 3.157 19.128 3.397 ;
     RECT  18.6 3.397 19.272 3.829 ;
     RECT  17.616 3.829 19.272 4.595 ;
     RECT  18.6 4.595 19.272 5.027 ;
     RECT  13.2 2.151 13.512 5.077 ;
     RECT  15.9 2.151 16.212 6.853 ;
     RECT  18.6 5.027 18.912 7.189 ;
     RECT  15.072 6.853 16.212 7.861 ;
     RECT  15.072 7.861 17.112 8.003 ;
     RECT  18.6 7.189 19.128 8.099 ;
     RECT  15.9 8.003 17.112 8.579 ;
     RECT  18.6 8.099 19.08 8.723 ;
     RECT  15.9 8.579 16.212 9.541 ;
     RECT  18.6 8.723 19.032 9.925 ;
     RECT  18.6 9.925 19.128 10.069 ;
     RECT  18.48 10.069 19.128 10.355 ;
     RECT  18.48 10.355 18.912 10.405 ;
     RECT  15.9 9.541 16.92 10.883 ;
     RECT  15.9 10.883 16.212 11.941 ;
     RECT  18.336 10.405 18.912 11.941 ;
     RECT  18.192 11.941 18.912 12.805 ;
     RECT  15.072 11.941 16.212 13.045 ;
     RECT  18.192 12.805 19.128 13.139 ;
     RECT  18.48 13.139 19.128 13.331 ;
     RECT  15.072 13.045 16.728 13.715 ;
     RECT  18.48 13.331 18.912 14.291 ;
     RECT  18.6 14.291 18.912 14.485 ;
     RECT  18.6 14.485 19.368 14.963 ;
     RECT  15.072 13.715 16.212 15.877 ;
     RECT  15.024 15.877 16.212 16.307 ;
     RECT  18.6 14.963 18.912 17.221 ;
     RECT  15.072 16.307 16.212 17.413 ;
     RECT  14.832 17.413 16.212 17.459 ;
     RECT  18.6 17.221 19.032 17.557 ;
     RECT  12.096 17.989 12.12 18.085 ;
     RECT  13.104 5.077 13.512 18.085 ;
     RECT  12.096 18.085 13.512 18.181 ;
     RECT  18.6 17.557 19.08 18.419 ;
     RECT  15.9 17.459 16.212 19.093 ;
     RECT  14.832 17.459 14.856 19.811 ;
     RECT  18.6 18.419 19.032 19.909 ;
     RECT  18.6 19.909 19.08 20.915 ;
     RECT  12.096 18.181 13.704 21.203 ;
     RECT  15.9 19.093 16.92 21.683 ;
     RECT  12.096 21.203 13.512 22.883 ;
     RECT  18.6 20.915 18.912 22.981 ;
     RECT  18.6 22.981 19.032 24.131 ;
     RECT  5.1 2.151 5.412 26.005 ;
     RECT  5.1 26.005 5.736 26.195 ;
     RECT  18.6 24.131 18.912 27.061 ;
     RECT  2.4 2.151 2.712 27.541 ;
     RECT  18.6 27.061 19.128 27.635 ;
     RECT  2.304 27.541 2.712 27.683 ;
     RECT  18.6 27.635 19.032 28.163 ;
     RECT  12.288 22.883 13.512 29.605 ;
     RECT  10.5 2.151 10.812 30.325 ;
     RECT  12.096 29.605 13.512 30.851 ;
     RECT  12.816 30.851 13.512 31.381 ;
     RECT  12.816 31.381 13.752 32.725 ;
     RECT  12.816 32.725 14.232 32.771 ;
     RECT  13.2 32.771 14.232 35.269 ;
     RECT  15.9 21.683 16.212 38.725 ;
     RECT  13.2 35.269 14.472 39.013 ;
     RECT  15.9 38.725 16.92 39.013 ;
     RECT  13.2 39.013 16.92 39.923 ;
     RECT  15.9 39.923 16.92 40.163 ;
     RECT  13.2 39.923 14.472 42.565 ;
     RECT  15.9 40.163 16.212 42.565 ;
     RECT  2.4 27.683 2.712 43.141 ;
     RECT  2.304 43.141 2.712 43.331 ;
     RECT  2.4 43.331 2.712 43.813 ;
     RECT  2.4 43.813 2.952 44.099 ;
     RECT  12.096 43.285 12.12 44.437 ;
     RECT  13.2 42.565 16.212 44.437 ;
     RECT  12.096 44.437 16.212 44.579 ;
     RECT  12.432 44.579 16.212 46.643 ;
     RECT  10.5 30.325 11.112 49.859 ;
     RECT  2.4 44.099 2.712 50.677 ;
     RECT  2.304 50.677 2.712 50.867 ;
     RECT  12.48 46.643 16.212 50.867 ;
     RECT  15.9 50.867 16.212 51.877 ;
     RECT  12.48 50.867 14.76 51.973 ;
     RECT  10.5 49.859 10.92 52.019 ;
     RECT  12.048 51.973 14.76 54.371 ;
     RECT  15.9 51.877 16.92 54.371 ;
     RECT  18.6 28.163 18.912 54.853 ;
     RECT  18.6 54.853 19.032 55.715 ;
     RECT  12.48 54.371 14.76 55.957 ;
     RECT  12.384 55.957 14.76 56.867 ;
     RECT  12.384 56.867 14.712 57.541 ;
     RECT  12 57.541 14.712 58.021 ;
     RECT  15.9 54.371 16.212 58.021 ;
     RECT  12 58.021 16.212 58.979 ;
     RECT  12.384 58.979 16.212 61.331 ;
     RECT  21.312 62.677 21.336 62.819 ;
     RECT  12.384 61.331 14.712 62.821 ;
     RECT  15.9 61.331 16.212 62.821 ;
     RECT  2.4 50.867 2.712 63.061 ;
     RECT  12.384 62.821 16.212 63.589 ;
     RECT  2.304 63.061 2.712 63.731 ;
     RECT  2.4 63.731 2.712 65.893 ;
     RECT  2.304 65.893 2.712 66.035 ;
     RECT  18.6 55.715 18.912 67.573 ;
     RECT  18.48 67.573 18.912 68.675 ;
     RECT  12.096 63.589 16.212 70.117 ;
     RECT  12.096 70.117 16.92 71.459 ;
     RECT  12.096 71.459 16.212 74.147 ;
     RECT  2.4 66.035 2.712 75.061 ;
     RECT  2.304 75.061 2.712 75.971 ;
     RECT  13.2 74.147 16.212 80.963 ;
     RECT  15.072 80.963 16.212 81.059 ;
     RECT  18.6 68.675 18.912 84.037 ;
     RECT  12.096 74.147 12.168 84.563 ;
     RECT  18.6 84.037 19.032 84.611 ;
     RECT  18.6 84.611 18.912 85.669 ;
     RECT  15.36 81.059 16.212 86.005 ;
     RECT  18.48 85.669 18.912 86.005 ;
     RECT  18.48 86.005 19.08 86.339 ;
     RECT  15.312 86.005 16.212 86.675 ;
     RECT  18.6 86.339 19.08 87.539 ;
     RECT  12.096 84.563 12.12 88.069 ;
     RECT  13.2 80.963 13.512 88.069 ;
     RECT  12.096 88.069 13.512 88.115 ;
     RECT  12.384 88.115 13.512 88.165 ;
     RECT  15.36 86.675 16.212 88.741 ;
     RECT  2.4 75.971 2.712 89.269 ;
     RECT  2.304 89.269 2.712 89.459 ;
     RECT  18.6 87.539 18.912 89.461 ;
     RECT  18.6 89.461 19.032 90.035 ;
     RECT  12.384 88.165 13.8 90.037 ;
     RECT  12.048 90.037 13.8 90.565 ;
     RECT  12.048 90.565 13.848 90.659 ;
     RECT  12.384 90.659 13.848 91.669 ;
     RECT  15.312 88.741 16.212 91.907 ;
     RECT  12.288 91.669 13.848 92.293 ;
     RECT  12.288 92.293 14.808 92.339 ;
     RECT  12.288 92.339 13.704 92.435 ;
     RECT  12.288 92.435 13.512 92.963 ;
     RECT  2.4 89.459 2.712 93.589 ;
     RECT  2.304 93.589 2.712 93.779 ;
     RECT  15.9 91.907 16.212 93.781 ;
     RECT  15.9 93.781 16.92 93.829 ;
     RECT  18.6 90.035 18.912 93.829 ;
     RECT  15.9 93.829 18.912 94.021 ;
     RECT  15.9 94.021 19.032 94.595 ;
     RECT  15.9 94.595 18.912 94.691 ;
     RECT  14.784 92.339 14.808 95.125 ;
     RECT  15.9 94.691 16.92 95.125 ;
     RECT  14.784 95.125 16.92 95.219 ;
     RECT  18.6 94.691 18.912 95.893 ;
     RECT  12.384 92.963 13.512 96.277 ;
     RECT  14.784 95.219 16.212 96.323 ;
     RECT  12.096 96.277 13.512 96.419 ;
     RECT  18.6 95.893 19.128 96.467 ;
     RECT  18.6 96.467 19.032 96.805 ;
     RECT  15.9 96.323 16.212 96.853 ;
     RECT  15.9 96.853 17.112 96.995 ;
     RECT  13.2 96.419 13.512 96.997 ;
     RECT  12.096 96.419 12.12 97.043 ;
     RECT  18.48 96.805 19.032 97.139 ;
     RECT  0.24 96.853 0.264 97.235 ;
     RECT  2.4 93.779 2.712 97.381 ;
     RECT  14.784 96.323 14.808 97.429 ;
     RECT  15.9 96.995 17.016 97.429 ;
     RECT  14.784 97.429 17.016 97.523 ;
     RECT  2.4 97.381 3.576 97.571 ;
     RECT  18.48 97.139 18.912 97.813 ;
     RECT  18.192 97.813 18.912 98.675 ;
     RECT  18.6 98.675 18.912 99.493 ;
     RECT  14.784 97.523 16.212 99.685 ;
     RECT  14.784 99.685 16.536 100.355 ;
     RECT  18.6 99.493 19.128 100.789 ;
     RECT  18.6 100.789 19.176 101.555 ;
     RECT  18.6 101.555 18.912 102.373 ;
     RECT  14.784 100.355 16.212 102.707 ;
     RECT  14.784 102.707 14.808 103.811 ;
     RECT  18.48 102.373 18.912 103.811 ;
     RECT  18.6 103.811 18.912 104.389 ;
     RECT  15.9 102.707 16.212 104.821 ;
     RECT  18.6 104.389 19.032 104.917 ;
     RECT  15.9 104.821 17.016 105.539 ;
     RECT  18.48 104.917 19.032 105.683 ;
     RECT  18.48 105.683 18.912 105.925 ;
     RECT  13.2 96.997 13.656 105.973 ;
     RECT  18.192 105.925 18.912 106.643 ;
     RECT  15.9 105.539 16.212 106.885 ;
     RECT  15.9 106.885 16.536 107.795 ;
     RECT  2.4 97.571 2.712 107.941 ;
     RECT  2.304 107.941 2.712 108.131 ;
     RECT  13.2 105.973 13.704 108.133 ;
     RECT  18.48 106.643 18.912 108.371 ;
     RECT  13.2 108.133 13.896 109.475 ;
     RECT  18.6 108.371 18.912 109.477 ;
     RECT  18.6 109.477 19.032 109.669 ;
     RECT  15.9 107.795 16.212 109.813 ;
     RECT  17.376 109.285 17.4 110.099 ;
     RECT  18.6 109.669 19.32 110.149 ;
     RECT  15.36 109.813 16.212 110.627 ;
     RECT  17.472 110.533 17.496 111.347 ;
     RECT  18.6 110.149 19.368 111.443 ;
     RECT  2.4 108.131 2.712 112.329 ;
     RECT  5.1 26.195 5.412 112.329 ;
     RECT  7.8 2.151 8.112 112.329 ;
     RECT  10.5 52.019 10.812 112.329 ;
     RECT  13.2 109.475 13.512 112.329 ;
     RECT  15.9 110.627 16.212 112.329 ;
     RECT  18.6 111.443 18.912 112.329 ;
     RECT  2.4 112.329 2.52 112.343 ;
     RECT  5.1 112.329 5.22 112.343 ;
     RECT  7.8 112.329 7.92 112.343 ;
     RECT  10.5 112.329 10.62 112.343 ;
     RECT  13.2 112.329 13.32 112.343 ;
     RECT  15.9 112.329 16.02 112.343 ;
     RECT  18.6 112.329 18.72 112.343 ;
  END
END hbfd_rly_624_EW_fc
END LIBRARY
